VERSION 5.8 ;
BUSBITCHARS "[]" ;
DIVIDERCHAR "/" ;
UNITS
    DATABASE MICRONS 1000 ;
END UNITS

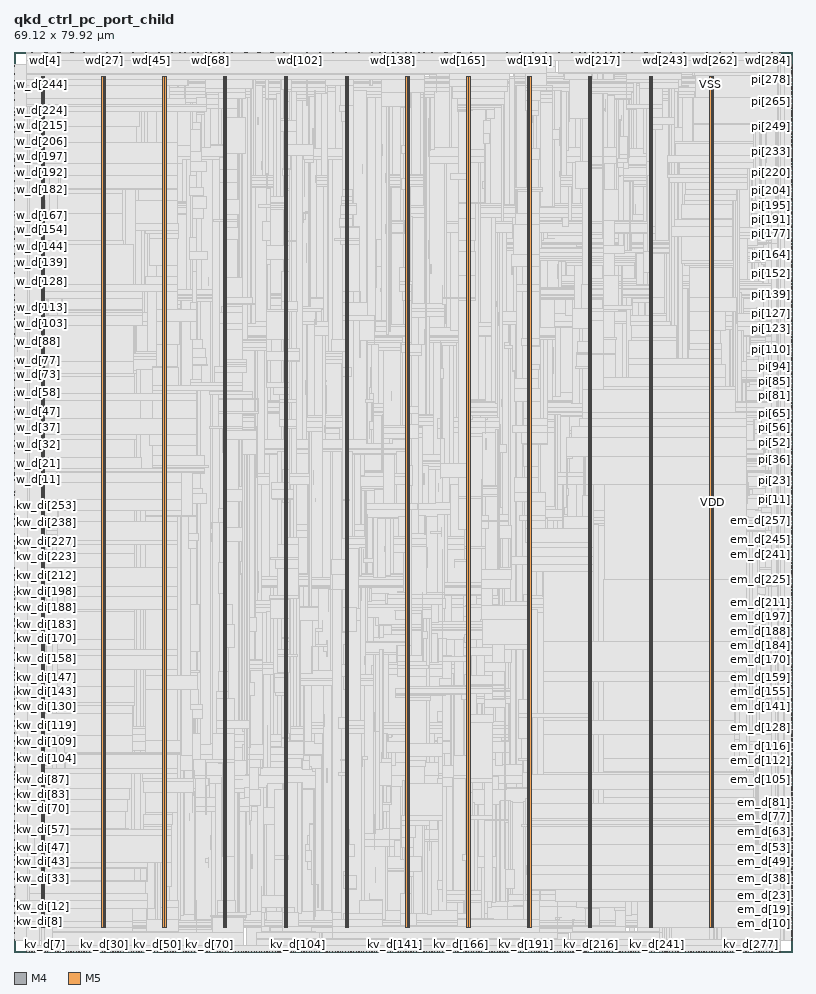
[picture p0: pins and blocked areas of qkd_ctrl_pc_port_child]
MACRO qkd_ctrl_pc_port_child
  FOREIGN qkd_ctrl_pc_port_child 0 0 ;
  CLASS BLOCK ;
  SIZE 69.12 BY 79.92 ;
  PIN col_sr_e
    DIRECTION INPUT ;
    USE SIGNAL ;
    PORT
      LAYER M4 ;
        RECT  0 1.056 0.084 1.08 ;
    END
  END col_sr_e
  PIN col_v_e
    DIRECTION INPUT ;
    USE SIGNAL ;
    PORT
      LAYER M4 ;
        RECT  0 1.2 0.084 1.224 ;
    END
  END col_v_e
  PIN col_we_e
    DIRECTION INPUT ;
    USE SIGNAL ;
    PORT
      LAYER M4 ;
        RECT  0 1.344 0.084 1.368 ;
    END
  END col_we_e
  PIN em_d[0]
    DIRECTION OUTPUT ;
    USE SIGNAL ;
    PORT
      LAYER M4 ;
        RECT  69.036 1.056 69.12 1.08 ;
    END
  END em_d[0]
  PIN em_d[100]
    DIRECTION OUTPUT ;
    USE SIGNAL ;
    PORT
      LAYER M4 ;
        RECT  69.036 15.264 69.12 15.288 ;
    END
  END em_d[100]
  PIN em_d[101]
    DIRECTION OUTPUT ;
    USE SIGNAL ;
    PORT
      LAYER M4 ;
        RECT  69.036 15.408 69.12 15.432 ;
    END
  END em_d[101]
  PIN em_d[102]
    DIRECTION OUTPUT ;
    USE SIGNAL ;
    PORT
      LAYER M4 ;
        RECT  69.036 15.552 69.12 15.576 ;
    END
  END em_d[102]
  PIN em_d[103]
    DIRECTION OUTPUT ;
    USE SIGNAL ;
    PORT
      LAYER M4 ;
        RECT  69.036 15.696 69.12 15.72 ;
    END
  END em_d[103]
  PIN em_d[104]
    DIRECTION OUTPUT ;
    USE SIGNAL ;
    PORT
      LAYER M4 ;
        RECT  69.036 15.84 69.12 15.864 ;
    END
  END em_d[104]
  PIN em_d[105]
    DIRECTION OUTPUT ;
    USE SIGNAL ;
    PORT
      LAYER M4 ;
        RECT  69.036 15.984 69.12 16.008 ;
    END
  END em_d[105]
  PIN em_d[106]
    DIRECTION OUTPUT ;
    USE SIGNAL ;
    PORT
      LAYER M4 ;
        RECT  69.036 16.128 69.12 16.152 ;
    END
  END em_d[106]
  PIN em_d[107]
    DIRECTION OUTPUT ;
    USE SIGNAL ;
    PORT
      LAYER M4 ;
        RECT  69.036 16.272 69.12 16.296 ;
    END
  END em_d[107]
  PIN em_d[108]
    DIRECTION OUTPUT ;
    USE SIGNAL ;
    PORT
      LAYER M4 ;
        RECT  69.036 16.416 69.12 16.44 ;
    END
  END em_d[108]
  PIN em_d[109]
    DIRECTION OUTPUT ;
    USE SIGNAL ;
    PORT
      LAYER M4 ;
        RECT  69.036 16.56 69.12 16.584 ;
    END
  END em_d[109]
  PIN em_d[10]
    DIRECTION OUTPUT ;
    USE SIGNAL ;
    PORT
      LAYER M4 ;
        RECT  69.036 2.496 69.12 2.52 ;
    END
  END em_d[10]
  PIN em_d[110]
    DIRECTION OUTPUT ;
    USE SIGNAL ;
    PORT
      LAYER M4 ;
        RECT  69.036 16.704 69.12 16.728 ;
    END
  END em_d[110]
  PIN em_d[111]
    DIRECTION OUTPUT ;
    USE SIGNAL ;
    PORT
      LAYER M4 ;
        RECT  69.036 16.848 69.12 16.872 ;
    END
  END em_d[111]
  PIN em_d[112]
    DIRECTION OUTPUT ;
    USE SIGNAL ;
    PORT
      LAYER M4 ;
        RECT  69.036 16.992 69.12 17.016 ;
    END
  END em_d[112]
  PIN em_d[113]
    DIRECTION OUTPUT ;
    USE SIGNAL ;
    PORT
      LAYER M4 ;
        RECT  69.036 17.136 69.12 17.16 ;
    END
  END em_d[113]
  PIN em_d[114]
    DIRECTION OUTPUT ;
    USE SIGNAL ;
    PORT
      LAYER M4 ;
        RECT  69.036 17.28 69.12 17.304 ;
    END
  END em_d[114]
  PIN em_d[115]
    DIRECTION OUTPUT ;
    USE SIGNAL ;
    PORT
      LAYER M4 ;
        RECT  69.036 17.424 69.12 17.448 ;
    END
  END em_d[115]
  PIN em_d[116]
    DIRECTION OUTPUT ;
    USE SIGNAL ;
    PORT
      LAYER M4 ;
        RECT  69.036 17.568 69.12 17.592 ;
    END
  END em_d[116]
  PIN em_d[117]
    DIRECTION OUTPUT ;
    USE SIGNAL ;
    PORT
      LAYER M4 ;
        RECT  69.036 17.712 69.12 17.736 ;
    END
  END em_d[117]
  PIN em_d[118]
    DIRECTION OUTPUT ;
    USE SIGNAL ;
    PORT
      LAYER M4 ;
        RECT  69.036 17.856 69.12 17.88 ;
    END
  END em_d[118]
  PIN em_d[119]
    DIRECTION OUTPUT ;
    USE SIGNAL ;
    PORT
      LAYER M4 ;
        RECT  69.036 18 69.12 18.024 ;
    END
  END em_d[119]
  PIN em_d[11]
    DIRECTION OUTPUT ;
    USE SIGNAL ;
    PORT
      LAYER M4 ;
        RECT  69.036 2.64 69.12 2.664 ;
    END
  END em_d[11]
  PIN em_d[120]
    DIRECTION OUTPUT ;
    USE SIGNAL ;
    PORT
      LAYER M4 ;
        RECT  69.036 18.144 69.12 18.168 ;
    END
  END em_d[120]
  PIN em_d[121]
    DIRECTION OUTPUT ;
    USE SIGNAL ;
    PORT
      LAYER M4 ;
        RECT  69.036 18.288 69.12 18.312 ;
    END
  END em_d[121]
  PIN em_d[122]
    DIRECTION OUTPUT ;
    USE SIGNAL ;
    PORT
      LAYER M4 ;
        RECT  69.036 18.384 69.12 18.408 ;
    END
  END em_d[122]
  PIN em_d[123]
    DIRECTION OUTPUT ;
    USE SIGNAL ;
    PORT
      LAYER M4 ;
        RECT  69.036 18.528 69.12 18.552 ;
    END
  END em_d[123]
  PIN em_d[124]
    DIRECTION OUTPUT ;
    USE SIGNAL ;
    PORT
      LAYER M4 ;
        RECT  69.036 18.672 69.12 18.696 ;
    END
  END em_d[124]
  PIN em_d[125]
    DIRECTION OUTPUT ;
    USE SIGNAL ;
    PORT
      LAYER M4 ;
        RECT  69.036 18.816 69.12 18.84 ;
    END
  END em_d[125]
  PIN em_d[126]
    DIRECTION OUTPUT ;
    USE SIGNAL ;
    PORT
      LAYER M4 ;
        RECT  69.036 18.96 69.12 18.984 ;
    END
  END em_d[126]
  PIN em_d[127]
    DIRECTION OUTPUT ;
    USE SIGNAL ;
    PORT
      LAYER M4 ;
        RECT  69.036 19.104 69.12 19.128 ;
    END
  END em_d[127]
  PIN em_d[128]
    DIRECTION OUTPUT ;
    USE SIGNAL ;
    PORT
      LAYER M4 ;
        RECT  69.036 19.248 69.12 19.272 ;
    END
  END em_d[128]
  PIN em_d[129]
    DIRECTION OUTPUT ;
    USE SIGNAL ;
    PORT
      LAYER M4 ;
        RECT  69.036 19.392 69.12 19.416 ;
    END
  END em_d[129]
  PIN em_d[12]
    DIRECTION OUTPUT ;
    USE SIGNAL ;
    PORT
      LAYER M4 ;
        RECT  69.036 2.784 69.12 2.808 ;
    END
  END em_d[12]
  PIN em_d[130]
    DIRECTION OUTPUT ;
    USE SIGNAL ;
    PORT
      LAYER M4 ;
        RECT  69.036 19.536 69.12 19.56 ;
    END
  END em_d[130]
  PIN em_d[131]
    DIRECTION OUTPUT ;
    USE SIGNAL ;
    PORT
      LAYER M4 ;
        RECT  69.036 19.68 69.12 19.704 ;
    END
  END em_d[131]
  PIN em_d[132]
    DIRECTION OUTPUT ;
    USE SIGNAL ;
    PORT
      LAYER M4 ;
        RECT  69.036 19.824 69.12 19.848 ;
    END
  END em_d[132]
  PIN em_d[133]
    DIRECTION OUTPUT ;
    USE SIGNAL ;
    PORT
      LAYER M4 ;
        RECT  69.036 19.968 69.12 19.992 ;
    END
  END em_d[133]
  PIN em_d[134]
    DIRECTION OUTPUT ;
    USE SIGNAL ;
    PORT
      LAYER M4 ;
        RECT  69.036 20.112 69.12 20.136 ;
    END
  END em_d[134]
  PIN em_d[135]
    DIRECTION OUTPUT ;
    USE SIGNAL ;
    PORT
      LAYER M4 ;
        RECT  69.036 20.256 69.12 20.28 ;
    END
  END em_d[135]
  PIN em_d[136]
    DIRECTION OUTPUT ;
    USE SIGNAL ;
    PORT
      LAYER M4 ;
        RECT  69.036 20.4 69.12 20.424 ;
    END
  END em_d[136]
  PIN em_d[137]
    DIRECTION OUTPUT ;
    USE SIGNAL ;
    PORT
      LAYER M4 ;
        RECT  69.036 20.544 69.12 20.568 ;
    END
  END em_d[137]
  PIN em_d[138]
    DIRECTION OUTPUT ;
    USE SIGNAL ;
    PORT
      LAYER M4 ;
        RECT  69.036 20.688 69.12 20.712 ;
    END
  END em_d[138]
  PIN em_d[139]
    DIRECTION OUTPUT ;
    USE SIGNAL ;
    PORT
      LAYER M4 ;
        RECT  69.036 20.832 69.12 20.856 ;
    END
  END em_d[139]
  PIN em_d[13]
    DIRECTION OUTPUT ;
    USE SIGNAL ;
    PORT
      LAYER M4 ;
        RECT  69.036 2.928 69.12 2.952 ;
    END
  END em_d[13]
  PIN em_d[140]
    DIRECTION OUTPUT ;
    USE SIGNAL ;
    PORT
      LAYER M4 ;
        RECT  69.036 20.976 69.12 21 ;
    END
  END em_d[140]
  PIN em_d[141]
    DIRECTION OUTPUT ;
    USE SIGNAL ;
    PORT
      LAYER M4 ;
        RECT  69.036 21.12 69.12 21.144 ;
    END
  END em_d[141]
  PIN em_d[142]
    DIRECTION OUTPUT ;
    USE SIGNAL ;
    PORT
      LAYER M4 ;
        RECT  69.036 21.264 69.12 21.288 ;
    END
  END em_d[142]
  PIN em_d[143]
    DIRECTION OUTPUT ;
    USE SIGNAL ;
    PORT
      LAYER M4 ;
        RECT  69.036 21.408 69.12 21.432 ;
    END
  END em_d[143]
  PIN em_d[144]
    DIRECTION OUTPUT ;
    USE SIGNAL ;
    PORT
      LAYER M4 ;
        RECT  69.036 21.552 69.12 21.576 ;
    END
  END em_d[144]
  PIN em_d[145]
    DIRECTION OUTPUT ;
    USE SIGNAL ;
    PORT
      LAYER M4 ;
        RECT  69.036 21.696 69.12 21.72 ;
    END
  END em_d[145]
  PIN em_d[146]
    DIRECTION OUTPUT ;
    USE SIGNAL ;
    PORT
      LAYER M4 ;
        RECT  69.036 21.84 69.12 21.864 ;
    END
  END em_d[146]
  PIN em_d[147]
    DIRECTION OUTPUT ;
    USE SIGNAL ;
    PORT
      LAYER M4 ;
        RECT  69.036 21.984 69.12 22.008 ;
    END
  END em_d[147]
  PIN em_d[148]
    DIRECTION OUTPUT ;
    USE SIGNAL ;
    PORT
      LAYER M4 ;
        RECT  69.036 22.08 69.12 22.104 ;
    END
  END em_d[148]
  PIN em_d[149]
    DIRECTION OUTPUT ;
    USE SIGNAL ;
    PORT
      LAYER M4 ;
        RECT  69.036 22.224 69.12 22.248 ;
    END
  END em_d[149]
  PIN em_d[14]
    DIRECTION OUTPUT ;
    USE SIGNAL ;
    PORT
      LAYER M4 ;
        RECT  69.036 3.072 69.12 3.096 ;
    END
  END em_d[14]
  PIN em_d[150]
    DIRECTION OUTPUT ;
    USE SIGNAL ;
    PORT
      LAYER M4 ;
        RECT  69.036 22.368 69.12 22.392 ;
    END
  END em_d[150]
  PIN em_d[151]
    DIRECTION OUTPUT ;
    USE SIGNAL ;
    PORT
      LAYER M4 ;
        RECT  69.036 22.512 69.12 22.536 ;
    END
  END em_d[151]
  PIN em_d[152]
    DIRECTION OUTPUT ;
    USE SIGNAL ;
    PORT
      LAYER M4 ;
        RECT  69.036 22.656 69.12 22.68 ;
    END
  END em_d[152]
  PIN em_d[153]
    DIRECTION OUTPUT ;
    USE SIGNAL ;
    PORT
      LAYER M4 ;
        RECT  69.036 22.8 69.12 22.824 ;
    END
  END em_d[153]
  PIN em_d[154]
    DIRECTION OUTPUT ;
    USE SIGNAL ;
    PORT
      LAYER M4 ;
        RECT  69.036 22.944 69.12 22.968 ;
    END
  END em_d[154]
  PIN em_d[155]
    DIRECTION OUTPUT ;
    USE SIGNAL ;
    PORT
      LAYER M4 ;
        RECT  69.036 23.088 69.12 23.112 ;
    END
  END em_d[155]
  PIN em_d[156]
    DIRECTION OUTPUT ;
    USE SIGNAL ;
    PORT
      LAYER M4 ;
        RECT  69.036 23.232 69.12 23.256 ;
    END
  END em_d[156]
  PIN em_d[157]
    DIRECTION OUTPUT ;
    USE SIGNAL ;
    PORT
      LAYER M4 ;
        RECT  69.036 23.376 69.12 23.4 ;
    END
  END em_d[157]
  PIN em_d[158]
    DIRECTION OUTPUT ;
    USE SIGNAL ;
    PORT
      LAYER M4 ;
        RECT  69.036 23.52 69.12 23.544 ;
    END
  END em_d[158]
  PIN em_d[159]
    DIRECTION OUTPUT ;
    USE SIGNAL ;
    PORT
      LAYER M4 ;
        RECT  69.036 23.664 69.12 23.688 ;
    END
  END em_d[159]
  PIN em_d[15]
    DIRECTION OUTPUT ;
    USE SIGNAL ;
    PORT
      LAYER M4 ;
        RECT  69.036 3.216 69.12 3.24 ;
    END
  END em_d[15]
  PIN em_d[160]
    DIRECTION OUTPUT ;
    USE SIGNAL ;
    PORT
      LAYER M4 ;
        RECT  69.036 23.808 69.12 23.832 ;
    END
  END em_d[160]
  PIN em_d[161]
    DIRECTION OUTPUT ;
    USE SIGNAL ;
    PORT
      LAYER M4 ;
        RECT  69.036 23.952 69.12 23.976 ;
    END
  END em_d[161]
  PIN em_d[162]
    DIRECTION OUTPUT ;
    USE SIGNAL ;
    PORT
      LAYER M4 ;
        RECT  69.036 24.096 69.12 24.12 ;
    END
  END em_d[162]
  PIN em_d[163]
    DIRECTION OUTPUT ;
    USE SIGNAL ;
    PORT
      LAYER M4 ;
        RECT  69.036 24.24 69.12 24.264 ;
    END
  END em_d[163]
  PIN em_d[164]
    DIRECTION OUTPUT ;
    USE SIGNAL ;
    PORT
      LAYER M4 ;
        RECT  69.036 24.384 69.12 24.408 ;
    END
  END em_d[164]
  PIN em_d[165]
    DIRECTION OUTPUT ;
    USE SIGNAL ;
    PORT
      LAYER M4 ;
        RECT  69.036 24.528 69.12 24.552 ;
    END
  END em_d[165]
  PIN em_d[166]
    DIRECTION OUTPUT ;
    USE SIGNAL ;
    PORT
      LAYER M4 ;
        RECT  69.036 24.672 69.12 24.696 ;
    END
  END em_d[166]
  PIN em_d[167]
    DIRECTION OUTPUT ;
    USE SIGNAL ;
    PORT
      LAYER M4 ;
        RECT  69.036 24.816 69.12 24.84 ;
    END
  END em_d[167]
  PIN em_d[168]
    DIRECTION OUTPUT ;
    USE SIGNAL ;
    PORT
      LAYER M4 ;
        RECT  69.036 24.96 69.12 24.984 ;
    END
  END em_d[168]
  PIN em_d[169]
    DIRECTION OUTPUT ;
    USE SIGNAL ;
    PORT
      LAYER M4 ;
        RECT  69.036 25.104 69.12 25.128 ;
    END
  END em_d[169]
  PIN em_d[16]
    DIRECTION OUTPUT ;
    USE SIGNAL ;
    PORT
      LAYER M4 ;
        RECT  69.036 3.312 69.12 3.336 ;
    END
  END em_d[16]
  PIN em_d[170]
    DIRECTION OUTPUT ;
    USE SIGNAL ;
    PORT
      LAYER M4 ;
        RECT  69.036 25.248 69.12 25.272 ;
    END
  END em_d[170]
  PIN em_d[171]
    DIRECTION OUTPUT ;
    USE SIGNAL ;
    PORT
      LAYER M4 ;
        RECT  69.036 25.392 69.12 25.416 ;
    END
  END em_d[171]
  PIN em_d[172]
    DIRECTION OUTPUT ;
    USE SIGNAL ;
    PORT
      LAYER M4 ;
        RECT  69.036 25.536 69.12 25.56 ;
    END
  END em_d[172]
  PIN em_d[173]
    DIRECTION OUTPUT ;
    USE SIGNAL ;
    PORT
      LAYER M4 ;
        RECT  69.036 25.68 69.12 25.704 ;
    END
  END em_d[173]
  PIN em_d[174]
    DIRECTION OUTPUT ;
    USE SIGNAL ;
    PORT
      LAYER M4 ;
        RECT  69.036 25.824 69.12 25.848 ;
    END
  END em_d[174]
  PIN em_d[175]
    DIRECTION OUTPUT ;
    USE SIGNAL ;
    PORT
      LAYER M4 ;
        RECT  69.036 25.92 69.12 25.944 ;
    END
  END em_d[175]
  PIN em_d[176]
    DIRECTION OUTPUT ;
    USE SIGNAL ;
    PORT
      LAYER M4 ;
        RECT  69.036 26.064 69.12 26.088 ;
    END
  END em_d[176]
  PIN em_d[177]
    DIRECTION OUTPUT ;
    USE SIGNAL ;
    PORT
      LAYER M4 ;
        RECT  69.036 26.208 69.12 26.232 ;
    END
  END em_d[177]
  PIN em_d[178]
    DIRECTION OUTPUT ;
    USE SIGNAL ;
    PORT
      LAYER M4 ;
        RECT  69.036 26.352 69.12 26.376 ;
    END
  END em_d[178]
  PIN em_d[179]
    DIRECTION OUTPUT ;
    USE SIGNAL ;
    PORT
      LAYER M4 ;
        RECT  69.036 26.496 69.12 26.52 ;
    END
  END em_d[179]
  PIN em_d[17]
    DIRECTION OUTPUT ;
    USE SIGNAL ;
    PORT
      LAYER M4 ;
        RECT  69.036 3.456 69.12 3.48 ;
    END
  END em_d[17]
  PIN em_d[180]
    DIRECTION OUTPUT ;
    USE SIGNAL ;
    PORT
      LAYER M4 ;
        RECT  69.036 26.64 69.12 26.664 ;
    END
  END em_d[180]
  PIN em_d[181]
    DIRECTION OUTPUT ;
    USE SIGNAL ;
    PORT
      LAYER M4 ;
        RECT  69.036 26.784 69.12 26.808 ;
    END
  END em_d[181]
  PIN em_d[182]
    DIRECTION OUTPUT ;
    USE SIGNAL ;
    PORT
      LAYER M4 ;
        RECT  69.036 26.928 69.12 26.952 ;
    END
  END em_d[182]
  PIN em_d[183]
    DIRECTION OUTPUT ;
    USE SIGNAL ;
    PORT
      LAYER M4 ;
        RECT  69.036 27.072 69.12 27.096 ;
    END
  END em_d[183]
  PIN em_d[184]
    DIRECTION OUTPUT ;
    USE SIGNAL ;
    PORT
      LAYER M4 ;
        RECT  69.036 27.216 69.12 27.24 ;
    END
  END em_d[184]
  PIN em_d[185]
    DIRECTION OUTPUT ;
    USE SIGNAL ;
    PORT
      LAYER M4 ;
        RECT  69.036 27.36 69.12 27.384 ;
    END
  END em_d[185]
  PIN em_d[186]
    DIRECTION OUTPUT ;
    USE SIGNAL ;
    PORT
      LAYER M4 ;
        RECT  69.036 27.504 69.12 27.528 ;
    END
  END em_d[186]
  PIN em_d[187]
    DIRECTION OUTPUT ;
    USE SIGNAL ;
    PORT
      LAYER M4 ;
        RECT  69.036 27.648 69.12 27.672 ;
    END
  END em_d[187]
  PIN em_d[188]
    DIRECTION OUTPUT ;
    USE SIGNAL ;
    PORT
      LAYER M4 ;
        RECT  69.036 27.792 69.12 27.816 ;
    END
  END em_d[188]
  PIN em_d[189]
    DIRECTION OUTPUT ;
    USE SIGNAL ;
    PORT
      LAYER M4 ;
        RECT  69.036 27.936 69.12 27.96 ;
    END
  END em_d[189]
  PIN em_d[18]
    DIRECTION OUTPUT ;
    USE SIGNAL ;
    PORT
      LAYER M4 ;
        RECT  69.036 3.6 69.12 3.624 ;
    END
  END em_d[18]
  PIN em_d[190]
    DIRECTION OUTPUT ;
    USE SIGNAL ;
    PORT
      LAYER M4 ;
        RECT  69.036 28.08 69.12 28.104 ;
    END
  END em_d[190]
  PIN em_d[191]
    DIRECTION OUTPUT ;
    USE SIGNAL ;
    PORT
      LAYER M4 ;
        RECT  69.036 28.224 69.12 28.248 ;
    END
  END em_d[191]
  PIN em_d[192]
    DIRECTION OUTPUT ;
    USE SIGNAL ;
    PORT
      LAYER M4 ;
        RECT  69.036 28.368 69.12 28.392 ;
    END
  END em_d[192]
  PIN em_d[193]
    DIRECTION OUTPUT ;
    USE SIGNAL ;
    PORT
      LAYER M4 ;
        RECT  69.036 28.512 69.12 28.536 ;
    END
  END em_d[193]
  PIN em_d[194]
    DIRECTION OUTPUT ;
    USE SIGNAL ;
    PORT
      LAYER M4 ;
        RECT  69.036 28.656 69.12 28.68 ;
    END
  END em_d[194]
  PIN em_d[195]
    DIRECTION OUTPUT ;
    USE SIGNAL ;
    PORT
      LAYER M4 ;
        RECT  69.036 28.8 69.12 28.824 ;
    END
  END em_d[195]
  PIN em_d[196]
    DIRECTION OUTPUT ;
    USE SIGNAL ;
    PORT
      LAYER M4 ;
        RECT  69.036 28.944 69.12 28.968 ;
    END
  END em_d[196]
  PIN em_d[197]
    DIRECTION OUTPUT ;
    USE SIGNAL ;
    PORT
      LAYER M4 ;
        RECT  69.036 29.088 69.12 29.112 ;
    END
  END em_d[197]
  PIN em_d[198]
    DIRECTION OUTPUT ;
    USE SIGNAL ;
    PORT
      LAYER M4 ;
        RECT  69.036 29.232 69.12 29.256 ;
    END
  END em_d[198]
  PIN em_d[199]
    DIRECTION OUTPUT ;
    USE SIGNAL ;
    PORT
      LAYER M4 ;
        RECT  69.036 29.376 69.12 29.4 ;
    END
  END em_d[199]
  PIN em_d[19]
    DIRECTION OUTPUT ;
    USE SIGNAL ;
    PORT
      LAYER M4 ;
        RECT  69.036 3.744 69.12 3.768 ;
    END
  END em_d[19]
  PIN em_d[1]
    DIRECTION OUTPUT ;
    USE SIGNAL ;
    PORT
      LAYER M4 ;
        RECT  69.036 1.2 69.12 1.224 ;
    END
  END em_d[1]
  PIN em_d[200]
    DIRECTION OUTPUT ;
    USE SIGNAL ;
    PORT
      LAYER M4 ;
        RECT  69.036 29.52 69.12 29.544 ;
    END
  END em_d[200]
  PIN em_d[201]
    DIRECTION OUTPUT ;
    USE SIGNAL ;
    PORT
      LAYER M4 ;
        RECT  69.036 29.616 69.12 29.64 ;
    END
  END em_d[201]
  PIN em_d[202]
    DIRECTION OUTPUT ;
    USE SIGNAL ;
    PORT
      LAYER M4 ;
        RECT  69.036 29.76 69.12 29.784 ;
    END
  END em_d[202]
  PIN em_d[203]
    DIRECTION OUTPUT ;
    USE SIGNAL ;
    PORT
      LAYER M4 ;
        RECT  69.036 29.904 69.12 29.928 ;
    END
  END em_d[203]
  PIN em_d[204]
    DIRECTION OUTPUT ;
    USE SIGNAL ;
    PORT
      LAYER M4 ;
        RECT  69.036 30.048 69.12 30.072 ;
    END
  END em_d[204]
  PIN em_d[205]
    DIRECTION OUTPUT ;
    USE SIGNAL ;
    PORT
      LAYER M4 ;
        RECT  69.036 30.192 69.12 30.216 ;
    END
  END em_d[205]
  PIN em_d[206]
    DIRECTION OUTPUT ;
    USE SIGNAL ;
    PORT
      LAYER M4 ;
        RECT  69.036 30.336 69.12 30.36 ;
    END
  END em_d[206]
  PIN em_d[207]
    DIRECTION OUTPUT ;
    USE SIGNAL ;
    PORT
      LAYER M4 ;
        RECT  69.036 30.48 69.12 30.504 ;
    END
  END em_d[207]
  PIN em_d[208]
    DIRECTION OUTPUT ;
    USE SIGNAL ;
    PORT
      LAYER M4 ;
        RECT  69.036 30.624 69.12 30.648 ;
    END
  END em_d[208]
  PIN em_d[209]
    DIRECTION OUTPUT ;
    USE SIGNAL ;
    PORT
      LAYER M4 ;
        RECT  69.036 30.768 69.12 30.792 ;
    END
  END em_d[209]
  PIN em_d[20]
    DIRECTION OUTPUT ;
    USE SIGNAL ;
    PORT
      LAYER M4 ;
        RECT  69.036 3.888 69.12 3.912 ;
    END
  END em_d[20]
  PIN em_d[210]
    DIRECTION OUTPUT ;
    USE SIGNAL ;
    PORT
      LAYER M4 ;
        RECT  69.036 30.912 69.12 30.936 ;
    END
  END em_d[210]
  PIN em_d[211]
    DIRECTION OUTPUT ;
    USE SIGNAL ;
    PORT
      LAYER M4 ;
        RECT  69.036 31.056 69.12 31.08 ;
    END
  END em_d[211]
  PIN em_d[212]
    DIRECTION OUTPUT ;
    USE SIGNAL ;
    PORT
      LAYER M4 ;
        RECT  69.036 31.2 69.12 31.224 ;
    END
  END em_d[212]
  PIN em_d[213]
    DIRECTION OUTPUT ;
    USE SIGNAL ;
    PORT
      LAYER M4 ;
        RECT  69.036 31.344 69.12 31.368 ;
    END
  END em_d[213]
  PIN em_d[214]
    DIRECTION OUTPUT ;
    USE SIGNAL ;
    PORT
      LAYER M4 ;
        RECT  69.036 31.488 69.12 31.512 ;
    END
  END em_d[214]
  PIN em_d[215]
    DIRECTION OUTPUT ;
    USE SIGNAL ;
    PORT
      LAYER M4 ;
        RECT  69.036 31.632 69.12 31.656 ;
    END
  END em_d[215]
  PIN em_d[216]
    DIRECTION OUTPUT ;
    USE SIGNAL ;
    PORT
      LAYER M4 ;
        RECT  69.036 31.776 69.12 31.8 ;
    END
  END em_d[216]
  PIN em_d[217]
    DIRECTION OUTPUT ;
    USE SIGNAL ;
    PORT
      LAYER M4 ;
        RECT  69.036 31.92 69.12 31.944 ;
    END
  END em_d[217]
  PIN em_d[218]
    DIRECTION OUTPUT ;
    USE SIGNAL ;
    PORT
      LAYER M4 ;
        RECT  69.036 32.064 69.12 32.088 ;
    END
  END em_d[218]
  PIN em_d[219]
    DIRECTION OUTPUT ;
    USE SIGNAL ;
    PORT
      LAYER M4 ;
        RECT  69.036 32.208 69.12 32.232 ;
    END
  END em_d[219]
  PIN em_d[21]
    DIRECTION OUTPUT ;
    USE SIGNAL ;
    PORT
      LAYER M4 ;
        RECT  69.036 4.032 69.12 4.056 ;
    END
  END em_d[21]
  PIN em_d[220]
    DIRECTION OUTPUT ;
    USE SIGNAL ;
    PORT
      LAYER M4 ;
        RECT  69.036 32.352 69.12 32.376 ;
    END
  END em_d[220]
  PIN em_d[221]
    DIRECTION OUTPUT ;
    USE SIGNAL ;
    PORT
      LAYER M4 ;
        RECT  69.036 32.496 69.12 32.52 ;
    END
  END em_d[221]
  PIN em_d[222]
    DIRECTION OUTPUT ;
    USE SIGNAL ;
    PORT
      LAYER M4 ;
        RECT  69.036 32.64 69.12 32.664 ;
    END
  END em_d[222]
  PIN em_d[223]
    DIRECTION OUTPUT ;
    USE SIGNAL ;
    PORT
      LAYER M4 ;
        RECT  69.036 32.784 69.12 32.808 ;
    END
  END em_d[223]
  PIN em_d[224]
    DIRECTION OUTPUT ;
    USE SIGNAL ;
    PORT
      LAYER M4 ;
        RECT  69.036 32.928 69.12 32.952 ;
    END
  END em_d[224]
  PIN em_d[225]
    DIRECTION OUTPUT ;
    USE SIGNAL ;
    PORT
      LAYER M4 ;
        RECT  69.036 33.072 69.12 33.096 ;
    END
  END em_d[225]
  PIN em_d[226]
    DIRECTION OUTPUT ;
    USE SIGNAL ;
    PORT
      LAYER M4 ;
        RECT  69.036 33.216 69.12 33.24 ;
    END
  END em_d[226]
  PIN em_d[227]
    DIRECTION OUTPUT ;
    USE SIGNAL ;
    PORT
      LAYER M4 ;
        RECT  69.036 33.36 69.12 33.384 ;
    END
  END em_d[227]
  PIN em_d[228]
    DIRECTION OUTPUT ;
    USE SIGNAL ;
    PORT
      LAYER M4 ;
        RECT  69.036 33.456 69.12 33.48 ;
    END
  END em_d[228]
  PIN em_d[229]
    DIRECTION OUTPUT ;
    USE SIGNAL ;
    PORT
      LAYER M4 ;
        RECT  69.036 33.6 69.12 33.624 ;
    END
  END em_d[229]
  PIN em_d[22]
    DIRECTION OUTPUT ;
    USE SIGNAL ;
    PORT
      LAYER M4 ;
        RECT  69.036 4.176 69.12 4.2 ;
    END
  END em_d[22]
  PIN em_d[230]
    DIRECTION OUTPUT ;
    USE SIGNAL ;
    PORT
      LAYER M4 ;
        RECT  69.036 33.744 69.12 33.768 ;
    END
  END em_d[230]
  PIN em_d[231]
    DIRECTION OUTPUT ;
    USE SIGNAL ;
    PORT
      LAYER M4 ;
        RECT  69.036 33.888 69.12 33.912 ;
    END
  END em_d[231]
  PIN em_d[232]
    DIRECTION OUTPUT ;
    USE SIGNAL ;
    PORT
      LAYER M4 ;
        RECT  69.036 34.032 69.12 34.056 ;
    END
  END em_d[232]
  PIN em_d[233]
    DIRECTION OUTPUT ;
    USE SIGNAL ;
    PORT
      LAYER M4 ;
        RECT  69.036 34.176 69.12 34.2 ;
    END
  END em_d[233]
  PIN em_d[234]
    DIRECTION OUTPUT ;
    USE SIGNAL ;
    PORT
      LAYER M4 ;
        RECT  69.036 34.32 69.12 34.344 ;
    END
  END em_d[234]
  PIN em_d[235]
    DIRECTION OUTPUT ;
    USE SIGNAL ;
    PORT
      LAYER M4 ;
        RECT  69.036 34.464 69.12 34.488 ;
    END
  END em_d[235]
  PIN em_d[236]
    DIRECTION OUTPUT ;
    USE SIGNAL ;
    PORT
      LAYER M4 ;
        RECT  69.036 34.608 69.12 34.632 ;
    END
  END em_d[236]
  PIN em_d[237]
    DIRECTION OUTPUT ;
    USE SIGNAL ;
    PORT
      LAYER M4 ;
        RECT  69.036 34.752 69.12 34.776 ;
    END
  END em_d[237]
  PIN em_d[238]
    DIRECTION OUTPUT ;
    USE SIGNAL ;
    PORT
      LAYER M4 ;
        RECT  69.036 34.896 69.12 34.92 ;
    END
  END em_d[238]
  PIN em_d[239]
    DIRECTION OUTPUT ;
    USE SIGNAL ;
    PORT
      LAYER M4 ;
        RECT  69.036 35.04 69.12 35.064 ;
    END
  END em_d[239]
  PIN em_d[23]
    DIRECTION OUTPUT ;
    USE SIGNAL ;
    PORT
      LAYER M4 ;
        RECT  69.036 4.32 69.12 4.344 ;
    END
  END em_d[23]
  PIN em_d[240]
    DIRECTION OUTPUT ;
    USE SIGNAL ;
    PORT
      LAYER M4 ;
        RECT  69.036 35.184 69.12 35.208 ;
    END
  END em_d[240]
  PIN em_d[241]
    DIRECTION OUTPUT ;
    USE SIGNAL ;
    PORT
      LAYER M4 ;
        RECT  69.036 35.328 69.12 35.352 ;
    END
  END em_d[241]
  PIN em_d[242]
    DIRECTION OUTPUT ;
    USE SIGNAL ;
    PORT
      LAYER M4 ;
        RECT  69.036 35.472 69.12 35.496 ;
    END
  END em_d[242]
  PIN em_d[243]
    DIRECTION OUTPUT ;
    USE SIGNAL ;
    PORT
      LAYER M4 ;
        RECT  69.036 35.616 69.12 35.64 ;
    END
  END em_d[243]
  PIN em_d[244]
    DIRECTION OUTPUT ;
    USE SIGNAL ;
    PORT
      LAYER M4 ;
        RECT  69.036 35.76 69.12 35.784 ;
    END
  END em_d[244]
  PIN em_d[245]
    DIRECTION OUTPUT ;
    USE SIGNAL ;
    PORT
      LAYER M4 ;
        RECT  69.036 35.904 69.12 35.928 ;
    END
  END em_d[245]
  PIN em_d[246]
    DIRECTION OUTPUT ;
    USE SIGNAL ;
    PORT
      LAYER M4 ;
        RECT  69.036 36.048 69.12 36.072 ;
    END
  END em_d[246]
  PIN em_d[247]
    DIRECTION OUTPUT ;
    USE SIGNAL ;
    PORT
      LAYER M4 ;
        RECT  69.036 36.192 69.12 36.216 ;
    END
  END em_d[247]
  PIN em_d[248]
    DIRECTION OUTPUT ;
    USE SIGNAL ;
    PORT
      LAYER M4 ;
        RECT  69.036 36.336 69.12 36.36 ;
    END
  END em_d[248]
  PIN em_d[249]
    DIRECTION OUTPUT ;
    USE SIGNAL ;
    PORT
      LAYER M4 ;
        RECT  69.036 36.48 69.12 36.504 ;
    END
  END em_d[249]
  PIN em_d[24]
    DIRECTION OUTPUT ;
    USE SIGNAL ;
    PORT
      LAYER M4 ;
        RECT  69.036 4.464 69.12 4.488 ;
    END
  END em_d[24]
  PIN em_d[250]
    DIRECTION OUTPUT ;
    USE SIGNAL ;
    PORT
      LAYER M4 ;
        RECT  69.036 36.624 69.12 36.648 ;
    END
  END em_d[250]
  PIN em_d[251]
    DIRECTION OUTPUT ;
    USE SIGNAL ;
    PORT
      LAYER M4 ;
        RECT  69.036 36.768 69.12 36.792 ;
    END
  END em_d[251]
  PIN em_d[252]
    DIRECTION OUTPUT ;
    USE SIGNAL ;
    PORT
      LAYER M4 ;
        RECT  69.036 36.912 69.12 36.936 ;
    END
  END em_d[252]
  PIN em_d[253]
    DIRECTION OUTPUT ;
    USE SIGNAL ;
    PORT
      LAYER M4 ;
        RECT  69.036 37.056 69.12 37.08 ;
    END
  END em_d[253]
  PIN em_d[254]
    DIRECTION OUTPUT ;
    USE SIGNAL ;
    PORT
      LAYER M4 ;
        RECT  69.036 37.152 69.12 37.176 ;
    END
  END em_d[254]
  PIN em_d[255]
    DIRECTION OUTPUT ;
    USE SIGNAL ;
    PORT
      LAYER M4 ;
        RECT  69.036 37.296 69.12 37.32 ;
    END
  END em_d[255]
  PIN em_d[256]
    DIRECTION OUTPUT ;
    USE SIGNAL ;
    PORT
      LAYER M4 ;
        RECT  69.036 37.44 69.12 37.464 ;
    END
  END em_d[256]
  PIN em_d[257]
    DIRECTION OUTPUT ;
    USE SIGNAL ;
    PORT
      LAYER M4 ;
        RECT  69.036 37.584 69.12 37.608 ;
    END
  END em_d[257]
  PIN em_d[25]
    DIRECTION OUTPUT ;
    USE SIGNAL ;
    PORT
      LAYER M4 ;
        RECT  69.036 4.608 69.12 4.632 ;
    END
  END em_d[25]
  PIN em_d[26]
    DIRECTION OUTPUT ;
    USE SIGNAL ;
    PORT
      LAYER M4 ;
        RECT  69.036 4.752 69.12 4.776 ;
    END
  END em_d[26]
  PIN em_d[27]
    DIRECTION OUTPUT ;
    USE SIGNAL ;
    PORT
      LAYER M4 ;
        RECT  69.036 4.896 69.12 4.92 ;
    END
  END em_d[27]
  PIN em_d[28]
    DIRECTION OUTPUT ;
    USE SIGNAL ;
    PORT
      LAYER M4 ;
        RECT  69.036 5.04 69.12 5.064 ;
    END
  END em_d[28]
  PIN em_d[29]
    DIRECTION OUTPUT ;
    USE SIGNAL ;
    PORT
      LAYER M4 ;
        RECT  69.036 5.184 69.12 5.208 ;
    END
  END em_d[29]
  PIN em_d[2]
    DIRECTION OUTPUT ;
    USE SIGNAL ;
    PORT
      LAYER M4 ;
        RECT  69.036 1.344 69.12 1.368 ;
    END
  END em_d[2]
  PIN em_d[30]
    DIRECTION OUTPUT ;
    USE SIGNAL ;
    PORT
      LAYER M4 ;
        RECT  69.036 5.328 69.12 5.352 ;
    END
  END em_d[30]
  PIN em_d[31]
    DIRECTION OUTPUT ;
    USE SIGNAL ;
    PORT
      LAYER M4 ;
        RECT  69.036 5.472 69.12 5.496 ;
    END
  END em_d[31]
  PIN em_d[32]
    DIRECTION OUTPUT ;
    USE SIGNAL ;
    PORT
      LAYER M4 ;
        RECT  69.036 5.616 69.12 5.64 ;
    END
  END em_d[32]
  PIN em_d[33]
    DIRECTION OUTPUT ;
    USE SIGNAL ;
    PORT
      LAYER M4 ;
        RECT  69.036 5.76 69.12 5.784 ;
    END
  END em_d[33]
  PIN em_d[34]
    DIRECTION OUTPUT ;
    USE SIGNAL ;
    PORT
      LAYER M4 ;
        RECT  69.036 5.904 69.12 5.928 ;
    END
  END em_d[34]
  PIN em_d[35]
    DIRECTION OUTPUT ;
    USE SIGNAL ;
    PORT
      LAYER M4 ;
        RECT  69.036 6.048 69.12 6.072 ;
    END
  END em_d[35]
  PIN em_d[36]
    DIRECTION OUTPUT ;
    USE SIGNAL ;
    PORT
      LAYER M4 ;
        RECT  69.036 6.192 69.12 6.216 ;
    END
  END em_d[36]
  PIN em_d[37]
    DIRECTION OUTPUT ;
    USE SIGNAL ;
    PORT
      LAYER M4 ;
        RECT  69.036 6.336 69.12 6.36 ;
    END
  END em_d[37]
  PIN em_d[38]
    DIRECTION OUTPUT ;
    USE SIGNAL ;
    PORT
      LAYER M4 ;
        RECT  69.036 6.48 69.12 6.504 ;
    END
  END em_d[38]
  PIN em_d[39]
    DIRECTION OUTPUT ;
    USE SIGNAL ;
    PORT
      LAYER M4 ;
        RECT  69.036 6.624 69.12 6.648 ;
    END
  END em_d[39]
  PIN em_d[3]
    DIRECTION OUTPUT ;
    USE SIGNAL ;
    PORT
      LAYER M4 ;
        RECT  69.036 1.488 69.12 1.512 ;
    END
  END em_d[3]
  PIN em_d[40]
    DIRECTION OUTPUT ;
    USE SIGNAL ;
    PORT
      LAYER M4 ;
        RECT  69.036 6.768 69.12 6.792 ;
    END
  END em_d[40]
  PIN em_d[41]
    DIRECTION OUTPUT ;
    USE SIGNAL ;
    PORT
      LAYER M4 ;
        RECT  69.036 6.912 69.12 6.936 ;
    END
  END em_d[41]
  PIN em_d[42]
    DIRECTION OUTPUT ;
    USE SIGNAL ;
    PORT
      LAYER M4 ;
        RECT  69.036 7.008 69.12 7.032 ;
    END
  END em_d[42]
  PIN em_d[43]
    DIRECTION OUTPUT ;
    USE SIGNAL ;
    PORT
      LAYER M4 ;
        RECT  69.036 7.152 69.12 7.176 ;
    END
  END em_d[43]
  PIN em_d[44]
    DIRECTION OUTPUT ;
    USE SIGNAL ;
    PORT
      LAYER M4 ;
        RECT  69.036 7.296 69.12 7.32 ;
    END
  END em_d[44]
  PIN em_d[45]
    DIRECTION OUTPUT ;
    USE SIGNAL ;
    PORT
      LAYER M4 ;
        RECT  69.036 7.44 69.12 7.464 ;
    END
  END em_d[45]
  PIN em_d[46]
    DIRECTION OUTPUT ;
    USE SIGNAL ;
    PORT
      LAYER M4 ;
        RECT  69.036 7.584 69.12 7.608 ;
    END
  END em_d[46]
  PIN em_d[47]
    DIRECTION OUTPUT ;
    USE SIGNAL ;
    PORT
      LAYER M4 ;
        RECT  69.036 7.728 69.12 7.752 ;
    END
  END em_d[47]
  PIN em_d[48]
    DIRECTION OUTPUT ;
    USE SIGNAL ;
    PORT
      LAYER M4 ;
        RECT  69.036 7.872 69.12 7.896 ;
    END
  END em_d[48]
  PIN em_d[49]
    DIRECTION OUTPUT ;
    USE SIGNAL ;
    PORT
      LAYER M4 ;
        RECT  69.036 8.016 69.12 8.04 ;
    END
  END em_d[49]
  PIN em_d[4]
    DIRECTION OUTPUT ;
    USE SIGNAL ;
    PORT
      LAYER M4 ;
        RECT  69.036 1.632 69.12 1.656 ;
    END
  END em_d[4]
  PIN em_d[50]
    DIRECTION OUTPUT ;
    USE SIGNAL ;
    PORT
      LAYER M4 ;
        RECT  69.036 8.16 69.12 8.184 ;
    END
  END em_d[50]
  PIN em_d[51]
    DIRECTION OUTPUT ;
    USE SIGNAL ;
    PORT
      LAYER M4 ;
        RECT  69.036 8.304 69.12 8.328 ;
    END
  END em_d[51]
  PIN em_d[52]
    DIRECTION OUTPUT ;
    USE SIGNAL ;
    PORT
      LAYER M4 ;
        RECT  69.036 8.448 69.12 8.472 ;
    END
  END em_d[52]
  PIN em_d[53]
    DIRECTION OUTPUT ;
    USE SIGNAL ;
    PORT
      LAYER M4 ;
        RECT  69.036 8.592 69.12 8.616 ;
    END
  END em_d[53]
  PIN em_d[54]
    DIRECTION OUTPUT ;
    USE SIGNAL ;
    PORT
      LAYER M4 ;
        RECT  69.036 8.736 69.12 8.76 ;
    END
  END em_d[54]
  PIN em_d[55]
    DIRECTION OUTPUT ;
    USE SIGNAL ;
    PORT
      LAYER M4 ;
        RECT  69.036 8.88 69.12 8.904 ;
    END
  END em_d[55]
  PIN em_d[56]
    DIRECTION OUTPUT ;
    USE SIGNAL ;
    PORT
      LAYER M4 ;
        RECT  69.036 9.024 69.12 9.048 ;
    END
  END em_d[56]
  PIN em_d[57]
    DIRECTION OUTPUT ;
    USE SIGNAL ;
    PORT
      LAYER M4 ;
        RECT  69.036 9.168 69.12 9.192 ;
    END
  END em_d[57]
  PIN em_d[58]
    DIRECTION OUTPUT ;
    USE SIGNAL ;
    PORT
      LAYER M4 ;
        RECT  69.036 9.312 69.12 9.336 ;
    END
  END em_d[58]
  PIN em_d[59]
    DIRECTION OUTPUT ;
    USE SIGNAL ;
    PORT
      LAYER M4 ;
        RECT  69.036 9.456 69.12 9.48 ;
    END
  END em_d[59]
  PIN em_d[5]
    DIRECTION OUTPUT ;
    USE SIGNAL ;
    PORT
      LAYER M4 ;
        RECT  69.036 1.776 69.12 1.8 ;
    END
  END em_d[5]
  PIN em_d[60]
    DIRECTION OUTPUT ;
    USE SIGNAL ;
    PORT
      LAYER M4 ;
        RECT  69.036 9.6 69.12 9.624 ;
    END
  END em_d[60]
  PIN em_d[61]
    DIRECTION OUTPUT ;
    USE SIGNAL ;
    PORT
      LAYER M4 ;
        RECT  69.036 9.744 69.12 9.768 ;
    END
  END em_d[61]
  PIN em_d[62]
    DIRECTION OUTPUT ;
    USE SIGNAL ;
    PORT
      LAYER M4 ;
        RECT  69.036 9.888 69.12 9.912 ;
    END
  END em_d[62]
  PIN em_d[63]
    DIRECTION OUTPUT ;
    USE SIGNAL ;
    PORT
      LAYER M4 ;
        RECT  69.036 10.032 69.12 10.056 ;
    END
  END em_d[63]
  PIN em_d[64]
    DIRECTION OUTPUT ;
    USE SIGNAL ;
    PORT
      LAYER M4 ;
        RECT  69.036 10.176 69.12 10.2 ;
    END
  END em_d[64]
  PIN em_d[65]
    DIRECTION OUTPUT ;
    USE SIGNAL ;
    PORT
      LAYER M4 ;
        RECT  69.036 10.32 69.12 10.344 ;
    END
  END em_d[65]
  PIN em_d[66]
    DIRECTION OUTPUT ;
    USE SIGNAL ;
    PORT
      LAYER M4 ;
        RECT  69.036 10.464 69.12 10.488 ;
    END
  END em_d[66]
  PIN em_d[67]
    DIRECTION OUTPUT ;
    USE SIGNAL ;
    PORT
      LAYER M4 ;
        RECT  69.036 10.608 69.12 10.632 ;
    END
  END em_d[67]
  PIN em_d[68]
    DIRECTION OUTPUT ;
    USE SIGNAL ;
    PORT
      LAYER M4 ;
        RECT  69.036 10.752 69.12 10.776 ;
    END
  END em_d[68]
  PIN em_d[69]
    DIRECTION OUTPUT ;
    USE SIGNAL ;
    PORT
      LAYER M4 ;
        RECT  69.036 10.848 69.12 10.872 ;
    END
  END em_d[69]
  PIN em_d[6]
    DIRECTION OUTPUT ;
    USE SIGNAL ;
    PORT
      LAYER M4 ;
        RECT  69.036 1.92 69.12 1.944 ;
    END
  END em_d[6]
  PIN em_d[70]
    DIRECTION OUTPUT ;
    USE SIGNAL ;
    PORT
      LAYER M4 ;
        RECT  69.036 10.992 69.12 11.016 ;
    END
  END em_d[70]
  PIN em_d[71]
    DIRECTION OUTPUT ;
    USE SIGNAL ;
    PORT
      LAYER M4 ;
        RECT  69.036 11.136 69.12 11.16 ;
    END
  END em_d[71]
  PIN em_d[72]
    DIRECTION OUTPUT ;
    USE SIGNAL ;
    PORT
      LAYER M4 ;
        RECT  69.036 11.28 69.12 11.304 ;
    END
  END em_d[72]
  PIN em_d[73]
    DIRECTION OUTPUT ;
    USE SIGNAL ;
    PORT
      LAYER M4 ;
        RECT  69.036 11.424 69.12 11.448 ;
    END
  END em_d[73]
  PIN em_d[74]
    DIRECTION OUTPUT ;
    USE SIGNAL ;
    PORT
      LAYER M4 ;
        RECT  69.036 11.568 69.12 11.592 ;
    END
  END em_d[74]
  PIN em_d[75]
    DIRECTION OUTPUT ;
    USE SIGNAL ;
    PORT
      LAYER M4 ;
        RECT  69.036 11.712 69.12 11.736 ;
    END
  END em_d[75]
  PIN em_d[76]
    DIRECTION OUTPUT ;
    USE SIGNAL ;
    PORT
      LAYER M4 ;
        RECT  69.036 11.856 69.12 11.88 ;
    END
  END em_d[76]
  PIN em_d[77]
    DIRECTION OUTPUT ;
    USE SIGNAL ;
    PORT
      LAYER M4 ;
        RECT  69.036 12 69.12 12.024 ;
    END
  END em_d[77]
  PIN em_d[78]
    DIRECTION OUTPUT ;
    USE SIGNAL ;
    PORT
      LAYER M4 ;
        RECT  69.036 12.144 69.12 12.168 ;
    END
  END em_d[78]
  PIN em_d[79]
    DIRECTION OUTPUT ;
    USE SIGNAL ;
    PORT
      LAYER M4 ;
        RECT  69.036 12.288 69.12 12.312 ;
    END
  END em_d[79]
  PIN em_d[7]
    DIRECTION OUTPUT ;
    USE SIGNAL ;
    PORT
      LAYER M4 ;
        RECT  69.036 2.064 69.12 2.088 ;
    END
  END em_d[7]
  PIN em_d[80]
    DIRECTION OUTPUT ;
    USE SIGNAL ;
    PORT
      LAYER M4 ;
        RECT  69.036 12.432 69.12 12.456 ;
    END
  END em_d[80]
  PIN em_d[81]
    DIRECTION OUTPUT ;
    USE SIGNAL ;
    PORT
      LAYER M4 ;
        RECT  69.036 12.576 69.12 12.6 ;
    END
  END em_d[81]
  PIN em_d[82]
    DIRECTION OUTPUT ;
    USE SIGNAL ;
    PORT
      LAYER M4 ;
        RECT  69.036 12.72 69.12 12.744 ;
    END
  END em_d[82]
  PIN em_d[83]
    DIRECTION OUTPUT ;
    USE SIGNAL ;
    PORT
      LAYER M4 ;
        RECT  69.036 12.864 69.12 12.888 ;
    END
  END em_d[83]
  PIN em_d[84]
    DIRECTION OUTPUT ;
    USE SIGNAL ;
    PORT
      LAYER M4 ;
        RECT  69.036 13.008 69.12 13.032 ;
    END
  END em_d[84]
  PIN em_d[85]
    DIRECTION OUTPUT ;
    USE SIGNAL ;
    PORT
      LAYER M4 ;
        RECT  69.036 13.152 69.12 13.176 ;
    END
  END em_d[85]
  PIN em_d[86]
    DIRECTION OUTPUT ;
    USE SIGNAL ;
    PORT
      LAYER M4 ;
        RECT  69.036 13.296 69.12 13.32 ;
    END
  END em_d[86]
  PIN em_d[87]
    DIRECTION OUTPUT ;
    USE SIGNAL ;
    PORT
      LAYER M4 ;
        RECT  69.036 13.44 69.12 13.464 ;
    END
  END em_d[87]
  PIN em_d[88]
    DIRECTION OUTPUT ;
    USE SIGNAL ;
    PORT
      LAYER M4 ;
        RECT  69.036 13.584 69.12 13.608 ;
    END
  END em_d[88]
  PIN em_d[89]
    DIRECTION OUTPUT ;
    USE SIGNAL ;
    PORT
      LAYER M4 ;
        RECT  69.036 13.728 69.12 13.752 ;
    END
  END em_d[89]
  PIN em_d[8]
    DIRECTION OUTPUT ;
    USE SIGNAL ;
    PORT
      LAYER M4 ;
        RECT  69.036 2.208 69.12 2.232 ;
    END
  END em_d[8]
  PIN em_d[90]
    DIRECTION OUTPUT ;
    USE SIGNAL ;
    PORT
      LAYER M4 ;
        RECT  69.036 13.872 69.12 13.896 ;
    END
  END em_d[90]
  PIN em_d[91]
    DIRECTION OUTPUT ;
    USE SIGNAL ;
    PORT
      LAYER M4 ;
        RECT  69.036 14.016 69.12 14.04 ;
    END
  END em_d[91]
  PIN em_d[92]
    DIRECTION OUTPUT ;
    USE SIGNAL ;
    PORT
      LAYER M4 ;
        RECT  69.036 14.16 69.12 14.184 ;
    END
  END em_d[92]
  PIN em_d[93]
    DIRECTION OUTPUT ;
    USE SIGNAL ;
    PORT
      LAYER M4 ;
        RECT  69.036 14.304 69.12 14.328 ;
    END
  END em_d[93]
  PIN em_d[94]
    DIRECTION OUTPUT ;
    USE SIGNAL ;
    PORT
      LAYER M4 ;
        RECT  69.036 14.448 69.12 14.472 ;
    END
  END em_d[94]
  PIN em_d[95]
    DIRECTION OUTPUT ;
    USE SIGNAL ;
    PORT
      LAYER M4 ;
        RECT  69.036 14.544 69.12 14.568 ;
    END
  END em_d[95]
  PIN em_d[96]
    DIRECTION OUTPUT ;
    USE SIGNAL ;
    PORT
      LAYER M4 ;
        RECT  69.036 14.688 69.12 14.712 ;
    END
  END em_d[96]
  PIN em_d[97]
    DIRECTION OUTPUT ;
    USE SIGNAL ;
    PORT
      LAYER M4 ;
        RECT  69.036 14.832 69.12 14.856 ;
    END
  END em_d[97]
  PIN em_d[98]
    DIRECTION OUTPUT ;
    USE SIGNAL ;
    PORT
      LAYER M4 ;
        RECT  69.036 14.976 69.12 15 ;
    END
  END em_d[98]
  PIN em_d[99]
    DIRECTION OUTPUT ;
    USE SIGNAL ;
    PORT
      LAYER M4 ;
        RECT  69.036 15.12 69.12 15.144 ;
    END
  END em_d[99]
  PIN em_d[9]
    DIRECTION OUTPUT ;
    USE SIGNAL ;
    PORT
      LAYER M4 ;
        RECT  69.036 2.352 69.12 2.376 ;
    END
  END em_d[9]
  PIN em_v
    DIRECTION OUTPUT ;
    USE SIGNAL ;
    PORT
      LAYER M4 ;
        RECT  69.036 37.728 69.12 37.752 ;
    END
  END em_v
  PIN fault
    DIRECTION OUTPUT ;
    USE SIGNAL ;
    PORT
      LAYER M5 ;
        RECT  1.104 79.836 1.128 79.92 ;
    END
  END fault
  PIN hclk
    DIRECTION INPUT ;
    USE SIGNAL ;
    PORT
      LAYER M5 ;
        RECT  1.344 79.836 1.368 79.92 ;
    END
  END hclk
  PIN hrst
    DIRECTION INPUT ;
    USE SIGNAL ;
    PORT
      LAYER M5 ;
        RECT  1.584 79.836 1.608 79.92 ;
    END
  END hrst
  PIN kv_d[0]
    DIRECTION OUTPUT ;
    USE SIGNAL ;
    PORT
      LAYER M5 ;
        RECT  1.104 0 1.128 0.084 ;
    END
  END kv_d[0]
  PIN kv_d[100]
    DIRECTION OUTPUT ;
    USE SIGNAL ;
    PORT
      LAYER M5 ;
        RECT  24.336 0 24.36 0.084 ;
    END
  END kv_d[100]
  PIN kv_d[101]
    DIRECTION OUTPUT ;
    USE SIGNAL ;
    PORT
      LAYER M5 ;
        RECT  24.576 0 24.6 0.084 ;
    END
  END kv_d[101]
  PIN kv_d[102]
    DIRECTION OUTPUT ;
    USE SIGNAL ;
    PORT
      LAYER M5 ;
        RECT  24.816 0 24.84 0.084 ;
    END
  END kv_d[102]
  PIN kv_d[103]
    DIRECTION OUTPUT ;
    USE SIGNAL ;
    PORT
      LAYER M5 ;
        RECT  25.008 0 25.032 0.084 ;
    END
  END kv_d[103]
  PIN kv_d[104]
    DIRECTION OUTPUT ;
    USE SIGNAL ;
    PORT
      LAYER M5 ;
        RECT  25.248 0 25.272 0.084 ;
    END
  END kv_d[104]
  PIN kv_d[105]
    DIRECTION OUTPUT ;
    USE SIGNAL ;
    PORT
      LAYER M5 ;
        RECT  25.488 0 25.512 0.084 ;
    END
  END kv_d[105]
  PIN kv_d[106]
    DIRECTION OUTPUT ;
    USE SIGNAL ;
    PORT
      LAYER M5 ;
        RECT  25.728 0 25.752 0.084 ;
    END
  END kv_d[106]
  PIN kv_d[107]
    DIRECTION OUTPUT ;
    USE SIGNAL ;
    PORT
      LAYER M5 ;
        RECT  25.968 0 25.992 0.084 ;
    END
  END kv_d[107]
  PIN kv_d[108]
    DIRECTION OUTPUT ;
    USE SIGNAL ;
    PORT
      LAYER M5 ;
        RECT  26.208 0 26.232 0.084 ;
    END
  END kv_d[108]
  PIN kv_d[109]
    DIRECTION OUTPUT ;
    USE SIGNAL ;
    PORT
      LAYER M5 ;
        RECT  26.4 0 26.424 0.084 ;
    END
  END kv_d[109]
  PIN kv_d[10]
    DIRECTION OUTPUT ;
    USE SIGNAL ;
    PORT
      LAYER M5 ;
        RECT  3.408 0 3.432 0.084 ;
    END
  END kv_d[10]
  PIN kv_d[110]
    DIRECTION OUTPUT ;
    USE SIGNAL ;
    PORT
      LAYER M5 ;
        RECT  26.64 0 26.664 0.084 ;
    END
  END kv_d[110]
  PIN kv_d[111]
    DIRECTION OUTPUT ;
    USE SIGNAL ;
    PORT
      LAYER M5 ;
        RECT  26.88 0 26.904 0.084 ;
    END
  END kv_d[111]
  PIN kv_d[112]
    DIRECTION OUTPUT ;
    USE SIGNAL ;
    PORT
      LAYER M5 ;
        RECT  27.12 0 27.144 0.084 ;
    END
  END kv_d[112]
  PIN kv_d[113]
    DIRECTION OUTPUT ;
    USE SIGNAL ;
    PORT
      LAYER M5 ;
        RECT  27.36 0 27.384 0.084 ;
    END
  END kv_d[113]
  PIN kv_d[114]
    DIRECTION OUTPUT ;
    USE SIGNAL ;
    PORT
      LAYER M5 ;
        RECT  27.6 0 27.624 0.084 ;
    END
  END kv_d[114]
  PIN kv_d[115]
    DIRECTION OUTPUT ;
    USE SIGNAL ;
    PORT
      LAYER M5 ;
        RECT  27.792 0 27.816 0.084 ;
    END
  END kv_d[115]
  PIN kv_d[116]
    DIRECTION OUTPUT ;
    USE SIGNAL ;
    PORT
      LAYER M5 ;
        RECT  28.032 0 28.056 0.084 ;
    END
  END kv_d[116]
  PIN kv_d[117]
    DIRECTION OUTPUT ;
    USE SIGNAL ;
    PORT
      LAYER M5 ;
        RECT  28.272 0 28.296 0.084 ;
    END
  END kv_d[117]
  PIN kv_d[118]
    DIRECTION OUTPUT ;
    USE SIGNAL ;
    PORT
      LAYER M5 ;
        RECT  28.512 0 28.536 0.084 ;
    END
  END kv_d[118]
  PIN kv_d[119]
    DIRECTION OUTPUT ;
    USE SIGNAL ;
    PORT
      LAYER M5 ;
        RECT  28.752 0 28.776 0.084 ;
    END
  END kv_d[119]
  PIN kv_d[11]
    DIRECTION OUTPUT ;
    USE SIGNAL ;
    PORT
      LAYER M5 ;
        RECT  3.648 0 3.672 0.084 ;
    END
  END kv_d[11]
  PIN kv_d[120]
    DIRECTION OUTPUT ;
    USE SIGNAL ;
    PORT
      LAYER M5 ;
        RECT  28.992 0 29.016 0.084 ;
    END
  END kv_d[120]
  PIN kv_d[121]
    DIRECTION OUTPUT ;
    USE SIGNAL ;
    PORT
      LAYER M5 ;
        RECT  29.184 0 29.208 0.084 ;
    END
  END kv_d[121]
  PIN kv_d[122]
    DIRECTION OUTPUT ;
    USE SIGNAL ;
    PORT
      LAYER M5 ;
        RECT  29.424 0 29.448 0.084 ;
    END
  END kv_d[122]
  PIN kv_d[123]
    DIRECTION OUTPUT ;
    USE SIGNAL ;
    PORT
      LAYER M5 ;
        RECT  29.664 0 29.688 0.084 ;
    END
  END kv_d[123]
  PIN kv_d[124]
    DIRECTION OUTPUT ;
    USE SIGNAL ;
    PORT
      LAYER M5 ;
        RECT  29.904 0 29.928 0.084 ;
    END
  END kv_d[124]
  PIN kv_d[125]
    DIRECTION OUTPUT ;
    USE SIGNAL ;
    PORT
      LAYER M5 ;
        RECT  30.144 0 30.168 0.084 ;
    END
  END kv_d[125]
  PIN kv_d[126]
    DIRECTION OUTPUT ;
    USE SIGNAL ;
    PORT
      LAYER M5 ;
        RECT  30.384 0 30.408 0.084 ;
    END
  END kv_d[126]
  PIN kv_d[127]
    DIRECTION OUTPUT ;
    USE SIGNAL ;
    PORT
      LAYER M5 ;
        RECT  30.624 0 30.648 0.084 ;
    END
  END kv_d[127]
  PIN kv_d[128]
    DIRECTION OUTPUT ;
    USE SIGNAL ;
    PORT
      LAYER M5 ;
        RECT  30.816 0 30.84 0.084 ;
    END
  END kv_d[128]
  PIN kv_d[129]
    DIRECTION OUTPUT ;
    USE SIGNAL ;
    PORT
      LAYER M5 ;
        RECT  31.056 0 31.08 0.084 ;
    END
  END kv_d[129]
  PIN kv_d[12]
    DIRECTION OUTPUT ;
    USE SIGNAL ;
    PORT
      LAYER M5 ;
        RECT  3.888 0 3.912 0.084 ;
    END
  END kv_d[12]
  PIN kv_d[130]
    DIRECTION OUTPUT ;
    USE SIGNAL ;
    PORT
      LAYER M5 ;
        RECT  31.296 0 31.32 0.084 ;
    END
  END kv_d[130]
  PIN kv_d[131]
    DIRECTION OUTPUT ;
    USE SIGNAL ;
    PORT
      LAYER M5 ;
        RECT  31.536 0 31.56 0.084 ;
    END
  END kv_d[131]
  PIN kv_d[132]
    DIRECTION OUTPUT ;
    USE SIGNAL ;
    PORT
      LAYER M5 ;
        RECT  31.776 0 31.8 0.084 ;
    END
  END kv_d[132]
  PIN kv_d[133]
    DIRECTION OUTPUT ;
    USE SIGNAL ;
    PORT
      LAYER M5 ;
        RECT  32.016 0 32.04 0.084 ;
    END
  END kv_d[133]
  PIN kv_d[134]
    DIRECTION OUTPUT ;
    USE SIGNAL ;
    PORT
      LAYER M5 ;
        RECT  32.208 0 32.232 0.084 ;
    END
  END kv_d[134]
  PIN kv_d[135]
    DIRECTION OUTPUT ;
    USE SIGNAL ;
    PORT
      LAYER M5 ;
        RECT  32.448 0 32.472 0.084 ;
    END
  END kv_d[135]
  PIN kv_d[136]
    DIRECTION OUTPUT ;
    USE SIGNAL ;
    PORT
      LAYER M5 ;
        RECT  32.688 0 32.712 0.084 ;
    END
  END kv_d[136]
  PIN kv_d[137]
    DIRECTION OUTPUT ;
    USE SIGNAL ;
    PORT
      LAYER M5 ;
        RECT  32.928 0 32.952 0.084 ;
    END
  END kv_d[137]
  PIN kv_d[138]
    DIRECTION OUTPUT ;
    USE SIGNAL ;
    PORT
      LAYER M5 ;
        RECT  33.168 0 33.192 0.084 ;
    END
  END kv_d[138]
  PIN kv_d[139]
    DIRECTION OUTPUT ;
    USE SIGNAL ;
    PORT
      LAYER M5 ;
        RECT  33.408 0 33.432 0.084 ;
    END
  END kv_d[139]
  PIN kv_d[13]
    DIRECTION OUTPUT ;
    USE SIGNAL ;
    PORT
      LAYER M5 ;
        RECT  4.128 0 4.152 0.084 ;
    END
  END kv_d[13]
  PIN kv_d[140]
    DIRECTION OUTPUT ;
    USE SIGNAL ;
    PORT
      LAYER M5 ;
        RECT  33.6 0 33.624 0.084 ;
    END
  END kv_d[140]
  PIN kv_d[141]
    DIRECTION OUTPUT ;
    USE SIGNAL ;
    PORT
      LAYER M5 ;
        RECT  33.84 0 33.864 0.084 ;
    END
  END kv_d[141]
  PIN kv_d[142]
    DIRECTION OUTPUT ;
    USE SIGNAL ;
    PORT
      LAYER M5 ;
        RECT  34.08 0 34.104 0.084 ;
    END
  END kv_d[142]
  PIN kv_d[143]
    DIRECTION OUTPUT ;
    USE SIGNAL ;
    PORT
      LAYER M5 ;
        RECT  34.32 0 34.344 0.084 ;
    END
  END kv_d[143]
  PIN kv_d[144]
    DIRECTION OUTPUT ;
    USE SIGNAL ;
    PORT
      LAYER M5 ;
        RECT  34.56 0 34.584 0.084 ;
    END
  END kv_d[144]
  PIN kv_d[145]
    DIRECTION OUTPUT ;
    USE SIGNAL ;
    PORT
      LAYER M5 ;
        RECT  34.8 0 34.824 0.084 ;
    END
  END kv_d[145]
  PIN kv_d[146]
    DIRECTION OUTPUT ;
    USE SIGNAL ;
    PORT
      LAYER M5 ;
        RECT  34.992 0 35.016 0.084 ;
    END
  END kv_d[146]
  PIN kv_d[147]
    DIRECTION OUTPUT ;
    USE SIGNAL ;
    PORT
      LAYER M5 ;
        RECT  35.232 0 35.256 0.084 ;
    END
  END kv_d[147]
  PIN kv_d[148]
    DIRECTION OUTPUT ;
    USE SIGNAL ;
    PORT
      LAYER M5 ;
        RECT  35.472 0 35.496 0.084 ;
    END
  END kv_d[148]
  PIN kv_d[149]
    DIRECTION OUTPUT ;
    USE SIGNAL ;
    PORT
      LAYER M5 ;
        RECT  35.712 0 35.736 0.084 ;
    END
  END kv_d[149]
  PIN kv_d[14]
    DIRECTION OUTPUT ;
    USE SIGNAL ;
    PORT
      LAYER M5 ;
        RECT  4.368 0 4.392 0.084 ;
    END
  END kv_d[14]
  PIN kv_d[150]
    DIRECTION OUTPUT ;
    USE SIGNAL ;
    PORT
      LAYER M5 ;
        RECT  35.952 0 35.976 0.084 ;
    END
  END kv_d[150]
  PIN kv_d[151]
    DIRECTION OUTPUT ;
    USE SIGNAL ;
    PORT
      LAYER M5 ;
        RECT  36.192 0 36.216 0.084 ;
    END
  END kv_d[151]
  PIN kv_d[152]
    DIRECTION OUTPUT ;
    USE SIGNAL ;
    PORT
      LAYER M5 ;
        RECT  36.384 0 36.408 0.084 ;
    END
  END kv_d[152]
  PIN kv_d[153]
    DIRECTION OUTPUT ;
    USE SIGNAL ;
    PORT
      LAYER M5 ;
        RECT  36.624 0 36.648 0.084 ;
    END
  END kv_d[153]
  PIN kv_d[154]
    DIRECTION OUTPUT ;
    USE SIGNAL ;
    PORT
      LAYER M5 ;
        RECT  36.864 0 36.888 0.084 ;
    END
  END kv_d[154]
  PIN kv_d[155]
    DIRECTION OUTPUT ;
    USE SIGNAL ;
    PORT
      LAYER M5 ;
        RECT  37.104 0 37.128 0.084 ;
    END
  END kv_d[155]
  PIN kv_d[156]
    DIRECTION OUTPUT ;
    USE SIGNAL ;
    PORT
      LAYER M5 ;
        RECT  37.344 0 37.368 0.084 ;
    END
  END kv_d[156]
  PIN kv_d[157]
    DIRECTION OUTPUT ;
    USE SIGNAL ;
    PORT
      LAYER M5 ;
        RECT  37.584 0 37.608 0.084 ;
    END
  END kv_d[157]
  PIN kv_d[158]
    DIRECTION OUTPUT ;
    USE SIGNAL ;
    PORT
      LAYER M5 ;
        RECT  37.776 0 37.8 0.084 ;
    END
  END kv_d[158]
  PIN kv_d[159]
    DIRECTION OUTPUT ;
    USE SIGNAL ;
    PORT
      LAYER M5 ;
        RECT  38.016 0 38.04 0.084 ;
    END
  END kv_d[159]
  PIN kv_d[15]
    DIRECTION OUTPUT ;
    USE SIGNAL ;
    PORT
      LAYER M5 ;
        RECT  4.608 0 4.632 0.084 ;
    END
  END kv_d[15]
  PIN kv_d[160]
    DIRECTION OUTPUT ;
    USE SIGNAL ;
    PORT
      LAYER M5 ;
        RECT  38.256 0 38.28 0.084 ;
    END
  END kv_d[160]
  PIN kv_d[161]
    DIRECTION OUTPUT ;
    USE SIGNAL ;
    PORT
      LAYER M5 ;
        RECT  38.496 0 38.52 0.084 ;
    END
  END kv_d[161]
  PIN kv_d[162]
    DIRECTION OUTPUT ;
    USE SIGNAL ;
    PORT
      LAYER M5 ;
        RECT  38.736 0 38.76 0.084 ;
    END
  END kv_d[162]
  PIN kv_d[163]
    DIRECTION OUTPUT ;
    USE SIGNAL ;
    PORT
      LAYER M5 ;
        RECT  38.976 0 39 0.084 ;
    END
  END kv_d[163]
  PIN kv_d[164]
    DIRECTION OUTPUT ;
    USE SIGNAL ;
    PORT
      LAYER M5 ;
        RECT  39.216 0 39.24 0.084 ;
    END
  END kv_d[164]
  PIN kv_d[165]
    DIRECTION OUTPUT ;
    USE SIGNAL ;
    PORT
      LAYER M5 ;
        RECT  39.408 0 39.432 0.084 ;
    END
  END kv_d[165]
  PIN kv_d[166]
    DIRECTION OUTPUT ;
    USE SIGNAL ;
    PORT
      LAYER M5 ;
        RECT  39.648 0 39.672 0.084 ;
    END
  END kv_d[166]
  PIN kv_d[167]
    DIRECTION OUTPUT ;
    USE SIGNAL ;
    PORT
      LAYER M5 ;
        RECT  39.888 0 39.912 0.084 ;
    END
  END kv_d[167]
  PIN kv_d[168]
    DIRECTION OUTPUT ;
    USE SIGNAL ;
    PORT
      LAYER M5 ;
        RECT  40.128 0 40.152 0.084 ;
    END
  END kv_d[168]
  PIN kv_d[169]
    DIRECTION OUTPUT ;
    USE SIGNAL ;
    PORT
      LAYER M5 ;
        RECT  40.368 0 40.392 0.084 ;
    END
  END kv_d[169]
  PIN kv_d[16]
    DIRECTION OUTPUT ;
    USE SIGNAL ;
    PORT
      LAYER M5 ;
        RECT  4.8 0 4.824 0.084 ;
    END
  END kv_d[16]
  PIN kv_d[170]
    DIRECTION OUTPUT ;
    USE SIGNAL ;
    PORT
      LAYER M5 ;
        RECT  40.608 0 40.632 0.084 ;
    END
  END kv_d[170]
  PIN kv_d[171]
    DIRECTION OUTPUT ;
    USE SIGNAL ;
    PORT
      LAYER M5 ;
        RECT  40.8 0 40.824 0.084 ;
    END
  END kv_d[171]
  PIN kv_d[172]
    DIRECTION OUTPUT ;
    USE SIGNAL ;
    PORT
      LAYER M5 ;
        RECT  41.04 0 41.064 0.084 ;
    END
  END kv_d[172]
  PIN kv_d[173]
    DIRECTION OUTPUT ;
    USE SIGNAL ;
    PORT
      LAYER M5 ;
        RECT  41.28 0 41.304 0.084 ;
    END
  END kv_d[173]
  PIN kv_d[174]
    DIRECTION OUTPUT ;
    USE SIGNAL ;
    PORT
      LAYER M5 ;
        RECT  41.52 0 41.544 0.084 ;
    END
  END kv_d[174]
  PIN kv_d[175]
    DIRECTION OUTPUT ;
    USE SIGNAL ;
    PORT
      LAYER M5 ;
        RECT  41.76 0 41.784 0.084 ;
    END
  END kv_d[175]
  PIN kv_d[176]
    DIRECTION OUTPUT ;
    USE SIGNAL ;
    PORT
      LAYER M5 ;
        RECT  42 0 42.024 0.084 ;
    END
  END kv_d[176]
  PIN kv_d[177]
    DIRECTION OUTPUT ;
    USE SIGNAL ;
    PORT
      LAYER M5 ;
        RECT  42.192 0 42.216 0.084 ;
    END
  END kv_d[177]
  PIN kv_d[178]
    DIRECTION OUTPUT ;
    USE SIGNAL ;
    PORT
      LAYER M5 ;
        RECT  42.432 0 42.456 0.084 ;
    END
  END kv_d[178]
  PIN kv_d[179]
    DIRECTION OUTPUT ;
    USE SIGNAL ;
    PORT
      LAYER M5 ;
        RECT  42.672 0 42.696 0.084 ;
    END
  END kv_d[179]
  PIN kv_d[17]
    DIRECTION OUTPUT ;
    USE SIGNAL ;
    PORT
      LAYER M5 ;
        RECT  5.04 0 5.064 0.084 ;
    END
  END kv_d[17]
  PIN kv_d[180]
    DIRECTION OUTPUT ;
    USE SIGNAL ;
    PORT
      LAYER M5 ;
        RECT  42.912 0 42.936 0.084 ;
    END
  END kv_d[180]
  PIN kv_d[181]
    DIRECTION OUTPUT ;
    USE SIGNAL ;
    PORT
      LAYER M5 ;
        RECT  43.152 0 43.176 0.084 ;
    END
  END kv_d[181]
  PIN kv_d[182]
    DIRECTION OUTPUT ;
    USE SIGNAL ;
    PORT
      LAYER M5 ;
        RECT  43.392 0 43.416 0.084 ;
    END
  END kv_d[182]
  PIN kv_d[183]
    DIRECTION OUTPUT ;
    USE SIGNAL ;
    PORT
      LAYER M5 ;
        RECT  43.584 0 43.608 0.084 ;
    END
  END kv_d[183]
  PIN kv_d[184]
    DIRECTION OUTPUT ;
    USE SIGNAL ;
    PORT
      LAYER M5 ;
        RECT  43.824 0 43.848 0.084 ;
    END
  END kv_d[184]
  PIN kv_d[185]
    DIRECTION OUTPUT ;
    USE SIGNAL ;
    PORT
      LAYER M5 ;
        RECT  44.064 0 44.088 0.084 ;
    END
  END kv_d[185]
  PIN kv_d[186]
    DIRECTION OUTPUT ;
    USE SIGNAL ;
    PORT
      LAYER M5 ;
        RECT  44.304 0 44.328 0.084 ;
    END
  END kv_d[186]
  PIN kv_d[187]
    DIRECTION OUTPUT ;
    USE SIGNAL ;
    PORT
      LAYER M5 ;
        RECT  44.544 0 44.568 0.084 ;
    END
  END kv_d[187]
  PIN kv_d[188]
    DIRECTION OUTPUT ;
    USE SIGNAL ;
    PORT
      LAYER M5 ;
        RECT  44.784 0 44.808 0.084 ;
    END
  END kv_d[188]
  PIN kv_d[189]
    DIRECTION OUTPUT ;
    USE SIGNAL ;
    PORT
      LAYER M5 ;
        RECT  44.976 0 45 0.084 ;
    END
  END kv_d[189]
  PIN kv_d[18]
    DIRECTION OUTPUT ;
    USE SIGNAL ;
    PORT
      LAYER M5 ;
        RECT  5.28 0 5.304 0.084 ;
    END
  END kv_d[18]
  PIN kv_d[190]
    DIRECTION OUTPUT ;
    USE SIGNAL ;
    PORT
      LAYER M5 ;
        RECT  45.216 0 45.24 0.084 ;
    END
  END kv_d[190]
  PIN kv_d[191]
    DIRECTION OUTPUT ;
    USE SIGNAL ;
    PORT
      LAYER M5 ;
        RECT  45.456 0 45.48 0.084 ;
    END
  END kv_d[191]
  PIN kv_d[192]
    DIRECTION OUTPUT ;
    USE SIGNAL ;
    PORT
      LAYER M5 ;
        RECT  45.696 0 45.72 0.084 ;
    END
  END kv_d[192]
  PIN kv_d[193]
    DIRECTION OUTPUT ;
    USE SIGNAL ;
    PORT
      LAYER M5 ;
        RECT  45.936 0 45.96 0.084 ;
    END
  END kv_d[193]
  PIN kv_d[194]
    DIRECTION OUTPUT ;
    USE SIGNAL ;
    PORT
      LAYER M5 ;
        RECT  46.176 0 46.2 0.084 ;
    END
  END kv_d[194]
  PIN kv_d[195]
    DIRECTION OUTPUT ;
    USE SIGNAL ;
    PORT
      LAYER M5 ;
        RECT  46.416 0 46.44 0.084 ;
    END
  END kv_d[195]
  PIN kv_d[196]
    DIRECTION OUTPUT ;
    USE SIGNAL ;
    PORT
      LAYER M5 ;
        RECT  46.608 0 46.632 0.084 ;
    END
  END kv_d[196]
  PIN kv_d[197]
    DIRECTION OUTPUT ;
    USE SIGNAL ;
    PORT
      LAYER M5 ;
        RECT  46.848 0 46.872 0.084 ;
    END
  END kv_d[197]
  PIN kv_d[198]
    DIRECTION OUTPUT ;
    USE SIGNAL ;
    PORT
      LAYER M5 ;
        RECT  47.088 0 47.112 0.084 ;
    END
  END kv_d[198]
  PIN kv_d[199]
    DIRECTION OUTPUT ;
    USE SIGNAL ;
    PORT
      LAYER M5 ;
        RECT  47.328 0 47.352 0.084 ;
    END
  END kv_d[199]
  PIN kv_d[19]
    DIRECTION OUTPUT ;
    USE SIGNAL ;
    PORT
      LAYER M5 ;
        RECT  5.52 0 5.544 0.084 ;
    END
  END kv_d[19]
  PIN kv_d[1]
    DIRECTION OUTPUT ;
    USE SIGNAL ;
    PORT
      LAYER M5 ;
        RECT  1.344 0 1.368 0.084 ;
    END
  END kv_d[1]
  PIN kv_d[200]
    DIRECTION OUTPUT ;
    USE SIGNAL ;
    PORT
      LAYER M5 ;
        RECT  47.568 0 47.592 0.084 ;
    END
  END kv_d[200]
  PIN kv_d[201]
    DIRECTION OUTPUT ;
    USE SIGNAL ;
    PORT
      LAYER M5 ;
        RECT  47.808 0 47.832 0.084 ;
    END
  END kv_d[201]
  PIN kv_d[202]
    DIRECTION OUTPUT ;
    USE SIGNAL ;
    PORT
      LAYER M5 ;
        RECT  48 0 48.024 0.084 ;
    END
  END kv_d[202]
  PIN kv_d[203]
    DIRECTION OUTPUT ;
    USE SIGNAL ;
    PORT
      LAYER M5 ;
        RECT  48.24 0 48.264 0.084 ;
    END
  END kv_d[203]
  PIN kv_d[204]
    DIRECTION OUTPUT ;
    USE SIGNAL ;
    PORT
      LAYER M5 ;
        RECT  48.48 0 48.504 0.084 ;
    END
  END kv_d[204]
  PIN kv_d[205]
    DIRECTION OUTPUT ;
    USE SIGNAL ;
    PORT
      LAYER M5 ;
        RECT  48.72 0 48.744 0.084 ;
    END
  END kv_d[205]
  PIN kv_d[206]
    DIRECTION OUTPUT ;
    USE SIGNAL ;
    PORT
      LAYER M5 ;
        RECT  48.96 0 48.984 0.084 ;
    END
  END kv_d[206]
  PIN kv_d[207]
    DIRECTION OUTPUT ;
    USE SIGNAL ;
    PORT
      LAYER M5 ;
        RECT  49.2 0 49.224 0.084 ;
    END
  END kv_d[207]
  PIN kv_d[208]
    DIRECTION OUTPUT ;
    USE SIGNAL ;
    PORT
      LAYER M5 ;
        RECT  49.392 0 49.416 0.084 ;
    END
  END kv_d[208]
  PIN kv_d[209]
    DIRECTION OUTPUT ;
    USE SIGNAL ;
    PORT
      LAYER M5 ;
        RECT  49.632 0 49.656 0.084 ;
    END
  END kv_d[209]
  PIN kv_d[20]
    DIRECTION OUTPUT ;
    USE SIGNAL ;
    PORT
      LAYER M5 ;
        RECT  5.76 0 5.784 0.084 ;
    END
  END kv_d[20]
  PIN kv_d[210]
    DIRECTION OUTPUT ;
    USE SIGNAL ;
    PORT
      LAYER M5 ;
        RECT  49.872 0 49.896 0.084 ;
    END
  END kv_d[210]
  PIN kv_d[211]
    DIRECTION OUTPUT ;
    USE SIGNAL ;
    PORT
      LAYER M5 ;
        RECT  50.112 0 50.136 0.084 ;
    END
  END kv_d[211]
  PIN kv_d[212]
    DIRECTION OUTPUT ;
    USE SIGNAL ;
    PORT
      LAYER M5 ;
        RECT  50.352 0 50.376 0.084 ;
    END
  END kv_d[212]
  PIN kv_d[213]
    DIRECTION OUTPUT ;
    USE SIGNAL ;
    PORT
      LAYER M5 ;
        RECT  50.592 0 50.616 0.084 ;
    END
  END kv_d[213]
  PIN kv_d[214]
    DIRECTION OUTPUT ;
    USE SIGNAL ;
    PORT
      LAYER M5 ;
        RECT  50.784 0 50.808 0.084 ;
    END
  END kv_d[214]
  PIN kv_d[215]
    DIRECTION OUTPUT ;
    USE SIGNAL ;
    PORT
      LAYER M5 ;
        RECT  51.024 0 51.048 0.084 ;
    END
  END kv_d[215]
  PIN kv_d[216]
    DIRECTION OUTPUT ;
    USE SIGNAL ;
    PORT
      LAYER M5 ;
        RECT  51.264 0 51.288 0.084 ;
    END
  END kv_d[216]
  PIN kv_d[217]
    DIRECTION OUTPUT ;
    USE SIGNAL ;
    PORT
      LAYER M5 ;
        RECT  51.504 0 51.528 0.084 ;
    END
  END kv_d[217]
  PIN kv_d[218]
    DIRECTION OUTPUT ;
    USE SIGNAL ;
    PORT
      LAYER M5 ;
        RECT  51.744 0 51.768 0.084 ;
    END
  END kv_d[218]
  PIN kv_d[219]
    DIRECTION OUTPUT ;
    USE SIGNAL ;
    PORT
      LAYER M5 ;
        RECT  51.984 0 52.008 0.084 ;
    END
  END kv_d[219]
  PIN kv_d[21]
    DIRECTION OUTPUT ;
    USE SIGNAL ;
    PORT
      LAYER M5 ;
        RECT  6 0 6.024 0.084 ;
    END
  END kv_d[21]
  PIN kv_d[220]
    DIRECTION OUTPUT ;
    USE SIGNAL ;
    PORT
      LAYER M5 ;
        RECT  52.176 0 52.2 0.084 ;
    END
  END kv_d[220]
  PIN kv_d[221]
    DIRECTION OUTPUT ;
    USE SIGNAL ;
    PORT
      LAYER M5 ;
        RECT  52.416 0 52.44 0.084 ;
    END
  END kv_d[221]
  PIN kv_d[222]
    DIRECTION OUTPUT ;
    USE SIGNAL ;
    PORT
      LAYER M5 ;
        RECT  52.656 0 52.68 0.084 ;
    END
  END kv_d[222]
  PIN kv_d[223]
    DIRECTION OUTPUT ;
    USE SIGNAL ;
    PORT
      LAYER M5 ;
        RECT  52.896 0 52.92 0.084 ;
    END
  END kv_d[223]
  PIN kv_d[224]
    DIRECTION OUTPUT ;
    USE SIGNAL ;
    PORT
      LAYER M5 ;
        RECT  53.136 0 53.16 0.084 ;
    END
  END kv_d[224]
  PIN kv_d[225]
    DIRECTION OUTPUT ;
    USE SIGNAL ;
    PORT
      LAYER M5 ;
        RECT  53.376 0 53.4 0.084 ;
    END
  END kv_d[225]
  PIN kv_d[226]
    DIRECTION OUTPUT ;
    USE SIGNAL ;
    PORT
      LAYER M5 ;
        RECT  53.616 0 53.64 0.084 ;
    END
  END kv_d[226]
  PIN kv_d[227]
    DIRECTION OUTPUT ;
    USE SIGNAL ;
    PORT
      LAYER M5 ;
        RECT  53.808 0 53.832 0.084 ;
    END
  END kv_d[227]
  PIN kv_d[228]
    DIRECTION OUTPUT ;
    USE SIGNAL ;
    PORT
      LAYER M5 ;
        RECT  54.048 0 54.072 0.084 ;
    END
  END kv_d[228]
  PIN kv_d[229]
    DIRECTION OUTPUT ;
    USE SIGNAL ;
    PORT
      LAYER M5 ;
        RECT  54.288 0 54.312 0.084 ;
    END
  END kv_d[229]
  PIN kv_d[22]
    DIRECTION OUTPUT ;
    USE SIGNAL ;
    PORT
      LAYER M5 ;
        RECT  6.192 0 6.216 0.084 ;
    END
  END kv_d[22]
  PIN kv_d[230]
    DIRECTION OUTPUT ;
    USE SIGNAL ;
    PORT
      LAYER M5 ;
        RECT  54.528 0 54.552 0.084 ;
    END
  END kv_d[230]
  PIN kv_d[231]
    DIRECTION OUTPUT ;
    USE SIGNAL ;
    PORT
      LAYER M5 ;
        RECT  54.768 0 54.792 0.084 ;
    END
  END kv_d[231]
  PIN kv_d[232]
    DIRECTION OUTPUT ;
    USE SIGNAL ;
    PORT
      LAYER M5 ;
        RECT  55.008 0 55.032 0.084 ;
    END
  END kv_d[232]
  PIN kv_d[233]
    DIRECTION OUTPUT ;
    USE SIGNAL ;
    PORT
      LAYER M5 ;
        RECT  55.2 0 55.224 0.084 ;
    END
  END kv_d[233]
  PIN kv_d[234]
    DIRECTION OUTPUT ;
    USE SIGNAL ;
    PORT
      LAYER M5 ;
        RECT  55.44 0 55.464 0.084 ;
    END
  END kv_d[234]
  PIN kv_d[235]
    DIRECTION OUTPUT ;
    USE SIGNAL ;
    PORT
      LAYER M5 ;
        RECT  55.68 0 55.704 0.084 ;
    END
  END kv_d[235]
  PIN kv_d[236]
    DIRECTION OUTPUT ;
    USE SIGNAL ;
    PORT
      LAYER M5 ;
        RECT  55.92 0 55.944 0.084 ;
    END
  END kv_d[236]
  PIN kv_d[237]
    DIRECTION OUTPUT ;
    USE SIGNAL ;
    PORT
      LAYER M5 ;
        RECT  56.16 0 56.184 0.084 ;
    END
  END kv_d[237]
  PIN kv_d[238]
    DIRECTION OUTPUT ;
    USE SIGNAL ;
    PORT
      LAYER M5 ;
        RECT  56.4 0 56.424 0.084 ;
    END
  END kv_d[238]
  PIN kv_d[239]
    DIRECTION OUTPUT ;
    USE SIGNAL ;
    PORT
      LAYER M5 ;
        RECT  56.592 0 56.616 0.084 ;
    END
  END kv_d[239]
  PIN kv_d[23]
    DIRECTION OUTPUT ;
    USE SIGNAL ;
    PORT
      LAYER M5 ;
        RECT  6.432 0 6.456 0.084 ;
    END
  END kv_d[23]
  PIN kv_d[240]
    DIRECTION OUTPUT ;
    USE SIGNAL ;
    PORT
      LAYER M5 ;
        RECT  56.832 0 56.856 0.084 ;
    END
  END kv_d[240]
  PIN kv_d[241]
    DIRECTION OUTPUT ;
    USE SIGNAL ;
    PORT
      LAYER M5 ;
        RECT  57.072 0 57.096 0.084 ;
    END
  END kv_d[241]
  PIN kv_d[242]
    DIRECTION OUTPUT ;
    USE SIGNAL ;
    PORT
      LAYER M5 ;
        RECT  57.312 0 57.336 0.084 ;
    END
  END kv_d[242]
  PIN kv_d[243]
    DIRECTION OUTPUT ;
    USE SIGNAL ;
    PORT
      LAYER M5 ;
        RECT  57.552 0 57.576 0.084 ;
    END
  END kv_d[243]
  PIN kv_d[244]
    DIRECTION OUTPUT ;
    USE SIGNAL ;
    PORT
      LAYER M5 ;
        RECT  57.792 0 57.816 0.084 ;
    END
  END kv_d[244]
  PIN kv_d[245]
    DIRECTION OUTPUT ;
    USE SIGNAL ;
    PORT
      LAYER M5 ;
        RECT  57.984 0 58.008 0.084 ;
    END
  END kv_d[245]
  PIN kv_d[246]
    DIRECTION OUTPUT ;
    USE SIGNAL ;
    PORT
      LAYER M5 ;
        RECT  58.224 0 58.248 0.084 ;
    END
  END kv_d[246]
  PIN kv_d[247]
    DIRECTION OUTPUT ;
    USE SIGNAL ;
    PORT
      LAYER M5 ;
        RECT  58.464 0 58.488 0.084 ;
    END
  END kv_d[247]
  PIN kv_d[248]
    DIRECTION OUTPUT ;
    USE SIGNAL ;
    PORT
      LAYER M5 ;
        RECT  58.704 0 58.728 0.084 ;
    END
  END kv_d[248]
  PIN kv_d[249]
    DIRECTION OUTPUT ;
    USE SIGNAL ;
    PORT
      LAYER M5 ;
        RECT  58.944 0 58.968 0.084 ;
    END
  END kv_d[249]
  PIN kv_d[24]
    DIRECTION OUTPUT ;
    USE SIGNAL ;
    PORT
      LAYER M5 ;
        RECT  6.672 0 6.696 0.084 ;
    END
  END kv_d[24]
  PIN kv_d[250]
    DIRECTION OUTPUT ;
    USE SIGNAL ;
    PORT
      LAYER M5 ;
        RECT  59.184 0 59.208 0.084 ;
    END
  END kv_d[250]
  PIN kv_d[251]
    DIRECTION OUTPUT ;
    USE SIGNAL ;
    PORT
      LAYER M5 ;
        RECT  59.376 0 59.4 0.084 ;
    END
  END kv_d[251]
  PIN kv_d[252]
    DIRECTION OUTPUT ;
    USE SIGNAL ;
    PORT
      LAYER M5 ;
        RECT  59.616 0 59.64 0.084 ;
    END
  END kv_d[252]
  PIN kv_d[253]
    DIRECTION OUTPUT ;
    USE SIGNAL ;
    PORT
      LAYER M5 ;
        RECT  59.856 0 59.88 0.084 ;
    END
  END kv_d[253]
  PIN kv_d[254]
    DIRECTION OUTPUT ;
    USE SIGNAL ;
    PORT
      LAYER M5 ;
        RECT  60.096 0 60.12 0.084 ;
    END
  END kv_d[254]
  PIN kv_d[255]
    DIRECTION OUTPUT ;
    USE SIGNAL ;
    PORT
      LAYER M5 ;
        RECT  60.336 0 60.36 0.084 ;
    END
  END kv_d[255]
  PIN kv_d[256]
    DIRECTION OUTPUT ;
    USE SIGNAL ;
    PORT
      LAYER M5 ;
        RECT  60.576 0 60.6 0.084 ;
    END
  END kv_d[256]
  PIN kv_d[257]
    DIRECTION OUTPUT ;
    USE SIGNAL ;
    PORT
      LAYER M5 ;
        RECT  60.816 0 60.84 0.084 ;
    END
  END kv_d[257]
  PIN kv_d[258]
    DIRECTION OUTPUT ;
    USE SIGNAL ;
    PORT
      LAYER M5 ;
        RECT  61.008 0 61.032 0.084 ;
    END
  END kv_d[258]
  PIN kv_d[259]
    DIRECTION OUTPUT ;
    USE SIGNAL ;
    PORT
      LAYER M5 ;
        RECT  61.248 0 61.272 0.084 ;
    END
  END kv_d[259]
  PIN kv_d[25]
    DIRECTION OUTPUT ;
    USE SIGNAL ;
    PORT
      LAYER M5 ;
        RECT  6.912 0 6.936 0.084 ;
    END
  END kv_d[25]
  PIN kv_d[260]
    DIRECTION OUTPUT ;
    USE SIGNAL ;
    PORT
      LAYER M5 ;
        RECT  61.488 0 61.512 0.084 ;
    END
  END kv_d[260]
  PIN kv_d[261]
    DIRECTION OUTPUT ;
    USE SIGNAL ;
    PORT
      LAYER M5 ;
        RECT  61.728 0 61.752 0.084 ;
    END
  END kv_d[261]
  PIN kv_d[262]
    DIRECTION OUTPUT ;
    USE SIGNAL ;
    PORT
      LAYER M5 ;
        RECT  61.968 0 61.992 0.084 ;
    END
  END kv_d[262]
  PIN kv_d[263]
    DIRECTION OUTPUT ;
    USE SIGNAL ;
    PORT
      LAYER M5 ;
        RECT  62.208 0 62.232 0.084 ;
    END
  END kv_d[263]
  PIN kv_d[264]
    DIRECTION OUTPUT ;
    USE SIGNAL ;
    PORT
      LAYER M5 ;
        RECT  62.4 0 62.424 0.084 ;
    END
  END kv_d[264]
  PIN kv_d[265]
    DIRECTION OUTPUT ;
    USE SIGNAL ;
    PORT
      LAYER M5 ;
        RECT  62.64 0 62.664 0.084 ;
    END
  END kv_d[265]
  PIN kv_d[266]
    DIRECTION OUTPUT ;
    USE SIGNAL ;
    PORT
      LAYER M5 ;
        RECT  62.88 0 62.904 0.084 ;
    END
  END kv_d[266]
  PIN kv_d[267]
    DIRECTION OUTPUT ;
    USE SIGNAL ;
    PORT
      LAYER M5 ;
        RECT  63.12 0 63.144 0.084 ;
    END
  END kv_d[267]
  PIN kv_d[268]
    DIRECTION OUTPUT ;
    USE SIGNAL ;
    PORT
      LAYER M5 ;
        RECT  63.36 0 63.384 0.084 ;
    END
  END kv_d[268]
  PIN kv_d[269]
    DIRECTION OUTPUT ;
    USE SIGNAL ;
    PORT
      LAYER M5 ;
        RECT  63.6 0 63.624 0.084 ;
    END
  END kv_d[269]
  PIN kv_d[26]
    DIRECTION OUTPUT ;
    USE SIGNAL ;
    PORT
      LAYER M5 ;
        RECT  7.152 0 7.176 0.084 ;
    END
  END kv_d[26]
  PIN kv_d[270]
    DIRECTION OUTPUT ;
    USE SIGNAL ;
    PORT
      LAYER M5 ;
        RECT  63.792 0 63.816 0.084 ;
    END
  END kv_d[270]
  PIN kv_d[271]
    DIRECTION OUTPUT ;
    USE SIGNAL ;
    PORT
      LAYER M5 ;
        RECT  64.032 0 64.056 0.084 ;
    END
  END kv_d[271]
  PIN kv_d[272]
    DIRECTION OUTPUT ;
    USE SIGNAL ;
    PORT
      LAYER M5 ;
        RECT  64.272 0 64.296 0.084 ;
    END
  END kv_d[272]
  PIN kv_d[273]
    DIRECTION OUTPUT ;
    USE SIGNAL ;
    PORT
      LAYER M5 ;
        RECT  64.512 0 64.536 0.084 ;
    END
  END kv_d[273]
  PIN kv_d[274]
    DIRECTION OUTPUT ;
    USE SIGNAL ;
    PORT
      LAYER M5 ;
        RECT  64.752 0 64.776 0.084 ;
    END
  END kv_d[274]
  PIN kv_d[275]
    DIRECTION OUTPUT ;
    USE SIGNAL ;
    PORT
      LAYER M5 ;
        RECT  64.992 0 65.016 0.084 ;
    END
  END kv_d[275]
  PIN kv_d[276]
    DIRECTION OUTPUT ;
    USE SIGNAL ;
    PORT
      LAYER M5 ;
        RECT  65.184 0 65.208 0.084 ;
    END
  END kv_d[276]
  PIN kv_d[277]
    DIRECTION OUTPUT ;
    USE SIGNAL ;
    PORT
      LAYER M5 ;
        RECT  65.424 0 65.448 0.084 ;
    END
  END kv_d[277]
  PIN kv_d[278]
    DIRECTION OUTPUT ;
    USE SIGNAL ;
    PORT
      LAYER M5 ;
        RECT  65.664 0 65.688 0.084 ;
    END
  END kv_d[278]
  PIN kv_d[279]
    DIRECTION OUTPUT ;
    USE SIGNAL ;
    PORT
      LAYER M5 ;
        RECT  65.904 0 65.928 0.084 ;
    END
  END kv_d[279]
  PIN kv_d[27]
    DIRECTION OUTPUT ;
    USE SIGNAL ;
    PORT
      LAYER M5 ;
        RECT  7.392 0 7.416 0.084 ;
    END
  END kv_d[27]
  PIN kv_d[280]
    DIRECTION OUTPUT ;
    USE SIGNAL ;
    PORT
      LAYER M5 ;
        RECT  66.144 0 66.168 0.084 ;
    END
  END kv_d[280]
  PIN kv_d[281]
    DIRECTION OUTPUT ;
    USE SIGNAL ;
    PORT
      LAYER M5 ;
        RECT  66.384 0 66.408 0.084 ;
    END
  END kv_d[281]
  PIN kv_d[282]
    DIRECTION OUTPUT ;
    USE SIGNAL ;
    PORT
      LAYER M5 ;
        RECT  66.576 0 66.6 0.084 ;
    END
  END kv_d[282]
  PIN kv_d[283]
    DIRECTION OUTPUT ;
    USE SIGNAL ;
    PORT
      LAYER M5 ;
        RECT  66.816 0 66.84 0.084 ;
    END
  END kv_d[283]
  PIN kv_d[284]
    DIRECTION OUTPUT ;
    USE SIGNAL ;
    PORT
      LAYER M5 ;
        RECT  67.056 0 67.08 0.084 ;
    END
  END kv_d[284]
  PIN kv_d[285]
    DIRECTION OUTPUT ;
    USE SIGNAL ;
    PORT
      LAYER M5 ;
        RECT  67.296 0 67.32 0.084 ;
    END
  END kv_d[285]
  PIN kv_d[286]
    DIRECTION OUTPUT ;
    USE SIGNAL ;
    PORT
      LAYER M5 ;
        RECT  67.536 0 67.56 0.084 ;
    END
  END kv_d[286]
  PIN kv_d[287]
    DIRECTION OUTPUT ;
    USE SIGNAL ;
    PORT
      LAYER M5 ;
        RECT  67.776 0 67.8 0.084 ;
    END
  END kv_d[287]
  PIN kv_d[28]
    DIRECTION OUTPUT ;
    USE SIGNAL ;
    PORT
      LAYER M5 ;
        RECT  7.584 0 7.608 0.084 ;
    END
  END kv_d[28]
  PIN kv_d[29]
    DIRECTION OUTPUT ;
    USE SIGNAL ;
    PORT
      LAYER M5 ;
        RECT  7.824 0 7.848 0.084 ;
    END
  END kv_d[29]
  PIN kv_d[2]
    DIRECTION OUTPUT ;
    USE SIGNAL ;
    PORT
      LAYER M5 ;
        RECT  1.584 0 1.608 0.084 ;
    END
  END kv_d[2]
  PIN kv_d[30]
    DIRECTION OUTPUT ;
    USE SIGNAL ;
    PORT
      LAYER M5 ;
        RECT  8.064 0 8.088 0.084 ;
    END
  END kv_d[30]
  PIN kv_d[31]
    DIRECTION OUTPUT ;
    USE SIGNAL ;
    PORT
      LAYER M5 ;
        RECT  8.304 0 8.328 0.084 ;
    END
  END kv_d[31]
  PIN kv_d[32]
    DIRECTION OUTPUT ;
    USE SIGNAL ;
    PORT
      LAYER M5 ;
        RECT  8.544 0 8.568 0.084 ;
    END
  END kv_d[32]
  PIN kv_d[33]
    DIRECTION OUTPUT ;
    USE SIGNAL ;
    PORT
      LAYER M5 ;
        RECT  8.784 0 8.808 0.084 ;
    END
  END kv_d[33]
  PIN kv_d[34]
    DIRECTION OUTPUT ;
    USE SIGNAL ;
    PORT
      LAYER M5 ;
        RECT  9.024 0 9.048 0.084 ;
    END
  END kv_d[34]
  PIN kv_d[35]
    DIRECTION OUTPUT ;
    USE SIGNAL ;
    PORT
      LAYER M5 ;
        RECT  9.216 0 9.24 0.084 ;
    END
  END kv_d[35]
  PIN kv_d[36]
    DIRECTION OUTPUT ;
    USE SIGNAL ;
    PORT
      LAYER M5 ;
        RECT  9.456 0 9.48 0.084 ;
    END
  END kv_d[36]
  PIN kv_d[37]
    DIRECTION OUTPUT ;
    USE SIGNAL ;
    PORT
      LAYER M5 ;
        RECT  9.696 0 9.72 0.084 ;
    END
  END kv_d[37]
  PIN kv_d[38]
    DIRECTION OUTPUT ;
    USE SIGNAL ;
    PORT
      LAYER M5 ;
        RECT  9.936 0 9.96 0.084 ;
    END
  END kv_d[38]
  PIN kv_d[39]
    DIRECTION OUTPUT ;
    USE SIGNAL ;
    PORT
      LAYER M5 ;
        RECT  10.176 0 10.2 0.084 ;
    END
  END kv_d[39]
  PIN kv_d[3]
    DIRECTION OUTPUT ;
    USE SIGNAL ;
    PORT
      LAYER M5 ;
        RECT  1.824 0 1.848 0.084 ;
    END
  END kv_d[3]
  PIN kv_d[40]
    DIRECTION OUTPUT ;
    USE SIGNAL ;
    PORT
      LAYER M5 ;
        RECT  10.416 0 10.44 0.084 ;
    END
  END kv_d[40]
  PIN kv_d[41]
    DIRECTION OUTPUT ;
    USE SIGNAL ;
    PORT
      LAYER M5 ;
        RECT  10.608 0 10.632 0.084 ;
    END
  END kv_d[41]
  PIN kv_d[42]
    DIRECTION OUTPUT ;
    USE SIGNAL ;
    PORT
      LAYER M5 ;
        RECT  10.848 0 10.872 0.084 ;
    END
  END kv_d[42]
  PIN kv_d[43]
    DIRECTION OUTPUT ;
    USE SIGNAL ;
    PORT
      LAYER M5 ;
        RECT  11.088 0 11.112 0.084 ;
    END
  END kv_d[43]
  PIN kv_d[44]
    DIRECTION OUTPUT ;
    USE SIGNAL ;
    PORT
      LAYER M5 ;
        RECT  11.328 0 11.352 0.084 ;
    END
  END kv_d[44]
  PIN kv_d[45]
    DIRECTION OUTPUT ;
    USE SIGNAL ;
    PORT
      LAYER M5 ;
        RECT  11.568 0 11.592 0.084 ;
    END
  END kv_d[45]
  PIN kv_d[46]
    DIRECTION OUTPUT ;
    USE SIGNAL ;
    PORT
      LAYER M5 ;
        RECT  11.808 0 11.832 0.084 ;
    END
  END kv_d[46]
  PIN kv_d[47]
    DIRECTION OUTPUT ;
    USE SIGNAL ;
    PORT
      LAYER M5 ;
        RECT  12 0 12.024 0.084 ;
    END
  END kv_d[47]
  PIN kv_d[48]
    DIRECTION OUTPUT ;
    USE SIGNAL ;
    PORT
      LAYER M5 ;
        RECT  12.24 0 12.264 0.084 ;
    END
  END kv_d[48]
  PIN kv_d[49]
    DIRECTION OUTPUT ;
    USE SIGNAL ;
    PORT
      LAYER M5 ;
        RECT  12.48 0 12.504 0.084 ;
    END
  END kv_d[49]
  PIN kv_d[4]
    DIRECTION OUTPUT ;
    USE SIGNAL ;
    PORT
      LAYER M5 ;
        RECT  2.016 0 2.04 0.084 ;
    END
  END kv_d[4]
  PIN kv_d[50]
    DIRECTION OUTPUT ;
    USE SIGNAL ;
    PORT
      LAYER M5 ;
        RECT  12.72 0 12.744 0.084 ;
    END
  END kv_d[50]
  PIN kv_d[51]
    DIRECTION OUTPUT ;
    USE SIGNAL ;
    PORT
      LAYER M5 ;
        RECT  12.96 0 12.984 0.084 ;
    END
  END kv_d[51]
  PIN kv_d[52]
    DIRECTION OUTPUT ;
    USE SIGNAL ;
    PORT
      LAYER M5 ;
        RECT  13.2 0 13.224 0.084 ;
    END
  END kv_d[52]
  PIN kv_d[53]
    DIRECTION OUTPUT ;
    USE SIGNAL ;
    PORT
      LAYER M5 ;
        RECT  13.392 0 13.416 0.084 ;
    END
  END kv_d[53]
  PIN kv_d[54]
    DIRECTION OUTPUT ;
    USE SIGNAL ;
    PORT
      LAYER M5 ;
        RECT  13.632 0 13.656 0.084 ;
    END
  END kv_d[54]
  PIN kv_d[55]
    DIRECTION OUTPUT ;
    USE SIGNAL ;
    PORT
      LAYER M5 ;
        RECT  13.872 0 13.896 0.084 ;
    END
  END kv_d[55]
  PIN kv_d[56]
    DIRECTION OUTPUT ;
    USE SIGNAL ;
    PORT
      LAYER M5 ;
        RECT  14.112 0 14.136 0.084 ;
    END
  END kv_d[56]
  PIN kv_d[57]
    DIRECTION OUTPUT ;
    USE SIGNAL ;
    PORT
      LAYER M5 ;
        RECT  14.352 0 14.376 0.084 ;
    END
  END kv_d[57]
  PIN kv_d[58]
    DIRECTION OUTPUT ;
    USE SIGNAL ;
    PORT
      LAYER M5 ;
        RECT  14.592 0 14.616 0.084 ;
    END
  END kv_d[58]
  PIN kv_d[59]
    DIRECTION OUTPUT ;
    USE SIGNAL ;
    PORT
      LAYER M5 ;
        RECT  14.784 0 14.808 0.084 ;
    END
  END kv_d[59]
  PIN kv_d[5]
    DIRECTION OUTPUT ;
    USE SIGNAL ;
    PORT
      LAYER M5 ;
        RECT  2.256 0 2.28 0.084 ;
    END
  END kv_d[5]
  PIN kv_d[60]
    DIRECTION OUTPUT ;
    USE SIGNAL ;
    PORT
      LAYER M5 ;
        RECT  15.024 0 15.048 0.084 ;
    END
  END kv_d[60]
  PIN kv_d[61]
    DIRECTION OUTPUT ;
    USE SIGNAL ;
    PORT
      LAYER M5 ;
        RECT  15.264 0 15.288 0.084 ;
    END
  END kv_d[61]
  PIN kv_d[62]
    DIRECTION OUTPUT ;
    USE SIGNAL ;
    PORT
      LAYER M5 ;
        RECT  15.504 0 15.528 0.084 ;
    END
  END kv_d[62]
  PIN kv_d[63]
    DIRECTION OUTPUT ;
    USE SIGNAL ;
    PORT
      LAYER M5 ;
        RECT  15.744 0 15.768 0.084 ;
    END
  END kv_d[63]
  PIN kv_d[64]
    DIRECTION OUTPUT ;
    USE SIGNAL ;
    PORT
      LAYER M5 ;
        RECT  15.984 0 16.008 0.084 ;
    END
  END kv_d[64]
  PIN kv_d[65]
    DIRECTION OUTPUT ;
    USE SIGNAL ;
    PORT
      LAYER M5 ;
        RECT  16.224 0 16.248 0.084 ;
    END
  END kv_d[65]
  PIN kv_d[66]
    DIRECTION OUTPUT ;
    USE SIGNAL ;
    PORT
      LAYER M5 ;
        RECT  16.416 0 16.44 0.084 ;
    END
  END kv_d[66]
  PIN kv_d[67]
    DIRECTION OUTPUT ;
    USE SIGNAL ;
    PORT
      LAYER M5 ;
        RECT  16.656 0 16.68 0.084 ;
    END
  END kv_d[67]
  PIN kv_d[68]
    DIRECTION OUTPUT ;
    USE SIGNAL ;
    PORT
      LAYER M5 ;
        RECT  16.896 0 16.92 0.084 ;
    END
  END kv_d[68]
  PIN kv_d[69]
    DIRECTION OUTPUT ;
    USE SIGNAL ;
    PORT
      LAYER M5 ;
        RECT  17.136 0 17.16 0.084 ;
    END
  END kv_d[69]
  PIN kv_d[6]
    DIRECTION OUTPUT ;
    USE SIGNAL ;
    PORT
      LAYER M5 ;
        RECT  2.496 0 2.52 0.084 ;
    END
  END kv_d[6]
  PIN kv_d[70]
    DIRECTION OUTPUT ;
    USE SIGNAL ;
    PORT
      LAYER M5 ;
        RECT  17.376 0 17.4 0.084 ;
    END
  END kv_d[70]
  PIN kv_d[71]
    DIRECTION OUTPUT ;
    USE SIGNAL ;
    PORT
      LAYER M5 ;
        RECT  17.616 0 17.64 0.084 ;
    END
  END kv_d[71]
  PIN kv_d[72]
    DIRECTION OUTPUT ;
    USE SIGNAL ;
    PORT
      LAYER M5 ;
        RECT  17.808 0 17.832 0.084 ;
    END
  END kv_d[72]
  PIN kv_d[73]
    DIRECTION OUTPUT ;
    USE SIGNAL ;
    PORT
      LAYER M5 ;
        RECT  18.048 0 18.072 0.084 ;
    END
  END kv_d[73]
  PIN kv_d[74]
    DIRECTION OUTPUT ;
    USE SIGNAL ;
    PORT
      LAYER M5 ;
        RECT  18.288 0 18.312 0.084 ;
    END
  END kv_d[74]
  PIN kv_d[75]
    DIRECTION OUTPUT ;
    USE SIGNAL ;
    PORT
      LAYER M5 ;
        RECT  18.528 0 18.552 0.084 ;
    END
  END kv_d[75]
  PIN kv_d[76]
    DIRECTION OUTPUT ;
    USE SIGNAL ;
    PORT
      LAYER M5 ;
        RECT  18.768 0 18.792 0.084 ;
    END
  END kv_d[76]
  PIN kv_d[77]
    DIRECTION OUTPUT ;
    USE SIGNAL ;
    PORT
      LAYER M5 ;
        RECT  19.008 0 19.032 0.084 ;
    END
  END kv_d[77]
  PIN kv_d[78]
    DIRECTION OUTPUT ;
    USE SIGNAL ;
    PORT
      LAYER M5 ;
        RECT  19.2 0 19.224 0.084 ;
    END
  END kv_d[78]
  PIN kv_d[79]
    DIRECTION OUTPUT ;
    USE SIGNAL ;
    PORT
      LAYER M5 ;
        RECT  19.44 0 19.464 0.084 ;
    END
  END kv_d[79]
  PIN kv_d[7]
    DIRECTION OUTPUT ;
    USE SIGNAL ;
    PORT
      LAYER M5 ;
        RECT  2.736 0 2.76 0.084 ;
    END
  END kv_d[7]
  PIN kv_d[80]
    DIRECTION OUTPUT ;
    USE SIGNAL ;
    PORT
      LAYER M5 ;
        RECT  19.68 0 19.704 0.084 ;
    END
  END kv_d[80]
  PIN kv_d[81]
    DIRECTION OUTPUT ;
    USE SIGNAL ;
    PORT
      LAYER M5 ;
        RECT  19.92 0 19.944 0.084 ;
    END
  END kv_d[81]
  PIN kv_d[82]
    DIRECTION OUTPUT ;
    USE SIGNAL ;
    PORT
      LAYER M5 ;
        RECT  20.16 0 20.184 0.084 ;
    END
  END kv_d[82]
  PIN kv_d[83]
    DIRECTION OUTPUT ;
    USE SIGNAL ;
    PORT
      LAYER M5 ;
        RECT  20.4 0 20.424 0.084 ;
    END
  END kv_d[83]
  PIN kv_d[84]
    DIRECTION OUTPUT ;
    USE SIGNAL ;
    PORT
      LAYER M5 ;
        RECT  20.592 0 20.616 0.084 ;
    END
  END kv_d[84]
  PIN kv_d[85]
    DIRECTION OUTPUT ;
    USE SIGNAL ;
    PORT
      LAYER M5 ;
        RECT  20.832 0 20.856 0.084 ;
    END
  END kv_d[85]
  PIN kv_d[86]
    DIRECTION OUTPUT ;
    USE SIGNAL ;
    PORT
      LAYER M5 ;
        RECT  21.072 0 21.096 0.084 ;
    END
  END kv_d[86]
  PIN kv_d[87]
    DIRECTION OUTPUT ;
    USE SIGNAL ;
    PORT
      LAYER M5 ;
        RECT  21.312 0 21.336 0.084 ;
    END
  END kv_d[87]
  PIN kv_d[88]
    DIRECTION OUTPUT ;
    USE SIGNAL ;
    PORT
      LAYER M5 ;
        RECT  21.552 0 21.576 0.084 ;
    END
  END kv_d[88]
  PIN kv_d[89]
    DIRECTION OUTPUT ;
    USE SIGNAL ;
    PORT
      LAYER M5 ;
        RECT  21.792 0 21.816 0.084 ;
    END
  END kv_d[89]
  PIN kv_d[8]
    DIRECTION OUTPUT ;
    USE SIGNAL ;
    PORT
      LAYER M5 ;
        RECT  2.976 0 3 0.084 ;
    END
  END kv_d[8]
  PIN kv_d[90]
    DIRECTION OUTPUT ;
    USE SIGNAL ;
    PORT
      LAYER M5 ;
        RECT  21.984 0 22.008 0.084 ;
    END
  END kv_d[90]
  PIN kv_d[91]
    DIRECTION OUTPUT ;
    USE SIGNAL ;
    PORT
      LAYER M5 ;
        RECT  22.224 0 22.248 0.084 ;
    END
  END kv_d[91]
  PIN kv_d[92]
    DIRECTION OUTPUT ;
    USE SIGNAL ;
    PORT
      LAYER M5 ;
        RECT  22.464 0 22.488 0.084 ;
    END
  END kv_d[92]
  PIN kv_d[93]
    DIRECTION OUTPUT ;
    USE SIGNAL ;
    PORT
      LAYER M5 ;
        RECT  22.704 0 22.728 0.084 ;
    END
  END kv_d[93]
  PIN kv_d[94]
    DIRECTION OUTPUT ;
    USE SIGNAL ;
    PORT
      LAYER M5 ;
        RECT  22.944 0 22.968 0.084 ;
    END
  END kv_d[94]
  PIN kv_d[95]
    DIRECTION OUTPUT ;
    USE SIGNAL ;
    PORT
      LAYER M5 ;
        RECT  23.184 0 23.208 0.084 ;
    END
  END kv_d[95]
  PIN kv_d[96]
    DIRECTION OUTPUT ;
    USE SIGNAL ;
    PORT
      LAYER M5 ;
        RECT  23.424 0 23.448 0.084 ;
    END
  END kv_d[96]
  PIN kv_d[97]
    DIRECTION OUTPUT ;
    USE SIGNAL ;
    PORT
      LAYER M5 ;
        RECT  23.616 0 23.64 0.084 ;
    END
  END kv_d[97]
  PIN kv_d[98]
    DIRECTION OUTPUT ;
    USE SIGNAL ;
    PORT
      LAYER M5 ;
        RECT  23.856 0 23.88 0.084 ;
    END
  END kv_d[98]
  PIN kv_d[99]
    DIRECTION OUTPUT ;
    USE SIGNAL ;
    PORT
      LAYER M5 ;
        RECT  24.096 0 24.12 0.084 ;
    END
  END kv_d[99]
  PIN kv_d[9]
    DIRECTION OUTPUT ;
    USE SIGNAL ;
    PORT
      LAYER M5 ;
        RECT  3.216 0 3.24 0.084 ;
    END
  END kv_d[9]
  PIN kv_v
    DIRECTION OUTPUT ;
    USE SIGNAL ;
    PORT
      LAYER M5 ;
        RECT  68.016 0 68.04 0.084 ;
    END
  END kv_v
  PIN kw_di[0]
    DIRECTION INPUT ;
    USE SIGNAL ;
    PORT
      LAYER M4 ;
        RECT  0 1.536 0.084 1.56 ;
    END
  END kw_di[0]
  PIN kw_di[100]
    DIRECTION INPUT ;
    USE SIGNAL ;
    PORT
      LAYER M4 ;
        RECT  0 16.608 0.084 16.632 ;
    END
  END kw_di[100]
  PIN kw_di[101]
    DIRECTION INPUT ;
    USE SIGNAL ;
    PORT
      LAYER M4 ;
        RECT  0 16.752 0.084 16.776 ;
    END
  END kw_di[101]
  PIN kw_di[102]
    DIRECTION INPUT ;
    USE SIGNAL ;
    PORT
      LAYER M4 ;
        RECT  0 16.896 0.084 16.92 ;
    END
  END kw_di[102]
  PIN kw_di[103]
    DIRECTION INPUT ;
    USE SIGNAL ;
    PORT
      LAYER M4 ;
        RECT  0 17.04 0.084 17.064 ;
    END
  END kw_di[103]
  PIN kw_di[104]
    DIRECTION INPUT ;
    USE SIGNAL ;
    PORT
      LAYER M4 ;
        RECT  0 17.184 0.084 17.208 ;
    END
  END kw_di[104]
  PIN kw_di[105]
    DIRECTION INPUT ;
    USE SIGNAL ;
    PORT
      LAYER M4 ;
        RECT  0 17.328 0.084 17.352 ;
    END
  END kw_di[105]
  PIN kw_di[106]
    DIRECTION INPUT ;
    USE SIGNAL ;
    PORT
      LAYER M4 ;
        RECT  0 17.472 0.084 17.496 ;
    END
  END kw_di[106]
  PIN kw_di[107]
    DIRECTION INPUT ;
    USE SIGNAL ;
    PORT
      LAYER M4 ;
        RECT  0 17.664 0.084 17.688 ;
    END
  END kw_di[107]
  PIN kw_di[108]
    DIRECTION INPUT ;
    USE SIGNAL ;
    PORT
      LAYER M4 ;
        RECT  0 17.808 0.084 17.832 ;
    END
  END kw_di[108]
  PIN kw_di[109]
    DIRECTION INPUT ;
    USE SIGNAL ;
    PORT
      LAYER M4 ;
        RECT  0 17.952 0.084 17.976 ;
    END
  END kw_di[109]
  PIN kw_di[10]
    DIRECTION INPUT ;
    USE SIGNAL ;
    PORT
      LAYER M4 ;
        RECT  0 3.024 0.084 3.048 ;
    END
  END kw_di[10]
  PIN kw_di[110]
    DIRECTION INPUT ;
    USE SIGNAL ;
    PORT
      LAYER M4 ;
        RECT  0 18.096 0.084 18.12 ;
    END
  END kw_di[110]
  PIN kw_di[111]
    DIRECTION INPUT ;
    USE SIGNAL ;
    PORT
      LAYER M4 ;
        RECT  0 18.24 0.084 18.264 ;
    END
  END kw_di[111]
  PIN kw_di[112]
    DIRECTION INPUT ;
    USE SIGNAL ;
    PORT
      LAYER M4 ;
        RECT  0 18.384 0.084 18.408 ;
    END
  END kw_di[112]
  PIN kw_di[113]
    DIRECTION INPUT ;
    USE SIGNAL ;
    PORT
      LAYER M4 ;
        RECT  0 18.528 0.084 18.552 ;
    END
  END kw_di[113]
  PIN kw_di[114]
    DIRECTION INPUT ;
    USE SIGNAL ;
    PORT
      LAYER M4 ;
        RECT  0 18.72 0.084 18.744 ;
    END
  END kw_di[114]
  PIN kw_di[115]
    DIRECTION INPUT ;
    USE SIGNAL ;
    PORT
      LAYER M4 ;
        RECT  0 18.864 0.084 18.888 ;
    END
  END kw_di[115]
  PIN kw_di[116]
    DIRECTION INPUT ;
    USE SIGNAL ;
    PORT
      LAYER M4 ;
        RECT  0 19.008 0.084 19.032 ;
    END
  END kw_di[116]
  PIN kw_di[117]
    DIRECTION INPUT ;
    USE SIGNAL ;
    PORT
      LAYER M4 ;
        RECT  0 19.152 0.084 19.176 ;
    END
  END kw_di[117]
  PIN kw_di[118]
    DIRECTION INPUT ;
    USE SIGNAL ;
    PORT
      LAYER M4 ;
        RECT  0 19.296 0.084 19.32 ;
    END
  END kw_di[118]
  PIN kw_di[119]
    DIRECTION INPUT ;
    USE SIGNAL ;
    PORT
      LAYER M4 ;
        RECT  0 19.44 0.084 19.464 ;
    END
  END kw_di[119]
  PIN kw_di[11]
    DIRECTION INPUT ;
    USE SIGNAL ;
    PORT
      LAYER M4 ;
        RECT  0 3.168 0.084 3.192 ;
    END
  END kw_di[11]
  PIN kw_di[120]
    DIRECTION INPUT ;
    USE SIGNAL ;
    PORT
      LAYER M4 ;
        RECT  0 19.584 0.084 19.608 ;
    END
  END kw_di[120]
  PIN kw_di[121]
    DIRECTION INPUT ;
    USE SIGNAL ;
    PORT
      LAYER M4 ;
        RECT  0 19.776 0.084 19.8 ;
    END
  END kw_di[121]
  PIN kw_di[122]
    DIRECTION INPUT ;
    USE SIGNAL ;
    PORT
      LAYER M4 ;
        RECT  0 19.92 0.084 19.944 ;
    END
  END kw_di[122]
  PIN kw_di[123]
    DIRECTION INPUT ;
    USE SIGNAL ;
    PORT
      LAYER M4 ;
        RECT  0 20.064 0.084 20.088 ;
    END
  END kw_di[123]
  PIN kw_di[124]
    DIRECTION INPUT ;
    USE SIGNAL ;
    PORT
      LAYER M4 ;
        RECT  0 20.208 0.084 20.232 ;
    END
  END kw_di[124]
  PIN kw_di[125]
    DIRECTION INPUT ;
    USE SIGNAL ;
    PORT
      LAYER M4 ;
        RECT  0 20.352 0.084 20.376 ;
    END
  END kw_di[125]
  PIN kw_di[126]
    DIRECTION INPUT ;
    USE SIGNAL ;
    PORT
      LAYER M4 ;
        RECT  0 20.496 0.084 20.52 ;
    END
  END kw_di[126]
  PIN kw_di[127]
    DIRECTION INPUT ;
    USE SIGNAL ;
    PORT
      LAYER M4 ;
        RECT  0 20.64 0.084 20.664 ;
    END
  END kw_di[127]
  PIN kw_di[128]
    DIRECTION INPUT ;
    USE SIGNAL ;
    PORT
      LAYER M4 ;
        RECT  0 20.784 0.084 20.808 ;
    END
  END kw_di[128]
  PIN kw_di[129]
    DIRECTION INPUT ;
    USE SIGNAL ;
    PORT
      LAYER M4 ;
        RECT  0 20.976 0.084 21 ;
    END
  END kw_di[129]
  PIN kw_di[12]
    DIRECTION INPUT ;
    USE SIGNAL ;
    PORT
      LAYER M4 ;
        RECT  0 3.312 0.084 3.336 ;
    END
  END kw_di[12]
  PIN kw_di[130]
    DIRECTION INPUT ;
    USE SIGNAL ;
    PORT
      LAYER M4 ;
        RECT  0 21.12 0.084 21.144 ;
    END
  END kw_di[130]
  PIN kw_di[131]
    DIRECTION INPUT ;
    USE SIGNAL ;
    PORT
      LAYER M4 ;
        RECT  0 21.264 0.084 21.288 ;
    END
  END kw_di[131]
  PIN kw_di[132]
    DIRECTION INPUT ;
    USE SIGNAL ;
    PORT
      LAYER M4 ;
        RECT  0 21.408 0.084 21.432 ;
    END
  END kw_di[132]
  PIN kw_di[133]
    DIRECTION INPUT ;
    USE SIGNAL ;
    PORT
      LAYER M4 ;
        RECT  0 21.552 0.084 21.576 ;
    END
  END kw_di[133]
  PIN kw_di[134]
    DIRECTION INPUT ;
    USE SIGNAL ;
    PORT
      LAYER M4 ;
        RECT  0 21.696 0.084 21.72 ;
    END
  END kw_di[134]
  PIN kw_di[135]
    DIRECTION INPUT ;
    USE SIGNAL ;
    PORT
      LAYER M4 ;
        RECT  0 21.84 0.084 21.864 ;
    END
  END kw_di[135]
  PIN kw_di[136]
    DIRECTION INPUT ;
    USE SIGNAL ;
    PORT
      LAYER M4 ;
        RECT  0 22.032 0.084 22.056 ;
    END
  END kw_di[136]
  PIN kw_di[137]
    DIRECTION INPUT ;
    USE SIGNAL ;
    PORT
      LAYER M4 ;
        RECT  0 22.176 0.084 22.2 ;
    END
  END kw_di[137]
  PIN kw_di[138]
    DIRECTION INPUT ;
    USE SIGNAL ;
    PORT
      LAYER M4 ;
        RECT  0 22.32 0.084 22.344 ;
    END
  END kw_di[138]
  PIN kw_di[139]
    DIRECTION INPUT ;
    USE SIGNAL ;
    PORT
      LAYER M4 ;
        RECT  0 22.464 0.084 22.488 ;
    END
  END kw_di[139]
  PIN kw_di[13]
    DIRECTION INPUT ;
    USE SIGNAL ;
    PORT
      LAYER M4 ;
        RECT  0 3.456 0.084 3.48 ;
    END
  END kw_di[13]
  PIN kw_di[140]
    DIRECTION INPUT ;
    USE SIGNAL ;
    PORT
      LAYER M4 ;
        RECT  0 22.608 0.084 22.632 ;
    END
  END kw_di[140]
  PIN kw_di[141]
    DIRECTION INPUT ;
    USE SIGNAL ;
    PORT
      LAYER M4 ;
        RECT  0 22.752 0.084 22.776 ;
    END
  END kw_di[141]
  PIN kw_di[142]
    DIRECTION INPUT ;
    USE SIGNAL ;
    PORT
      LAYER M4 ;
        RECT  0 22.896 0.084 22.92 ;
    END
  END kw_di[142]
  PIN kw_di[143]
    DIRECTION INPUT ;
    USE SIGNAL ;
    PORT
      LAYER M4 ;
        RECT  0 23.088 0.084 23.112 ;
    END
  END kw_di[143]
  PIN kw_di[144]
    DIRECTION INPUT ;
    USE SIGNAL ;
    PORT
      LAYER M4 ;
        RECT  0 23.232 0.084 23.256 ;
    END
  END kw_di[144]
  PIN kw_di[145]
    DIRECTION INPUT ;
    USE SIGNAL ;
    PORT
      LAYER M4 ;
        RECT  0 23.376 0.084 23.4 ;
    END
  END kw_di[145]
  PIN kw_di[146]
    DIRECTION INPUT ;
    USE SIGNAL ;
    PORT
      LAYER M4 ;
        RECT  0 23.52 0.084 23.544 ;
    END
  END kw_di[146]
  PIN kw_di[147]
    DIRECTION INPUT ;
    USE SIGNAL ;
    PORT
      LAYER M4 ;
        RECT  0 23.664 0.084 23.688 ;
    END
  END kw_di[147]
  PIN kw_di[148]
    DIRECTION INPUT ;
    USE SIGNAL ;
    PORT
      LAYER M4 ;
        RECT  0 23.808 0.084 23.832 ;
    END
  END kw_di[148]
  PIN kw_di[149]
    DIRECTION INPUT ;
    USE SIGNAL ;
    PORT
      LAYER M4 ;
        RECT  0 23.952 0.084 23.976 ;
    END
  END kw_di[149]
  PIN kw_di[14]
    DIRECTION INPUT ;
    USE SIGNAL ;
    PORT
      LAYER M4 ;
        RECT  0 3.648 0.084 3.672 ;
    END
  END kw_di[14]
  PIN kw_di[150]
    DIRECTION INPUT ;
    USE SIGNAL ;
    PORT
      LAYER M4 ;
        RECT  0 24.144 0.084 24.168 ;
    END
  END kw_di[150]
  PIN kw_di[151]
    DIRECTION INPUT ;
    USE SIGNAL ;
    PORT
      LAYER M4 ;
        RECT  0 24.288 0.084 24.312 ;
    END
  END kw_di[151]
  PIN kw_di[152]
    DIRECTION INPUT ;
    USE SIGNAL ;
    PORT
      LAYER M4 ;
        RECT  0 24.432 0.084 24.456 ;
    END
  END kw_di[152]
  PIN kw_di[153]
    DIRECTION INPUT ;
    USE SIGNAL ;
    PORT
      LAYER M4 ;
        RECT  0 24.576 0.084 24.6 ;
    END
  END kw_di[153]
  PIN kw_di[154]
    DIRECTION INPUT ;
    USE SIGNAL ;
    PORT
      LAYER M4 ;
        RECT  0 24.72 0.084 24.744 ;
    END
  END kw_di[154]
  PIN kw_di[155]
    DIRECTION INPUT ;
    USE SIGNAL ;
    PORT
      LAYER M4 ;
        RECT  0 24.864 0.084 24.888 ;
    END
  END kw_di[155]
  PIN kw_di[156]
    DIRECTION INPUT ;
    USE SIGNAL ;
    PORT
      LAYER M4 ;
        RECT  0 25.008 0.084 25.032 ;
    END
  END kw_di[156]
  PIN kw_di[157]
    DIRECTION INPUT ;
    USE SIGNAL ;
    PORT
      LAYER M4 ;
        RECT  0 25.2 0.084 25.224 ;
    END
  END kw_di[157]
  PIN kw_di[158]
    DIRECTION INPUT ;
    USE SIGNAL ;
    PORT
      LAYER M4 ;
        RECT  0 25.344 0.084 25.368 ;
    END
  END kw_di[158]
  PIN kw_di[159]
    DIRECTION INPUT ;
    USE SIGNAL ;
    PORT
      LAYER M4 ;
        RECT  0 25.488 0.084 25.512 ;
    END
  END kw_di[159]
  PIN kw_di[15]
    DIRECTION INPUT ;
    USE SIGNAL ;
    PORT
      LAYER M4 ;
        RECT  0 3.792 0.084 3.816 ;
    END
  END kw_di[15]
  PIN kw_di[160]
    DIRECTION INPUT ;
    USE SIGNAL ;
    PORT
      LAYER M4 ;
        RECT  0 25.632 0.084 25.656 ;
    END
  END kw_di[160]
  PIN kw_di[161]
    DIRECTION INPUT ;
    USE SIGNAL ;
    PORT
      LAYER M4 ;
        RECT  0 25.776 0.084 25.8 ;
    END
  END kw_di[161]
  PIN kw_di[162]
    DIRECTION INPUT ;
    USE SIGNAL ;
    PORT
      LAYER M4 ;
        RECT  0 25.92 0.084 25.944 ;
    END
  END kw_di[162]
  PIN kw_di[163]
    DIRECTION INPUT ;
    USE SIGNAL ;
    PORT
      LAYER M4 ;
        RECT  0 26.064 0.084 26.088 ;
    END
  END kw_di[163]
  PIN kw_di[164]
    DIRECTION INPUT ;
    USE SIGNAL ;
    PORT
      LAYER M4 ;
        RECT  0 26.256 0.084 26.28 ;
    END
  END kw_di[164]
  PIN kw_di[165]
    DIRECTION INPUT ;
    USE SIGNAL ;
    PORT
      LAYER M4 ;
        RECT  0 26.4 0.084 26.424 ;
    END
  END kw_di[165]
  PIN kw_di[166]
    DIRECTION INPUT ;
    USE SIGNAL ;
    PORT
      LAYER M4 ;
        RECT  0 26.544 0.084 26.568 ;
    END
  END kw_di[166]
  PIN kw_di[167]
    DIRECTION INPUT ;
    USE SIGNAL ;
    PORT
      LAYER M4 ;
        RECT  0 26.688 0.084 26.712 ;
    END
  END kw_di[167]
  PIN kw_di[168]
    DIRECTION INPUT ;
    USE SIGNAL ;
    PORT
      LAYER M4 ;
        RECT  0 26.832 0.084 26.856 ;
    END
  END kw_di[168]
  PIN kw_di[169]
    DIRECTION INPUT ;
    USE SIGNAL ;
    PORT
      LAYER M4 ;
        RECT  0 26.976 0.084 27 ;
    END
  END kw_di[169]
  PIN kw_di[16]
    DIRECTION INPUT ;
    USE SIGNAL ;
    PORT
      LAYER M4 ;
        RECT  0 3.936 0.084 3.96 ;
    END
  END kw_di[16]
  PIN kw_di[170]
    DIRECTION INPUT ;
    USE SIGNAL ;
    PORT
      LAYER M4 ;
        RECT  0 27.12 0.084 27.144 ;
    END
  END kw_di[170]
  PIN kw_di[171]
    DIRECTION INPUT ;
    USE SIGNAL ;
    PORT
      LAYER M4 ;
        RECT  0 27.312 0.084 27.336 ;
    END
  END kw_di[171]
  PIN kw_di[172]
    DIRECTION INPUT ;
    USE SIGNAL ;
    PORT
      LAYER M4 ;
        RECT  0 27.456 0.084 27.48 ;
    END
  END kw_di[172]
  PIN kw_di[173]
    DIRECTION INPUT ;
    USE SIGNAL ;
    PORT
      LAYER M4 ;
        RECT  0 27.6 0.084 27.624 ;
    END
  END kw_di[173]
  PIN kw_di[174]
    DIRECTION INPUT ;
    USE SIGNAL ;
    PORT
      LAYER M4 ;
        RECT  0 27.744 0.084 27.768 ;
    END
  END kw_di[174]
  PIN kw_di[175]
    DIRECTION INPUT ;
    USE SIGNAL ;
    PORT
      LAYER M4 ;
        RECT  0 27.888 0.084 27.912 ;
    END
  END kw_di[175]
  PIN kw_di[176]
    DIRECTION INPUT ;
    USE SIGNAL ;
    PORT
      LAYER M4 ;
        RECT  0 28.032 0.084 28.056 ;
    END
  END kw_di[176]
  PIN kw_di[177]
    DIRECTION INPUT ;
    USE SIGNAL ;
    PORT
      LAYER M4 ;
        RECT  0 28.176 0.084 28.2 ;
    END
  END kw_di[177]
  PIN kw_di[178]
    DIRECTION INPUT ;
    USE SIGNAL ;
    PORT
      LAYER M4 ;
        RECT  0 28.32 0.084 28.344 ;
    END
  END kw_di[178]
  PIN kw_di[179]
    DIRECTION INPUT ;
    USE SIGNAL ;
    PORT
      LAYER M4 ;
        RECT  0 28.512 0.084 28.536 ;
    END
  END kw_di[179]
  PIN kw_di[17]
    DIRECTION INPUT ;
    USE SIGNAL ;
    PORT
      LAYER M4 ;
        RECT  0 4.08 0.084 4.104 ;
    END
  END kw_di[17]
  PIN kw_di[180]
    DIRECTION INPUT ;
    USE SIGNAL ;
    PORT
      LAYER M4 ;
        RECT  0 28.656 0.084 28.68 ;
    END
  END kw_di[180]
  PIN kw_di[181]
    DIRECTION INPUT ;
    USE SIGNAL ;
    PORT
      LAYER M4 ;
        RECT  0 28.8 0.084 28.824 ;
    END
  END kw_di[181]
  PIN kw_di[182]
    DIRECTION INPUT ;
    USE SIGNAL ;
    PORT
      LAYER M4 ;
        RECT  0 28.944 0.084 28.968 ;
    END
  END kw_di[182]
  PIN kw_di[183]
    DIRECTION INPUT ;
    USE SIGNAL ;
    PORT
      LAYER M4 ;
        RECT  0 29.088 0.084 29.112 ;
    END
  END kw_di[183]
  PIN kw_di[184]
    DIRECTION INPUT ;
    USE SIGNAL ;
    PORT
      LAYER M4 ;
        RECT  0 29.232 0.084 29.256 ;
    END
  END kw_di[184]
  PIN kw_di[185]
    DIRECTION INPUT ;
    USE SIGNAL ;
    PORT
      LAYER M4 ;
        RECT  0 29.376 0.084 29.4 ;
    END
  END kw_di[185]
  PIN kw_di[186]
    DIRECTION INPUT ;
    USE SIGNAL ;
    PORT
      LAYER M4 ;
        RECT  0 29.568 0.084 29.592 ;
    END
  END kw_di[186]
  PIN kw_di[187]
    DIRECTION INPUT ;
    USE SIGNAL ;
    PORT
      LAYER M4 ;
        RECT  0 29.712 0.084 29.736 ;
    END
  END kw_di[187]
  PIN kw_di[188]
    DIRECTION INPUT ;
    USE SIGNAL ;
    PORT
      LAYER M4 ;
        RECT  0 29.856 0.084 29.88 ;
    END
  END kw_di[188]
  PIN kw_di[189]
    DIRECTION INPUT ;
    USE SIGNAL ;
    PORT
      LAYER M4 ;
        RECT  0 30 0.084 30.024 ;
    END
  END kw_di[189]
  PIN kw_di[18]
    DIRECTION INPUT ;
    USE SIGNAL ;
    PORT
      LAYER M4 ;
        RECT  0 4.224 0.084 4.248 ;
    END
  END kw_di[18]
  PIN kw_di[190]
    DIRECTION INPUT ;
    USE SIGNAL ;
    PORT
      LAYER M4 ;
        RECT  0 30.144 0.084 30.168 ;
    END
  END kw_di[190]
  PIN kw_di[191]
    DIRECTION INPUT ;
    USE SIGNAL ;
    PORT
      LAYER M4 ;
        RECT  0 30.288 0.084 30.312 ;
    END
  END kw_di[191]
  PIN kw_di[192]
    DIRECTION INPUT ;
    USE SIGNAL ;
    PORT
      LAYER M4 ;
        RECT  0 30.432 0.084 30.456 ;
    END
  END kw_di[192]
  PIN kw_di[193]
    DIRECTION INPUT ;
    USE SIGNAL ;
    PORT
      LAYER M4 ;
        RECT  0 30.624 0.084 30.648 ;
    END
  END kw_di[193]
  PIN kw_di[194]
    DIRECTION INPUT ;
    USE SIGNAL ;
    PORT
      LAYER M4 ;
        RECT  0 30.768 0.084 30.792 ;
    END
  END kw_di[194]
  PIN kw_di[195]
    DIRECTION INPUT ;
    USE SIGNAL ;
    PORT
      LAYER M4 ;
        RECT  0 30.912 0.084 30.936 ;
    END
  END kw_di[195]
  PIN kw_di[196]
    DIRECTION INPUT ;
    USE SIGNAL ;
    PORT
      LAYER M4 ;
        RECT  0 31.056 0.084 31.08 ;
    END
  END kw_di[196]
  PIN kw_di[197]
    DIRECTION INPUT ;
    USE SIGNAL ;
    PORT
      LAYER M4 ;
        RECT  0 31.2 0.084 31.224 ;
    END
  END kw_di[197]
  PIN kw_di[198]
    DIRECTION INPUT ;
    USE SIGNAL ;
    PORT
      LAYER M4 ;
        RECT  0 31.344 0.084 31.368 ;
    END
  END kw_di[198]
  PIN kw_di[199]
    DIRECTION INPUT ;
    USE SIGNAL ;
    PORT
      LAYER M4 ;
        RECT  0 31.488 0.084 31.512 ;
    END
  END kw_di[199]
  PIN kw_di[19]
    DIRECTION INPUT ;
    USE SIGNAL ;
    PORT
      LAYER M4 ;
        RECT  0 4.368 0.084 4.392 ;
    END
  END kw_di[19]
  PIN kw_di[1]
    DIRECTION INPUT ;
    USE SIGNAL ;
    PORT
      LAYER M4 ;
        RECT  0 1.68 0.084 1.704 ;
    END
  END kw_di[1]
  PIN kw_di[200]
    DIRECTION INPUT ;
    USE SIGNAL ;
    PORT
      LAYER M4 ;
        RECT  0 31.68 0.084 31.704 ;
    END
  END kw_di[200]
  PIN kw_di[201]
    DIRECTION INPUT ;
    USE SIGNAL ;
    PORT
      LAYER M4 ;
        RECT  0 31.824 0.084 31.848 ;
    END
  END kw_di[201]
  PIN kw_di[202]
    DIRECTION INPUT ;
    USE SIGNAL ;
    PORT
      LAYER M4 ;
        RECT  0 31.968 0.084 31.992 ;
    END
  END kw_di[202]
  PIN kw_di[203]
    DIRECTION INPUT ;
    USE SIGNAL ;
    PORT
      LAYER M4 ;
        RECT  0 32.112 0.084 32.136 ;
    END
  END kw_di[203]
  PIN kw_di[204]
    DIRECTION INPUT ;
    USE SIGNAL ;
    PORT
      LAYER M4 ;
        RECT  0 32.256 0.084 32.28 ;
    END
  END kw_di[204]
  PIN kw_di[205]
    DIRECTION INPUT ;
    USE SIGNAL ;
    PORT
      LAYER M4 ;
        RECT  0 32.4 0.084 32.424 ;
    END
  END kw_di[205]
  PIN kw_di[206]
    DIRECTION INPUT ;
    USE SIGNAL ;
    PORT
      LAYER M4 ;
        RECT  0 32.544 0.084 32.568 ;
    END
  END kw_di[206]
  PIN kw_di[207]
    DIRECTION INPUT ;
    USE SIGNAL ;
    PORT
      LAYER M4 ;
        RECT  0 32.736 0.084 32.76 ;
    END
  END kw_di[207]
  PIN kw_di[208]
    DIRECTION INPUT ;
    USE SIGNAL ;
    PORT
      LAYER M4 ;
        RECT  0 32.88 0.084 32.904 ;
    END
  END kw_di[208]
  PIN kw_di[209]
    DIRECTION INPUT ;
    USE SIGNAL ;
    PORT
      LAYER M4 ;
        RECT  0 33.024 0.084 33.048 ;
    END
  END kw_di[209]
  PIN kw_di[20]
    DIRECTION INPUT ;
    USE SIGNAL ;
    PORT
      LAYER M4 ;
        RECT  0 4.512 0.084 4.536 ;
    END
  END kw_di[20]
  PIN kw_di[210]
    DIRECTION INPUT ;
    USE SIGNAL ;
    PORT
      LAYER M4 ;
        RECT  0 33.168 0.084 33.192 ;
    END
  END kw_di[210]
  PIN kw_di[211]
    DIRECTION INPUT ;
    USE SIGNAL ;
    PORT
      LAYER M4 ;
        RECT  0 33.312 0.084 33.336 ;
    END
  END kw_di[211]
  PIN kw_di[212]
    DIRECTION INPUT ;
    USE SIGNAL ;
    PORT
      LAYER M4 ;
        RECT  0 33.456 0.084 33.48 ;
    END
  END kw_di[212]
  PIN kw_di[213]
    DIRECTION INPUT ;
    USE SIGNAL ;
    PORT
      LAYER M4 ;
        RECT  0 33.6 0.084 33.624 ;
    END
  END kw_di[213]
  PIN kw_di[214]
    DIRECTION INPUT ;
    USE SIGNAL ;
    PORT
      LAYER M4 ;
        RECT  0 33.792 0.084 33.816 ;
    END
  END kw_di[214]
  PIN kw_di[215]
    DIRECTION INPUT ;
    USE SIGNAL ;
    PORT
      LAYER M4 ;
        RECT  0 33.936 0.084 33.96 ;
    END
  END kw_di[215]
  PIN kw_di[216]
    DIRECTION INPUT ;
    USE SIGNAL ;
    PORT
      LAYER M4 ;
        RECT  0 34.08 0.084 34.104 ;
    END
  END kw_di[216]
  PIN kw_di[217]
    DIRECTION INPUT ;
    USE SIGNAL ;
    PORT
      LAYER M4 ;
        RECT  0 34.224 0.084 34.248 ;
    END
  END kw_di[217]
  PIN kw_di[218]
    DIRECTION INPUT ;
    USE SIGNAL ;
    PORT
      LAYER M4 ;
        RECT  0 34.368 0.084 34.392 ;
    END
  END kw_di[218]
  PIN kw_di[219]
    DIRECTION INPUT ;
    USE SIGNAL ;
    PORT
      LAYER M4 ;
        RECT  0 34.512 0.084 34.536 ;
    END
  END kw_di[219]
  PIN kw_di[21]
    DIRECTION INPUT ;
    USE SIGNAL ;
    PORT
      LAYER M4 ;
        RECT  0 4.704 0.084 4.728 ;
    END
  END kw_di[21]
  PIN kw_di[220]
    DIRECTION INPUT ;
    USE SIGNAL ;
    PORT
      LAYER M4 ;
        RECT  0 34.656 0.084 34.68 ;
    END
  END kw_di[220]
  PIN kw_di[221]
    DIRECTION INPUT ;
    USE SIGNAL ;
    PORT
      LAYER M4 ;
        RECT  0 34.848 0.084 34.872 ;
    END
  END kw_di[221]
  PIN kw_di[222]
    DIRECTION INPUT ;
    USE SIGNAL ;
    PORT
      LAYER M4 ;
        RECT  0 34.992 0.084 35.016 ;
    END
  END kw_di[222]
  PIN kw_di[223]
    DIRECTION INPUT ;
    USE SIGNAL ;
    PORT
      LAYER M4 ;
        RECT  0 35.136 0.084 35.16 ;
    END
  END kw_di[223]
  PIN kw_di[224]
    DIRECTION INPUT ;
    USE SIGNAL ;
    PORT
      LAYER M4 ;
        RECT  0 35.28 0.084 35.304 ;
    END
  END kw_di[224]
  PIN kw_di[225]
    DIRECTION INPUT ;
    USE SIGNAL ;
    PORT
      LAYER M4 ;
        RECT  0 35.424 0.084 35.448 ;
    END
  END kw_di[225]
  PIN kw_di[226]
    DIRECTION INPUT ;
    USE SIGNAL ;
    PORT
      LAYER M4 ;
        RECT  0 35.568 0.084 35.592 ;
    END
  END kw_di[226]
  PIN kw_di[227]
    DIRECTION INPUT ;
    USE SIGNAL ;
    PORT
      LAYER M4 ;
        RECT  0 35.712 0.084 35.736 ;
    END
  END kw_di[227]
  PIN kw_di[228]
    DIRECTION INPUT ;
    USE SIGNAL ;
    PORT
      LAYER M4 ;
        RECT  0 35.856 0.084 35.88 ;
    END
  END kw_di[228]
  PIN kw_di[229]
    DIRECTION INPUT ;
    USE SIGNAL ;
    PORT
      LAYER M4 ;
        RECT  0 36.048 0.084 36.072 ;
    END
  END kw_di[229]
  PIN kw_di[22]
    DIRECTION INPUT ;
    USE SIGNAL ;
    PORT
      LAYER M4 ;
        RECT  0 4.848 0.084 4.872 ;
    END
  END kw_di[22]
  PIN kw_di[230]
    DIRECTION INPUT ;
    USE SIGNAL ;
    PORT
      LAYER M4 ;
        RECT  0 36.192 0.084 36.216 ;
    END
  END kw_di[230]
  PIN kw_di[231]
    DIRECTION INPUT ;
    USE SIGNAL ;
    PORT
      LAYER M4 ;
        RECT  0 36.336 0.084 36.36 ;
    END
  END kw_di[231]
  PIN kw_di[232]
    DIRECTION INPUT ;
    USE SIGNAL ;
    PORT
      LAYER M4 ;
        RECT  0 36.48 0.084 36.504 ;
    END
  END kw_di[232]
  PIN kw_di[233]
    DIRECTION INPUT ;
    USE SIGNAL ;
    PORT
      LAYER M4 ;
        RECT  0 36.624 0.084 36.648 ;
    END
  END kw_di[233]
  PIN kw_di[234]
    DIRECTION INPUT ;
    USE SIGNAL ;
    PORT
      LAYER M4 ;
        RECT  0 36.768 0.084 36.792 ;
    END
  END kw_di[234]
  PIN kw_di[235]
    DIRECTION INPUT ;
    USE SIGNAL ;
    PORT
      LAYER M4 ;
        RECT  0 36.912 0.084 36.936 ;
    END
  END kw_di[235]
  PIN kw_di[236]
    DIRECTION INPUT ;
    USE SIGNAL ;
    PORT
      LAYER M4 ;
        RECT  0 37.104 0.084 37.128 ;
    END
  END kw_di[236]
  PIN kw_di[237]
    DIRECTION INPUT ;
    USE SIGNAL ;
    PORT
      LAYER M4 ;
        RECT  0 37.248 0.084 37.272 ;
    END
  END kw_di[237]
  PIN kw_di[238]
    DIRECTION INPUT ;
    USE SIGNAL ;
    PORT
      LAYER M4 ;
        RECT  0 37.392 0.084 37.416 ;
    END
  END kw_di[238]
  PIN kw_di[239]
    DIRECTION INPUT ;
    USE SIGNAL ;
    PORT
      LAYER M4 ;
        RECT  0 37.536 0.084 37.56 ;
    END
  END kw_di[239]
  PIN kw_di[23]
    DIRECTION INPUT ;
    USE SIGNAL ;
    PORT
      LAYER M4 ;
        RECT  0 4.992 0.084 5.016 ;
    END
  END kw_di[23]
  PIN kw_di[240]
    DIRECTION INPUT ;
    USE SIGNAL ;
    PORT
      LAYER M4 ;
        RECT  0 37.68 0.084 37.704 ;
    END
  END kw_di[240]
  PIN kw_di[241]
    DIRECTION INPUT ;
    USE SIGNAL ;
    PORT
      LAYER M4 ;
        RECT  0 37.824 0.084 37.848 ;
    END
  END kw_di[241]
  PIN kw_di[242]
    DIRECTION INPUT ;
    USE SIGNAL ;
    PORT
      LAYER M4 ;
        RECT  0 37.968 0.084 37.992 ;
    END
  END kw_di[242]
  PIN kw_di[243]
    DIRECTION INPUT ;
    USE SIGNAL ;
    PORT
      LAYER M4 ;
        RECT  0 38.16 0.084 38.184 ;
    END
  END kw_di[243]
  PIN kw_di[244]
    DIRECTION INPUT ;
    USE SIGNAL ;
    PORT
      LAYER M4 ;
        RECT  0 38.304 0.084 38.328 ;
    END
  END kw_di[244]
  PIN kw_di[245]
    DIRECTION INPUT ;
    USE SIGNAL ;
    PORT
      LAYER M4 ;
        RECT  0 38.448 0.084 38.472 ;
    END
  END kw_di[245]
  PIN kw_di[246]
    DIRECTION INPUT ;
    USE SIGNAL ;
    PORT
      LAYER M4 ;
        RECT  0 38.592 0.084 38.616 ;
    END
  END kw_di[246]
  PIN kw_di[247]
    DIRECTION INPUT ;
    USE SIGNAL ;
    PORT
      LAYER M4 ;
        RECT  0 38.736 0.084 38.76 ;
    END
  END kw_di[247]
  PIN kw_di[248]
    DIRECTION INPUT ;
    USE SIGNAL ;
    PORT
      LAYER M4 ;
        RECT  0 38.88 0.084 38.904 ;
    END
  END kw_di[248]
  PIN kw_di[249]
    DIRECTION INPUT ;
    USE SIGNAL ;
    PORT
      LAYER M4 ;
        RECT  0 39.024 0.084 39.048 ;
    END
  END kw_di[249]
  PIN kw_di[24]
    DIRECTION INPUT ;
    USE SIGNAL ;
    PORT
      LAYER M4 ;
        RECT  0 5.136 0.084 5.16 ;
    END
  END kw_di[24]
  PIN kw_di[250]
    DIRECTION INPUT ;
    USE SIGNAL ;
    PORT
      LAYER M4 ;
        RECT  0 39.216 0.084 39.24 ;
    END
  END kw_di[250]
  PIN kw_di[251]
    DIRECTION INPUT ;
    USE SIGNAL ;
    PORT
      LAYER M4 ;
        RECT  0 39.36 0.084 39.384 ;
    END
  END kw_di[251]
  PIN kw_di[252]
    DIRECTION INPUT ;
    USE SIGNAL ;
    PORT
      LAYER M4 ;
        RECT  0 39.504 0.084 39.528 ;
    END
  END kw_di[252]
  PIN kw_di[253]
    DIRECTION INPUT ;
    USE SIGNAL ;
    PORT
      LAYER M4 ;
        RECT  0 39.648 0.084 39.672 ;
    END
  END kw_di[253]
  PIN kw_di[254]
    DIRECTION INPUT ;
    USE SIGNAL ;
    PORT
      LAYER M4 ;
        RECT  0 39.792 0.084 39.816 ;
    END
  END kw_di[254]
  PIN kw_di[255]
    DIRECTION INPUT ;
    USE SIGNAL ;
    PORT
      LAYER M4 ;
        RECT  0 39.936 0.084 39.96 ;
    END
  END kw_di[255]
  PIN kw_di[25]
    DIRECTION INPUT ;
    USE SIGNAL ;
    PORT
      LAYER M4 ;
        RECT  0 5.28 0.084 5.304 ;
    END
  END kw_di[25]
  PIN kw_di[26]
    DIRECTION INPUT ;
    USE SIGNAL ;
    PORT
      LAYER M4 ;
        RECT  0 5.424 0.084 5.448 ;
    END
  END kw_di[26]
  PIN kw_di[27]
    DIRECTION INPUT ;
    USE SIGNAL ;
    PORT
      LAYER M4 ;
        RECT  0 5.568 0.084 5.592 ;
    END
  END kw_di[27]
  PIN kw_di[28]
    DIRECTION INPUT ;
    USE SIGNAL ;
    PORT
      LAYER M4 ;
        RECT  0 5.76 0.084 5.784 ;
    END
  END kw_di[28]
  PIN kw_di[29]
    DIRECTION INPUT ;
    USE SIGNAL ;
    PORT
      LAYER M4 ;
        RECT  0 5.904 0.084 5.928 ;
    END
  END kw_di[29]
  PIN kw_di[2]
    DIRECTION INPUT ;
    USE SIGNAL ;
    PORT
      LAYER M4 ;
        RECT  0 1.824 0.084 1.848 ;
    END
  END kw_di[2]
  PIN kw_di[30]
    DIRECTION INPUT ;
    USE SIGNAL ;
    PORT
      LAYER M4 ;
        RECT  0 6.048 0.084 6.072 ;
    END
  END kw_di[30]
  PIN kw_di[31]
    DIRECTION INPUT ;
    USE SIGNAL ;
    PORT
      LAYER M4 ;
        RECT  0 6.192 0.084 6.216 ;
    END
  END kw_di[31]
  PIN kw_di[32]
    DIRECTION INPUT ;
    USE SIGNAL ;
    PORT
      LAYER M4 ;
        RECT  0 6.336 0.084 6.36 ;
    END
  END kw_di[32]
  PIN kw_di[33]
    DIRECTION INPUT ;
    USE SIGNAL ;
    PORT
      LAYER M4 ;
        RECT  0 6.48 0.084 6.504 ;
    END
  END kw_di[33]
  PIN kw_di[34]
    DIRECTION INPUT ;
    USE SIGNAL ;
    PORT
      LAYER M4 ;
        RECT  0 6.624 0.084 6.648 ;
    END
  END kw_di[34]
  PIN kw_di[35]
    DIRECTION INPUT ;
    USE SIGNAL ;
    PORT
      LAYER M4 ;
        RECT  0 6.768 0.084 6.792 ;
    END
  END kw_di[35]
  PIN kw_di[36]
    DIRECTION INPUT ;
    USE SIGNAL ;
    PORT
      LAYER M4 ;
        RECT  0 6.96 0.084 6.984 ;
    END
  END kw_di[36]
  PIN kw_di[37]
    DIRECTION INPUT ;
    USE SIGNAL ;
    PORT
      LAYER M4 ;
        RECT  0 7.104 0.084 7.128 ;
    END
  END kw_di[37]
  PIN kw_di[38]
    DIRECTION INPUT ;
    USE SIGNAL ;
    PORT
      LAYER M4 ;
        RECT  0 7.248 0.084 7.272 ;
    END
  END kw_di[38]
  PIN kw_di[39]
    DIRECTION INPUT ;
    USE SIGNAL ;
    PORT
      LAYER M4 ;
        RECT  0 7.392 0.084 7.416 ;
    END
  END kw_di[39]
  PIN kw_di[3]
    DIRECTION INPUT ;
    USE SIGNAL ;
    PORT
      LAYER M4 ;
        RECT  0 1.968 0.084 1.992 ;
    END
  END kw_di[3]
  PIN kw_di[40]
    DIRECTION INPUT ;
    USE SIGNAL ;
    PORT
      LAYER M4 ;
        RECT  0 7.536 0.084 7.56 ;
    END
  END kw_di[40]
  PIN kw_di[41]
    DIRECTION INPUT ;
    USE SIGNAL ;
    PORT
      LAYER M4 ;
        RECT  0 7.68 0.084 7.704 ;
    END
  END kw_di[41]
  PIN kw_di[42]
    DIRECTION INPUT ;
    USE SIGNAL ;
    PORT
      LAYER M4 ;
        RECT  0 7.824 0.084 7.848 ;
    END
  END kw_di[42]
  PIN kw_di[43]
    DIRECTION INPUT ;
    USE SIGNAL ;
    PORT
      LAYER M4 ;
        RECT  0 8.016 0.084 8.04 ;
    END
  END kw_di[43]
  PIN kw_di[44]
    DIRECTION INPUT ;
    USE SIGNAL ;
    PORT
      LAYER M4 ;
        RECT  0 8.16 0.084 8.184 ;
    END
  END kw_di[44]
  PIN kw_di[45]
    DIRECTION INPUT ;
    USE SIGNAL ;
    PORT
      LAYER M4 ;
        RECT  0 8.304 0.084 8.328 ;
    END
  END kw_di[45]
  PIN kw_di[46]
    DIRECTION INPUT ;
    USE SIGNAL ;
    PORT
      LAYER M4 ;
        RECT  0 8.448 0.084 8.472 ;
    END
  END kw_di[46]
  PIN kw_di[47]
    DIRECTION INPUT ;
    USE SIGNAL ;
    PORT
      LAYER M4 ;
        RECT  0 8.592 0.084 8.616 ;
    END
  END kw_di[47]
  PIN kw_di[48]
    DIRECTION INPUT ;
    USE SIGNAL ;
    PORT
      LAYER M4 ;
        RECT  0 8.736 0.084 8.76 ;
    END
  END kw_di[48]
  PIN kw_di[49]
    DIRECTION INPUT ;
    USE SIGNAL ;
    PORT
      LAYER M4 ;
        RECT  0 8.88 0.084 8.904 ;
    END
  END kw_di[49]
  PIN kw_di[4]
    DIRECTION INPUT ;
    USE SIGNAL ;
    PORT
      LAYER M4 ;
        RECT  0 2.112 0.084 2.136 ;
    END
  END kw_di[4]
  PIN kw_di[50]
    DIRECTION INPUT ;
    USE SIGNAL ;
    PORT
      LAYER M4 ;
        RECT  0 9.072 0.084 9.096 ;
    END
  END kw_di[50]
  PIN kw_di[51]
    DIRECTION INPUT ;
    USE SIGNAL ;
    PORT
      LAYER M4 ;
        RECT  0 9.216 0.084 9.24 ;
    END
  END kw_di[51]
  PIN kw_di[52]
    DIRECTION INPUT ;
    USE SIGNAL ;
    PORT
      LAYER M4 ;
        RECT  0 9.36 0.084 9.384 ;
    END
  END kw_di[52]
  PIN kw_di[53]
    DIRECTION INPUT ;
    USE SIGNAL ;
    PORT
      LAYER M4 ;
        RECT  0 9.504 0.084 9.528 ;
    END
  END kw_di[53]
  PIN kw_di[54]
    DIRECTION INPUT ;
    USE SIGNAL ;
    PORT
      LAYER M4 ;
        RECT  0 9.648 0.084 9.672 ;
    END
  END kw_di[54]
  PIN kw_di[55]
    DIRECTION INPUT ;
    USE SIGNAL ;
    PORT
      LAYER M4 ;
        RECT  0 9.792 0.084 9.816 ;
    END
  END kw_di[55]
  PIN kw_di[56]
    DIRECTION INPUT ;
    USE SIGNAL ;
    PORT
      LAYER M4 ;
        RECT  0 9.936 0.084 9.96 ;
    END
  END kw_di[56]
  PIN kw_di[57]
    DIRECTION INPUT ;
    USE SIGNAL ;
    PORT
      LAYER M4 ;
        RECT  0 10.128 0.084 10.152 ;
    END
  END kw_di[57]
  PIN kw_di[58]
    DIRECTION INPUT ;
    USE SIGNAL ;
    PORT
      LAYER M4 ;
        RECT  0 10.272 0.084 10.296 ;
    END
  END kw_di[58]
  PIN kw_di[59]
    DIRECTION INPUT ;
    USE SIGNAL ;
    PORT
      LAYER M4 ;
        RECT  0 10.416 0.084 10.44 ;
    END
  END kw_di[59]
  PIN kw_di[5]
    DIRECTION INPUT ;
    USE SIGNAL ;
    PORT
      LAYER M4 ;
        RECT  0 2.256 0.084 2.28 ;
    END
  END kw_di[5]
  PIN kw_di[60]
    DIRECTION INPUT ;
    USE SIGNAL ;
    PORT
      LAYER M4 ;
        RECT  0 10.56 0.084 10.584 ;
    END
  END kw_di[60]
  PIN kw_di[61]
    DIRECTION INPUT ;
    USE SIGNAL ;
    PORT
      LAYER M4 ;
        RECT  0 10.704 0.084 10.728 ;
    END
  END kw_di[61]
  PIN kw_di[62]
    DIRECTION INPUT ;
    USE SIGNAL ;
    PORT
      LAYER M4 ;
        RECT  0 10.848 0.084 10.872 ;
    END
  END kw_di[62]
  PIN kw_di[63]
    DIRECTION INPUT ;
    USE SIGNAL ;
    PORT
      LAYER M4 ;
        RECT  0 10.992 0.084 11.016 ;
    END
  END kw_di[63]
  PIN kw_di[64]
    DIRECTION INPUT ;
    USE SIGNAL ;
    PORT
      LAYER M4 ;
        RECT  0 11.184 0.084 11.208 ;
    END
  END kw_di[64]
  PIN kw_di[65]
    DIRECTION INPUT ;
    USE SIGNAL ;
    PORT
      LAYER M4 ;
        RECT  0 11.328 0.084 11.352 ;
    END
  END kw_di[65]
  PIN kw_di[66]
    DIRECTION INPUT ;
    USE SIGNAL ;
    PORT
      LAYER M4 ;
        RECT  0 11.472 0.084 11.496 ;
    END
  END kw_di[66]
  PIN kw_di[67]
    DIRECTION INPUT ;
    USE SIGNAL ;
    PORT
      LAYER M4 ;
        RECT  0 11.616 0.084 11.64 ;
    END
  END kw_di[67]
  PIN kw_di[68]
    DIRECTION INPUT ;
    USE SIGNAL ;
    PORT
      LAYER M4 ;
        RECT  0 11.76 0.084 11.784 ;
    END
  END kw_di[68]
  PIN kw_di[69]
    DIRECTION INPUT ;
    USE SIGNAL ;
    PORT
      LAYER M4 ;
        RECT  0 11.904 0.084 11.928 ;
    END
  END kw_di[69]
  PIN kw_di[6]
    DIRECTION INPUT ;
    USE SIGNAL ;
    PORT
      LAYER M4 ;
        RECT  0 2.4 0.084 2.424 ;
    END
  END kw_di[6]
  PIN kw_di[70]
    DIRECTION INPUT ;
    USE SIGNAL ;
    PORT
      LAYER M4 ;
        RECT  0 12.048 0.084 12.072 ;
    END
  END kw_di[70]
  PIN kw_di[71]
    DIRECTION INPUT ;
    USE SIGNAL ;
    PORT
      LAYER M4 ;
        RECT  0 12.24 0.084 12.264 ;
    END
  END kw_di[71]
  PIN kw_di[72]
    DIRECTION INPUT ;
    USE SIGNAL ;
    PORT
      LAYER M4 ;
        RECT  0 12.384 0.084 12.408 ;
    END
  END kw_di[72]
  PIN kw_di[73]
    DIRECTION INPUT ;
    USE SIGNAL ;
    PORT
      LAYER M4 ;
        RECT  0 12.528 0.084 12.552 ;
    END
  END kw_di[73]
  PIN kw_di[74]
    DIRECTION INPUT ;
    USE SIGNAL ;
    PORT
      LAYER M4 ;
        RECT  0 12.672 0.084 12.696 ;
    END
  END kw_di[74]
  PIN kw_di[75]
    DIRECTION INPUT ;
    USE SIGNAL ;
    PORT
      LAYER M4 ;
        RECT  0 12.816 0.084 12.84 ;
    END
  END kw_di[75]
  PIN kw_di[76]
    DIRECTION INPUT ;
    USE SIGNAL ;
    PORT
      LAYER M4 ;
        RECT  0 12.96 0.084 12.984 ;
    END
  END kw_di[76]
  PIN kw_di[77]
    DIRECTION INPUT ;
    USE SIGNAL ;
    PORT
      LAYER M4 ;
        RECT  0 13.104 0.084 13.128 ;
    END
  END kw_di[77]
  PIN kw_di[78]
    DIRECTION INPUT ;
    USE SIGNAL ;
    PORT
      LAYER M4 ;
        RECT  0 13.248 0.084 13.272 ;
    END
  END kw_di[78]
  PIN kw_di[79]
    DIRECTION INPUT ;
    USE SIGNAL ;
    PORT
      LAYER M4 ;
        RECT  0 13.44 0.084 13.464 ;
    END
  END kw_di[79]
  PIN kw_di[7]
    DIRECTION INPUT ;
    USE SIGNAL ;
    PORT
      LAYER M4 ;
        RECT  0 2.592 0.084 2.616 ;
    END
  END kw_di[7]
  PIN kw_di[80]
    DIRECTION INPUT ;
    USE SIGNAL ;
    PORT
      LAYER M4 ;
        RECT  0 13.584 0.084 13.608 ;
    END
  END kw_di[80]
  PIN kw_di[81]
    DIRECTION INPUT ;
    USE SIGNAL ;
    PORT
      LAYER M4 ;
        RECT  0 13.728 0.084 13.752 ;
    END
  END kw_di[81]
  PIN kw_di[82]
    DIRECTION INPUT ;
    USE SIGNAL ;
    PORT
      LAYER M4 ;
        RECT  0 13.872 0.084 13.896 ;
    END
  END kw_di[82]
  PIN kw_di[83]
    DIRECTION INPUT ;
    USE SIGNAL ;
    PORT
      LAYER M4 ;
        RECT  0 14.016 0.084 14.04 ;
    END
  END kw_di[83]
  PIN kw_di[84]
    DIRECTION INPUT ;
    USE SIGNAL ;
    PORT
      LAYER M4 ;
        RECT  0 14.16 0.084 14.184 ;
    END
  END kw_di[84]
  PIN kw_di[85]
    DIRECTION INPUT ;
    USE SIGNAL ;
    PORT
      LAYER M4 ;
        RECT  0 14.304 0.084 14.328 ;
    END
  END kw_di[85]
  PIN kw_di[86]
    DIRECTION INPUT ;
    USE SIGNAL ;
    PORT
      LAYER M4 ;
        RECT  0 14.496 0.084 14.52 ;
    END
  END kw_di[86]
  PIN kw_di[87]
    DIRECTION INPUT ;
    USE SIGNAL ;
    PORT
      LAYER M4 ;
        RECT  0 14.64 0.084 14.664 ;
    END
  END kw_di[87]
  PIN kw_di[88]
    DIRECTION INPUT ;
    USE SIGNAL ;
    PORT
      LAYER M4 ;
        RECT  0 14.784 0.084 14.808 ;
    END
  END kw_di[88]
  PIN kw_di[89]
    DIRECTION INPUT ;
    USE SIGNAL ;
    PORT
      LAYER M4 ;
        RECT  0 14.928 0.084 14.952 ;
    END
  END kw_di[89]
  PIN kw_di[8]
    DIRECTION INPUT ;
    USE SIGNAL ;
    PORT
      LAYER M4 ;
        RECT  0 2.736 0.084 2.76 ;
    END
  END kw_di[8]
  PIN kw_di[90]
    DIRECTION INPUT ;
    USE SIGNAL ;
    PORT
      LAYER M4 ;
        RECT  0 15.072 0.084 15.096 ;
    END
  END kw_di[90]
  PIN kw_di[91]
    DIRECTION INPUT ;
    USE SIGNAL ;
    PORT
      LAYER M4 ;
        RECT  0 15.216 0.084 15.24 ;
    END
  END kw_di[91]
  PIN kw_di[92]
    DIRECTION INPUT ;
    USE SIGNAL ;
    PORT
      LAYER M4 ;
        RECT  0 15.36 0.084 15.384 ;
    END
  END kw_di[92]
  PIN kw_di[93]
    DIRECTION INPUT ;
    USE SIGNAL ;
    PORT
      LAYER M4 ;
        RECT  0 15.552 0.084 15.576 ;
    END
  END kw_di[93]
  PIN kw_di[94]
    DIRECTION INPUT ;
    USE SIGNAL ;
    PORT
      LAYER M4 ;
        RECT  0 15.696 0.084 15.72 ;
    END
  END kw_di[94]
  PIN kw_di[95]
    DIRECTION INPUT ;
    USE SIGNAL ;
    PORT
      LAYER M4 ;
        RECT  0 15.84 0.084 15.864 ;
    END
  END kw_di[95]
  PIN kw_di[96]
    DIRECTION INPUT ;
    USE SIGNAL ;
    PORT
      LAYER M4 ;
        RECT  0 15.984 0.084 16.008 ;
    END
  END kw_di[96]
  PIN kw_di[97]
    DIRECTION INPUT ;
    USE SIGNAL ;
    PORT
      LAYER M4 ;
        RECT  0 16.128 0.084 16.152 ;
    END
  END kw_di[97]
  PIN kw_di[98]
    DIRECTION INPUT ;
    USE SIGNAL ;
    PORT
      LAYER M4 ;
        RECT  0 16.272 0.084 16.296 ;
    END
  END kw_di[98]
  PIN kw_di[99]
    DIRECTION INPUT ;
    USE SIGNAL ;
    PORT
      LAYER M4 ;
        RECT  0 16.416 0.084 16.44 ;
    END
  END kw_di[99]
  PIN kw_di[9]
    DIRECTION INPUT ;
    USE SIGNAL ;
    PORT
      LAYER M4 ;
        RECT  0 2.88 0.084 2.904 ;
    END
  END kw_di[9]
  PIN kw_vi
    DIRECTION INPUT ;
    USE SIGNAL ;
    PORT
      LAYER M4 ;
        RECT  0 40.08 0.084 40.104 ;
    END
  END kw_vi
  PIN pi[0]
    DIRECTION INPUT ;
    USE SIGNAL ;
    PORT
      LAYER M4 ;
        RECT  69.036 37.872 69.12 37.896 ;
    END
  END pi[0]
  PIN pi[100]
    DIRECTION INPUT ;
    USE SIGNAL ;
    PORT
      LAYER M4 ;
        RECT  69.036 52.128 69.12 52.152 ;
    END
  END pi[100]
  PIN pi[101]
    DIRECTION INPUT ;
    USE SIGNAL ;
    PORT
      LAYER M4 ;
        RECT  69.036 52.224 69.12 52.248 ;
    END
  END pi[101]
  PIN pi[102]
    DIRECTION INPUT ;
    USE SIGNAL ;
    PORT
      LAYER M4 ;
        RECT  69.036 52.368 69.12 52.392 ;
    END
  END pi[102]
  PIN pi[103]
    DIRECTION INPUT ;
    USE SIGNAL ;
    PORT
      LAYER M4 ;
        RECT  69.036 52.512 69.12 52.536 ;
    END
  END pi[103]
  PIN pi[104]
    DIRECTION INPUT ;
    USE SIGNAL ;
    PORT
      LAYER M4 ;
        RECT  69.036 52.656 69.12 52.68 ;
    END
  END pi[104]
  PIN pi[105]
    DIRECTION INPUT ;
    USE SIGNAL ;
    PORT
      LAYER M4 ;
        RECT  69.036 52.8 69.12 52.824 ;
    END
  END pi[105]
  PIN pi[106]
    DIRECTION INPUT ;
    USE SIGNAL ;
    PORT
      LAYER M4 ;
        RECT  69.036 52.944 69.12 52.968 ;
    END
  END pi[106]
  PIN pi[107]
    DIRECTION INPUT ;
    USE SIGNAL ;
    PORT
      LAYER M4 ;
        RECT  69.036 53.088 69.12 53.112 ;
    END
  END pi[107]
  PIN pi[108]
    DIRECTION INPUT ;
    USE SIGNAL ;
    PORT
      LAYER M4 ;
        RECT  69.036 53.232 69.12 53.256 ;
    END
  END pi[108]
  PIN pi[109]
    DIRECTION INPUT ;
    USE SIGNAL ;
    PORT
      LAYER M4 ;
        RECT  69.036 53.376 69.12 53.4 ;
    END
  END pi[109]
  PIN pi[10]
    DIRECTION INPUT ;
    USE SIGNAL ;
    PORT
      LAYER M4 ;
        RECT  69.036 39.312 69.12 39.336 ;
    END
  END pi[10]
  PIN pi[110]
    DIRECTION INPUT ;
    USE SIGNAL ;
    PORT
      LAYER M4 ;
        RECT  69.036 53.52 69.12 53.544 ;
    END
  END pi[110]
  PIN pi[111]
    DIRECTION INPUT ;
    USE SIGNAL ;
    PORT
      LAYER M4 ;
        RECT  69.036 53.664 69.12 53.688 ;
    END
  END pi[111]
  PIN pi[112]
    DIRECTION INPUT ;
    USE SIGNAL ;
    PORT
      LAYER M4 ;
        RECT  69.036 53.808 69.12 53.832 ;
    END
  END pi[112]
  PIN pi[113]
    DIRECTION INPUT ;
    USE SIGNAL ;
    PORT
      LAYER M4 ;
        RECT  69.036 53.952 69.12 53.976 ;
    END
  END pi[113]
  PIN pi[114]
    DIRECTION INPUT ;
    USE SIGNAL ;
    PORT
      LAYER M4 ;
        RECT  69.036 54.096 69.12 54.12 ;
    END
  END pi[114]
  PIN pi[115]
    DIRECTION INPUT ;
    USE SIGNAL ;
    PORT
      LAYER M4 ;
        RECT  69.036 54.24 69.12 54.264 ;
    END
  END pi[115]
  PIN pi[116]
    DIRECTION INPUT ;
    USE SIGNAL ;
    PORT
      LAYER M4 ;
        RECT  69.036 54.384 69.12 54.408 ;
    END
  END pi[116]
  PIN pi[117]
    DIRECTION INPUT ;
    USE SIGNAL ;
    PORT
      LAYER M4 ;
        RECT  69.036 54.528 69.12 54.552 ;
    END
  END pi[117]
  PIN pi[118]
    DIRECTION INPUT ;
    USE SIGNAL ;
    PORT
      LAYER M4 ;
        RECT  69.036 54.672 69.12 54.696 ;
    END
  END pi[118]
  PIN pi[119]
    DIRECTION INPUT ;
    USE SIGNAL ;
    PORT
      LAYER M4 ;
        RECT  69.036 54.816 69.12 54.84 ;
    END
  END pi[119]
  PIN pi[11]
    DIRECTION INPUT ;
    USE SIGNAL ;
    PORT
      LAYER M4 ;
        RECT  69.036 39.456 69.12 39.48 ;
    END
  END pi[11]
  PIN pi[120]
    DIRECTION INPUT ;
    USE SIGNAL ;
    PORT
      LAYER M4 ;
        RECT  69.036 54.96 69.12 54.984 ;
    END
  END pi[120]
  PIN pi[121]
    DIRECTION INPUT ;
    USE SIGNAL ;
    PORT
      LAYER M4 ;
        RECT  69.036 55.104 69.12 55.128 ;
    END
  END pi[121]
  PIN pi[122]
    DIRECTION INPUT ;
    USE SIGNAL ;
    PORT
      LAYER M4 ;
        RECT  69.036 55.248 69.12 55.272 ;
    END
  END pi[122]
  PIN pi[123]
    DIRECTION INPUT ;
    USE SIGNAL ;
    PORT
      LAYER M4 ;
        RECT  69.036 55.392 69.12 55.416 ;
    END
  END pi[123]
  PIN pi[124]
    DIRECTION INPUT ;
    USE SIGNAL ;
    PORT
      LAYER M4 ;
        RECT  69.036 55.536 69.12 55.56 ;
    END
  END pi[124]
  PIN pi[125]
    DIRECTION INPUT ;
    USE SIGNAL ;
    PORT
      LAYER M4 ;
        RECT  69.036 55.68 69.12 55.704 ;
    END
  END pi[125]
  PIN pi[126]
    DIRECTION INPUT ;
    USE SIGNAL ;
    PORT
      LAYER M4 ;
        RECT  69.036 55.824 69.12 55.848 ;
    END
  END pi[126]
  PIN pi[127]
    DIRECTION INPUT ;
    USE SIGNAL ;
    PORT
      LAYER M4 ;
        RECT  69.036 55.968 69.12 55.992 ;
    END
  END pi[127]
  PIN pi[128]
    DIRECTION INPUT ;
    USE SIGNAL ;
    PORT
      LAYER M4 ;
        RECT  69.036 56.064 69.12 56.088 ;
    END
  END pi[128]
  PIN pi[129]
    DIRECTION INPUT ;
    USE SIGNAL ;
    PORT
      LAYER M4 ;
        RECT  69.036 56.208 69.12 56.232 ;
    END
  END pi[129]
  PIN pi[12]
    DIRECTION INPUT ;
    USE SIGNAL ;
    PORT
      LAYER M4 ;
        RECT  69.036 39.6 69.12 39.624 ;
    END
  END pi[12]
  PIN pi[130]
    DIRECTION INPUT ;
    USE SIGNAL ;
    PORT
      LAYER M4 ;
        RECT  69.036 56.352 69.12 56.376 ;
    END
  END pi[130]
  PIN pi[131]
    DIRECTION INPUT ;
    USE SIGNAL ;
    PORT
      LAYER M4 ;
        RECT  69.036 56.496 69.12 56.52 ;
    END
  END pi[131]
  PIN pi[132]
    DIRECTION INPUT ;
    USE SIGNAL ;
    PORT
      LAYER M4 ;
        RECT  69.036 56.64 69.12 56.664 ;
    END
  END pi[132]
  PIN pi[133]
    DIRECTION INPUT ;
    USE SIGNAL ;
    PORT
      LAYER M4 ;
        RECT  69.036 56.784 69.12 56.808 ;
    END
  END pi[133]
  PIN pi[134]
    DIRECTION INPUT ;
    USE SIGNAL ;
    PORT
      LAYER M4 ;
        RECT  69.036 56.928 69.12 56.952 ;
    END
  END pi[134]
  PIN pi[135]
    DIRECTION INPUT ;
    USE SIGNAL ;
    PORT
      LAYER M4 ;
        RECT  69.036 57.072 69.12 57.096 ;
    END
  END pi[135]
  PIN pi[136]
    DIRECTION INPUT ;
    USE SIGNAL ;
    PORT
      LAYER M4 ;
        RECT  69.036 57.216 69.12 57.24 ;
    END
  END pi[136]
  PIN pi[137]
    DIRECTION INPUT ;
    USE SIGNAL ;
    PORT
      LAYER M4 ;
        RECT  69.036 57.36 69.12 57.384 ;
    END
  END pi[137]
  PIN pi[138]
    DIRECTION INPUT ;
    USE SIGNAL ;
    PORT
      LAYER M4 ;
        RECT  69.036 57.504 69.12 57.528 ;
    END
  END pi[138]
  PIN pi[139]
    DIRECTION INPUT ;
    USE SIGNAL ;
    PORT
      LAYER M4 ;
        RECT  69.036 57.648 69.12 57.672 ;
    END
  END pi[139]
  PIN pi[13]
    DIRECTION INPUT ;
    USE SIGNAL ;
    PORT
      LAYER M4 ;
        RECT  69.036 39.744 69.12 39.768 ;
    END
  END pi[13]
  PIN pi[140]
    DIRECTION INPUT ;
    USE SIGNAL ;
    PORT
      LAYER M4 ;
        RECT  69.036 57.792 69.12 57.816 ;
    END
  END pi[140]
  PIN pi[141]
    DIRECTION INPUT ;
    USE SIGNAL ;
    PORT
      LAYER M4 ;
        RECT  69.036 57.936 69.12 57.96 ;
    END
  END pi[141]
  PIN pi[142]
    DIRECTION INPUT ;
    USE SIGNAL ;
    PORT
      LAYER M4 ;
        RECT  69.036 58.08 69.12 58.104 ;
    END
  END pi[142]
  PIN pi[143]
    DIRECTION INPUT ;
    USE SIGNAL ;
    PORT
      LAYER M4 ;
        RECT  69.036 58.224 69.12 58.248 ;
    END
  END pi[143]
  PIN pi[144]
    DIRECTION INPUT ;
    USE SIGNAL ;
    PORT
      LAYER M4 ;
        RECT  69.036 58.368 69.12 58.392 ;
    END
  END pi[144]
  PIN pi[145]
    DIRECTION INPUT ;
    USE SIGNAL ;
    PORT
      LAYER M4 ;
        RECT  69.036 58.512 69.12 58.536 ;
    END
  END pi[145]
  PIN pi[146]
    DIRECTION INPUT ;
    USE SIGNAL ;
    PORT
      LAYER M4 ;
        RECT  69.036 58.656 69.12 58.68 ;
    END
  END pi[146]
  PIN pi[147]
    DIRECTION INPUT ;
    USE SIGNAL ;
    PORT
      LAYER M4 ;
        RECT  69.036 58.8 69.12 58.824 ;
    END
  END pi[147]
  PIN pi[148]
    DIRECTION INPUT ;
    USE SIGNAL ;
    PORT
      LAYER M4 ;
        RECT  69.036 58.944 69.12 58.968 ;
    END
  END pi[148]
  PIN pi[149]
    DIRECTION INPUT ;
    USE SIGNAL ;
    PORT
      LAYER M4 ;
        RECT  69.036 59.088 69.12 59.112 ;
    END
  END pi[149]
  PIN pi[14]
    DIRECTION INPUT ;
    USE SIGNAL ;
    PORT
      LAYER M4 ;
        RECT  69.036 39.888 69.12 39.912 ;
    END
  END pi[14]
  PIN pi[150]
    DIRECTION INPUT ;
    USE SIGNAL ;
    PORT
      LAYER M4 ;
        RECT  69.036 59.232 69.12 59.256 ;
    END
  END pi[150]
  PIN pi[151]
    DIRECTION INPUT ;
    USE SIGNAL ;
    PORT
      LAYER M4 ;
        RECT  69.036 59.376 69.12 59.4 ;
    END
  END pi[151]
  PIN pi[152]
    DIRECTION INPUT ;
    USE SIGNAL ;
    PORT
      LAYER M4 ;
        RECT  69.036 59.52 69.12 59.544 ;
    END
  END pi[152]
  PIN pi[153]
    DIRECTION INPUT ;
    USE SIGNAL ;
    PORT
      LAYER M4 ;
        RECT  69.036 59.664 69.12 59.688 ;
    END
  END pi[153]
  PIN pi[154]
    DIRECTION INPUT ;
    USE SIGNAL ;
    PORT
      LAYER M4 ;
        RECT  69.036 59.76 69.12 59.784 ;
    END
  END pi[154]
  PIN pi[155]
    DIRECTION INPUT ;
    USE SIGNAL ;
    PORT
      LAYER M4 ;
        RECT  69.036 59.904 69.12 59.928 ;
    END
  END pi[155]
  PIN pi[156]
    DIRECTION INPUT ;
    USE SIGNAL ;
    PORT
      LAYER M4 ;
        RECT  69.036 60.048 69.12 60.072 ;
    END
  END pi[156]
  PIN pi[157]
    DIRECTION INPUT ;
    USE SIGNAL ;
    PORT
      LAYER M4 ;
        RECT  69.036 60.192 69.12 60.216 ;
    END
  END pi[157]
  PIN pi[158]
    DIRECTION INPUT ;
    USE SIGNAL ;
    PORT
      LAYER M4 ;
        RECT  69.036 60.336 69.12 60.36 ;
    END
  END pi[158]
  PIN pi[159]
    DIRECTION INPUT ;
    USE SIGNAL ;
    PORT
      LAYER M4 ;
        RECT  69.036 60.48 69.12 60.504 ;
    END
  END pi[159]
  PIN pi[15]
    DIRECTION INPUT ;
    USE SIGNAL ;
    PORT
      LAYER M4 ;
        RECT  69.036 40.032 69.12 40.056 ;
    END
  END pi[15]
  PIN pi[160]
    DIRECTION INPUT ;
    USE SIGNAL ;
    PORT
      LAYER M4 ;
        RECT  69.036 60.624 69.12 60.648 ;
    END
  END pi[160]
  PIN pi[161]
    DIRECTION INPUT ;
    USE SIGNAL ;
    PORT
      LAYER M4 ;
        RECT  69.036 60.768 69.12 60.792 ;
    END
  END pi[161]
  PIN pi[162]
    DIRECTION INPUT ;
    USE SIGNAL ;
    PORT
      LAYER M4 ;
        RECT  69.036 60.912 69.12 60.936 ;
    END
  END pi[162]
  PIN pi[163]
    DIRECTION INPUT ;
    USE SIGNAL ;
    PORT
      LAYER M4 ;
        RECT  69.036 61.056 69.12 61.08 ;
    END
  END pi[163]
  PIN pi[164]
    DIRECTION INPUT ;
    USE SIGNAL ;
    PORT
      LAYER M4 ;
        RECT  69.036 61.2 69.12 61.224 ;
    END
  END pi[164]
  PIN pi[165]
    DIRECTION INPUT ;
    USE SIGNAL ;
    PORT
      LAYER M4 ;
        RECT  69.036 61.344 69.12 61.368 ;
    END
  END pi[165]
  PIN pi[166]
    DIRECTION INPUT ;
    USE SIGNAL ;
    PORT
      LAYER M4 ;
        RECT  69.036 61.488 69.12 61.512 ;
    END
  END pi[166]
  PIN pi[167]
    DIRECTION INPUT ;
    USE SIGNAL ;
    PORT
      LAYER M4 ;
        RECT  69.036 61.632 69.12 61.656 ;
    END
  END pi[167]
  PIN pi[168]
    DIRECTION INPUT ;
    USE SIGNAL ;
    PORT
      LAYER M4 ;
        RECT  69.036 61.776 69.12 61.8 ;
    END
  END pi[168]
  PIN pi[169]
    DIRECTION INPUT ;
    USE SIGNAL ;
    PORT
      LAYER M4 ;
        RECT  69.036 61.92 69.12 61.944 ;
    END
  END pi[169]
  PIN pi[16]
    DIRECTION INPUT ;
    USE SIGNAL ;
    PORT
      LAYER M4 ;
        RECT  69.036 40.176 69.12 40.2 ;
    END
  END pi[16]
  PIN pi[170]
    DIRECTION INPUT ;
    USE SIGNAL ;
    PORT
      LAYER M4 ;
        RECT  69.036 62.064 69.12 62.088 ;
    END
  END pi[170]
  PIN pi[171]
    DIRECTION INPUT ;
    USE SIGNAL ;
    PORT
      LAYER M4 ;
        RECT  69.036 62.208 69.12 62.232 ;
    END
  END pi[171]
  PIN pi[172]
    DIRECTION INPUT ;
    USE SIGNAL ;
    PORT
      LAYER M4 ;
        RECT  69.036 62.352 69.12 62.376 ;
    END
  END pi[172]
  PIN pi[173]
    DIRECTION INPUT ;
    USE SIGNAL ;
    PORT
      LAYER M4 ;
        RECT  69.036 62.496 69.12 62.52 ;
    END
  END pi[173]
  PIN pi[174]
    DIRECTION INPUT ;
    USE SIGNAL ;
    PORT
      LAYER M4 ;
        RECT  69.036 62.64 69.12 62.664 ;
    END
  END pi[174]
  PIN pi[175]
    DIRECTION INPUT ;
    USE SIGNAL ;
    PORT
      LAYER M4 ;
        RECT  69.036 62.784 69.12 62.808 ;
    END
  END pi[175]
  PIN pi[176]
    DIRECTION INPUT ;
    USE SIGNAL ;
    PORT
      LAYER M4 ;
        RECT  69.036 62.928 69.12 62.952 ;
    END
  END pi[176]
  PIN pi[177]
    DIRECTION INPUT ;
    USE SIGNAL ;
    PORT
      LAYER M4 ;
        RECT  69.036 63.072 69.12 63.096 ;
    END
  END pi[177]
  PIN pi[178]
    DIRECTION INPUT ;
    USE SIGNAL ;
    PORT
      LAYER M4 ;
        RECT  69.036 63.216 69.12 63.24 ;
    END
  END pi[178]
  PIN pi[179]
    DIRECTION INPUT ;
    USE SIGNAL ;
    PORT
      LAYER M4 ;
        RECT  69.036 63.36 69.12 63.384 ;
    END
  END pi[179]
  PIN pi[17]
    DIRECTION INPUT ;
    USE SIGNAL ;
    PORT
      LAYER M4 ;
        RECT  69.036 40.32 69.12 40.344 ;
    END
  END pi[17]
  PIN pi[180]
    DIRECTION INPUT ;
    USE SIGNAL ;
    PORT
      LAYER M4 ;
        RECT  69.036 63.504 69.12 63.528 ;
    END
  END pi[180]
  PIN pi[181]
    DIRECTION INPUT ;
    USE SIGNAL ;
    PORT
      LAYER M4 ;
        RECT  69.036 63.6 69.12 63.624 ;
    END
  END pi[181]
  PIN pi[182]
    DIRECTION INPUT ;
    USE SIGNAL ;
    PORT
      LAYER M4 ;
        RECT  69.036 63.744 69.12 63.768 ;
    END
  END pi[182]
  PIN pi[183]
    DIRECTION INPUT ;
    USE SIGNAL ;
    PORT
      LAYER M4 ;
        RECT  69.036 63.888 69.12 63.912 ;
    END
  END pi[183]
  PIN pi[184]
    DIRECTION INPUT ;
    USE SIGNAL ;
    PORT
      LAYER M4 ;
        RECT  69.036 64.032 69.12 64.056 ;
    END
  END pi[184]
  PIN pi[185]
    DIRECTION INPUT ;
    USE SIGNAL ;
    PORT
      LAYER M4 ;
        RECT  69.036 64.176 69.12 64.2 ;
    END
  END pi[185]
  PIN pi[186]
    DIRECTION INPUT ;
    USE SIGNAL ;
    PORT
      LAYER M4 ;
        RECT  69.036 64.32 69.12 64.344 ;
    END
  END pi[186]
  PIN pi[187]
    DIRECTION INPUT ;
    USE SIGNAL ;
    PORT
      LAYER M4 ;
        RECT  69.036 64.464 69.12 64.488 ;
    END
  END pi[187]
  PIN pi[188]
    DIRECTION INPUT ;
    USE SIGNAL ;
    PORT
      LAYER M4 ;
        RECT  69.036 64.608 69.12 64.632 ;
    END
  END pi[188]
  PIN pi[189]
    DIRECTION INPUT ;
    USE SIGNAL ;
    PORT
      LAYER M4 ;
        RECT  69.036 64.752 69.12 64.776 ;
    END
  END pi[189]
  PIN pi[18]
    DIRECTION INPUT ;
    USE SIGNAL ;
    PORT
      LAYER M4 ;
        RECT  69.036 40.464 69.12 40.488 ;
    END
  END pi[18]
  PIN pi[190]
    DIRECTION INPUT ;
    USE SIGNAL ;
    PORT
      LAYER M4 ;
        RECT  69.036 64.896 69.12 64.92 ;
    END
  END pi[190]
  PIN pi[191]
    DIRECTION INPUT ;
    USE SIGNAL ;
    PORT
      LAYER M4 ;
        RECT  69.036 65.04 69.12 65.064 ;
    END
  END pi[191]
  PIN pi[192]
    DIRECTION INPUT ;
    USE SIGNAL ;
    PORT
      LAYER M4 ;
        RECT  69.036 65.184 69.12 65.208 ;
    END
  END pi[192]
  PIN pi[193]
    DIRECTION INPUT ;
    USE SIGNAL ;
    PORT
      LAYER M4 ;
        RECT  69.036 65.328 69.12 65.352 ;
    END
  END pi[193]
  PIN pi[194]
    DIRECTION INPUT ;
    USE SIGNAL ;
    PORT
      LAYER M4 ;
        RECT  69.036 65.472 69.12 65.496 ;
    END
  END pi[194]
  PIN pi[195]
    DIRECTION INPUT ;
    USE SIGNAL ;
    PORT
      LAYER M4 ;
        RECT  69.036 65.616 69.12 65.64 ;
    END
  END pi[195]
  PIN pi[196]
    DIRECTION INPUT ;
    USE SIGNAL ;
    PORT
      LAYER M4 ;
        RECT  69.036 65.76 69.12 65.784 ;
    END
  END pi[196]
  PIN pi[197]
    DIRECTION INPUT ;
    USE SIGNAL ;
    PORT
      LAYER M4 ;
        RECT  69.036 65.904 69.12 65.928 ;
    END
  END pi[197]
  PIN pi[198]
    DIRECTION INPUT ;
    USE SIGNAL ;
    PORT
      LAYER M4 ;
        RECT  69.036 66.048 69.12 66.072 ;
    END
  END pi[198]
  PIN pi[199]
    DIRECTION INPUT ;
    USE SIGNAL ;
    PORT
      LAYER M4 ;
        RECT  69.036 66.192 69.12 66.216 ;
    END
  END pi[199]
  PIN pi[19]
    DIRECTION INPUT ;
    USE SIGNAL ;
    PORT
      LAYER M4 ;
        RECT  69.036 40.608 69.12 40.632 ;
    END
  END pi[19]
  PIN pi[1]
    DIRECTION INPUT ;
    USE SIGNAL ;
    PORT
      LAYER M4 ;
        RECT  69.036 38.016 69.12 38.04 ;
    END
  END pi[1]
  PIN pi[200]
    DIRECTION INPUT ;
    USE SIGNAL ;
    PORT
      LAYER M4 ;
        RECT  69.036 66.336 69.12 66.36 ;
    END
  END pi[200]
  PIN pi[201]
    DIRECTION INPUT ;
    USE SIGNAL ;
    PORT
      LAYER M4 ;
        RECT  69.036 66.48 69.12 66.504 ;
    END
  END pi[201]
  PIN pi[202]
    DIRECTION INPUT ;
    USE SIGNAL ;
    PORT
      LAYER M4 ;
        RECT  69.036 66.624 69.12 66.648 ;
    END
  END pi[202]
  PIN pi[203]
    DIRECTION INPUT ;
    USE SIGNAL ;
    PORT
      LAYER M4 ;
        RECT  69.036 66.768 69.12 66.792 ;
    END
  END pi[203]
  PIN pi[204]
    DIRECTION INPUT ;
    USE SIGNAL ;
    PORT
      LAYER M4 ;
        RECT  69.036 66.912 69.12 66.936 ;
    END
  END pi[204]
  PIN pi[205]
    DIRECTION INPUT ;
    USE SIGNAL ;
    PORT
      LAYER M4 ;
        RECT  69.036 67.056 69.12 67.08 ;
    END
  END pi[205]
  PIN pi[206]
    DIRECTION INPUT ;
    USE SIGNAL ;
    PORT
      LAYER M4 ;
        RECT  69.036 67.2 69.12 67.224 ;
    END
  END pi[206]
  PIN pi[207]
    DIRECTION INPUT ;
    USE SIGNAL ;
    PORT
      LAYER M4 ;
        RECT  69.036 67.344 69.12 67.368 ;
    END
  END pi[207]
  PIN pi[208]
    DIRECTION INPUT ;
    USE SIGNAL ;
    PORT
      LAYER M4 ;
        RECT  69.036 67.44 69.12 67.464 ;
    END
  END pi[208]
  PIN pi[209]
    DIRECTION INPUT ;
    USE SIGNAL ;
    PORT
      LAYER M4 ;
        RECT  69.036 67.584 69.12 67.608 ;
    END
  END pi[209]
  PIN pi[20]
    DIRECTION INPUT ;
    USE SIGNAL ;
    PORT
      LAYER M4 ;
        RECT  69.036 40.752 69.12 40.776 ;
    END
  END pi[20]
  PIN pi[210]
    DIRECTION INPUT ;
    USE SIGNAL ;
    PORT
      LAYER M4 ;
        RECT  69.036 67.728 69.12 67.752 ;
    END
  END pi[210]
  PIN pi[211]
    DIRECTION INPUT ;
    USE SIGNAL ;
    PORT
      LAYER M4 ;
        RECT  69.036 67.872 69.12 67.896 ;
    END
  END pi[211]
  PIN pi[212]
    DIRECTION INPUT ;
    USE SIGNAL ;
    PORT
      LAYER M4 ;
        RECT  69.036 68.016 69.12 68.04 ;
    END
  END pi[212]
  PIN pi[213]
    DIRECTION INPUT ;
    USE SIGNAL ;
    PORT
      LAYER M4 ;
        RECT  69.036 68.16 69.12 68.184 ;
    END
  END pi[213]
  PIN pi[214]
    DIRECTION INPUT ;
    USE SIGNAL ;
    PORT
      LAYER M4 ;
        RECT  69.036 68.304 69.12 68.328 ;
    END
  END pi[214]
  PIN pi[215]
    DIRECTION INPUT ;
    USE SIGNAL ;
    PORT
      LAYER M4 ;
        RECT  69.036 68.448 69.12 68.472 ;
    END
  END pi[215]
  PIN pi[216]
    DIRECTION INPUT ;
    USE SIGNAL ;
    PORT
      LAYER M4 ;
        RECT  69.036 68.592 69.12 68.616 ;
    END
  END pi[216]
  PIN pi[217]
    DIRECTION INPUT ;
    USE SIGNAL ;
    PORT
      LAYER M4 ;
        RECT  69.036 68.736 69.12 68.76 ;
    END
  END pi[217]
  PIN pi[218]
    DIRECTION INPUT ;
    USE SIGNAL ;
    PORT
      LAYER M4 ;
        RECT  69.036 68.88 69.12 68.904 ;
    END
  END pi[218]
  PIN pi[219]
    DIRECTION INPUT ;
    USE SIGNAL ;
    PORT
      LAYER M4 ;
        RECT  69.036 69.024 69.12 69.048 ;
    END
  END pi[219]
  PIN pi[21]
    DIRECTION INPUT ;
    USE SIGNAL ;
    PORT
      LAYER M4 ;
        RECT  69.036 40.896 69.12 40.92 ;
    END
  END pi[21]
  PIN pi[220]
    DIRECTION INPUT ;
    USE SIGNAL ;
    PORT
      LAYER M4 ;
        RECT  69.036 69.168 69.12 69.192 ;
    END
  END pi[220]
  PIN pi[221]
    DIRECTION INPUT ;
    USE SIGNAL ;
    PORT
      LAYER M4 ;
        RECT  69.036 69.312 69.12 69.336 ;
    END
  END pi[221]
  PIN pi[222]
    DIRECTION INPUT ;
    USE SIGNAL ;
    PORT
      LAYER M4 ;
        RECT  69.036 69.456 69.12 69.48 ;
    END
  END pi[222]
  PIN pi[223]
    DIRECTION INPUT ;
    USE SIGNAL ;
    PORT
      LAYER M4 ;
        RECT  69.036 69.6 69.12 69.624 ;
    END
  END pi[223]
  PIN pi[224]
    DIRECTION INPUT ;
    USE SIGNAL ;
    PORT
      LAYER M4 ;
        RECT  69.036 69.744 69.12 69.768 ;
    END
  END pi[224]
  PIN pi[225]
    DIRECTION INPUT ;
    USE SIGNAL ;
    PORT
      LAYER M4 ;
        RECT  69.036 69.888 69.12 69.912 ;
    END
  END pi[225]
  PIN pi[226]
    DIRECTION INPUT ;
    USE SIGNAL ;
    PORT
      LAYER M4 ;
        RECT  69.036 70.032 69.12 70.056 ;
    END
  END pi[226]
  PIN pi[227]
    DIRECTION INPUT ;
    USE SIGNAL ;
    PORT
      LAYER M4 ;
        RECT  69.036 70.176 69.12 70.2 ;
    END
  END pi[227]
  PIN pi[228]
    DIRECTION INPUT ;
    USE SIGNAL ;
    PORT
      LAYER M4 ;
        RECT  69.036 70.32 69.12 70.344 ;
    END
  END pi[228]
  PIN pi[229]
    DIRECTION INPUT ;
    USE SIGNAL ;
    PORT
      LAYER M4 ;
        RECT  69.036 70.464 69.12 70.488 ;
    END
  END pi[229]
  PIN pi[22]
    DIRECTION INPUT ;
    USE SIGNAL ;
    PORT
      LAYER M4 ;
        RECT  69.036 40.992 69.12 41.016 ;
    END
  END pi[22]
  PIN pi[230]
    DIRECTION INPUT ;
    USE SIGNAL ;
    PORT
      LAYER M4 ;
        RECT  69.036 70.608 69.12 70.632 ;
    END
  END pi[230]
  PIN pi[231]
    DIRECTION INPUT ;
    USE SIGNAL ;
    PORT
      LAYER M4 ;
        RECT  69.036 70.752 69.12 70.776 ;
    END
  END pi[231]
  PIN pi[232]
    DIRECTION INPUT ;
    USE SIGNAL ;
    PORT
      LAYER M4 ;
        RECT  69.036 70.896 69.12 70.92 ;
    END
  END pi[232]
  PIN pi[233]
    DIRECTION INPUT ;
    USE SIGNAL ;
    PORT
      LAYER M4 ;
        RECT  69.036 71.04 69.12 71.064 ;
    END
  END pi[233]
  PIN pi[234]
    DIRECTION INPUT ;
    USE SIGNAL ;
    PORT
      LAYER M4 ;
        RECT  69.036 71.136 69.12 71.16 ;
    END
  END pi[234]
  PIN pi[235]
    DIRECTION INPUT ;
    USE SIGNAL ;
    PORT
      LAYER M4 ;
        RECT  69.036 71.28 69.12 71.304 ;
    END
  END pi[235]
  PIN pi[236]
    DIRECTION INPUT ;
    USE SIGNAL ;
    PORT
      LAYER M4 ;
        RECT  69.036 71.424 69.12 71.448 ;
    END
  END pi[236]
  PIN pi[237]
    DIRECTION INPUT ;
    USE SIGNAL ;
    PORT
      LAYER M4 ;
        RECT  69.036 71.568 69.12 71.592 ;
    END
  END pi[237]
  PIN pi[238]
    DIRECTION INPUT ;
    USE SIGNAL ;
    PORT
      LAYER M4 ;
        RECT  69.036 71.712 69.12 71.736 ;
    END
  END pi[238]
  PIN pi[239]
    DIRECTION INPUT ;
    USE SIGNAL ;
    PORT
      LAYER M4 ;
        RECT  69.036 71.856 69.12 71.88 ;
    END
  END pi[239]
  PIN pi[23]
    DIRECTION INPUT ;
    USE SIGNAL ;
    PORT
      LAYER M4 ;
        RECT  69.036 41.136 69.12 41.16 ;
    END
  END pi[23]
  PIN pi[240]
    DIRECTION INPUT ;
    USE SIGNAL ;
    PORT
      LAYER M4 ;
        RECT  69.036 72 69.12 72.024 ;
    END
  END pi[240]
  PIN pi[241]
    DIRECTION INPUT ;
    USE SIGNAL ;
    PORT
      LAYER M4 ;
        RECT  69.036 72.144 69.12 72.168 ;
    END
  END pi[241]
  PIN pi[242]
    DIRECTION INPUT ;
    USE SIGNAL ;
    PORT
      LAYER M4 ;
        RECT  69.036 72.288 69.12 72.312 ;
    END
  END pi[242]
  PIN pi[243]
    DIRECTION INPUT ;
    USE SIGNAL ;
    PORT
      LAYER M4 ;
        RECT  69.036 72.432 69.12 72.456 ;
    END
  END pi[243]
  PIN pi[244]
    DIRECTION INPUT ;
    USE SIGNAL ;
    PORT
      LAYER M4 ;
        RECT  69.036 72.576 69.12 72.6 ;
    END
  END pi[244]
  PIN pi[245]
    DIRECTION INPUT ;
    USE SIGNAL ;
    PORT
      LAYER M4 ;
        RECT  69.036 72.72 69.12 72.744 ;
    END
  END pi[245]
  PIN pi[246]
    DIRECTION INPUT ;
    USE SIGNAL ;
    PORT
      LAYER M4 ;
        RECT  69.036 72.864 69.12 72.888 ;
    END
  END pi[246]
  PIN pi[247]
    DIRECTION INPUT ;
    USE SIGNAL ;
    PORT
      LAYER M4 ;
        RECT  69.036 73.008 69.12 73.032 ;
    END
  END pi[247]
  PIN pi[248]
    DIRECTION INPUT ;
    USE SIGNAL ;
    PORT
      LAYER M4 ;
        RECT  69.036 73.152 69.12 73.176 ;
    END
  END pi[248]
  PIN pi[249]
    DIRECTION INPUT ;
    USE SIGNAL ;
    PORT
      LAYER M4 ;
        RECT  69.036 73.296 69.12 73.32 ;
    END
  END pi[249]
  PIN pi[24]
    DIRECTION INPUT ;
    USE SIGNAL ;
    PORT
      LAYER M4 ;
        RECT  69.036 41.28 69.12 41.304 ;
    END
  END pi[24]
  PIN pi[250]
    DIRECTION INPUT ;
    USE SIGNAL ;
    PORT
      LAYER M4 ;
        RECT  69.036 73.44 69.12 73.464 ;
    END
  END pi[250]
  PIN pi[251]
    DIRECTION INPUT ;
    USE SIGNAL ;
    PORT
      LAYER M4 ;
        RECT  69.036 73.584 69.12 73.608 ;
    END
  END pi[251]
  PIN pi[252]
    DIRECTION INPUT ;
    USE SIGNAL ;
    PORT
      LAYER M4 ;
        RECT  69.036 73.728 69.12 73.752 ;
    END
  END pi[252]
  PIN pi[253]
    DIRECTION INPUT ;
    USE SIGNAL ;
    PORT
      LAYER M4 ;
        RECT  69.036 73.872 69.12 73.896 ;
    END
  END pi[253]
  PIN pi[254]
    DIRECTION INPUT ;
    USE SIGNAL ;
    PORT
      LAYER M4 ;
        RECT  69.036 74.016 69.12 74.04 ;
    END
  END pi[254]
  PIN pi[255]
    DIRECTION INPUT ;
    USE SIGNAL ;
    PORT
      LAYER M4 ;
        RECT  69.036 74.16 69.12 74.184 ;
    END
  END pi[255]
  PIN pi[256]
    DIRECTION INPUT ;
    USE SIGNAL ;
    PORT
      LAYER M4 ;
        RECT  69.036 74.304 69.12 74.328 ;
    END
  END pi[256]
  PIN pi[257]
    DIRECTION INPUT ;
    USE SIGNAL ;
    PORT
      LAYER M4 ;
        RECT  69.036 74.448 69.12 74.472 ;
    END
  END pi[257]
  PIN pi[258]
    DIRECTION INPUT ;
    USE SIGNAL ;
    PORT
      LAYER M4 ;
        RECT  69.036 74.592 69.12 74.616 ;
    END
  END pi[258]
  PIN pi[259]
    DIRECTION INPUT ;
    USE SIGNAL ;
    PORT
      LAYER M4 ;
        RECT  69.036 74.736 69.12 74.76 ;
    END
  END pi[259]
  PIN pi[25]
    DIRECTION INPUT ;
    USE SIGNAL ;
    PORT
      LAYER M4 ;
        RECT  69.036 41.424 69.12 41.448 ;
    END
  END pi[25]
  PIN pi[260]
    DIRECTION INPUT ;
    USE SIGNAL ;
    PORT
      LAYER M4 ;
        RECT  69.036 74.88 69.12 74.904 ;
    END
  END pi[260]
  PIN pi[261]
    DIRECTION INPUT ;
    USE SIGNAL ;
    PORT
      LAYER M4 ;
        RECT  69.036 74.976 69.12 75 ;
    END
  END pi[261]
  PIN pi[262]
    DIRECTION INPUT ;
    USE SIGNAL ;
    PORT
      LAYER M4 ;
        RECT  69.036 75.12 69.12 75.144 ;
    END
  END pi[262]
  PIN pi[263]
    DIRECTION INPUT ;
    USE SIGNAL ;
    PORT
      LAYER M4 ;
        RECT  69.036 75.264 69.12 75.288 ;
    END
  END pi[263]
  PIN pi[264]
    DIRECTION INPUT ;
    USE SIGNAL ;
    PORT
      LAYER M4 ;
        RECT  69.036 75.408 69.12 75.432 ;
    END
  END pi[264]
  PIN pi[265]
    DIRECTION INPUT ;
    USE SIGNAL ;
    PORT
      LAYER M4 ;
        RECT  69.036 75.552 69.12 75.576 ;
    END
  END pi[265]
  PIN pi[266]
    DIRECTION INPUT ;
    USE SIGNAL ;
    PORT
      LAYER M4 ;
        RECT  69.036 75.696 69.12 75.72 ;
    END
  END pi[266]
  PIN pi[267]
    DIRECTION INPUT ;
    USE SIGNAL ;
    PORT
      LAYER M4 ;
        RECT  69.036 75.84 69.12 75.864 ;
    END
  END pi[267]
  PIN pi[268]
    DIRECTION INPUT ;
    USE SIGNAL ;
    PORT
      LAYER M4 ;
        RECT  69.036 75.984 69.12 76.008 ;
    END
  END pi[268]
  PIN pi[269]
    DIRECTION INPUT ;
    USE SIGNAL ;
    PORT
      LAYER M4 ;
        RECT  69.036 76.128 69.12 76.152 ;
    END
  END pi[269]
  PIN pi[26]
    DIRECTION INPUT ;
    USE SIGNAL ;
    PORT
      LAYER M4 ;
        RECT  69.036 41.568 69.12 41.592 ;
    END
  END pi[26]
  PIN pi[270]
    DIRECTION INPUT ;
    USE SIGNAL ;
    PORT
      LAYER M4 ;
        RECT  69.036 76.272 69.12 76.296 ;
    END
  END pi[270]
  PIN pi[271]
    DIRECTION INPUT ;
    USE SIGNAL ;
    PORT
      LAYER M4 ;
        RECT  69.036 76.416 69.12 76.44 ;
    END
  END pi[271]
  PIN pi[272]
    DIRECTION INPUT ;
    USE SIGNAL ;
    PORT
      LAYER M4 ;
        RECT  69.036 76.56 69.12 76.584 ;
    END
  END pi[272]
  PIN pi[273]
    DIRECTION INPUT ;
    USE SIGNAL ;
    PORT
      LAYER M4 ;
        RECT  69.036 76.704 69.12 76.728 ;
    END
  END pi[273]
  PIN pi[274]
    DIRECTION INPUT ;
    USE SIGNAL ;
    PORT
      LAYER M4 ;
        RECT  69.036 76.848 69.12 76.872 ;
    END
  END pi[274]
  PIN pi[275]
    DIRECTION INPUT ;
    USE SIGNAL ;
    PORT
      LAYER M4 ;
        RECT  69.036 76.992 69.12 77.016 ;
    END
  END pi[275]
  PIN pi[276]
    DIRECTION INPUT ;
    USE SIGNAL ;
    PORT
      LAYER M4 ;
        RECT  69.036 77.136 69.12 77.16 ;
    END
  END pi[276]
  PIN pi[277]
    DIRECTION INPUT ;
    USE SIGNAL ;
    PORT
      LAYER M4 ;
        RECT  69.036 77.28 69.12 77.304 ;
    END
  END pi[277]
  PIN pi[278]
    DIRECTION INPUT ;
    USE SIGNAL ;
    PORT
      LAYER M4 ;
        RECT  69.036 77.424 69.12 77.448 ;
    END
  END pi[278]
  PIN pi[279]
    DIRECTION INPUT ;
    USE SIGNAL ;
    PORT
      LAYER M4 ;
        RECT  69.036 77.568 69.12 77.592 ;
    END
  END pi[279]
  PIN pi[27]
    DIRECTION INPUT ;
    USE SIGNAL ;
    PORT
      LAYER M4 ;
        RECT  69.036 41.712 69.12 41.736 ;
    END
  END pi[27]
  PIN pi[280]
    DIRECTION INPUT ;
    USE SIGNAL ;
    PORT
      LAYER M4 ;
        RECT  69.036 77.712 69.12 77.736 ;
    END
  END pi[280]
  PIN pi[281]
    DIRECTION INPUT ;
    USE SIGNAL ;
    PORT
      LAYER M4 ;
        RECT  69.036 77.856 69.12 77.88 ;
    END
  END pi[281]
  PIN pi[282]
    DIRECTION INPUT ;
    USE SIGNAL ;
    PORT
      LAYER M4 ;
        RECT  69.036 78 69.12 78.024 ;
    END
  END pi[282]
  PIN pi[283]
    DIRECTION INPUT ;
    USE SIGNAL ;
    PORT
      LAYER M4 ;
        RECT  69.036 78.144 69.12 78.168 ;
    END
  END pi[283]
  PIN pi[284]
    DIRECTION INPUT ;
    USE SIGNAL ;
    PORT
      LAYER M4 ;
        RECT  69.036 78.288 69.12 78.312 ;
    END
  END pi[284]
  PIN pi[285]
    DIRECTION INPUT ;
    USE SIGNAL ;
    PORT
      LAYER M4 ;
        RECT  69.036 78.432 69.12 78.456 ;
    END
  END pi[285]
  PIN pi[286]
    DIRECTION INPUT ;
    USE SIGNAL ;
    PORT
      LAYER M4 ;
        RECT  69.036 78.576 69.12 78.6 ;
    END
  END pi[286]
  PIN pi[287]
    DIRECTION INPUT ;
    USE SIGNAL ;
    PORT
      LAYER M4 ;
        RECT  69.036 78.672 69.12 78.696 ;
    END
  END pi[287]
  PIN pi[288]
    DIRECTION INPUT ;
    USE SIGNAL ;
    PORT
      LAYER M4 ;
        RECT  69.036 78.816 69.12 78.84 ;
    END
  END pi[288]
  PIN pi[28]
    DIRECTION INPUT ;
    USE SIGNAL ;
    PORT
      LAYER M4 ;
        RECT  69.036 41.856 69.12 41.88 ;
    END
  END pi[28]
  PIN pi[29]
    DIRECTION INPUT ;
    USE SIGNAL ;
    PORT
      LAYER M4 ;
        RECT  69.036 42 69.12 42.024 ;
    END
  END pi[29]
  PIN pi[2]
    DIRECTION INPUT ;
    USE SIGNAL ;
    PORT
      LAYER M4 ;
        RECT  69.036 38.16 69.12 38.184 ;
    END
  END pi[2]
  PIN pi[30]
    DIRECTION INPUT ;
    USE SIGNAL ;
    PORT
      LAYER M4 ;
        RECT  69.036 42.144 69.12 42.168 ;
    END
  END pi[30]
  PIN pi[31]
    DIRECTION INPUT ;
    USE SIGNAL ;
    PORT
      LAYER M4 ;
        RECT  69.036 42.288 69.12 42.312 ;
    END
  END pi[31]
  PIN pi[32]
    DIRECTION INPUT ;
    USE SIGNAL ;
    PORT
      LAYER M4 ;
        RECT  69.036 42.432 69.12 42.456 ;
    END
  END pi[32]
  PIN pi[33]
    DIRECTION INPUT ;
    USE SIGNAL ;
    PORT
      LAYER M4 ;
        RECT  69.036 42.576 69.12 42.6 ;
    END
  END pi[33]
  PIN pi[34]
    DIRECTION INPUT ;
    USE SIGNAL ;
    PORT
      LAYER M4 ;
        RECT  69.036 42.72 69.12 42.744 ;
    END
  END pi[34]
  PIN pi[35]
    DIRECTION INPUT ;
    USE SIGNAL ;
    PORT
      LAYER M4 ;
        RECT  69.036 42.864 69.12 42.888 ;
    END
  END pi[35]
  PIN pi[36]
    DIRECTION INPUT ;
    USE SIGNAL ;
    PORT
      LAYER M4 ;
        RECT  69.036 43.008 69.12 43.032 ;
    END
  END pi[36]
  PIN pi[37]
    DIRECTION INPUT ;
    USE SIGNAL ;
    PORT
      LAYER M4 ;
        RECT  69.036 43.152 69.12 43.176 ;
    END
  END pi[37]
  PIN pi[38]
    DIRECTION INPUT ;
    USE SIGNAL ;
    PORT
      LAYER M4 ;
        RECT  69.036 43.296 69.12 43.32 ;
    END
  END pi[38]
  PIN pi[39]
    DIRECTION INPUT ;
    USE SIGNAL ;
    PORT
      LAYER M4 ;
        RECT  69.036 43.44 69.12 43.464 ;
    END
  END pi[39]
  PIN pi[3]
    DIRECTION INPUT ;
    USE SIGNAL ;
    PORT
      LAYER M4 ;
        RECT  69.036 38.304 69.12 38.328 ;
    END
  END pi[3]
  PIN pi[40]
    DIRECTION INPUT ;
    USE SIGNAL ;
    PORT
      LAYER M4 ;
        RECT  69.036 43.584 69.12 43.608 ;
    END
  END pi[40]
  PIN pi[41]
    DIRECTION INPUT ;
    USE SIGNAL ;
    PORT
      LAYER M4 ;
        RECT  69.036 43.728 69.12 43.752 ;
    END
  END pi[41]
  PIN pi[42]
    DIRECTION INPUT ;
    USE SIGNAL ;
    PORT
      LAYER M4 ;
        RECT  69.036 43.872 69.12 43.896 ;
    END
  END pi[42]
  PIN pi[43]
    DIRECTION INPUT ;
    USE SIGNAL ;
    PORT
      LAYER M4 ;
        RECT  69.036 44.016 69.12 44.04 ;
    END
  END pi[43]
  PIN pi[44]
    DIRECTION INPUT ;
    USE SIGNAL ;
    PORT
      LAYER M4 ;
        RECT  69.036 44.16 69.12 44.184 ;
    END
  END pi[44]
  PIN pi[45]
    DIRECTION INPUT ;
    USE SIGNAL ;
    PORT
      LAYER M4 ;
        RECT  69.036 44.304 69.12 44.328 ;
    END
  END pi[45]
  PIN pi[46]
    DIRECTION INPUT ;
    USE SIGNAL ;
    PORT
      LAYER M4 ;
        RECT  69.036 44.448 69.12 44.472 ;
    END
  END pi[46]
  PIN pi[47]
    DIRECTION INPUT ;
    USE SIGNAL ;
    PORT
      LAYER M4 ;
        RECT  69.036 44.592 69.12 44.616 ;
    END
  END pi[47]
  PIN pi[48]
    DIRECTION INPUT ;
    USE SIGNAL ;
    PORT
      LAYER M4 ;
        RECT  69.036 44.688 69.12 44.712 ;
    END
  END pi[48]
  PIN pi[49]
    DIRECTION INPUT ;
    USE SIGNAL ;
    PORT
      LAYER M4 ;
        RECT  69.036 44.832 69.12 44.856 ;
    END
  END pi[49]
  PIN pi[4]
    DIRECTION INPUT ;
    USE SIGNAL ;
    PORT
      LAYER M4 ;
        RECT  69.036 38.448 69.12 38.472 ;
    END
  END pi[4]
  PIN pi[50]
    DIRECTION INPUT ;
    USE SIGNAL ;
    PORT
      LAYER M4 ;
        RECT  69.036 44.976 69.12 45 ;
    END
  END pi[50]
  PIN pi[51]
    DIRECTION INPUT ;
    USE SIGNAL ;
    PORT
      LAYER M4 ;
        RECT  69.036 45.12 69.12 45.144 ;
    END
  END pi[51]
  PIN pi[52]
    DIRECTION INPUT ;
    USE SIGNAL ;
    PORT
      LAYER M4 ;
        RECT  69.036 45.264 69.12 45.288 ;
    END
  END pi[52]
  PIN pi[53]
    DIRECTION INPUT ;
    USE SIGNAL ;
    PORT
      LAYER M4 ;
        RECT  69.036 45.408 69.12 45.432 ;
    END
  END pi[53]
  PIN pi[54]
    DIRECTION INPUT ;
    USE SIGNAL ;
    PORT
      LAYER M4 ;
        RECT  69.036 45.552 69.12 45.576 ;
    END
  END pi[54]
  PIN pi[55]
    DIRECTION INPUT ;
    USE SIGNAL ;
    PORT
      LAYER M4 ;
        RECT  69.036 45.696 69.12 45.72 ;
    END
  END pi[55]
  PIN pi[56]
    DIRECTION INPUT ;
    USE SIGNAL ;
    PORT
      LAYER M4 ;
        RECT  69.036 45.84 69.12 45.864 ;
    END
  END pi[56]
  PIN pi[57]
    DIRECTION INPUT ;
    USE SIGNAL ;
    PORT
      LAYER M4 ;
        RECT  69.036 45.984 69.12 46.008 ;
    END
  END pi[57]
  PIN pi[58]
    DIRECTION INPUT ;
    USE SIGNAL ;
    PORT
      LAYER M4 ;
        RECT  69.036 46.128 69.12 46.152 ;
    END
  END pi[58]
  PIN pi[59]
    DIRECTION INPUT ;
    USE SIGNAL ;
    PORT
      LAYER M4 ;
        RECT  69.036 46.272 69.12 46.296 ;
    END
  END pi[59]
  PIN pi[5]
    DIRECTION INPUT ;
    USE SIGNAL ;
    PORT
      LAYER M4 ;
        RECT  69.036 38.592 69.12 38.616 ;
    END
  END pi[5]
  PIN pi[60]
    DIRECTION INPUT ;
    USE SIGNAL ;
    PORT
      LAYER M4 ;
        RECT  69.036 46.416 69.12 46.44 ;
    END
  END pi[60]
  PIN pi[61]
    DIRECTION INPUT ;
    USE SIGNAL ;
    PORT
      LAYER M4 ;
        RECT  69.036 46.56 69.12 46.584 ;
    END
  END pi[61]
  PIN pi[62]
    DIRECTION INPUT ;
    USE SIGNAL ;
    PORT
      LAYER M4 ;
        RECT  69.036 46.704 69.12 46.728 ;
    END
  END pi[62]
  PIN pi[63]
    DIRECTION INPUT ;
    USE SIGNAL ;
    PORT
      LAYER M4 ;
        RECT  69.036 46.848 69.12 46.872 ;
    END
  END pi[63]
  PIN pi[64]
    DIRECTION INPUT ;
    USE SIGNAL ;
    PORT
      LAYER M4 ;
        RECT  69.036 46.992 69.12 47.016 ;
    END
  END pi[64]
  PIN pi[65]
    DIRECTION INPUT ;
    USE SIGNAL ;
    PORT
      LAYER M4 ;
        RECT  69.036 47.136 69.12 47.16 ;
    END
  END pi[65]
  PIN pi[66]
    DIRECTION INPUT ;
    USE SIGNAL ;
    PORT
      LAYER M4 ;
        RECT  69.036 47.28 69.12 47.304 ;
    END
  END pi[66]
  PIN pi[67]
    DIRECTION INPUT ;
    USE SIGNAL ;
    PORT
      LAYER M4 ;
        RECT  69.036 47.424 69.12 47.448 ;
    END
  END pi[67]
  PIN pi[68]
    DIRECTION INPUT ;
    USE SIGNAL ;
    PORT
      LAYER M4 ;
        RECT  69.036 47.568 69.12 47.592 ;
    END
  END pi[68]
  PIN pi[69]
    DIRECTION INPUT ;
    USE SIGNAL ;
    PORT
      LAYER M4 ;
        RECT  69.036 47.712 69.12 47.736 ;
    END
  END pi[69]
  PIN pi[6]
    DIRECTION INPUT ;
    USE SIGNAL ;
    PORT
      LAYER M4 ;
        RECT  69.036 38.736 69.12 38.76 ;
    END
  END pi[6]
  PIN pi[70]
    DIRECTION INPUT ;
    USE SIGNAL ;
    PORT
      LAYER M4 ;
        RECT  69.036 47.856 69.12 47.88 ;
    END
  END pi[70]
  PIN pi[71]
    DIRECTION INPUT ;
    USE SIGNAL ;
    PORT
      LAYER M4 ;
        RECT  69.036 48 69.12 48.024 ;
    END
  END pi[71]
  PIN pi[72]
    DIRECTION INPUT ;
    USE SIGNAL ;
    PORT
      LAYER M4 ;
        RECT  69.036 48.144 69.12 48.168 ;
    END
  END pi[72]
  PIN pi[73]
    DIRECTION INPUT ;
    USE SIGNAL ;
    PORT
      LAYER M4 ;
        RECT  69.036 48.288 69.12 48.312 ;
    END
  END pi[73]
  PIN pi[74]
    DIRECTION INPUT ;
    USE SIGNAL ;
    PORT
      LAYER M4 ;
        RECT  69.036 48.432 69.12 48.456 ;
    END
  END pi[74]
  PIN pi[75]
    DIRECTION INPUT ;
    USE SIGNAL ;
    PORT
      LAYER M4 ;
        RECT  69.036 48.528 69.12 48.552 ;
    END
  END pi[75]
  PIN pi[76]
    DIRECTION INPUT ;
    USE SIGNAL ;
    PORT
      LAYER M4 ;
        RECT  69.036 48.672 69.12 48.696 ;
    END
  END pi[76]
  PIN pi[77]
    DIRECTION INPUT ;
    USE SIGNAL ;
    PORT
      LAYER M4 ;
        RECT  69.036 48.816 69.12 48.84 ;
    END
  END pi[77]
  PIN pi[78]
    DIRECTION INPUT ;
    USE SIGNAL ;
    PORT
      LAYER M4 ;
        RECT  69.036 48.96 69.12 48.984 ;
    END
  END pi[78]
  PIN pi[79]
    DIRECTION INPUT ;
    USE SIGNAL ;
    PORT
      LAYER M4 ;
        RECT  69.036 49.104 69.12 49.128 ;
    END
  END pi[79]
  PIN pi[7]
    DIRECTION INPUT ;
    USE SIGNAL ;
    PORT
      LAYER M4 ;
        RECT  69.036 38.88 69.12 38.904 ;
    END
  END pi[7]
  PIN pi[80]
    DIRECTION INPUT ;
    USE SIGNAL ;
    PORT
      LAYER M4 ;
        RECT  69.036 49.248 69.12 49.272 ;
    END
  END pi[80]
  PIN pi[81]
    DIRECTION INPUT ;
    USE SIGNAL ;
    PORT
      LAYER M4 ;
        RECT  69.036 49.392 69.12 49.416 ;
    END
  END pi[81]
  PIN pi[82]
    DIRECTION INPUT ;
    USE SIGNAL ;
    PORT
      LAYER M4 ;
        RECT  69.036 49.536 69.12 49.56 ;
    END
  END pi[82]
  PIN pi[83]
    DIRECTION INPUT ;
    USE SIGNAL ;
    PORT
      LAYER M4 ;
        RECT  69.036 49.68 69.12 49.704 ;
    END
  END pi[83]
  PIN pi[84]
    DIRECTION INPUT ;
    USE SIGNAL ;
    PORT
      LAYER M4 ;
        RECT  69.036 49.824 69.12 49.848 ;
    END
  END pi[84]
  PIN pi[85]
    DIRECTION INPUT ;
    USE SIGNAL ;
    PORT
      LAYER M4 ;
        RECT  69.036 49.968 69.12 49.992 ;
    END
  END pi[85]
  PIN pi[86]
    DIRECTION INPUT ;
    USE SIGNAL ;
    PORT
      LAYER M4 ;
        RECT  69.036 50.112 69.12 50.136 ;
    END
  END pi[86]
  PIN pi[87]
    DIRECTION INPUT ;
    USE SIGNAL ;
    PORT
      LAYER M4 ;
        RECT  69.036 50.256 69.12 50.28 ;
    END
  END pi[87]
  PIN pi[88]
    DIRECTION INPUT ;
    USE SIGNAL ;
    PORT
      LAYER M4 ;
        RECT  69.036 50.4 69.12 50.424 ;
    END
  END pi[88]
  PIN pi[89]
    DIRECTION INPUT ;
    USE SIGNAL ;
    PORT
      LAYER M4 ;
        RECT  69.036 50.544 69.12 50.568 ;
    END
  END pi[89]
  PIN pi[8]
    DIRECTION INPUT ;
    USE SIGNAL ;
    PORT
      LAYER M4 ;
        RECT  69.036 39.024 69.12 39.048 ;
    END
  END pi[8]
  PIN pi[90]
    DIRECTION INPUT ;
    USE SIGNAL ;
    PORT
      LAYER M4 ;
        RECT  69.036 50.688 69.12 50.712 ;
    END
  END pi[90]
  PIN pi[91]
    DIRECTION INPUT ;
    USE SIGNAL ;
    PORT
      LAYER M4 ;
        RECT  69.036 50.832 69.12 50.856 ;
    END
  END pi[91]
  PIN pi[92]
    DIRECTION INPUT ;
    USE SIGNAL ;
    PORT
      LAYER M4 ;
        RECT  69.036 50.976 69.12 51 ;
    END
  END pi[92]
  PIN pi[93]
    DIRECTION INPUT ;
    USE SIGNAL ;
    PORT
      LAYER M4 ;
        RECT  69.036 51.12 69.12 51.144 ;
    END
  END pi[93]
  PIN pi[94]
    DIRECTION INPUT ;
    USE SIGNAL ;
    PORT
      LAYER M4 ;
        RECT  69.036 51.264 69.12 51.288 ;
    END
  END pi[94]
  PIN pi[95]
    DIRECTION INPUT ;
    USE SIGNAL ;
    PORT
      LAYER M4 ;
        RECT  69.036 51.408 69.12 51.432 ;
    END
  END pi[95]
  PIN pi[96]
    DIRECTION INPUT ;
    USE SIGNAL ;
    PORT
      LAYER M4 ;
        RECT  69.036 51.552 69.12 51.576 ;
    END
  END pi[96]
  PIN pi[97]
    DIRECTION INPUT ;
    USE SIGNAL ;
    PORT
      LAYER M4 ;
        RECT  69.036 51.696 69.12 51.72 ;
    END
  END pi[97]
  PIN pi[98]
    DIRECTION INPUT ;
    USE SIGNAL ;
    PORT
      LAYER M4 ;
        RECT  69.036 51.84 69.12 51.864 ;
    END
  END pi[98]
  PIN pi[99]
    DIRECTION INPUT ;
    USE SIGNAL ;
    PORT
      LAYER M4 ;
        RECT  69.036 51.984 69.12 52.008 ;
    END
  END pi[99]
  PIN pi[9]
    DIRECTION INPUT ;
    USE SIGNAL ;
    PORT
      LAYER M4 ;
        RECT  69.036 39.168 69.12 39.192 ;
    END
  END pi[9]
  PIN w_d[0]
    DIRECTION INPUT ;
    USE SIGNAL ;
    PORT
      LAYER M4 ;
        RECT  0 40.272 0.084 40.296 ;
    END
  END w_d[0]
  PIN w_d[100]
    DIRECTION INPUT ;
    USE SIGNAL ;
    PORT
      LAYER M4 ;
        RECT  0 55.344 0.084 55.368 ;
    END
  END w_d[100]
  PIN w_d[101]
    DIRECTION INPUT ;
    USE SIGNAL ;
    PORT
      LAYER M4 ;
        RECT  0 55.488 0.084 55.512 ;
    END
  END w_d[101]
  PIN w_d[102]
    DIRECTION INPUT ;
    USE SIGNAL ;
    PORT
      LAYER M4 ;
        RECT  0 55.632 0.084 55.656 ;
    END
  END w_d[102]
  PIN w_d[103]
    DIRECTION INPUT ;
    USE SIGNAL ;
    PORT
      LAYER M4 ;
        RECT  0 55.776 0.084 55.8 ;
    END
  END w_d[103]
  PIN w_d[104]
    DIRECTION INPUT ;
    USE SIGNAL ;
    PORT
      LAYER M4 ;
        RECT  0 55.92 0.084 55.944 ;
    END
  END w_d[104]
  PIN w_d[105]
    DIRECTION INPUT ;
    USE SIGNAL ;
    PORT
      LAYER M4 ;
        RECT  0 56.064 0.084 56.088 ;
    END
  END w_d[105]
  PIN w_d[106]
    DIRECTION INPUT ;
    USE SIGNAL ;
    PORT
      LAYER M4 ;
        RECT  0 56.208 0.084 56.232 ;
    END
  END w_d[106]
  PIN w_d[107]
    DIRECTION INPUT ;
    USE SIGNAL ;
    PORT
      LAYER M4 ;
        RECT  0 56.4 0.084 56.424 ;
    END
  END w_d[107]
  PIN w_d[108]
    DIRECTION INPUT ;
    USE SIGNAL ;
    PORT
      LAYER M4 ;
        RECT  0 56.544 0.084 56.568 ;
    END
  END w_d[108]
  PIN w_d[109]
    DIRECTION INPUT ;
    USE SIGNAL ;
    PORT
      LAYER M4 ;
        RECT  0 56.688 0.084 56.712 ;
    END
  END w_d[109]
  PIN w_d[10]
    DIRECTION INPUT ;
    USE SIGNAL ;
    PORT
      LAYER M4 ;
        RECT  0 41.76 0.084 41.784 ;
    END
  END w_d[10]
  PIN w_d[110]
    DIRECTION INPUT ;
    USE SIGNAL ;
    PORT
      LAYER M4 ;
        RECT  0 56.832 0.084 56.856 ;
    END
  END w_d[110]
  PIN w_d[111]
    DIRECTION INPUT ;
    USE SIGNAL ;
    PORT
      LAYER M4 ;
        RECT  0 56.976 0.084 57 ;
    END
  END w_d[111]
  PIN w_d[112]
    DIRECTION INPUT ;
    USE SIGNAL ;
    PORT
      LAYER M4 ;
        RECT  0 57.12 0.084 57.144 ;
    END
  END w_d[112]
  PIN w_d[113]
    DIRECTION INPUT ;
    USE SIGNAL ;
    PORT
      LAYER M4 ;
        RECT  0 57.264 0.084 57.288 ;
    END
  END w_d[113]
  PIN w_d[114]
    DIRECTION INPUT ;
    USE SIGNAL ;
    PORT
      LAYER M4 ;
        RECT  0 57.408 0.084 57.432 ;
    END
  END w_d[114]
  PIN w_d[115]
    DIRECTION INPUT ;
    USE SIGNAL ;
    PORT
      LAYER M4 ;
        RECT  0 57.6 0.084 57.624 ;
    END
  END w_d[115]
  PIN w_d[116]
    DIRECTION INPUT ;
    USE SIGNAL ;
    PORT
      LAYER M4 ;
        RECT  0 57.744 0.084 57.768 ;
    END
  END w_d[116]
  PIN w_d[117]
    DIRECTION INPUT ;
    USE SIGNAL ;
    PORT
      LAYER M4 ;
        RECT  0 57.888 0.084 57.912 ;
    END
  END w_d[117]
  PIN w_d[118]
    DIRECTION INPUT ;
    USE SIGNAL ;
    PORT
      LAYER M4 ;
        RECT  0 58.032 0.084 58.056 ;
    END
  END w_d[118]
  PIN w_d[119]
    DIRECTION INPUT ;
    USE SIGNAL ;
    PORT
      LAYER M4 ;
        RECT  0 58.176 0.084 58.2 ;
    END
  END w_d[119]
  PIN w_d[11]
    DIRECTION INPUT ;
    USE SIGNAL ;
    PORT
      LAYER M4 ;
        RECT  0 41.904 0.084 41.928 ;
    END
  END w_d[11]
  PIN w_d[120]
    DIRECTION INPUT ;
    USE SIGNAL ;
    PORT
      LAYER M4 ;
        RECT  0 58.32 0.084 58.344 ;
    END
  END w_d[120]
  PIN w_d[121]
    DIRECTION INPUT ;
    USE SIGNAL ;
    PORT
      LAYER M4 ;
        RECT  0 58.464 0.084 58.488 ;
    END
  END w_d[121]
  PIN w_d[122]
    DIRECTION INPUT ;
    USE SIGNAL ;
    PORT
      LAYER M4 ;
        RECT  0 58.656 0.084 58.68 ;
    END
  END w_d[122]
  PIN w_d[123]
    DIRECTION INPUT ;
    USE SIGNAL ;
    PORT
      LAYER M4 ;
        RECT  0 58.8 0.084 58.824 ;
    END
  END w_d[123]
  PIN w_d[124]
    DIRECTION INPUT ;
    USE SIGNAL ;
    PORT
      LAYER M4 ;
        RECT  0 58.944 0.084 58.968 ;
    END
  END w_d[124]
  PIN w_d[125]
    DIRECTION INPUT ;
    USE SIGNAL ;
    PORT
      LAYER M4 ;
        RECT  0 59.088 0.084 59.112 ;
    END
  END w_d[125]
  PIN w_d[126]
    DIRECTION INPUT ;
    USE SIGNAL ;
    PORT
      LAYER M4 ;
        RECT  0 59.232 0.084 59.256 ;
    END
  END w_d[126]
  PIN w_d[127]
    DIRECTION INPUT ;
    USE SIGNAL ;
    PORT
      LAYER M4 ;
        RECT  0 59.376 0.084 59.4 ;
    END
  END w_d[127]
  PIN w_d[128]
    DIRECTION INPUT ;
    USE SIGNAL ;
    PORT
      LAYER M4 ;
        RECT  0 59.52 0.084 59.544 ;
    END
  END w_d[128]
  PIN w_d[129]
    DIRECTION INPUT ;
    USE SIGNAL ;
    PORT
      LAYER M4 ;
        RECT  0 59.712 0.084 59.736 ;
    END
  END w_d[129]
  PIN w_d[12]
    DIRECTION INPUT ;
    USE SIGNAL ;
    PORT
      LAYER M4 ;
        RECT  0 42.048 0.084 42.072 ;
    END
  END w_d[12]
  PIN w_d[130]
    DIRECTION INPUT ;
    USE SIGNAL ;
    PORT
      LAYER M4 ;
        RECT  0 59.856 0.084 59.88 ;
    END
  END w_d[130]
  PIN w_d[131]
    DIRECTION INPUT ;
    USE SIGNAL ;
    PORT
      LAYER M4 ;
        RECT  0 60 0.084 60.024 ;
    END
  END w_d[131]
  PIN w_d[132]
    DIRECTION INPUT ;
    USE SIGNAL ;
    PORT
      LAYER M4 ;
        RECT  0 60.144 0.084 60.168 ;
    END
  END w_d[132]
  PIN w_d[133]
    DIRECTION INPUT ;
    USE SIGNAL ;
    PORT
      LAYER M4 ;
        RECT  0 60.288 0.084 60.312 ;
    END
  END w_d[133]
  PIN w_d[134]
    DIRECTION INPUT ;
    USE SIGNAL ;
    PORT
      LAYER M4 ;
        RECT  0 60.432 0.084 60.456 ;
    END
  END w_d[134]
  PIN w_d[135]
    DIRECTION INPUT ;
    USE SIGNAL ;
    PORT
      LAYER M4 ;
        RECT  0 60.576 0.084 60.6 ;
    END
  END w_d[135]
  PIN w_d[136]
    DIRECTION INPUT ;
    USE SIGNAL ;
    PORT
      LAYER M4 ;
        RECT  0 60.768 0.084 60.792 ;
    END
  END w_d[136]
  PIN w_d[137]
    DIRECTION INPUT ;
    USE SIGNAL ;
    PORT
      LAYER M4 ;
        RECT  0 60.912 0.084 60.936 ;
    END
  END w_d[137]
  PIN w_d[138]
    DIRECTION INPUT ;
    USE SIGNAL ;
    PORT
      LAYER M4 ;
        RECT  0 61.056 0.084 61.08 ;
    END
  END w_d[138]
  PIN w_d[139]
    DIRECTION INPUT ;
    USE SIGNAL ;
    PORT
      LAYER M4 ;
        RECT  0 61.2 0.084 61.224 ;
    END
  END w_d[139]
  PIN w_d[13]
    DIRECTION INPUT ;
    USE SIGNAL ;
    PORT
      LAYER M4 ;
        RECT  0 42.192 0.084 42.216 ;
    END
  END w_d[13]
  PIN w_d[140]
    DIRECTION INPUT ;
    USE SIGNAL ;
    PORT
      LAYER M4 ;
        RECT  0 61.344 0.084 61.368 ;
    END
  END w_d[140]
  PIN w_d[141]
    DIRECTION INPUT ;
    USE SIGNAL ;
    PORT
      LAYER M4 ;
        RECT  0 61.488 0.084 61.512 ;
    END
  END w_d[141]
  PIN w_d[142]
    DIRECTION INPUT ;
    USE SIGNAL ;
    PORT
      LAYER M4 ;
        RECT  0 61.632 0.084 61.656 ;
    END
  END w_d[142]
  PIN w_d[143]
    DIRECTION INPUT ;
    USE SIGNAL ;
    PORT
      LAYER M4 ;
        RECT  0 61.824 0.084 61.848 ;
    END
  END w_d[143]
  PIN w_d[144]
    DIRECTION INPUT ;
    USE SIGNAL ;
    PORT
      LAYER M4 ;
        RECT  0 61.968 0.084 61.992 ;
    END
  END w_d[144]
  PIN w_d[145]
    DIRECTION INPUT ;
    USE SIGNAL ;
    PORT
      LAYER M4 ;
        RECT  0 62.112 0.084 62.136 ;
    END
  END w_d[145]
  PIN w_d[146]
    DIRECTION INPUT ;
    USE SIGNAL ;
    PORT
      LAYER M4 ;
        RECT  0 62.256 0.084 62.28 ;
    END
  END w_d[146]
  PIN w_d[147]
    DIRECTION INPUT ;
    USE SIGNAL ;
    PORT
      LAYER M4 ;
        RECT  0 62.4 0.084 62.424 ;
    END
  END w_d[147]
  PIN w_d[148]
    DIRECTION INPUT ;
    USE SIGNAL ;
    PORT
      LAYER M4 ;
        RECT  0 62.544 0.084 62.568 ;
    END
  END w_d[148]
  PIN w_d[149]
    DIRECTION INPUT ;
    USE SIGNAL ;
    PORT
      LAYER M4 ;
        RECT  0 62.688 0.084 62.712 ;
    END
  END w_d[149]
  PIN w_d[14]
    DIRECTION INPUT ;
    USE SIGNAL ;
    PORT
      LAYER M4 ;
        RECT  0 42.336 0.084 42.36 ;
    END
  END w_d[14]
  PIN w_d[150]
    DIRECTION INPUT ;
    USE SIGNAL ;
    PORT
      LAYER M4 ;
        RECT  0 62.88 0.084 62.904 ;
    END
  END w_d[150]
  PIN w_d[151]
    DIRECTION INPUT ;
    USE SIGNAL ;
    PORT
      LAYER M4 ;
        RECT  0 63.024 0.084 63.048 ;
    END
  END w_d[151]
  PIN w_d[152]
    DIRECTION INPUT ;
    USE SIGNAL ;
    PORT
      LAYER M4 ;
        RECT  0 63.168 0.084 63.192 ;
    END
  END w_d[152]
  PIN w_d[153]
    DIRECTION INPUT ;
    USE SIGNAL ;
    PORT
      LAYER M4 ;
        RECT  0 63.312 0.084 63.336 ;
    END
  END w_d[153]
  PIN w_d[154]
    DIRECTION INPUT ;
    USE SIGNAL ;
    PORT
      LAYER M4 ;
        RECT  0 63.456 0.084 63.48 ;
    END
  END w_d[154]
  PIN w_d[155]
    DIRECTION INPUT ;
    USE SIGNAL ;
    PORT
      LAYER M4 ;
        RECT  0 63.6 0.084 63.624 ;
    END
  END w_d[155]
  PIN w_d[156]
    DIRECTION INPUT ;
    USE SIGNAL ;
    PORT
      LAYER M4 ;
        RECT  0 63.744 0.084 63.768 ;
    END
  END w_d[156]
  PIN w_d[157]
    DIRECTION INPUT ;
    USE SIGNAL ;
    PORT
      LAYER M4 ;
        RECT  0 63.936 0.084 63.96 ;
    END
  END w_d[157]
  PIN w_d[158]
    DIRECTION INPUT ;
    USE SIGNAL ;
    PORT
      LAYER M4 ;
        RECT  0 64.08 0.084 64.104 ;
    END
  END w_d[158]
  PIN w_d[159]
    DIRECTION INPUT ;
    USE SIGNAL ;
    PORT
      LAYER M4 ;
        RECT  0 64.224 0.084 64.248 ;
    END
  END w_d[159]
  PIN w_d[15]
    DIRECTION INPUT ;
    USE SIGNAL ;
    PORT
      LAYER M4 ;
        RECT  0 42.528 0.084 42.552 ;
    END
  END w_d[15]
  PIN w_d[160]
    DIRECTION INPUT ;
    USE SIGNAL ;
    PORT
      LAYER M4 ;
        RECT  0 64.368 0.084 64.392 ;
    END
  END w_d[160]
  PIN w_d[161]
    DIRECTION INPUT ;
    USE SIGNAL ;
    PORT
      LAYER M4 ;
        RECT  0 64.512 0.084 64.536 ;
    END
  END w_d[161]
  PIN w_d[162]
    DIRECTION INPUT ;
    USE SIGNAL ;
    PORT
      LAYER M4 ;
        RECT  0 64.656 0.084 64.68 ;
    END
  END w_d[162]
  PIN w_d[163]
    DIRECTION INPUT ;
    USE SIGNAL ;
    PORT
      LAYER M4 ;
        RECT  0 64.8 0.084 64.824 ;
    END
  END w_d[163]
  PIN w_d[164]
    DIRECTION INPUT ;
    USE SIGNAL ;
    PORT
      LAYER M4 ;
        RECT  0 64.944 0.084 64.968 ;
    END
  END w_d[164]
  PIN w_d[165]
    DIRECTION INPUT ;
    USE SIGNAL ;
    PORT
      LAYER M4 ;
        RECT  0 65.136 0.084 65.16 ;
    END
  END w_d[165]
  PIN w_d[166]
    DIRECTION INPUT ;
    USE SIGNAL ;
    PORT
      LAYER M4 ;
        RECT  0 65.28 0.084 65.304 ;
    END
  END w_d[166]
  PIN w_d[167]
    DIRECTION INPUT ;
    USE SIGNAL ;
    PORT
      LAYER M4 ;
        RECT  0 65.424 0.084 65.448 ;
    END
  END w_d[167]
  PIN w_d[168]
    DIRECTION INPUT ;
    USE SIGNAL ;
    PORT
      LAYER M4 ;
        RECT  0 65.568 0.084 65.592 ;
    END
  END w_d[168]
  PIN w_d[169]
    DIRECTION INPUT ;
    USE SIGNAL ;
    PORT
      LAYER M4 ;
        RECT  0 65.712 0.084 65.736 ;
    END
  END w_d[169]
  PIN w_d[16]
    DIRECTION INPUT ;
    USE SIGNAL ;
    PORT
      LAYER M4 ;
        RECT  0 42.672 0.084 42.696 ;
    END
  END w_d[16]
  PIN w_d[170]
    DIRECTION INPUT ;
    USE SIGNAL ;
    PORT
      LAYER M4 ;
        RECT  0 65.856 0.084 65.88 ;
    END
  END w_d[170]
  PIN w_d[171]
    DIRECTION INPUT ;
    USE SIGNAL ;
    PORT
      LAYER M4 ;
        RECT  0 66 0.084 66.024 ;
    END
  END w_d[171]
  PIN w_d[172]
    DIRECTION INPUT ;
    USE SIGNAL ;
    PORT
      LAYER M4 ;
        RECT  0 66.192 0.084 66.216 ;
    END
  END w_d[172]
  PIN w_d[173]
    DIRECTION INPUT ;
    USE SIGNAL ;
    PORT
      LAYER M4 ;
        RECT  0 66.336 0.084 66.36 ;
    END
  END w_d[173]
  PIN w_d[174]
    DIRECTION INPUT ;
    USE SIGNAL ;
    PORT
      LAYER M4 ;
        RECT  0 66.48 0.084 66.504 ;
    END
  END w_d[174]
  PIN w_d[175]
    DIRECTION INPUT ;
    USE SIGNAL ;
    PORT
      LAYER M4 ;
        RECT  0 66.624 0.084 66.648 ;
    END
  END w_d[175]
  PIN w_d[176]
    DIRECTION INPUT ;
    USE SIGNAL ;
    PORT
      LAYER M4 ;
        RECT  0 66.768 0.084 66.792 ;
    END
  END w_d[176]
  PIN w_d[177]
    DIRECTION INPUT ;
    USE SIGNAL ;
    PORT
      LAYER M4 ;
        RECT  0 66.912 0.084 66.936 ;
    END
  END w_d[177]
  PIN w_d[178]
    DIRECTION INPUT ;
    USE SIGNAL ;
    PORT
      LAYER M4 ;
        RECT  0 67.056 0.084 67.08 ;
    END
  END w_d[178]
  PIN w_d[179]
    DIRECTION INPUT ;
    USE SIGNAL ;
    PORT
      LAYER M4 ;
        RECT  0 67.248 0.084 67.272 ;
    END
  END w_d[179]
  PIN w_d[17]
    DIRECTION INPUT ;
    USE SIGNAL ;
    PORT
      LAYER M4 ;
        RECT  0 42.816 0.084 42.84 ;
    END
  END w_d[17]
  PIN w_d[180]
    DIRECTION INPUT ;
    USE SIGNAL ;
    PORT
      LAYER M4 ;
        RECT  0 67.392 0.084 67.416 ;
    END
  END w_d[180]
  PIN w_d[181]
    DIRECTION INPUT ;
    USE SIGNAL ;
    PORT
      LAYER M4 ;
        RECT  0 67.536 0.084 67.56 ;
    END
  END w_d[181]
  PIN w_d[182]
    DIRECTION INPUT ;
    USE SIGNAL ;
    PORT
      LAYER M4 ;
        RECT  0 67.68 0.084 67.704 ;
    END
  END w_d[182]
  PIN w_d[183]
    DIRECTION INPUT ;
    USE SIGNAL ;
    PORT
      LAYER M4 ;
        RECT  0 67.824 0.084 67.848 ;
    END
  END w_d[183]
  PIN w_d[184]
    DIRECTION INPUT ;
    USE SIGNAL ;
    PORT
      LAYER M4 ;
        RECT  0 67.968 0.084 67.992 ;
    END
  END w_d[184]
  PIN w_d[185]
    DIRECTION INPUT ;
    USE SIGNAL ;
    PORT
      LAYER M4 ;
        RECT  0 68.112 0.084 68.136 ;
    END
  END w_d[185]
  PIN w_d[186]
    DIRECTION INPUT ;
    USE SIGNAL ;
    PORT
      LAYER M4 ;
        RECT  0 68.304 0.084 68.328 ;
    END
  END w_d[186]
  PIN w_d[187]
    DIRECTION INPUT ;
    USE SIGNAL ;
    PORT
      LAYER M4 ;
        RECT  0 68.448 0.084 68.472 ;
    END
  END w_d[187]
  PIN w_d[188]
    DIRECTION INPUT ;
    USE SIGNAL ;
    PORT
      LAYER M4 ;
        RECT  0 68.592 0.084 68.616 ;
    END
  END w_d[188]
  PIN w_d[189]
    DIRECTION INPUT ;
    USE SIGNAL ;
    PORT
      LAYER M4 ;
        RECT  0 68.736 0.084 68.76 ;
    END
  END w_d[189]
  PIN w_d[18]
    DIRECTION INPUT ;
    USE SIGNAL ;
    PORT
      LAYER M4 ;
        RECT  0 42.96 0.084 42.984 ;
    END
  END w_d[18]
  PIN w_d[190]
    DIRECTION INPUT ;
    USE SIGNAL ;
    PORT
      LAYER M4 ;
        RECT  0 68.88 0.084 68.904 ;
    END
  END w_d[190]
  PIN w_d[191]
    DIRECTION INPUT ;
    USE SIGNAL ;
    PORT
      LAYER M4 ;
        RECT  0 69.024 0.084 69.048 ;
    END
  END w_d[191]
  PIN w_d[192]
    DIRECTION INPUT ;
    USE SIGNAL ;
    PORT
      LAYER M4 ;
        RECT  0 69.168 0.084 69.192 ;
    END
  END w_d[192]
  PIN w_d[193]
    DIRECTION INPUT ;
    USE SIGNAL ;
    PORT
      LAYER M4 ;
        RECT  0 69.36 0.084 69.384 ;
    END
  END w_d[193]
  PIN w_d[194]
    DIRECTION INPUT ;
    USE SIGNAL ;
    PORT
      LAYER M4 ;
        RECT  0 69.504 0.084 69.528 ;
    END
  END w_d[194]
  PIN w_d[195]
    DIRECTION INPUT ;
    USE SIGNAL ;
    PORT
      LAYER M4 ;
        RECT  0 69.648 0.084 69.672 ;
    END
  END w_d[195]
  PIN w_d[196]
    DIRECTION INPUT ;
    USE SIGNAL ;
    PORT
      LAYER M4 ;
        RECT  0 69.792 0.084 69.816 ;
    END
  END w_d[196]
  PIN w_d[197]
    DIRECTION INPUT ;
    USE SIGNAL ;
    PORT
      LAYER M4 ;
        RECT  0 69.936 0.084 69.96 ;
    END
  END w_d[197]
  PIN w_d[198]
    DIRECTION INPUT ;
    USE SIGNAL ;
    PORT
      LAYER M4 ;
        RECT  0 70.08 0.084 70.104 ;
    END
  END w_d[198]
  PIN w_d[199]
    DIRECTION INPUT ;
    USE SIGNAL ;
    PORT
      LAYER M4 ;
        RECT  0 70.224 0.084 70.248 ;
    END
  END w_d[199]
  PIN w_d[19]
    DIRECTION INPUT ;
    USE SIGNAL ;
    PORT
      LAYER M4 ;
        RECT  0 43.104 0.084 43.128 ;
    END
  END w_d[19]
  PIN w_d[1]
    DIRECTION INPUT ;
    USE SIGNAL ;
    PORT
      LAYER M4 ;
        RECT  0 40.416 0.084 40.44 ;
    END
  END w_d[1]
  PIN w_d[200]
    DIRECTION INPUT ;
    USE SIGNAL ;
    PORT
      LAYER M4 ;
        RECT  0 70.416 0.084 70.44 ;
    END
  END w_d[200]
  PIN w_d[201]
    DIRECTION INPUT ;
    USE SIGNAL ;
    PORT
      LAYER M4 ;
        RECT  0 70.56 0.084 70.584 ;
    END
  END w_d[201]
  PIN w_d[202]
    DIRECTION INPUT ;
    USE SIGNAL ;
    PORT
      LAYER M4 ;
        RECT  0 70.704 0.084 70.728 ;
    END
  END w_d[202]
  PIN w_d[203]
    DIRECTION INPUT ;
    USE SIGNAL ;
    PORT
      LAYER M4 ;
        RECT  0 70.848 0.084 70.872 ;
    END
  END w_d[203]
  PIN w_d[204]
    DIRECTION INPUT ;
    USE SIGNAL ;
    PORT
      LAYER M4 ;
        RECT  0 70.992 0.084 71.016 ;
    END
  END w_d[204]
  PIN w_d[205]
    DIRECTION INPUT ;
    USE SIGNAL ;
    PORT
      LAYER M4 ;
        RECT  0 71.136 0.084 71.16 ;
    END
  END w_d[205]
  PIN w_d[206]
    DIRECTION INPUT ;
    USE SIGNAL ;
    PORT
      LAYER M4 ;
        RECT  0 71.28 0.084 71.304 ;
    END
  END w_d[206]
  PIN w_d[207]
    DIRECTION INPUT ;
    USE SIGNAL ;
    PORT
      LAYER M4 ;
        RECT  0 71.472 0.084 71.496 ;
    END
  END w_d[207]
  PIN w_d[208]
    DIRECTION INPUT ;
    USE SIGNAL ;
    PORT
      LAYER M4 ;
        RECT  0 71.616 0.084 71.64 ;
    END
  END w_d[208]
  PIN w_d[209]
    DIRECTION INPUT ;
    USE SIGNAL ;
    PORT
      LAYER M4 ;
        RECT  0 71.76 0.084 71.784 ;
    END
  END w_d[209]
  PIN w_d[20]
    DIRECTION INPUT ;
    USE SIGNAL ;
    PORT
      LAYER M4 ;
        RECT  0 43.248 0.084 43.272 ;
    END
  END w_d[20]
  PIN w_d[210]
    DIRECTION INPUT ;
    USE SIGNAL ;
    PORT
      LAYER M4 ;
        RECT  0 71.904 0.084 71.928 ;
    END
  END w_d[210]
  PIN w_d[211]
    DIRECTION INPUT ;
    USE SIGNAL ;
    PORT
      LAYER M4 ;
        RECT  0 72.048 0.084 72.072 ;
    END
  END w_d[211]
  PIN w_d[212]
    DIRECTION INPUT ;
    USE SIGNAL ;
    PORT
      LAYER M4 ;
        RECT  0 72.192 0.084 72.216 ;
    END
  END w_d[212]
  PIN w_d[213]
    DIRECTION INPUT ;
    USE SIGNAL ;
    PORT
      LAYER M4 ;
        RECT  0 72.336 0.084 72.36 ;
    END
  END w_d[213]
  PIN w_d[214]
    DIRECTION INPUT ;
    USE SIGNAL ;
    PORT
      LAYER M4 ;
        RECT  0 72.48 0.084 72.504 ;
    END
  END w_d[214]
  PIN w_d[215]
    DIRECTION INPUT ;
    USE SIGNAL ;
    PORT
      LAYER M4 ;
        RECT  0 72.672 0.084 72.696 ;
    END
  END w_d[215]
  PIN w_d[216]
    DIRECTION INPUT ;
    USE SIGNAL ;
    PORT
      LAYER M4 ;
        RECT  0 72.816 0.084 72.84 ;
    END
  END w_d[216]
  PIN w_d[217]
    DIRECTION INPUT ;
    USE SIGNAL ;
    PORT
      LAYER M4 ;
        RECT  0 72.96 0.084 72.984 ;
    END
  END w_d[217]
  PIN w_d[218]
    DIRECTION INPUT ;
    USE SIGNAL ;
    PORT
      LAYER M4 ;
        RECT  0 73.104 0.084 73.128 ;
    END
  END w_d[218]
  PIN w_d[219]
    DIRECTION INPUT ;
    USE SIGNAL ;
    PORT
      LAYER M4 ;
        RECT  0 73.248 0.084 73.272 ;
    END
  END w_d[219]
  PIN w_d[21]
    DIRECTION INPUT ;
    USE SIGNAL ;
    PORT
      LAYER M4 ;
        RECT  0 43.392 0.084 43.416 ;
    END
  END w_d[21]
  PIN w_d[220]
    DIRECTION INPUT ;
    USE SIGNAL ;
    PORT
      LAYER M4 ;
        RECT  0 73.392 0.084 73.416 ;
    END
  END w_d[220]
  PIN w_d[221]
    DIRECTION INPUT ;
    USE SIGNAL ;
    PORT
      LAYER M4 ;
        RECT  0 73.536 0.084 73.56 ;
    END
  END w_d[221]
  PIN w_d[222]
    DIRECTION INPUT ;
    USE SIGNAL ;
    PORT
      LAYER M4 ;
        RECT  0 73.728 0.084 73.752 ;
    END
  END w_d[222]
  PIN w_d[223]
    DIRECTION INPUT ;
    USE SIGNAL ;
    PORT
      LAYER M4 ;
        RECT  0 73.872 0.084 73.896 ;
    END
  END w_d[223]
  PIN w_d[224]
    DIRECTION INPUT ;
    USE SIGNAL ;
    PORT
      LAYER M4 ;
        RECT  0 74.016 0.084 74.04 ;
    END
  END w_d[224]
  PIN w_d[225]
    DIRECTION INPUT ;
    USE SIGNAL ;
    PORT
      LAYER M4 ;
        RECT  0 74.16 0.084 74.184 ;
    END
  END w_d[225]
  PIN w_d[226]
    DIRECTION INPUT ;
    USE SIGNAL ;
    PORT
      LAYER M4 ;
        RECT  0 74.304 0.084 74.328 ;
    END
  END w_d[226]
  PIN w_d[227]
    DIRECTION INPUT ;
    USE SIGNAL ;
    PORT
      LAYER M4 ;
        RECT  0 74.448 0.084 74.472 ;
    END
  END w_d[227]
  PIN w_d[228]
    DIRECTION INPUT ;
    USE SIGNAL ;
    PORT
      LAYER M4 ;
        RECT  0 74.592 0.084 74.616 ;
    END
  END w_d[228]
  PIN w_d[229]
    DIRECTION INPUT ;
    USE SIGNAL ;
    PORT
      LAYER M4 ;
        RECT  0 74.784 0.084 74.808 ;
    END
  END w_d[229]
  PIN w_d[22]
    DIRECTION INPUT ;
    USE SIGNAL ;
    PORT
      LAYER M4 ;
        RECT  0 43.584 0.084 43.608 ;
    END
  END w_d[22]
  PIN w_d[230]
    DIRECTION INPUT ;
    USE SIGNAL ;
    PORT
      LAYER M4 ;
        RECT  0 74.928 0.084 74.952 ;
    END
  END w_d[230]
  PIN w_d[231]
    DIRECTION INPUT ;
    USE SIGNAL ;
    PORT
      LAYER M4 ;
        RECT  0 75.072 0.084 75.096 ;
    END
  END w_d[231]
  PIN w_d[232]
    DIRECTION INPUT ;
    USE SIGNAL ;
    PORT
      LAYER M4 ;
        RECT  0 75.216 0.084 75.24 ;
    END
  END w_d[232]
  PIN w_d[233]
    DIRECTION INPUT ;
    USE SIGNAL ;
    PORT
      LAYER M4 ;
        RECT  0 75.36 0.084 75.384 ;
    END
  END w_d[233]
  PIN w_d[234]
    DIRECTION INPUT ;
    USE SIGNAL ;
    PORT
      LAYER M4 ;
        RECT  0 75.504 0.084 75.528 ;
    END
  END w_d[234]
  PIN w_d[235]
    DIRECTION INPUT ;
    USE SIGNAL ;
    PORT
      LAYER M4 ;
        RECT  0 75.648 0.084 75.672 ;
    END
  END w_d[235]
  PIN w_d[236]
    DIRECTION INPUT ;
    USE SIGNAL ;
    PORT
      LAYER M4 ;
        RECT  0 75.84 0.084 75.864 ;
    END
  END w_d[236]
  PIN w_d[237]
    DIRECTION INPUT ;
    USE SIGNAL ;
    PORT
      LAYER M4 ;
        RECT  0 75.984 0.084 76.008 ;
    END
  END w_d[237]
  PIN w_d[238]
    DIRECTION INPUT ;
    USE SIGNAL ;
    PORT
      LAYER M4 ;
        RECT  0 76.128 0.084 76.152 ;
    END
  END w_d[238]
  PIN w_d[239]
    DIRECTION INPUT ;
    USE SIGNAL ;
    PORT
      LAYER M4 ;
        RECT  0 76.272 0.084 76.296 ;
    END
  END w_d[239]
  PIN w_d[23]
    DIRECTION INPUT ;
    USE SIGNAL ;
    PORT
      LAYER M4 ;
        RECT  0 43.728 0.084 43.752 ;
    END
  END w_d[23]
  PIN w_d[240]
    DIRECTION INPUT ;
    USE SIGNAL ;
    PORT
      LAYER M4 ;
        RECT  0 76.416 0.084 76.44 ;
    END
  END w_d[240]
  PIN w_d[241]
    DIRECTION INPUT ;
    USE SIGNAL ;
    PORT
      LAYER M4 ;
        RECT  0 76.56 0.084 76.584 ;
    END
  END w_d[241]
  PIN w_d[242]
    DIRECTION INPUT ;
    USE SIGNAL ;
    PORT
      LAYER M4 ;
        RECT  0 76.704 0.084 76.728 ;
    END
  END w_d[242]
  PIN w_d[243]
    DIRECTION INPUT ;
    USE SIGNAL ;
    PORT
      LAYER M4 ;
        RECT  0 76.896 0.084 76.92 ;
    END
  END w_d[243]
  PIN w_d[244]
    DIRECTION INPUT ;
    USE SIGNAL ;
    PORT
      LAYER M4 ;
        RECT  0 77.04 0.084 77.064 ;
    END
  END w_d[244]
  PIN w_d[245]
    DIRECTION INPUT ;
    USE SIGNAL ;
    PORT
      LAYER M4 ;
        RECT  0 77.184 0.084 77.208 ;
    END
  END w_d[245]
  PIN w_d[246]
    DIRECTION INPUT ;
    USE SIGNAL ;
    PORT
      LAYER M4 ;
        RECT  0 77.328 0.084 77.352 ;
    END
  END w_d[246]
  PIN w_d[247]
    DIRECTION INPUT ;
    USE SIGNAL ;
    PORT
      LAYER M4 ;
        RECT  0 77.472 0.084 77.496 ;
    END
  END w_d[247]
  PIN w_d[248]
    DIRECTION INPUT ;
    USE SIGNAL ;
    PORT
      LAYER M4 ;
        RECT  0 77.616 0.084 77.64 ;
    END
  END w_d[248]
  PIN w_d[249]
    DIRECTION INPUT ;
    USE SIGNAL ;
    PORT
      LAYER M4 ;
        RECT  0 77.76 0.084 77.784 ;
    END
  END w_d[249]
  PIN w_d[24]
    DIRECTION INPUT ;
    USE SIGNAL ;
    PORT
      LAYER M4 ;
        RECT  0 43.872 0.084 43.896 ;
    END
  END w_d[24]
  PIN w_d[250]
    DIRECTION INPUT ;
    USE SIGNAL ;
    PORT
      LAYER M4 ;
        RECT  0 77.952 0.084 77.976 ;
    END
  END w_d[250]
  PIN w_d[251]
    DIRECTION INPUT ;
    USE SIGNAL ;
    PORT
      LAYER M4 ;
        RECT  0 78.096 0.084 78.12 ;
    END
  END w_d[251]
  PIN w_d[252]
    DIRECTION INPUT ;
    USE SIGNAL ;
    PORT
      LAYER M4 ;
        RECT  0 78.24 0.084 78.264 ;
    END
  END w_d[252]
  PIN w_d[253]
    DIRECTION INPUT ;
    USE SIGNAL ;
    PORT
      LAYER M4 ;
        RECT  0 78.384 0.084 78.408 ;
    END
  END w_d[253]
  PIN w_d[254]
    DIRECTION INPUT ;
    USE SIGNAL ;
    PORT
      LAYER M4 ;
        RECT  0 78.528 0.084 78.552 ;
    END
  END w_d[254]
  PIN w_d[255]
    DIRECTION INPUT ;
    USE SIGNAL ;
    PORT
      LAYER M4 ;
        RECT  0 78.672 0.084 78.696 ;
    END
  END w_d[255]
  PIN w_d[25]
    DIRECTION INPUT ;
    USE SIGNAL ;
    PORT
      LAYER M4 ;
        RECT  0 44.016 0.084 44.04 ;
    END
  END w_d[25]
  PIN w_d[26]
    DIRECTION INPUT ;
    USE SIGNAL ;
    PORT
      LAYER M4 ;
        RECT  0 44.16 0.084 44.184 ;
    END
  END w_d[26]
  PIN w_d[27]
    DIRECTION INPUT ;
    USE SIGNAL ;
    PORT
      LAYER M4 ;
        RECT  0 44.304 0.084 44.328 ;
    END
  END w_d[27]
  PIN w_d[28]
    DIRECTION INPUT ;
    USE SIGNAL ;
    PORT
      LAYER M4 ;
        RECT  0 44.448 0.084 44.472 ;
    END
  END w_d[28]
  PIN w_d[29]
    DIRECTION INPUT ;
    USE SIGNAL ;
    PORT
      LAYER M4 ;
        RECT  0 44.64 0.084 44.664 ;
    END
  END w_d[29]
  PIN w_d[2]
    DIRECTION INPUT ;
    USE SIGNAL ;
    PORT
      LAYER M4 ;
        RECT  0 40.56 0.084 40.584 ;
    END
  END w_d[2]
  PIN w_d[30]
    DIRECTION INPUT ;
    USE SIGNAL ;
    PORT
      LAYER M4 ;
        RECT  0 44.784 0.084 44.808 ;
    END
  END w_d[30]
  PIN w_d[31]
    DIRECTION INPUT ;
    USE SIGNAL ;
    PORT
      LAYER M4 ;
        RECT  0 44.928 0.084 44.952 ;
    END
  END w_d[31]
  PIN w_d[32]
    DIRECTION INPUT ;
    USE SIGNAL ;
    PORT
      LAYER M4 ;
        RECT  0 45.072 0.084 45.096 ;
    END
  END w_d[32]
  PIN w_d[33]
    DIRECTION INPUT ;
    USE SIGNAL ;
    PORT
      LAYER M4 ;
        RECT  0 45.216 0.084 45.24 ;
    END
  END w_d[33]
  PIN w_d[34]
    DIRECTION INPUT ;
    USE SIGNAL ;
    PORT
      LAYER M4 ;
        RECT  0 45.36 0.084 45.384 ;
    END
  END w_d[34]
  PIN w_d[35]
    DIRECTION INPUT ;
    USE SIGNAL ;
    PORT
      LAYER M4 ;
        RECT  0 45.504 0.084 45.528 ;
    END
  END w_d[35]
  PIN w_d[36]
    DIRECTION INPUT ;
    USE SIGNAL ;
    PORT
      LAYER M4 ;
        RECT  0 45.696 0.084 45.72 ;
    END
  END w_d[36]
  PIN w_d[37]
    DIRECTION INPUT ;
    USE SIGNAL ;
    PORT
      LAYER M4 ;
        RECT  0 45.84 0.084 45.864 ;
    END
  END w_d[37]
  PIN w_d[38]
    DIRECTION INPUT ;
    USE SIGNAL ;
    PORT
      LAYER M4 ;
        RECT  0 45.984 0.084 46.008 ;
    END
  END w_d[38]
  PIN w_d[39]
    DIRECTION INPUT ;
    USE SIGNAL ;
    PORT
      LAYER M4 ;
        RECT  0 46.128 0.084 46.152 ;
    END
  END w_d[39]
  PIN w_d[3]
    DIRECTION INPUT ;
    USE SIGNAL ;
    PORT
      LAYER M4 ;
        RECT  0 40.704 0.084 40.728 ;
    END
  END w_d[3]
  PIN w_d[40]
    DIRECTION INPUT ;
    USE SIGNAL ;
    PORT
      LAYER M4 ;
        RECT  0 46.272 0.084 46.296 ;
    END
  END w_d[40]
  PIN w_d[41]
    DIRECTION INPUT ;
    USE SIGNAL ;
    PORT
      LAYER M4 ;
        RECT  0 46.416 0.084 46.44 ;
    END
  END w_d[41]
  PIN w_d[42]
    DIRECTION INPUT ;
    USE SIGNAL ;
    PORT
      LAYER M4 ;
        RECT  0 46.56 0.084 46.584 ;
    END
  END w_d[42]
  PIN w_d[43]
    DIRECTION INPUT ;
    USE SIGNAL ;
    PORT
      LAYER M4 ;
        RECT  0 46.752 0.084 46.776 ;
    END
  END w_d[43]
  PIN w_d[44]
    DIRECTION INPUT ;
    USE SIGNAL ;
    PORT
      LAYER M4 ;
        RECT  0 46.896 0.084 46.92 ;
    END
  END w_d[44]
  PIN w_d[45]
    DIRECTION INPUT ;
    USE SIGNAL ;
    PORT
      LAYER M4 ;
        RECT  0 47.04 0.084 47.064 ;
    END
  END w_d[45]
  PIN w_d[46]
    DIRECTION INPUT ;
    USE SIGNAL ;
    PORT
      LAYER M4 ;
        RECT  0 47.184 0.084 47.208 ;
    END
  END w_d[46]
  PIN w_d[47]
    DIRECTION INPUT ;
    USE SIGNAL ;
    PORT
      LAYER M4 ;
        RECT  0 47.328 0.084 47.352 ;
    END
  END w_d[47]
  PIN w_d[48]
    DIRECTION INPUT ;
    USE SIGNAL ;
    PORT
      LAYER M4 ;
        RECT  0 47.472 0.084 47.496 ;
    END
  END w_d[48]
  PIN w_d[49]
    DIRECTION INPUT ;
    USE SIGNAL ;
    PORT
      LAYER M4 ;
        RECT  0 47.616 0.084 47.64 ;
    END
  END w_d[49]
  PIN w_d[4]
    DIRECTION INPUT ;
    USE SIGNAL ;
    PORT
      LAYER M4 ;
        RECT  0 40.848 0.084 40.872 ;
    END
  END w_d[4]
  PIN w_d[50]
    DIRECTION INPUT ;
    USE SIGNAL ;
    PORT
      LAYER M4 ;
        RECT  0 47.808 0.084 47.832 ;
    END
  END w_d[50]
  PIN w_d[51]
    DIRECTION INPUT ;
    USE SIGNAL ;
    PORT
      LAYER M4 ;
        RECT  0 47.952 0.084 47.976 ;
    END
  END w_d[51]
  PIN w_d[52]
    DIRECTION INPUT ;
    USE SIGNAL ;
    PORT
      LAYER M4 ;
        RECT  0 48.096 0.084 48.12 ;
    END
  END w_d[52]
  PIN w_d[53]
    DIRECTION INPUT ;
    USE SIGNAL ;
    PORT
      LAYER M4 ;
        RECT  0 48.24 0.084 48.264 ;
    END
  END w_d[53]
  PIN w_d[54]
    DIRECTION INPUT ;
    USE SIGNAL ;
    PORT
      LAYER M4 ;
        RECT  0 48.384 0.084 48.408 ;
    END
  END w_d[54]
  PIN w_d[55]
    DIRECTION INPUT ;
    USE SIGNAL ;
    PORT
      LAYER M4 ;
        RECT  0 48.528 0.084 48.552 ;
    END
  END w_d[55]
  PIN w_d[56]
    DIRECTION INPUT ;
    USE SIGNAL ;
    PORT
      LAYER M4 ;
        RECT  0 48.672 0.084 48.696 ;
    END
  END w_d[56]
  PIN w_d[57]
    DIRECTION INPUT ;
    USE SIGNAL ;
    PORT
      LAYER M4 ;
        RECT  0 48.864 0.084 48.888 ;
    END
  END w_d[57]
  PIN w_d[58]
    DIRECTION INPUT ;
    USE SIGNAL ;
    PORT
      LAYER M4 ;
        RECT  0 49.008 0.084 49.032 ;
    END
  END w_d[58]
  PIN w_d[59]
    DIRECTION INPUT ;
    USE SIGNAL ;
    PORT
      LAYER M4 ;
        RECT  0 49.152 0.084 49.176 ;
    END
  END w_d[59]
  PIN w_d[5]
    DIRECTION INPUT ;
    USE SIGNAL ;
    PORT
      LAYER M4 ;
        RECT  0 40.992 0.084 41.016 ;
    END
  END w_d[5]
  PIN w_d[60]
    DIRECTION INPUT ;
    USE SIGNAL ;
    PORT
      LAYER M4 ;
        RECT  0 49.296 0.084 49.32 ;
    END
  END w_d[60]
  PIN w_d[61]
    DIRECTION INPUT ;
    USE SIGNAL ;
    PORT
      LAYER M4 ;
        RECT  0 49.44 0.084 49.464 ;
    END
  END w_d[61]
  PIN w_d[62]
    DIRECTION INPUT ;
    USE SIGNAL ;
    PORT
      LAYER M4 ;
        RECT  0 49.584 0.084 49.608 ;
    END
  END w_d[62]
  PIN w_d[63]
    DIRECTION INPUT ;
    USE SIGNAL ;
    PORT
      LAYER M4 ;
        RECT  0 49.728 0.084 49.752 ;
    END
  END w_d[63]
  PIN w_d[64]
    DIRECTION INPUT ;
    USE SIGNAL ;
    PORT
      LAYER M4 ;
        RECT  0 49.872 0.084 49.896 ;
    END
  END w_d[64]
  PIN w_d[65]
    DIRECTION INPUT ;
    USE SIGNAL ;
    PORT
      LAYER M4 ;
        RECT  0 50.064 0.084 50.088 ;
    END
  END w_d[65]
  PIN w_d[66]
    DIRECTION INPUT ;
    USE SIGNAL ;
    PORT
      LAYER M4 ;
        RECT  0 50.208 0.084 50.232 ;
    END
  END w_d[66]
  PIN w_d[67]
    DIRECTION INPUT ;
    USE SIGNAL ;
    PORT
      LAYER M4 ;
        RECT  0 50.352 0.084 50.376 ;
    END
  END w_d[67]
  PIN w_d[68]
    DIRECTION INPUT ;
    USE SIGNAL ;
    PORT
      LAYER M4 ;
        RECT  0 50.496 0.084 50.52 ;
    END
  END w_d[68]
  PIN w_d[69]
    DIRECTION INPUT ;
    USE SIGNAL ;
    PORT
      LAYER M4 ;
        RECT  0 50.64 0.084 50.664 ;
    END
  END w_d[69]
  PIN w_d[6]
    DIRECTION INPUT ;
    USE SIGNAL ;
    PORT
      LAYER M4 ;
        RECT  0 41.136 0.084 41.16 ;
    END
  END w_d[6]
  PIN w_d[70]
    DIRECTION INPUT ;
    USE SIGNAL ;
    PORT
      LAYER M4 ;
        RECT  0 50.784 0.084 50.808 ;
    END
  END w_d[70]
  PIN w_d[71]
    DIRECTION INPUT ;
    USE SIGNAL ;
    PORT
      LAYER M4 ;
        RECT  0 50.928 0.084 50.952 ;
    END
  END w_d[71]
  PIN w_d[72]
    DIRECTION INPUT ;
    USE SIGNAL ;
    PORT
      LAYER M4 ;
        RECT  0 51.12 0.084 51.144 ;
    END
  END w_d[72]
  PIN w_d[73]
    DIRECTION INPUT ;
    USE SIGNAL ;
    PORT
      LAYER M4 ;
        RECT  0 51.264 0.084 51.288 ;
    END
  END w_d[73]
  PIN w_d[74]
    DIRECTION INPUT ;
    USE SIGNAL ;
    PORT
      LAYER M4 ;
        RECT  0 51.408 0.084 51.432 ;
    END
  END w_d[74]
  PIN w_d[75]
    DIRECTION INPUT ;
    USE SIGNAL ;
    PORT
      LAYER M4 ;
        RECT  0 51.552 0.084 51.576 ;
    END
  END w_d[75]
  PIN w_d[76]
    DIRECTION INPUT ;
    USE SIGNAL ;
    PORT
      LAYER M4 ;
        RECT  0 51.696 0.084 51.72 ;
    END
  END w_d[76]
  PIN w_d[77]
    DIRECTION INPUT ;
    USE SIGNAL ;
    PORT
      LAYER M4 ;
        RECT  0 51.84 0.084 51.864 ;
    END
  END w_d[77]
  PIN w_d[78]
    DIRECTION INPUT ;
    USE SIGNAL ;
    PORT
      LAYER M4 ;
        RECT  0 51.984 0.084 52.008 ;
    END
  END w_d[78]
  PIN w_d[79]
    DIRECTION INPUT ;
    USE SIGNAL ;
    PORT
      LAYER M4 ;
        RECT  0 52.176 0.084 52.2 ;
    END
  END w_d[79]
  PIN w_d[7]
    DIRECTION INPUT ;
    USE SIGNAL ;
    PORT
      LAYER M4 ;
        RECT  0 41.328 0.084 41.352 ;
    END
  END w_d[7]
  PIN w_d[80]
    DIRECTION INPUT ;
    USE SIGNAL ;
    PORT
      LAYER M4 ;
        RECT  0 52.32 0.084 52.344 ;
    END
  END w_d[80]
  PIN w_d[81]
    DIRECTION INPUT ;
    USE SIGNAL ;
    PORT
      LAYER M4 ;
        RECT  0 52.464 0.084 52.488 ;
    END
  END w_d[81]
  PIN w_d[82]
    DIRECTION INPUT ;
    USE SIGNAL ;
    PORT
      LAYER M4 ;
        RECT  0 52.608 0.084 52.632 ;
    END
  END w_d[82]
  PIN w_d[83]
    DIRECTION INPUT ;
    USE SIGNAL ;
    PORT
      LAYER M4 ;
        RECT  0 52.752 0.084 52.776 ;
    END
  END w_d[83]
  PIN w_d[84]
    DIRECTION INPUT ;
    USE SIGNAL ;
    PORT
      LAYER M4 ;
        RECT  0 52.896 0.084 52.92 ;
    END
  END w_d[84]
  PIN w_d[85]
    DIRECTION INPUT ;
    USE SIGNAL ;
    PORT
      LAYER M4 ;
        RECT  0 53.04 0.084 53.064 ;
    END
  END w_d[85]
  PIN w_d[86]
    DIRECTION INPUT ;
    USE SIGNAL ;
    PORT
      LAYER M4 ;
        RECT  0 53.232 0.084 53.256 ;
    END
  END w_d[86]
  PIN w_d[87]
    DIRECTION INPUT ;
    USE SIGNAL ;
    PORT
      LAYER M4 ;
        RECT  0 53.376 0.084 53.4 ;
    END
  END w_d[87]
  PIN w_d[88]
    DIRECTION INPUT ;
    USE SIGNAL ;
    PORT
      LAYER M4 ;
        RECT  0 53.52 0.084 53.544 ;
    END
  END w_d[88]
  PIN w_d[89]
    DIRECTION INPUT ;
    USE SIGNAL ;
    PORT
      LAYER M4 ;
        RECT  0 53.664 0.084 53.688 ;
    END
  END w_d[89]
  PIN w_d[8]
    DIRECTION INPUT ;
    USE SIGNAL ;
    PORT
      LAYER M4 ;
        RECT  0 41.472 0.084 41.496 ;
    END
  END w_d[8]
  PIN w_d[90]
    DIRECTION INPUT ;
    USE SIGNAL ;
    PORT
      LAYER M4 ;
        RECT  0 53.808 0.084 53.832 ;
    END
  END w_d[90]
  PIN w_d[91]
    DIRECTION INPUT ;
    USE SIGNAL ;
    PORT
      LAYER M4 ;
        RECT  0 53.952 0.084 53.976 ;
    END
  END w_d[91]
  PIN w_d[92]
    DIRECTION INPUT ;
    USE SIGNAL ;
    PORT
      LAYER M4 ;
        RECT  0 54.096 0.084 54.12 ;
    END
  END w_d[92]
  PIN w_d[93]
    DIRECTION INPUT ;
    USE SIGNAL ;
    PORT
      LAYER M4 ;
        RECT  0 54.288 0.084 54.312 ;
    END
  END w_d[93]
  PIN w_d[94]
    DIRECTION INPUT ;
    USE SIGNAL ;
    PORT
      LAYER M4 ;
        RECT  0 54.432 0.084 54.456 ;
    END
  END w_d[94]
  PIN w_d[95]
    DIRECTION INPUT ;
    USE SIGNAL ;
    PORT
      LAYER M4 ;
        RECT  0 54.576 0.084 54.6 ;
    END
  END w_d[95]
  PIN w_d[96]
    DIRECTION INPUT ;
    USE SIGNAL ;
    PORT
      LAYER M4 ;
        RECT  0 54.72 0.084 54.744 ;
    END
  END w_d[96]
  PIN w_d[97]
    DIRECTION INPUT ;
    USE SIGNAL ;
    PORT
      LAYER M4 ;
        RECT  0 54.864 0.084 54.888 ;
    END
  END w_d[97]
  PIN w_d[98]
    DIRECTION INPUT ;
    USE SIGNAL ;
    PORT
      LAYER M4 ;
        RECT  0 55.008 0.084 55.032 ;
    END
  END w_d[98]
  PIN w_d[99]
    DIRECTION INPUT ;
    USE SIGNAL ;
    PORT
      LAYER M4 ;
        RECT  0 55.152 0.084 55.176 ;
    END
  END w_d[99]
  PIN w_d[9]
    DIRECTION INPUT ;
    USE SIGNAL ;
    PORT
      LAYER M4 ;
        RECT  0 41.616 0.084 41.64 ;
    END
  END w_d[9]
  PIN w_v
    DIRECTION INPUT ;
    USE SIGNAL ;
    PORT
      LAYER M4 ;
        RECT  0 78.816 0.084 78.84 ;
    END
  END w_v
  PIN wd[0]
    DIRECTION OUTPUT ;
    USE SIGNAL ;
    PORT
      LAYER M5 ;
        RECT  1.776 79.836 1.8 79.92 ;
    END
  END wd[0]
  PIN wd[100]
    DIRECTION OUTPUT ;
    USE SIGNAL ;
    PORT
      LAYER M5 ;
        RECT  24.864 79.836 24.888 79.92 ;
    END
  END wd[100]
  PIN wd[101]
    DIRECTION OUTPUT ;
    USE SIGNAL ;
    PORT
      LAYER M5 ;
        RECT  25.104 79.836 25.128 79.92 ;
    END
  END wd[101]
  PIN wd[102]
    DIRECTION OUTPUT ;
    USE SIGNAL ;
    PORT
      LAYER M5 ;
        RECT  25.344 79.836 25.368 79.92 ;
    END
  END wd[102]
  PIN wd[103]
    DIRECTION OUTPUT ;
    USE SIGNAL ;
    PORT
      LAYER M5 ;
        RECT  25.536 79.836 25.56 79.92 ;
    END
  END wd[103]
  PIN wd[104]
    DIRECTION OUTPUT ;
    USE SIGNAL ;
    PORT
      LAYER M5 ;
        RECT  25.776 79.836 25.8 79.92 ;
    END
  END wd[104]
  PIN wd[105]
    DIRECTION OUTPUT ;
    USE SIGNAL ;
    PORT
      LAYER M5 ;
        RECT  26.016 79.836 26.04 79.92 ;
    END
  END wd[105]
  PIN wd[106]
    DIRECTION OUTPUT ;
    USE SIGNAL ;
    PORT
      LAYER M5 ;
        RECT  26.256 79.836 26.28 79.92 ;
    END
  END wd[106]
  PIN wd[107]
    DIRECTION OUTPUT ;
    USE SIGNAL ;
    PORT
      LAYER M5 ;
        RECT  26.496 79.836 26.52 79.92 ;
    END
  END wd[107]
  PIN wd[108]
    DIRECTION OUTPUT ;
    USE SIGNAL ;
    PORT
      LAYER M5 ;
        RECT  26.688 79.836 26.712 79.92 ;
    END
  END wd[108]
  PIN wd[109]
    DIRECTION OUTPUT ;
    USE SIGNAL ;
    PORT
      LAYER M5 ;
        RECT  26.928 79.836 26.952 79.92 ;
    END
  END wd[109]
  PIN wd[10]
    DIRECTION OUTPUT ;
    USE SIGNAL ;
    PORT
      LAYER M5 ;
        RECT  4.08 79.836 4.104 79.92 ;
    END
  END wd[10]
  PIN wd[110]
    DIRECTION OUTPUT ;
    USE SIGNAL ;
    PORT
      LAYER M5 ;
        RECT  27.168 79.836 27.192 79.92 ;
    END
  END wd[110]
  PIN wd[111]
    DIRECTION OUTPUT ;
    USE SIGNAL ;
    PORT
      LAYER M5 ;
        RECT  27.408 79.836 27.432 79.92 ;
    END
  END wd[111]
  PIN wd[112]
    DIRECTION OUTPUT ;
    USE SIGNAL ;
    PORT
      LAYER M5 ;
        RECT  27.648 79.836 27.672 79.92 ;
    END
  END wd[112]
  PIN wd[113]
    DIRECTION OUTPUT ;
    USE SIGNAL ;
    PORT
      LAYER M5 ;
        RECT  27.84 79.836 27.864 79.92 ;
    END
  END wd[113]
  PIN wd[114]
    DIRECTION OUTPUT ;
    USE SIGNAL ;
    PORT
      LAYER M5 ;
        RECT  28.08 79.836 28.104 79.92 ;
    END
  END wd[114]
  PIN wd[115]
    DIRECTION OUTPUT ;
    USE SIGNAL ;
    PORT
      LAYER M5 ;
        RECT  28.32 79.836 28.344 79.92 ;
    END
  END wd[115]
  PIN wd[116]
    DIRECTION OUTPUT ;
    USE SIGNAL ;
    PORT
      LAYER M5 ;
        RECT  28.56 79.836 28.584 79.92 ;
    END
  END wd[116]
  PIN wd[117]
    DIRECTION OUTPUT ;
    USE SIGNAL ;
    PORT
      LAYER M5 ;
        RECT  28.8 79.836 28.824 79.92 ;
    END
  END wd[117]
  PIN wd[118]
    DIRECTION OUTPUT ;
    USE SIGNAL ;
    PORT
      LAYER M5 ;
        RECT  28.992 79.836 29.016 79.92 ;
    END
  END wd[118]
  PIN wd[119]
    DIRECTION OUTPUT ;
    USE SIGNAL ;
    PORT
      LAYER M5 ;
        RECT  29.232 79.836 29.256 79.92 ;
    END
  END wd[119]
  PIN wd[11]
    DIRECTION OUTPUT ;
    USE SIGNAL ;
    PORT
      LAYER M5 ;
        RECT  4.32 79.836 4.344 79.92 ;
    END
  END wd[11]
  PIN wd[120]
    DIRECTION OUTPUT ;
    USE SIGNAL ;
    PORT
      LAYER M5 ;
        RECT  29.472 79.836 29.496 79.92 ;
    END
  END wd[120]
  PIN wd[121]
    DIRECTION OUTPUT ;
    USE SIGNAL ;
    PORT
      LAYER M5 ;
        RECT  29.712 79.836 29.736 79.92 ;
    END
  END wd[121]
  PIN wd[122]
    DIRECTION OUTPUT ;
    USE SIGNAL ;
    PORT
      LAYER M5 ;
        RECT  29.952 79.836 29.976 79.92 ;
    END
  END wd[122]
  PIN wd[123]
    DIRECTION OUTPUT ;
    USE SIGNAL ;
    PORT
      LAYER M5 ;
        RECT  30.144 79.836 30.168 79.92 ;
    END
  END wd[123]
  PIN wd[124]
    DIRECTION OUTPUT ;
    USE SIGNAL ;
    PORT
      LAYER M5 ;
        RECT  30.384 79.836 30.408 79.92 ;
    END
  END wd[124]
  PIN wd[125]
    DIRECTION OUTPUT ;
    USE SIGNAL ;
    PORT
      LAYER M5 ;
        RECT  30.624 79.836 30.648 79.92 ;
    END
  END wd[125]
  PIN wd[126]
    DIRECTION OUTPUT ;
    USE SIGNAL ;
    PORT
      LAYER M5 ;
        RECT  30.864 79.836 30.888 79.92 ;
    END
  END wd[126]
  PIN wd[127]
    DIRECTION OUTPUT ;
    USE SIGNAL ;
    PORT
      LAYER M5 ;
        RECT  31.104 79.836 31.128 79.92 ;
    END
  END wd[127]
  PIN wd[128]
    DIRECTION OUTPUT ;
    USE SIGNAL ;
    PORT
      LAYER M5 ;
        RECT  31.296 79.836 31.32 79.92 ;
    END
  END wd[128]
  PIN wd[129]
    DIRECTION OUTPUT ;
    USE SIGNAL ;
    PORT
      LAYER M5 ;
        RECT  31.536 79.836 31.56 79.92 ;
    END
  END wd[129]
  PIN wd[12]
    DIRECTION OUTPUT ;
    USE SIGNAL ;
    PORT
      LAYER M5 ;
        RECT  4.56 79.836 4.584 79.92 ;
    END
  END wd[12]
  PIN wd[130]
    DIRECTION OUTPUT ;
    USE SIGNAL ;
    PORT
      LAYER M5 ;
        RECT  31.776 79.836 31.8 79.92 ;
    END
  END wd[130]
  PIN wd[131]
    DIRECTION OUTPUT ;
    USE SIGNAL ;
    PORT
      LAYER M5 ;
        RECT  32.016 79.836 32.04 79.92 ;
    END
  END wd[131]
  PIN wd[132]
    DIRECTION OUTPUT ;
    USE SIGNAL ;
    PORT
      LAYER M5 ;
        RECT  32.256 79.836 32.28 79.92 ;
    END
  END wd[132]
  PIN wd[133]
    DIRECTION OUTPUT ;
    USE SIGNAL ;
    PORT
      LAYER M5 ;
        RECT  32.496 79.836 32.52 79.92 ;
    END
  END wd[133]
  PIN wd[134]
    DIRECTION OUTPUT ;
    USE SIGNAL ;
    PORT
      LAYER M5 ;
        RECT  32.688 79.836 32.712 79.92 ;
    END
  END wd[134]
  PIN wd[135]
    DIRECTION OUTPUT ;
    USE SIGNAL ;
    PORT
      LAYER M5 ;
        RECT  32.928 79.836 32.952 79.92 ;
    END
  END wd[135]
  PIN wd[136]
    DIRECTION OUTPUT ;
    USE SIGNAL ;
    PORT
      LAYER M5 ;
        RECT  33.168 79.836 33.192 79.92 ;
    END
  END wd[136]
  PIN wd[137]
    DIRECTION OUTPUT ;
    USE SIGNAL ;
    PORT
      LAYER M5 ;
        RECT  33.408 79.836 33.432 79.92 ;
    END
  END wd[137]
  PIN wd[138]
    DIRECTION OUTPUT ;
    USE SIGNAL ;
    PORT
      LAYER M5 ;
        RECT  33.648 79.836 33.672 79.92 ;
    END
  END wd[138]
  PIN wd[139]
    DIRECTION OUTPUT ;
    USE SIGNAL ;
    PORT
      LAYER M5 ;
        RECT  33.84 79.836 33.864 79.92 ;
    END
  END wd[139]
  PIN wd[13]
    DIRECTION OUTPUT ;
    USE SIGNAL ;
    PORT
      LAYER M5 ;
        RECT  4.8 79.836 4.824 79.92 ;
    END
  END wd[13]
  PIN wd[140]
    DIRECTION OUTPUT ;
    USE SIGNAL ;
    PORT
      LAYER M5 ;
        RECT  34.08 79.836 34.104 79.92 ;
    END
  END wd[140]
  PIN wd[141]
    DIRECTION OUTPUT ;
    USE SIGNAL ;
    PORT
      LAYER M5 ;
        RECT  34.32 79.836 34.344 79.92 ;
    END
  END wd[141]
  PIN wd[142]
    DIRECTION OUTPUT ;
    USE SIGNAL ;
    PORT
      LAYER M5 ;
        RECT  34.56 79.836 34.584 79.92 ;
    END
  END wd[142]
  PIN wd[143]
    DIRECTION OUTPUT ;
    USE SIGNAL ;
    PORT
      LAYER M5 ;
        RECT  34.8 79.836 34.824 79.92 ;
    END
  END wd[143]
  PIN wd[144]
    DIRECTION OUTPUT ;
    USE SIGNAL ;
    PORT
      LAYER M5 ;
        RECT  34.992 79.836 35.016 79.92 ;
    END
  END wd[144]
  PIN wd[145]
    DIRECTION OUTPUT ;
    USE SIGNAL ;
    PORT
      LAYER M5 ;
        RECT  35.232 79.836 35.256 79.92 ;
    END
  END wd[145]
  PIN wd[146]
    DIRECTION OUTPUT ;
    USE SIGNAL ;
    PORT
      LAYER M5 ;
        RECT  35.472 79.836 35.496 79.92 ;
    END
  END wd[146]
  PIN wd[147]
    DIRECTION OUTPUT ;
    USE SIGNAL ;
    PORT
      LAYER M5 ;
        RECT  35.712 79.836 35.736 79.92 ;
    END
  END wd[147]
  PIN wd[148]
    DIRECTION OUTPUT ;
    USE SIGNAL ;
    PORT
      LAYER M5 ;
        RECT  35.952 79.836 35.976 79.92 ;
    END
  END wd[148]
  PIN wd[149]
    DIRECTION OUTPUT ;
    USE SIGNAL ;
    PORT
      LAYER M5 ;
        RECT  36.144 79.836 36.168 79.92 ;
    END
  END wd[149]
  PIN wd[14]
    DIRECTION OUTPUT ;
    USE SIGNAL ;
    PORT
      LAYER M5 ;
        RECT  5.04 79.836 5.064 79.92 ;
    END
  END wd[14]
  PIN wd[150]
    DIRECTION OUTPUT ;
    USE SIGNAL ;
    PORT
      LAYER M5 ;
        RECT  36.384 79.836 36.408 79.92 ;
    END
  END wd[150]
  PIN wd[151]
    DIRECTION OUTPUT ;
    USE SIGNAL ;
    PORT
      LAYER M5 ;
        RECT  36.624 79.836 36.648 79.92 ;
    END
  END wd[151]
  PIN wd[152]
    DIRECTION OUTPUT ;
    USE SIGNAL ;
    PORT
      LAYER M5 ;
        RECT  36.864 79.836 36.888 79.92 ;
    END
  END wd[152]
  PIN wd[153]
    DIRECTION OUTPUT ;
    USE SIGNAL ;
    PORT
      LAYER M5 ;
        RECT  37.104 79.836 37.128 79.92 ;
    END
  END wd[153]
  PIN wd[154]
    DIRECTION OUTPUT ;
    USE SIGNAL ;
    PORT
      LAYER M5 ;
        RECT  37.296 79.836 37.32 79.92 ;
    END
  END wd[154]
  PIN wd[155]
    DIRECTION OUTPUT ;
    USE SIGNAL ;
    PORT
      LAYER M5 ;
        RECT  37.536 79.836 37.56 79.92 ;
    END
  END wd[155]
  PIN wd[156]
    DIRECTION OUTPUT ;
    USE SIGNAL ;
    PORT
      LAYER M5 ;
        RECT  37.776 79.836 37.8 79.92 ;
    END
  END wd[156]
  PIN wd[157]
    DIRECTION OUTPUT ;
    USE SIGNAL ;
    PORT
      LAYER M5 ;
        RECT  38.016 79.836 38.04 79.92 ;
    END
  END wd[157]
  PIN wd[158]
    DIRECTION OUTPUT ;
    USE SIGNAL ;
    PORT
      LAYER M5 ;
        RECT  38.256 79.836 38.28 79.92 ;
    END
  END wd[158]
  PIN wd[159]
    DIRECTION OUTPUT ;
    USE SIGNAL ;
    PORT
      LAYER M5 ;
        RECT  38.448 79.836 38.472 79.92 ;
    END
  END wd[159]
  PIN wd[15]
    DIRECTION OUTPUT ;
    USE SIGNAL ;
    PORT
      LAYER M5 ;
        RECT  5.232 79.836 5.256 79.92 ;
    END
  END wd[15]
  PIN wd[160]
    DIRECTION OUTPUT ;
    USE SIGNAL ;
    PORT
      LAYER M5 ;
        RECT  38.688 79.836 38.712 79.92 ;
    END
  END wd[160]
  PIN wd[161]
    DIRECTION OUTPUT ;
    USE SIGNAL ;
    PORT
      LAYER M5 ;
        RECT  38.928 79.836 38.952 79.92 ;
    END
  END wd[161]
  PIN wd[162]
    DIRECTION OUTPUT ;
    USE SIGNAL ;
    PORT
      LAYER M5 ;
        RECT  39.168 79.836 39.192 79.92 ;
    END
  END wd[162]
  PIN wd[163]
    DIRECTION OUTPUT ;
    USE SIGNAL ;
    PORT
      LAYER M5 ;
        RECT  39.408 79.836 39.432 79.92 ;
    END
  END wd[163]
  PIN wd[164]
    DIRECTION OUTPUT ;
    USE SIGNAL ;
    PORT
      LAYER M5 ;
        RECT  39.6 79.836 39.624 79.92 ;
    END
  END wd[164]
  PIN wd[165]
    DIRECTION OUTPUT ;
    USE SIGNAL ;
    PORT
      LAYER M5 ;
        RECT  39.84 79.836 39.864 79.92 ;
    END
  END wd[165]
  PIN wd[166]
    DIRECTION OUTPUT ;
    USE SIGNAL ;
    PORT
      LAYER M5 ;
        RECT  40.08 79.836 40.104 79.92 ;
    END
  END wd[166]
  PIN wd[167]
    DIRECTION OUTPUT ;
    USE SIGNAL ;
    PORT
      LAYER M5 ;
        RECT  40.32 79.836 40.344 79.92 ;
    END
  END wd[167]
  PIN wd[168]
    DIRECTION OUTPUT ;
    USE SIGNAL ;
    PORT
      LAYER M5 ;
        RECT  40.56 79.836 40.584 79.92 ;
    END
  END wd[168]
  PIN wd[169]
    DIRECTION OUTPUT ;
    USE SIGNAL ;
    PORT
      LAYER M5 ;
        RECT  40.8 79.836 40.824 79.92 ;
    END
  END wd[169]
  PIN wd[16]
    DIRECTION OUTPUT ;
    USE SIGNAL ;
    PORT
      LAYER M5 ;
        RECT  5.472 79.836 5.496 79.92 ;
    END
  END wd[16]
  PIN wd[170]
    DIRECTION OUTPUT ;
    USE SIGNAL ;
    PORT
      LAYER M5 ;
        RECT  40.992 79.836 41.016 79.92 ;
    END
  END wd[170]
  PIN wd[171]
    DIRECTION OUTPUT ;
    USE SIGNAL ;
    PORT
      LAYER M5 ;
        RECT  41.232 79.836 41.256 79.92 ;
    END
  END wd[171]
  PIN wd[172]
    DIRECTION OUTPUT ;
    USE SIGNAL ;
    PORT
      LAYER M5 ;
        RECT  41.472 79.836 41.496 79.92 ;
    END
  END wd[172]
  PIN wd[173]
    DIRECTION OUTPUT ;
    USE SIGNAL ;
    PORT
      LAYER M5 ;
        RECT  41.712 79.836 41.736 79.92 ;
    END
  END wd[173]
  PIN wd[174]
    DIRECTION OUTPUT ;
    USE SIGNAL ;
    PORT
      LAYER M5 ;
        RECT  41.952 79.836 41.976 79.92 ;
    END
  END wd[174]
  PIN wd[175]
    DIRECTION OUTPUT ;
    USE SIGNAL ;
    PORT
      LAYER M5 ;
        RECT  42.144 79.836 42.168 79.92 ;
    END
  END wd[175]
  PIN wd[176]
    DIRECTION OUTPUT ;
    USE SIGNAL ;
    PORT
      LAYER M5 ;
        RECT  42.384 79.836 42.408 79.92 ;
    END
  END wd[176]
  PIN wd[177]
    DIRECTION OUTPUT ;
    USE SIGNAL ;
    PORT
      LAYER M5 ;
        RECT  42.624 79.836 42.648 79.92 ;
    END
  END wd[177]
  PIN wd[178]
    DIRECTION OUTPUT ;
    USE SIGNAL ;
    PORT
      LAYER M5 ;
        RECT  42.864 79.836 42.888 79.92 ;
    END
  END wd[178]
  PIN wd[179]
    DIRECTION OUTPUT ;
    USE SIGNAL ;
    PORT
      LAYER M5 ;
        RECT  43.104 79.836 43.128 79.92 ;
    END
  END wd[179]
  PIN wd[17]
    DIRECTION OUTPUT ;
    USE SIGNAL ;
    PORT
      LAYER M5 ;
        RECT  5.712 79.836 5.736 79.92 ;
    END
  END wd[17]
  PIN wd[180]
    DIRECTION OUTPUT ;
    USE SIGNAL ;
    PORT
      LAYER M5 ;
        RECT  43.296 79.836 43.32 79.92 ;
    END
  END wd[180]
  PIN wd[181]
    DIRECTION OUTPUT ;
    USE SIGNAL ;
    PORT
      LAYER M5 ;
        RECT  43.536 79.836 43.56 79.92 ;
    END
  END wd[181]
  PIN wd[182]
    DIRECTION OUTPUT ;
    USE SIGNAL ;
    PORT
      LAYER M5 ;
        RECT  43.776 79.836 43.8 79.92 ;
    END
  END wd[182]
  PIN wd[183]
    DIRECTION OUTPUT ;
    USE SIGNAL ;
    PORT
      LAYER M5 ;
        RECT  44.016 79.836 44.04 79.92 ;
    END
  END wd[183]
  PIN wd[184]
    DIRECTION OUTPUT ;
    USE SIGNAL ;
    PORT
      LAYER M5 ;
        RECT  44.256 79.836 44.28 79.92 ;
    END
  END wd[184]
  PIN wd[185]
    DIRECTION OUTPUT ;
    USE SIGNAL ;
    PORT
      LAYER M5 ;
        RECT  44.448 79.836 44.472 79.92 ;
    END
  END wd[185]
  PIN wd[186]
    DIRECTION OUTPUT ;
    USE SIGNAL ;
    PORT
      LAYER M5 ;
        RECT  44.688 79.836 44.712 79.92 ;
    END
  END wd[186]
  PIN wd[187]
    DIRECTION OUTPUT ;
    USE SIGNAL ;
    PORT
      LAYER M5 ;
        RECT  44.928 79.836 44.952 79.92 ;
    END
  END wd[187]
  PIN wd[188]
    DIRECTION OUTPUT ;
    USE SIGNAL ;
    PORT
      LAYER M5 ;
        RECT  45.168 79.836 45.192 79.92 ;
    END
  END wd[188]
  PIN wd[189]
    DIRECTION OUTPUT ;
    USE SIGNAL ;
    PORT
      LAYER M5 ;
        RECT  45.408 79.836 45.432 79.92 ;
    END
  END wd[189]
  PIN wd[18]
    DIRECTION OUTPUT ;
    USE SIGNAL ;
    PORT
      LAYER M5 ;
        RECT  5.952 79.836 5.976 79.92 ;
    END
  END wd[18]
  PIN wd[190]
    DIRECTION OUTPUT ;
    USE SIGNAL ;
    PORT
      LAYER M5 ;
        RECT  45.6 79.836 45.624 79.92 ;
    END
  END wd[190]
  PIN wd[191]
    DIRECTION OUTPUT ;
    USE SIGNAL ;
    PORT
      LAYER M5 ;
        RECT  45.84 79.836 45.864 79.92 ;
    END
  END wd[191]
  PIN wd[192]
    DIRECTION OUTPUT ;
    USE SIGNAL ;
    PORT
      LAYER M5 ;
        RECT  46.08 79.836 46.104 79.92 ;
    END
  END wd[192]
  PIN wd[193]
    DIRECTION OUTPUT ;
    USE SIGNAL ;
    PORT
      LAYER M5 ;
        RECT  46.32 79.836 46.344 79.92 ;
    END
  END wd[193]
  PIN wd[194]
    DIRECTION OUTPUT ;
    USE SIGNAL ;
    PORT
      LAYER M5 ;
        RECT  46.56 79.836 46.584 79.92 ;
    END
  END wd[194]
  PIN wd[195]
    DIRECTION OUTPUT ;
    USE SIGNAL ;
    PORT
      LAYER M5 ;
        RECT  46.752 79.836 46.776 79.92 ;
    END
  END wd[195]
  PIN wd[196]
    DIRECTION OUTPUT ;
    USE SIGNAL ;
    PORT
      LAYER M5 ;
        RECT  46.992 79.836 47.016 79.92 ;
    END
  END wd[196]
  PIN wd[197]
    DIRECTION OUTPUT ;
    USE SIGNAL ;
    PORT
      LAYER M5 ;
        RECT  47.232 79.836 47.256 79.92 ;
    END
  END wd[197]
  PIN wd[198]
    DIRECTION OUTPUT ;
    USE SIGNAL ;
    PORT
      LAYER M5 ;
        RECT  47.472 79.836 47.496 79.92 ;
    END
  END wd[198]
  PIN wd[199]
    DIRECTION OUTPUT ;
    USE SIGNAL ;
    PORT
      LAYER M5 ;
        RECT  47.712 79.836 47.736 79.92 ;
    END
  END wd[199]
  PIN wd[19]
    DIRECTION OUTPUT ;
    USE SIGNAL ;
    PORT
      LAYER M5 ;
        RECT  6.192 79.836 6.216 79.92 ;
    END
  END wd[19]
  PIN wd[1]
    DIRECTION OUTPUT ;
    USE SIGNAL ;
    PORT
      LAYER M5 ;
        RECT  2.016 79.836 2.04 79.92 ;
    END
  END wd[1]
  PIN wd[200]
    DIRECTION OUTPUT ;
    USE SIGNAL ;
    PORT
      LAYER M5 ;
        RECT  47.904 79.836 47.928 79.92 ;
    END
  END wd[200]
  PIN wd[201]
    DIRECTION OUTPUT ;
    USE SIGNAL ;
    PORT
      LAYER M5 ;
        RECT  48.144 79.836 48.168 79.92 ;
    END
  END wd[201]
  PIN wd[202]
    DIRECTION OUTPUT ;
    USE SIGNAL ;
    PORT
      LAYER M5 ;
        RECT  48.384 79.836 48.408 79.92 ;
    END
  END wd[202]
  PIN wd[203]
    DIRECTION OUTPUT ;
    USE SIGNAL ;
    PORT
      LAYER M5 ;
        RECT  48.624 79.836 48.648 79.92 ;
    END
  END wd[203]
  PIN wd[204]
    DIRECTION OUTPUT ;
    USE SIGNAL ;
    PORT
      LAYER M5 ;
        RECT  48.864 79.836 48.888 79.92 ;
    END
  END wd[204]
  PIN wd[205]
    DIRECTION OUTPUT ;
    USE SIGNAL ;
    PORT
      LAYER M5 ;
        RECT  49.056 79.836 49.08 79.92 ;
    END
  END wd[205]
  PIN wd[206]
    DIRECTION OUTPUT ;
    USE SIGNAL ;
    PORT
      LAYER M5 ;
        RECT  49.296 79.836 49.32 79.92 ;
    END
  END wd[206]
  PIN wd[207]
    DIRECTION OUTPUT ;
    USE SIGNAL ;
    PORT
      LAYER M5 ;
        RECT  49.536 79.836 49.56 79.92 ;
    END
  END wd[207]
  PIN wd[208]
    DIRECTION OUTPUT ;
    USE SIGNAL ;
    PORT
      LAYER M5 ;
        RECT  49.776 79.836 49.8 79.92 ;
    END
  END wd[208]
  PIN wd[209]
    DIRECTION OUTPUT ;
    USE SIGNAL ;
    PORT
      LAYER M5 ;
        RECT  50.016 79.836 50.04 79.92 ;
    END
  END wd[209]
  PIN wd[20]
    DIRECTION OUTPUT ;
    USE SIGNAL ;
    PORT
      LAYER M5 ;
        RECT  6.432 79.836 6.456 79.92 ;
    END
  END wd[20]
  PIN wd[210]
    DIRECTION OUTPUT ;
    USE SIGNAL ;
    PORT
      LAYER M5 ;
        RECT  50.256 79.836 50.28 79.92 ;
    END
  END wd[210]
  PIN wd[211]
    DIRECTION OUTPUT ;
    USE SIGNAL ;
    PORT
      LAYER M5 ;
        RECT  50.448 79.836 50.472 79.92 ;
    END
  END wd[211]
  PIN wd[212]
    DIRECTION OUTPUT ;
    USE SIGNAL ;
    PORT
      LAYER M5 ;
        RECT  50.688 79.836 50.712 79.92 ;
    END
  END wd[212]
  PIN wd[213]
    DIRECTION OUTPUT ;
    USE SIGNAL ;
    PORT
      LAYER M5 ;
        RECT  50.928 79.836 50.952 79.92 ;
    END
  END wd[213]
  PIN wd[214]
    DIRECTION OUTPUT ;
    USE SIGNAL ;
    PORT
      LAYER M5 ;
        RECT  51.168 79.836 51.192 79.92 ;
    END
  END wd[214]
  PIN wd[215]
    DIRECTION OUTPUT ;
    USE SIGNAL ;
    PORT
      LAYER M5 ;
        RECT  51.408 79.836 51.432 79.92 ;
    END
  END wd[215]
  PIN wd[216]
    DIRECTION OUTPUT ;
    USE SIGNAL ;
    PORT
      LAYER M5 ;
        RECT  51.6 79.836 51.624 79.92 ;
    END
  END wd[216]
  PIN wd[217]
    DIRECTION OUTPUT ;
    USE SIGNAL ;
    PORT
      LAYER M5 ;
        RECT  51.84 79.836 51.864 79.92 ;
    END
  END wd[217]
  PIN wd[218]
    DIRECTION OUTPUT ;
    USE SIGNAL ;
    PORT
      LAYER M5 ;
        RECT  52.08 79.836 52.104 79.92 ;
    END
  END wd[218]
  PIN wd[219]
    DIRECTION OUTPUT ;
    USE SIGNAL ;
    PORT
      LAYER M5 ;
        RECT  52.32 79.836 52.344 79.92 ;
    END
  END wd[219]
  PIN wd[21]
    DIRECTION OUTPUT ;
    USE SIGNAL ;
    PORT
      LAYER M5 ;
        RECT  6.624 79.836 6.648 79.92 ;
    END
  END wd[21]
  PIN wd[220]
    DIRECTION OUTPUT ;
    USE SIGNAL ;
    PORT
      LAYER M5 ;
        RECT  52.56 79.836 52.584 79.92 ;
    END
  END wd[220]
  PIN wd[221]
    DIRECTION OUTPUT ;
    USE SIGNAL ;
    PORT
      LAYER M5 ;
        RECT  52.752 79.836 52.776 79.92 ;
    END
  END wd[221]
  PIN wd[222]
    DIRECTION OUTPUT ;
    USE SIGNAL ;
    PORT
      LAYER M5 ;
        RECT  52.992 79.836 53.016 79.92 ;
    END
  END wd[222]
  PIN wd[223]
    DIRECTION OUTPUT ;
    USE SIGNAL ;
    PORT
      LAYER M5 ;
        RECT  53.232 79.836 53.256 79.92 ;
    END
  END wd[223]
  PIN wd[224]
    DIRECTION OUTPUT ;
    USE SIGNAL ;
    PORT
      LAYER M5 ;
        RECT  53.472 79.836 53.496 79.92 ;
    END
  END wd[224]
  PIN wd[225]
    DIRECTION OUTPUT ;
    USE SIGNAL ;
    PORT
      LAYER M5 ;
        RECT  53.712 79.836 53.736 79.92 ;
    END
  END wd[225]
  PIN wd[226]
    DIRECTION OUTPUT ;
    USE SIGNAL ;
    PORT
      LAYER M5 ;
        RECT  53.904 79.836 53.928 79.92 ;
    END
  END wd[226]
  PIN wd[227]
    DIRECTION OUTPUT ;
    USE SIGNAL ;
    PORT
      LAYER M5 ;
        RECT  54.144 79.836 54.168 79.92 ;
    END
  END wd[227]
  PIN wd[228]
    DIRECTION OUTPUT ;
    USE SIGNAL ;
    PORT
      LAYER M5 ;
        RECT  54.384 79.836 54.408 79.92 ;
    END
  END wd[228]
  PIN wd[229]
    DIRECTION OUTPUT ;
    USE SIGNAL ;
    PORT
      LAYER M5 ;
        RECT  54.624 79.836 54.648 79.92 ;
    END
  END wd[229]
  PIN wd[22]
    DIRECTION OUTPUT ;
    USE SIGNAL ;
    PORT
      LAYER M5 ;
        RECT  6.864 79.836 6.888 79.92 ;
    END
  END wd[22]
  PIN wd[230]
    DIRECTION OUTPUT ;
    USE SIGNAL ;
    PORT
      LAYER M5 ;
        RECT  54.864 79.836 54.888 79.92 ;
    END
  END wd[230]
  PIN wd[231]
    DIRECTION OUTPUT ;
    USE SIGNAL ;
    PORT
      LAYER M5 ;
        RECT  55.056 79.836 55.08 79.92 ;
    END
  END wd[231]
  PIN wd[232]
    DIRECTION OUTPUT ;
    USE SIGNAL ;
    PORT
      LAYER M5 ;
        RECT  55.296 79.836 55.32 79.92 ;
    END
  END wd[232]
  PIN wd[233]
    DIRECTION OUTPUT ;
    USE SIGNAL ;
    PORT
      LAYER M5 ;
        RECT  55.536 79.836 55.56 79.92 ;
    END
  END wd[233]
  PIN wd[234]
    DIRECTION OUTPUT ;
    USE SIGNAL ;
    PORT
      LAYER M5 ;
        RECT  55.776 79.836 55.8 79.92 ;
    END
  END wd[234]
  PIN wd[235]
    DIRECTION OUTPUT ;
    USE SIGNAL ;
    PORT
      LAYER M5 ;
        RECT  56.016 79.836 56.04 79.92 ;
    END
  END wd[235]
  PIN wd[236]
    DIRECTION OUTPUT ;
    USE SIGNAL ;
    PORT
      LAYER M5 ;
        RECT  56.208 79.836 56.232 79.92 ;
    END
  END wd[236]
  PIN wd[237]
    DIRECTION OUTPUT ;
    USE SIGNAL ;
    PORT
      LAYER M5 ;
        RECT  56.448 79.836 56.472 79.92 ;
    END
  END wd[237]
  PIN wd[238]
    DIRECTION OUTPUT ;
    USE SIGNAL ;
    PORT
      LAYER M5 ;
        RECT  56.688 79.836 56.712 79.92 ;
    END
  END wd[238]
  PIN wd[239]
    DIRECTION OUTPUT ;
    USE SIGNAL ;
    PORT
      LAYER M5 ;
        RECT  56.928 79.836 56.952 79.92 ;
    END
  END wd[239]
  PIN wd[23]
    DIRECTION OUTPUT ;
    USE SIGNAL ;
    PORT
      LAYER M5 ;
        RECT  7.104 79.836 7.128 79.92 ;
    END
  END wd[23]
  PIN wd[240]
    DIRECTION OUTPUT ;
    USE SIGNAL ;
    PORT
      LAYER M5 ;
        RECT  57.168 79.836 57.192 79.92 ;
    END
  END wd[240]
  PIN wd[241]
    DIRECTION OUTPUT ;
    USE SIGNAL ;
    PORT
      LAYER M5 ;
        RECT  57.36 79.836 57.384 79.92 ;
    END
  END wd[241]
  PIN wd[242]
    DIRECTION OUTPUT ;
    USE SIGNAL ;
    PORT
      LAYER M5 ;
        RECT  57.6 79.836 57.624 79.92 ;
    END
  END wd[242]
  PIN wd[243]
    DIRECTION OUTPUT ;
    USE SIGNAL ;
    PORT
      LAYER M5 ;
        RECT  57.84 79.836 57.864 79.92 ;
    END
  END wd[243]
  PIN wd[244]
    DIRECTION OUTPUT ;
    USE SIGNAL ;
    PORT
      LAYER M5 ;
        RECT  58.08 79.836 58.104 79.92 ;
    END
  END wd[244]
  PIN wd[245]
    DIRECTION OUTPUT ;
    USE SIGNAL ;
    PORT
      LAYER M5 ;
        RECT  58.32 79.836 58.344 79.92 ;
    END
  END wd[245]
  PIN wd[246]
    DIRECTION OUTPUT ;
    USE SIGNAL ;
    PORT
      LAYER M5 ;
        RECT  58.56 79.836 58.584 79.92 ;
    END
  END wd[246]
  PIN wd[247]
    DIRECTION OUTPUT ;
    USE SIGNAL ;
    PORT
      LAYER M5 ;
        RECT  58.752 79.836 58.776 79.92 ;
    END
  END wd[247]
  PIN wd[248]
    DIRECTION OUTPUT ;
    USE SIGNAL ;
    PORT
      LAYER M5 ;
        RECT  58.992 79.836 59.016 79.92 ;
    END
  END wd[248]
  PIN wd[249]
    DIRECTION OUTPUT ;
    USE SIGNAL ;
    PORT
      LAYER M5 ;
        RECT  59.232 79.836 59.256 79.92 ;
    END
  END wd[249]
  PIN wd[24]
    DIRECTION OUTPUT ;
    USE SIGNAL ;
    PORT
      LAYER M5 ;
        RECT  7.344 79.836 7.368 79.92 ;
    END
  END wd[24]
  PIN wd[250]
    DIRECTION OUTPUT ;
    USE SIGNAL ;
    PORT
      LAYER M5 ;
        RECT  59.472 79.836 59.496 79.92 ;
    END
  END wd[250]
  PIN wd[251]
    DIRECTION OUTPUT ;
    USE SIGNAL ;
    PORT
      LAYER M5 ;
        RECT  59.712 79.836 59.736 79.92 ;
    END
  END wd[251]
  PIN wd[252]
    DIRECTION OUTPUT ;
    USE SIGNAL ;
    PORT
      LAYER M5 ;
        RECT  59.904 79.836 59.928 79.92 ;
    END
  END wd[252]
  PIN wd[253]
    DIRECTION OUTPUT ;
    USE SIGNAL ;
    PORT
      LAYER M5 ;
        RECT  60.144 79.836 60.168 79.92 ;
    END
  END wd[253]
  PIN wd[254]
    DIRECTION OUTPUT ;
    USE SIGNAL ;
    PORT
      LAYER M5 ;
        RECT  60.384 79.836 60.408 79.92 ;
    END
  END wd[254]
  PIN wd[255]
    DIRECTION OUTPUT ;
    USE SIGNAL ;
    PORT
      LAYER M5 ;
        RECT  60.624 79.836 60.648 79.92 ;
    END
  END wd[255]
  PIN wd[256]
    DIRECTION OUTPUT ;
    USE SIGNAL ;
    PORT
      LAYER M5 ;
        RECT  60.864 79.836 60.888 79.92 ;
    END
  END wd[256]
  PIN wd[257]
    DIRECTION OUTPUT ;
    USE SIGNAL ;
    PORT
      LAYER M5 ;
        RECT  61.056 79.836 61.08 79.92 ;
    END
  END wd[257]
  PIN wd[258]
    DIRECTION OUTPUT ;
    USE SIGNAL ;
    PORT
      LAYER M5 ;
        RECT  61.296 79.836 61.32 79.92 ;
    END
  END wd[258]
  PIN wd[259]
    DIRECTION OUTPUT ;
    USE SIGNAL ;
    PORT
      LAYER M5 ;
        RECT  61.536 79.836 61.56 79.92 ;
    END
  END wd[259]
  PIN wd[25]
    DIRECTION OUTPUT ;
    USE SIGNAL ;
    PORT
      LAYER M5 ;
        RECT  7.584 79.836 7.608 79.92 ;
    END
  END wd[25]
  PIN wd[260]
    DIRECTION OUTPUT ;
    USE SIGNAL ;
    PORT
      LAYER M5 ;
        RECT  61.776 79.836 61.8 79.92 ;
    END
  END wd[260]
  PIN wd[261]
    DIRECTION OUTPUT ;
    USE SIGNAL ;
    PORT
      LAYER M5 ;
        RECT  62.016 79.836 62.04 79.92 ;
    END
  END wd[261]
  PIN wd[262]
    DIRECTION OUTPUT ;
    USE SIGNAL ;
    PORT
      LAYER M5 ;
        RECT  62.208 79.836 62.232 79.92 ;
    END
  END wd[262]
  PIN wd[263]
    DIRECTION OUTPUT ;
    USE SIGNAL ;
    PORT
      LAYER M5 ;
        RECT  62.448 79.836 62.472 79.92 ;
    END
  END wd[263]
  PIN wd[264]
    DIRECTION OUTPUT ;
    USE SIGNAL ;
    PORT
      LAYER M5 ;
        RECT  62.688 79.836 62.712 79.92 ;
    END
  END wd[264]
  PIN wd[265]
    DIRECTION OUTPUT ;
    USE SIGNAL ;
    PORT
      LAYER M5 ;
        RECT  62.928 79.836 62.952 79.92 ;
    END
  END wd[265]
  PIN wd[266]
    DIRECTION OUTPUT ;
    USE SIGNAL ;
    PORT
      LAYER M5 ;
        RECT  63.168 79.836 63.192 79.92 ;
    END
  END wd[266]
  PIN wd[267]
    DIRECTION OUTPUT ;
    USE SIGNAL ;
    PORT
      LAYER M5 ;
        RECT  63.36 79.836 63.384 79.92 ;
    END
  END wd[267]
  PIN wd[268]
    DIRECTION OUTPUT ;
    USE SIGNAL ;
    PORT
      LAYER M5 ;
        RECT  63.6 79.836 63.624 79.92 ;
    END
  END wd[268]
  PIN wd[269]
    DIRECTION OUTPUT ;
    USE SIGNAL ;
    PORT
      LAYER M5 ;
        RECT  63.84 79.836 63.864 79.92 ;
    END
  END wd[269]
  PIN wd[26]
    DIRECTION OUTPUT ;
    USE SIGNAL ;
    PORT
      LAYER M5 ;
        RECT  7.776 79.836 7.8 79.92 ;
    END
  END wd[26]
  PIN wd[270]
    DIRECTION OUTPUT ;
    USE SIGNAL ;
    PORT
      LAYER M5 ;
        RECT  64.08 79.836 64.104 79.92 ;
    END
  END wd[270]
  PIN wd[271]
    DIRECTION OUTPUT ;
    USE SIGNAL ;
    PORT
      LAYER M5 ;
        RECT  64.32 79.836 64.344 79.92 ;
    END
  END wd[271]
  PIN wd[272]
    DIRECTION OUTPUT ;
    USE SIGNAL ;
    PORT
      LAYER M5 ;
        RECT  64.512 79.836 64.536 79.92 ;
    END
  END wd[272]
  PIN wd[273]
    DIRECTION OUTPUT ;
    USE SIGNAL ;
    PORT
      LAYER M5 ;
        RECT  64.752 79.836 64.776 79.92 ;
    END
  END wd[273]
  PIN wd[274]
    DIRECTION OUTPUT ;
    USE SIGNAL ;
    PORT
      LAYER M5 ;
        RECT  64.992 79.836 65.016 79.92 ;
    END
  END wd[274]
  PIN wd[275]
    DIRECTION OUTPUT ;
    USE SIGNAL ;
    PORT
      LAYER M5 ;
        RECT  65.232 79.836 65.256 79.92 ;
    END
  END wd[275]
  PIN wd[276]
    DIRECTION OUTPUT ;
    USE SIGNAL ;
    PORT
      LAYER M5 ;
        RECT  65.472 79.836 65.496 79.92 ;
    END
  END wd[276]
  PIN wd[277]
    DIRECTION OUTPUT ;
    USE SIGNAL ;
    PORT
      LAYER M5 ;
        RECT  65.664 79.836 65.688 79.92 ;
    END
  END wd[277]
  PIN wd[278]
    DIRECTION OUTPUT ;
    USE SIGNAL ;
    PORT
      LAYER M5 ;
        RECT  65.904 79.836 65.928 79.92 ;
    END
  END wd[278]
  PIN wd[279]
    DIRECTION OUTPUT ;
    USE SIGNAL ;
    PORT
      LAYER M5 ;
        RECT  66.144 79.836 66.168 79.92 ;
    END
  END wd[279]
  PIN wd[27]
    DIRECTION OUTPUT ;
    USE SIGNAL ;
    PORT
      LAYER M5 ;
        RECT  8.016 79.836 8.04 79.92 ;
    END
  END wd[27]
  PIN wd[280]
    DIRECTION OUTPUT ;
    USE SIGNAL ;
    PORT
      LAYER M5 ;
        RECT  66.384 79.836 66.408 79.92 ;
    END
  END wd[280]
  PIN wd[281]
    DIRECTION OUTPUT ;
    USE SIGNAL ;
    PORT
      LAYER M5 ;
        RECT  66.624 79.836 66.648 79.92 ;
    END
  END wd[281]
  PIN wd[282]
    DIRECTION OUTPUT ;
    USE SIGNAL ;
    PORT
      LAYER M5 ;
        RECT  66.816 79.836 66.84 79.92 ;
    END
  END wd[282]
  PIN wd[283]
    DIRECTION OUTPUT ;
    USE SIGNAL ;
    PORT
      LAYER M5 ;
        RECT  67.056 79.836 67.08 79.92 ;
    END
  END wd[283]
  PIN wd[284]
    DIRECTION OUTPUT ;
    USE SIGNAL ;
    PORT
      LAYER M5 ;
        RECT  67.296 79.836 67.32 79.92 ;
    END
  END wd[284]
  PIN wd[285]
    DIRECTION OUTPUT ;
    USE SIGNAL ;
    PORT
      LAYER M5 ;
        RECT  67.536 79.836 67.56 79.92 ;
    END
  END wd[285]
  PIN wd[286]
    DIRECTION OUTPUT ;
    USE SIGNAL ;
    PORT
      LAYER M5 ;
        RECT  67.776 79.836 67.8 79.92 ;
    END
  END wd[286]
  PIN wd[287]
    DIRECTION OUTPUT ;
    USE SIGNAL ;
    PORT
      LAYER M5 ;
        RECT  68.016 79.836 68.04 79.92 ;
    END
  END wd[287]
  PIN wd[28]
    DIRECTION OUTPUT ;
    USE SIGNAL ;
    PORT
      LAYER M5 ;
        RECT  8.256 79.836 8.28 79.92 ;
    END
  END wd[28]
  PIN wd[29]
    DIRECTION OUTPUT ;
    USE SIGNAL ;
    PORT
      LAYER M5 ;
        RECT  8.496 79.836 8.52 79.92 ;
    END
  END wd[29]
  PIN wd[2]
    DIRECTION OUTPUT ;
    USE SIGNAL ;
    PORT
      LAYER M5 ;
        RECT  2.256 79.836 2.28 79.92 ;
    END
  END wd[2]
  PIN wd[30]
    DIRECTION OUTPUT ;
    USE SIGNAL ;
    PORT
      LAYER M5 ;
        RECT  8.736 79.836 8.76 79.92 ;
    END
  END wd[30]
  PIN wd[31]
    DIRECTION OUTPUT ;
    USE SIGNAL ;
    PORT
      LAYER M5 ;
        RECT  8.928 79.836 8.952 79.92 ;
    END
  END wd[31]
  PIN wd[32]
    DIRECTION OUTPUT ;
    USE SIGNAL ;
    PORT
      LAYER M5 ;
        RECT  9.168 79.836 9.192 79.92 ;
    END
  END wd[32]
  PIN wd[33]
    DIRECTION OUTPUT ;
    USE SIGNAL ;
    PORT
      LAYER M5 ;
        RECT  9.408 79.836 9.432 79.92 ;
    END
  END wd[33]
  PIN wd[34]
    DIRECTION OUTPUT ;
    USE SIGNAL ;
    PORT
      LAYER M5 ;
        RECT  9.648 79.836 9.672 79.92 ;
    END
  END wd[34]
  PIN wd[35]
    DIRECTION OUTPUT ;
    USE SIGNAL ;
    PORT
      LAYER M5 ;
        RECT  9.888 79.836 9.912 79.92 ;
    END
  END wd[35]
  PIN wd[36]
    DIRECTION OUTPUT ;
    USE SIGNAL ;
    PORT
      LAYER M5 ;
        RECT  10.08 79.836 10.104 79.92 ;
    END
  END wd[36]
  PIN wd[37]
    DIRECTION OUTPUT ;
    USE SIGNAL ;
    PORT
      LAYER M5 ;
        RECT  10.32 79.836 10.344 79.92 ;
    END
  END wd[37]
  PIN wd[38]
    DIRECTION OUTPUT ;
    USE SIGNAL ;
    PORT
      LAYER M5 ;
        RECT  10.56 79.836 10.584 79.92 ;
    END
  END wd[38]
  PIN wd[39]
    DIRECTION OUTPUT ;
    USE SIGNAL ;
    PORT
      LAYER M5 ;
        RECT  10.8 79.836 10.824 79.92 ;
    END
  END wd[39]
  PIN wd[3]
    DIRECTION OUTPUT ;
    USE SIGNAL ;
    PORT
      LAYER M5 ;
        RECT  2.496 79.836 2.52 79.92 ;
    END
  END wd[3]
  PIN wd[40]
    DIRECTION OUTPUT ;
    USE SIGNAL ;
    PORT
      LAYER M5 ;
        RECT  11.04 79.836 11.064 79.92 ;
    END
  END wd[40]
  PIN wd[41]
    DIRECTION OUTPUT ;
    USE SIGNAL ;
    PORT
      LAYER M5 ;
        RECT  11.232 79.836 11.256 79.92 ;
    END
  END wd[41]
  PIN wd[42]
    DIRECTION OUTPUT ;
    USE SIGNAL ;
    PORT
      LAYER M5 ;
        RECT  11.472 79.836 11.496 79.92 ;
    END
  END wd[42]
  PIN wd[43]
    DIRECTION OUTPUT ;
    USE SIGNAL ;
    PORT
      LAYER M5 ;
        RECT  11.712 79.836 11.736 79.92 ;
    END
  END wd[43]
  PIN wd[44]
    DIRECTION OUTPUT ;
    USE SIGNAL ;
    PORT
      LAYER M5 ;
        RECT  11.952 79.836 11.976 79.92 ;
    END
  END wd[44]
  PIN wd[45]
    DIRECTION OUTPUT ;
    USE SIGNAL ;
    PORT
      LAYER M5 ;
        RECT  12.192 79.836 12.216 79.92 ;
    END
  END wd[45]
  PIN wd[46]
    DIRECTION OUTPUT ;
    USE SIGNAL ;
    PORT
      LAYER M5 ;
        RECT  12.384 79.836 12.408 79.92 ;
    END
  END wd[46]
  PIN wd[47]
    DIRECTION OUTPUT ;
    USE SIGNAL ;
    PORT
      LAYER M5 ;
        RECT  12.624 79.836 12.648 79.92 ;
    END
  END wd[47]
  PIN wd[48]
    DIRECTION OUTPUT ;
    USE SIGNAL ;
    PORT
      LAYER M5 ;
        RECT  12.864 79.836 12.888 79.92 ;
    END
  END wd[48]
  PIN wd[49]
    DIRECTION OUTPUT ;
    USE SIGNAL ;
    PORT
      LAYER M5 ;
        RECT  13.104 79.836 13.128 79.92 ;
    END
  END wd[49]
  PIN wd[4]
    DIRECTION OUTPUT ;
    USE SIGNAL ;
    PORT
      LAYER M5 ;
        RECT  2.736 79.836 2.76 79.92 ;
    END
  END wd[4]
  PIN wd[50]
    DIRECTION OUTPUT ;
    USE SIGNAL ;
    PORT
      LAYER M5 ;
        RECT  13.344 79.836 13.368 79.92 ;
    END
  END wd[50]
  PIN wd[51]
    DIRECTION OUTPUT ;
    USE SIGNAL ;
    PORT
      LAYER M5 ;
        RECT  13.536 79.836 13.56 79.92 ;
    END
  END wd[51]
  PIN wd[52]
    DIRECTION OUTPUT ;
    USE SIGNAL ;
    PORT
      LAYER M5 ;
        RECT  13.776 79.836 13.8 79.92 ;
    END
  END wd[52]
  PIN wd[53]
    DIRECTION OUTPUT ;
    USE SIGNAL ;
    PORT
      LAYER M5 ;
        RECT  14.016 79.836 14.04 79.92 ;
    END
  END wd[53]
  PIN wd[54]
    DIRECTION OUTPUT ;
    USE SIGNAL ;
    PORT
      LAYER M5 ;
        RECT  14.256 79.836 14.28 79.92 ;
    END
  END wd[54]
  PIN wd[55]
    DIRECTION OUTPUT ;
    USE SIGNAL ;
    PORT
      LAYER M5 ;
        RECT  14.496 79.836 14.52 79.92 ;
    END
  END wd[55]
  PIN wd[56]
    DIRECTION OUTPUT ;
    USE SIGNAL ;
    PORT
      LAYER M5 ;
        RECT  14.736 79.836 14.76 79.92 ;
    END
  END wd[56]
  PIN wd[57]
    DIRECTION OUTPUT ;
    USE SIGNAL ;
    PORT
      LAYER M5 ;
        RECT  14.928 79.836 14.952 79.92 ;
    END
  END wd[57]
  PIN wd[58]
    DIRECTION OUTPUT ;
    USE SIGNAL ;
    PORT
      LAYER M5 ;
        RECT  15.168 79.836 15.192 79.92 ;
    END
  END wd[58]
  PIN wd[59]
    DIRECTION OUTPUT ;
    USE SIGNAL ;
    PORT
      LAYER M5 ;
        RECT  15.408 79.836 15.432 79.92 ;
    END
  END wd[59]
  PIN wd[5]
    DIRECTION OUTPUT ;
    USE SIGNAL ;
    PORT
      LAYER M5 ;
        RECT  2.928 79.836 2.952 79.92 ;
    END
  END wd[5]
  PIN wd[60]
    DIRECTION OUTPUT ;
    USE SIGNAL ;
    PORT
      LAYER M5 ;
        RECT  15.648 79.836 15.672 79.92 ;
    END
  END wd[60]
  PIN wd[61]
    DIRECTION OUTPUT ;
    USE SIGNAL ;
    PORT
      LAYER M5 ;
        RECT  15.888 79.836 15.912 79.92 ;
    END
  END wd[61]
  PIN wd[62]
    DIRECTION OUTPUT ;
    USE SIGNAL ;
    PORT
      LAYER M5 ;
        RECT  16.08 79.836 16.104 79.92 ;
    END
  END wd[62]
  PIN wd[63]
    DIRECTION OUTPUT ;
    USE SIGNAL ;
    PORT
      LAYER M5 ;
        RECT  16.32 79.836 16.344 79.92 ;
    END
  END wd[63]
  PIN wd[64]
    DIRECTION OUTPUT ;
    USE SIGNAL ;
    PORT
      LAYER M5 ;
        RECT  16.56 79.836 16.584 79.92 ;
    END
  END wd[64]
  PIN wd[65]
    DIRECTION OUTPUT ;
    USE SIGNAL ;
    PORT
      LAYER M5 ;
        RECT  16.8 79.836 16.824 79.92 ;
    END
  END wd[65]
  PIN wd[66]
    DIRECTION OUTPUT ;
    USE SIGNAL ;
    PORT
      LAYER M5 ;
        RECT  17.04 79.836 17.064 79.92 ;
    END
  END wd[66]
  PIN wd[67]
    DIRECTION OUTPUT ;
    USE SIGNAL ;
    PORT
      LAYER M5 ;
        RECT  17.232 79.836 17.256 79.92 ;
    END
  END wd[67]
  PIN wd[68]
    DIRECTION OUTPUT ;
    USE SIGNAL ;
    PORT
      LAYER M5 ;
        RECT  17.472 79.836 17.496 79.92 ;
    END
  END wd[68]
  PIN wd[69]
    DIRECTION OUTPUT ;
    USE SIGNAL ;
    PORT
      LAYER M5 ;
        RECT  17.712 79.836 17.736 79.92 ;
    END
  END wd[69]
  PIN wd[6]
    DIRECTION OUTPUT ;
    USE SIGNAL ;
    PORT
      LAYER M5 ;
        RECT  3.168 79.836 3.192 79.92 ;
    END
  END wd[6]
  PIN wd[70]
    DIRECTION OUTPUT ;
    USE SIGNAL ;
    PORT
      LAYER M5 ;
        RECT  17.952 79.836 17.976 79.92 ;
    END
  END wd[70]
  PIN wd[71]
    DIRECTION OUTPUT ;
    USE SIGNAL ;
    PORT
      LAYER M5 ;
        RECT  18.192 79.836 18.216 79.92 ;
    END
  END wd[71]
  PIN wd[72]
    DIRECTION OUTPUT ;
    USE SIGNAL ;
    PORT
      LAYER M5 ;
        RECT  18.384 79.836 18.408 79.92 ;
    END
  END wd[72]
  PIN wd[73]
    DIRECTION OUTPUT ;
    USE SIGNAL ;
    PORT
      LAYER M5 ;
        RECT  18.624 79.836 18.648 79.92 ;
    END
  END wd[73]
  PIN wd[74]
    DIRECTION OUTPUT ;
    USE SIGNAL ;
    PORT
      LAYER M5 ;
        RECT  18.864 79.836 18.888 79.92 ;
    END
  END wd[74]
  PIN wd[75]
    DIRECTION OUTPUT ;
    USE SIGNAL ;
    PORT
      LAYER M5 ;
        RECT  19.104 79.836 19.128 79.92 ;
    END
  END wd[75]
  PIN wd[76]
    DIRECTION OUTPUT ;
    USE SIGNAL ;
    PORT
      LAYER M5 ;
        RECT  19.344 79.836 19.368 79.92 ;
    END
  END wd[76]
  PIN wd[77]
    DIRECTION OUTPUT ;
    USE SIGNAL ;
    PORT
      LAYER M5 ;
        RECT  19.536 79.836 19.56 79.92 ;
    END
  END wd[77]
  PIN wd[78]
    DIRECTION OUTPUT ;
    USE SIGNAL ;
    PORT
      LAYER M5 ;
        RECT  19.776 79.836 19.8 79.92 ;
    END
  END wd[78]
  PIN wd[79]
    DIRECTION OUTPUT ;
    USE SIGNAL ;
    PORT
      LAYER M5 ;
        RECT  20.016 79.836 20.04 79.92 ;
    END
  END wd[79]
  PIN wd[7]
    DIRECTION OUTPUT ;
    USE SIGNAL ;
    PORT
      LAYER M5 ;
        RECT  3.408 79.836 3.432 79.92 ;
    END
  END wd[7]
  PIN wd[80]
    DIRECTION OUTPUT ;
    USE SIGNAL ;
    PORT
      LAYER M5 ;
        RECT  20.256 79.836 20.28 79.92 ;
    END
  END wd[80]
  PIN wd[81]
    DIRECTION OUTPUT ;
    USE SIGNAL ;
    PORT
      LAYER M5 ;
        RECT  20.496 79.836 20.52 79.92 ;
    END
  END wd[81]
  PIN wd[82]
    DIRECTION OUTPUT ;
    USE SIGNAL ;
    PORT
      LAYER M5 ;
        RECT  20.688 79.836 20.712 79.92 ;
    END
  END wd[82]
  PIN wd[83]
    DIRECTION OUTPUT ;
    USE SIGNAL ;
    PORT
      LAYER M5 ;
        RECT  20.928 79.836 20.952 79.92 ;
    END
  END wd[83]
  PIN wd[84]
    DIRECTION OUTPUT ;
    USE SIGNAL ;
    PORT
      LAYER M5 ;
        RECT  21.168 79.836 21.192 79.92 ;
    END
  END wd[84]
  PIN wd[85]
    DIRECTION OUTPUT ;
    USE SIGNAL ;
    PORT
      LAYER M5 ;
        RECT  21.408 79.836 21.432 79.92 ;
    END
  END wd[85]
  PIN wd[86]
    DIRECTION OUTPUT ;
    USE SIGNAL ;
    PORT
      LAYER M5 ;
        RECT  21.648 79.836 21.672 79.92 ;
    END
  END wd[86]
  PIN wd[87]
    DIRECTION OUTPUT ;
    USE SIGNAL ;
    PORT
      LAYER M5 ;
        RECT  21.84 79.836 21.864 79.92 ;
    END
  END wd[87]
  PIN wd[88]
    DIRECTION OUTPUT ;
    USE SIGNAL ;
    PORT
      LAYER M5 ;
        RECT  22.08 79.836 22.104 79.92 ;
    END
  END wd[88]
  PIN wd[89]
    DIRECTION OUTPUT ;
    USE SIGNAL ;
    PORT
      LAYER M5 ;
        RECT  22.32 79.836 22.344 79.92 ;
    END
  END wd[89]
  PIN wd[8]
    DIRECTION OUTPUT ;
    USE SIGNAL ;
    PORT
      LAYER M5 ;
        RECT  3.648 79.836 3.672 79.92 ;
    END
  END wd[8]
  PIN wd[90]
    DIRECTION OUTPUT ;
    USE SIGNAL ;
    PORT
      LAYER M5 ;
        RECT  22.56 79.836 22.584 79.92 ;
    END
  END wd[90]
  PIN wd[91]
    DIRECTION OUTPUT ;
    USE SIGNAL ;
    PORT
      LAYER M5 ;
        RECT  22.8 79.836 22.824 79.92 ;
    END
  END wd[91]
  PIN wd[92]
    DIRECTION OUTPUT ;
    USE SIGNAL ;
    PORT
      LAYER M5 ;
        RECT  22.992 79.836 23.016 79.92 ;
    END
  END wd[92]
  PIN wd[93]
    DIRECTION OUTPUT ;
    USE SIGNAL ;
    PORT
      LAYER M5 ;
        RECT  23.232 79.836 23.256 79.92 ;
    END
  END wd[93]
  PIN wd[94]
    DIRECTION OUTPUT ;
    USE SIGNAL ;
    PORT
      LAYER M5 ;
        RECT  23.472 79.836 23.496 79.92 ;
    END
  END wd[94]
  PIN wd[95]
    DIRECTION OUTPUT ;
    USE SIGNAL ;
    PORT
      LAYER M5 ;
        RECT  23.712 79.836 23.736 79.92 ;
    END
  END wd[95]
  PIN wd[96]
    DIRECTION OUTPUT ;
    USE SIGNAL ;
    PORT
      LAYER M5 ;
        RECT  23.952 79.836 23.976 79.92 ;
    END
  END wd[96]
  PIN wd[97]
    DIRECTION OUTPUT ;
    USE SIGNAL ;
    PORT
      LAYER M5 ;
        RECT  24.192 79.836 24.216 79.92 ;
    END
  END wd[97]
  PIN wd[98]
    DIRECTION OUTPUT ;
    USE SIGNAL ;
    PORT
      LAYER M5 ;
        RECT  24.384 79.836 24.408 79.92 ;
    END
  END wd[98]
  PIN wd[99]
    DIRECTION OUTPUT ;
    USE SIGNAL ;
    PORT
      LAYER M5 ;
        RECT  24.624 79.836 24.648 79.92 ;
    END
  END wd[99]
  PIN wd[9]
    DIRECTION OUTPUT ;
    USE SIGNAL ;
    PORT
      LAYER M5 ;
        RECT  3.888 79.836 3.912 79.92 ;
    END
  END wd[9]
  PIN VDD
    DIRECTION INOUT ;
    USE POWER ;
    PORT
      LAYER M5 ;
        RECT  61.992 2.151 62.112 77.769 ;
        RECT  56.592 2.151 56.712 77.769 ;
        RECT  51.192 2.151 51.312 77.769 ;
        RECT  45.792 2.151 45.912 77.769 ;
        RECT  40.392 2.151 40.512 77.769 ;
        RECT  34.992 2.151 35.112 77.769 ;
        RECT  29.592 2.151 29.712 77.769 ;
        RECT  24.192 2.151 24.312 77.769 ;
        RECT  18.792 2.151 18.912 77.769 ;
        RECT  13.392 2.151 13.512 77.769 ;
        RECT  7.992 2.151 8.112 77.769 ;
        RECT  2.592 2.151 2.712 77.769 ;
    END
  END VDD
  PIN VSS
    DIRECTION INOUT ;
    USE GROUND ;
    PORT
      LAYER M5 ;
        RECT  61.8 2.137 61.92 77.783 ;
        RECT  56.4 2.137 56.52 77.783 ;
        RECT  51 2.137 51.12 77.783 ;
        RECT  45.6 2.137 45.72 77.783 ;
        RECT  40.2 2.137 40.32 77.783 ;
        RECT  34.8 2.137 34.92 77.783 ;
        RECT  29.4 2.137 29.52 77.783 ;
        RECT  24 2.137 24.12 77.783 ;
        RECT  18.6 2.137 18.72 77.783 ;
        RECT  13.2 2.137 13.32 77.783 ;
        RECT  7.8 2.137 7.92 77.783 ;
        RECT  2.4 2.137 2.52 77.783 ;
    END
  END VSS
  OBS
    LAYER RVTN ;
     RECT  2.16 2.16 66.96 2.295 ;
     RECT  2.16 2.565 66.96 2.835 ;
     RECT  2.16 3.105 66.96 3.375 ;
     RECT  2.16 3.645 66.96 3.915 ;
     RECT  2.16 4.185 66.96 4.455 ;
     RECT  2.16 4.725 66.96 4.995 ;
     RECT  2.16 5.265 66.96 5.535 ;
     RECT  2.16 5.805 66.96 6.075 ;
     RECT  2.16 6.345 66.96 6.615 ;
     RECT  2.16 6.885 66.96 7.155 ;
     RECT  2.16 7.425 66.96 7.695 ;
     RECT  2.16 7.965 66.96 8.235 ;
     RECT  2.16 8.505 66.96 8.775 ;
     RECT  2.16 9.045 66.96 9.315 ;
     RECT  2.16 9.585 66.96 9.855 ;
     RECT  2.16 10.125 66.96 10.395 ;
     RECT  2.16 10.665 66.96 10.935 ;
     RECT  2.16 11.205 66.96 11.475 ;
     RECT  2.16 11.745 66.96 12.015 ;
     RECT  2.16 12.285 66.96 12.555 ;
     RECT  2.16 12.825 66.96 13.095 ;
     RECT  2.16 13.365 66.96 13.635 ;
     RECT  2.16 13.905 66.96 14.175 ;
     RECT  2.16 14.445 66.96 14.715 ;
     RECT  2.16 14.985 66.96 15.255 ;
     RECT  2.16 15.525 66.96 15.795 ;
     RECT  2.16 16.065 66.96 16.335 ;
     RECT  2.16 16.605 66.96 16.875 ;
     RECT  2.16 17.145 66.96 17.415 ;
     RECT  2.16 17.685 66.96 17.955 ;
     RECT  2.16 18.225 66.96 18.495 ;
     RECT  2.16 18.765 66.96 19.035 ;
     RECT  2.16 19.305 66.96 19.575 ;
     RECT  2.16 19.845 66.96 20.115 ;
     RECT  2.16 20.385 66.96 20.655 ;
     RECT  2.16 20.925 66.96 21.195 ;
     RECT  2.16 21.465 66.96 21.735 ;
     RECT  2.16 22.005 66.96 22.275 ;
     RECT  2.16 22.545 66.96 22.815 ;
     RECT  2.16 23.085 66.96 23.355 ;
     RECT  2.16 23.625 66.96 23.895 ;
     RECT  2.16 24.165 66.96 24.435 ;
     RECT  2.16 24.705 66.96 24.975 ;
     RECT  2.16 25.245 66.96 25.515 ;
     RECT  2.16 25.785 66.96 26.055 ;
     RECT  2.16 26.325 66.96 26.595 ;
     RECT  2.16 26.865 66.96 27.135 ;
     RECT  2.16 27.405 66.96 27.675 ;
     RECT  2.16 27.945 66.96 28.215 ;
     RECT  2.16 28.485 66.96 28.755 ;
     RECT  2.16 29.025 66.96 29.295 ;
     RECT  2.16 29.565 66.96 29.835 ;
     RECT  2.16 30.105 66.96 30.375 ;
     RECT  2.16 30.645 66.96 30.915 ;
     RECT  2.16 31.185 66.96 31.455 ;
     RECT  2.16 31.725 66.96 31.995 ;
     RECT  2.16 32.265 66.96 32.535 ;
     RECT  2.16 32.805 66.96 33.075 ;
     RECT  2.16 33.345 66.96 33.615 ;
     RECT  2.16 33.885 66.96 34.155 ;
     RECT  2.16 34.425 66.96 34.695 ;
     RECT  2.16 34.965 66.96 35.235 ;
     RECT  2.16 35.505 66.96 35.775 ;
     RECT  2.16 36.045 66.96 36.315 ;
     RECT  2.16 36.585 66.96 36.855 ;
     RECT  2.16 37.125 66.96 37.395 ;
     RECT  2.16 37.665 66.96 37.935 ;
     RECT  2.16 38.205 66.96 38.475 ;
     RECT  2.16 38.745 66.96 39.015 ;
     RECT  2.16 39.285 66.96 39.555 ;
     RECT  2.16 39.825 66.96 40.095 ;
     RECT  2.16 40.365 66.96 40.635 ;
     RECT  2.16 40.905 66.96 41.175 ;
     RECT  2.16 41.445 66.96 41.715 ;
     RECT  2.16 41.985 66.96 42.255 ;
     RECT  2.16 42.525 66.96 42.795 ;
     RECT  2.16 43.065 66.96 43.335 ;
     RECT  2.16 43.605 66.96 43.875 ;
     RECT  2.16 44.145 66.96 44.415 ;
     RECT  2.16 44.685 66.96 44.955 ;
     RECT  2.16 45.225 66.96 45.495 ;
     RECT  2.16 45.765 66.96 46.035 ;
     RECT  2.16 46.305 66.96 46.575 ;
     RECT  2.16 46.845 66.96 47.115 ;
     RECT  2.16 47.385 66.96 47.655 ;
     RECT  2.16 47.925 66.96 48.195 ;
     RECT  2.16 48.465 66.96 48.735 ;
     RECT  2.16 49.005 66.96 49.275 ;
     RECT  2.16 49.545 66.96 49.815 ;
     RECT  2.16 50.085 66.96 50.355 ;
     RECT  2.16 50.625 66.96 50.895 ;
     RECT  2.16 51.165 66.96 51.435 ;
     RECT  2.16 51.705 66.96 51.975 ;
     RECT  2.16 52.245 66.96 52.515 ;
     RECT  2.16 52.785 66.96 53.055 ;
     RECT  2.16 53.325 66.96 53.595 ;
     RECT  2.16 53.865 66.96 54.135 ;
     RECT  2.16 54.405 66.96 54.675 ;
     RECT  2.16 54.945 66.96 55.215 ;
     RECT  2.16 55.485 66.96 55.755 ;
     RECT  2.16 56.025 66.96 56.295 ;
     RECT  2.16 56.565 66.96 56.835 ;
     RECT  2.16 57.105 66.96 57.375 ;
     RECT  2.16 57.645 66.96 57.915 ;
     RECT  2.16 58.185 66.96 58.455 ;
     RECT  2.16 58.725 66.96 58.995 ;
     RECT  2.16 59.265 66.96 59.535 ;
     RECT  2.16 59.805 66.96 60.075 ;
     RECT  2.16 60.345 66.96 60.615 ;
     RECT  2.16 60.885 66.96 61.155 ;
     RECT  2.16 61.425 66.96 61.695 ;
     RECT  2.16 61.965 66.96 62.235 ;
     RECT  2.16 62.505 66.96 62.775 ;
     RECT  2.16 63.045 66.96 63.315 ;
     RECT  2.16 63.585 66.96 63.855 ;
     RECT  2.16 64.125 66.96 64.395 ;
     RECT  2.16 64.665 66.96 64.935 ;
     RECT  2.16 65.205 66.96 65.475 ;
     RECT  2.16 65.745 66.96 66.015 ;
     RECT  2.16 66.285 66.96 66.555 ;
     RECT  2.16 66.825 66.96 67.095 ;
     RECT  2.16 67.365 66.96 67.635 ;
     RECT  2.16 67.905 66.96 68.175 ;
     RECT  2.16 68.445 66.96 68.715 ;
     RECT  2.16 68.985 66.96 69.255 ;
     RECT  2.16 69.525 66.96 69.795 ;
     RECT  2.16 70.065 66.96 70.335 ;
     RECT  2.16 70.605 66.96 70.875 ;
     RECT  2.16 71.145 66.96 71.415 ;
     RECT  2.16 71.685 66.96 71.955 ;
     RECT  2.16 72.225 66.96 72.495 ;
     RECT  2.16 72.765 66.96 73.035 ;
     RECT  2.16 73.305 66.96 73.575 ;
     RECT  2.16 73.845 66.96 74.115 ;
     RECT  2.16 74.385 66.96 74.655 ;
     RECT  2.16 74.925 66.96 75.195 ;
     RECT  2.16 75.465 66.96 75.735 ;
     RECT  2.16 76.005 66.96 76.275 ;
     RECT  2.16 76.545 66.96 76.815 ;
     RECT  2.16 77.085 66.96 77.355 ;
     RECT  2.16 77.625 66.96 77.76 ;
    LAYER RVTP ;
     RECT  2.16 2.295 66.96 2.565 ;
     RECT  2.16 2.835 66.96 3.105 ;
     RECT  2.16 3.375 66.96 3.645 ;
     RECT  2.16 3.915 66.96 4.185 ;
     RECT  2.16 4.455 66.96 4.725 ;
     RECT  2.16 4.995 66.96 5.265 ;
     RECT  2.16 5.535 66.96 5.805 ;
     RECT  2.16 6.075 66.96 6.345 ;
     RECT  2.16 6.615 66.96 6.885 ;
     RECT  2.16 7.155 66.96 7.425 ;
     RECT  2.16 7.695 66.96 7.965 ;
     RECT  2.16 8.235 66.96 8.505 ;
     RECT  2.16 8.775 66.96 9.045 ;
     RECT  2.16 9.315 66.96 9.585 ;
     RECT  2.16 9.855 66.96 10.125 ;
     RECT  2.16 10.395 66.96 10.665 ;
     RECT  2.16 10.935 66.96 11.205 ;
     RECT  2.16 11.475 66.96 11.745 ;
     RECT  2.16 12.015 66.96 12.285 ;
     RECT  2.16 12.555 66.96 12.825 ;
     RECT  2.16 13.095 66.96 13.365 ;
     RECT  2.16 13.635 66.96 13.905 ;
     RECT  2.16 14.175 66.96 14.445 ;
     RECT  2.16 14.715 66.96 14.985 ;
     RECT  2.16 15.255 66.96 15.525 ;
     RECT  2.16 15.795 66.96 16.065 ;
     RECT  2.16 16.335 66.96 16.605 ;
     RECT  2.16 16.875 66.96 17.145 ;
     RECT  2.16 17.415 66.96 17.685 ;
     RECT  2.16 17.955 66.96 18.225 ;
     RECT  2.16 18.495 66.96 18.765 ;
     RECT  2.16 19.035 66.96 19.305 ;
     RECT  2.16 19.575 66.96 19.845 ;
     RECT  2.16 20.115 66.96 20.385 ;
     RECT  2.16 20.655 66.96 20.925 ;
     RECT  2.16 21.195 66.96 21.465 ;
     RECT  2.16 21.735 66.96 22.005 ;
     RECT  2.16 22.275 66.96 22.545 ;
     RECT  2.16 22.815 66.96 23.085 ;
     RECT  2.16 23.355 66.96 23.625 ;
     RECT  2.16 23.895 66.96 24.165 ;
     RECT  2.16 24.435 66.96 24.705 ;
     RECT  2.16 24.975 66.96 25.245 ;
     RECT  2.16 25.515 66.96 25.785 ;
     RECT  2.16 26.055 66.96 26.325 ;
     RECT  2.16 26.595 66.96 26.865 ;
     RECT  2.16 27.135 66.96 27.405 ;
     RECT  2.16 27.675 66.96 27.945 ;
     RECT  2.16 28.215 66.96 28.485 ;
     RECT  2.16 28.755 66.96 29.025 ;
     RECT  2.16 29.295 66.96 29.565 ;
     RECT  2.16 29.835 66.96 30.105 ;
     RECT  2.16 30.375 66.96 30.645 ;
     RECT  2.16 30.915 66.96 31.185 ;
     RECT  2.16 31.455 66.96 31.725 ;
     RECT  2.16 31.995 66.96 32.265 ;
     RECT  2.16 32.535 66.96 32.805 ;
     RECT  2.16 33.075 66.96 33.345 ;
     RECT  2.16 33.615 66.96 33.885 ;
     RECT  2.16 34.155 66.96 34.425 ;
     RECT  2.16 34.695 66.96 34.965 ;
     RECT  2.16 35.235 66.96 35.505 ;
     RECT  2.16 35.775 66.96 36.045 ;
     RECT  2.16 36.315 66.96 36.585 ;
     RECT  2.16 36.855 66.96 37.125 ;
     RECT  2.16 37.395 66.96 37.665 ;
     RECT  2.16 37.935 66.96 38.205 ;
     RECT  2.16 38.475 66.96 38.745 ;
     RECT  2.16 39.015 66.96 39.285 ;
     RECT  2.16 39.555 66.96 39.825 ;
     RECT  2.16 40.095 66.96 40.365 ;
     RECT  2.16 40.635 66.96 40.905 ;
     RECT  2.16 41.175 66.96 41.445 ;
     RECT  2.16 41.715 66.96 41.985 ;
     RECT  2.16 42.255 66.96 42.525 ;
     RECT  2.16 42.795 66.96 43.065 ;
     RECT  2.16 43.335 66.96 43.605 ;
     RECT  2.16 43.875 66.96 44.145 ;
     RECT  2.16 44.415 66.96 44.685 ;
     RECT  2.16 44.955 66.96 45.225 ;
     RECT  2.16 45.495 66.96 45.765 ;
     RECT  2.16 46.035 66.96 46.305 ;
     RECT  2.16 46.575 66.96 46.845 ;
     RECT  2.16 47.115 66.96 47.385 ;
     RECT  2.16 47.655 66.96 47.925 ;
     RECT  2.16 48.195 66.96 48.465 ;
     RECT  2.16 48.735 66.96 49.005 ;
     RECT  2.16 49.275 66.96 49.545 ;
     RECT  2.16 49.815 66.96 50.085 ;
     RECT  2.16 50.355 66.96 50.625 ;
     RECT  2.16 50.895 66.96 51.165 ;
     RECT  2.16 51.435 66.96 51.705 ;
     RECT  2.16 51.975 66.96 52.245 ;
     RECT  2.16 52.515 66.96 52.785 ;
     RECT  2.16 53.055 66.96 53.325 ;
     RECT  2.16 53.595 66.96 53.865 ;
     RECT  2.16 54.135 66.96 54.405 ;
     RECT  2.16 54.675 66.96 54.945 ;
     RECT  2.16 55.215 66.96 55.485 ;
     RECT  2.16 55.755 66.96 56.025 ;
     RECT  2.16 56.295 66.96 56.565 ;
     RECT  2.16 56.835 66.96 57.105 ;
     RECT  2.16 57.375 66.96 57.645 ;
     RECT  2.16 57.915 66.96 58.185 ;
     RECT  2.16 58.455 66.96 58.725 ;
     RECT  2.16 58.995 66.96 59.265 ;
     RECT  2.16 59.535 66.96 59.805 ;
     RECT  2.16 60.075 66.96 60.345 ;
     RECT  2.16 60.615 66.96 60.885 ;
     RECT  2.16 61.155 66.96 61.425 ;
     RECT  2.16 61.695 66.96 61.965 ;
     RECT  2.16 62.235 66.96 62.505 ;
     RECT  2.16 62.775 66.96 63.045 ;
     RECT  2.16 63.315 66.96 63.585 ;
     RECT  2.16 63.855 66.96 64.125 ;
     RECT  2.16 64.395 66.96 64.665 ;
     RECT  2.16 64.935 66.96 65.205 ;
     RECT  2.16 65.475 66.96 65.745 ;
     RECT  2.16 66.015 66.96 66.285 ;
     RECT  2.16 66.555 66.96 66.825 ;
     RECT  2.16 67.095 66.96 67.365 ;
     RECT  2.16 67.635 66.96 67.905 ;
     RECT  2.16 68.175 66.96 68.445 ;
     RECT  2.16 68.715 66.96 68.985 ;
     RECT  2.16 69.255 66.96 69.525 ;
     RECT  2.16 69.795 66.96 70.065 ;
     RECT  2.16 70.335 66.96 70.605 ;
     RECT  2.16 70.875 66.96 71.145 ;
     RECT  2.16 71.415 66.96 71.685 ;
     RECT  2.16 71.955 66.96 72.225 ;
     RECT  2.16 72.495 66.96 72.765 ;
     RECT  2.16 73.035 66.96 73.305 ;
     RECT  2.16 73.575 66.96 73.845 ;
     RECT  2.16 74.115 66.96 74.385 ;
     RECT  2.16 74.655 66.96 74.925 ;
     RECT  2.16 75.195 66.96 75.465 ;
     RECT  2.16 75.735 66.96 76.005 ;
     RECT  2.16 76.275 66.96 76.545 ;
     RECT  2.16 76.815 66.96 77.085 ;
     RECT  2.16 77.355 66.96 77.625 ;
    LAYER M1 ;
     RECT  2.16 2.151 66.96 77.769 ;
    LAYER M2 ;
     RECT  0.031 68.76 0.103 68.778 ;
     RECT  0.103 19.62 0.139 19.638 ;
     RECT  0.103 21.51 0.139 21.528 ;
     RECT  0.103 22.788 0.139 22.806 ;
     RECT  0.103 63.252 0.139 63.648 ;
     RECT  0.103 66.186 0.139 66.204 ;
     RECT  0.139 2.268 0.175 2.286 ;
     RECT  0.103 26.37 0.175 26.388 ;
     RECT  0.139 62.712 0.175 63.648 ;
     RECT  0.103 64.872 0.175 64.89 ;
     RECT  0.139 65.79 0.175 66.204 ;
     RECT  0.175 65.79 0.203 66.888 ;
     RECT  0.175 26.1 0.211 26.388 ;
     RECT  0.203 66.87 0.211 66.888 ;
     RECT  0.139 67.878 0.211 67.896 ;
     RECT  0.103 71.622 0.211 71.64 ;
     RECT  0.211 71.622 0.499 72.252 ;
     RECT  0.103 3.384 0.535 3.708 ;
     RECT  0.103 42.732 0.535 42.75 ;
     RECT  0.103 47.358 0.535 47.376 ;
     RECT  0.499 51.75 0.535 51.768 ;
     RECT  0.103 58.122 0.535 58.716 ;
     RECT  0.103 59.814 0.535 60.372 ;
     RECT  0.211 66.87 0.535 67.896 ;
     RECT  0.103 68.688 0.535 69.48 ;
     RECT  0.103 70.308 0.535 70.326 ;
     RECT  0.499 71.154 0.535 72.252 ;
     RECT  0.499 73.314 0.535 73.872 ;
     RECT  0.463 74.934 0.535 74.952 ;
     RECT  0.535 28.224 1.147 28.242 ;
     RECT  0.535 37.476 1.147 37.494 ;
     RECT  0.103 49.554 1.147 49.572 ;
     RECT  0.535 74.934 1.147 74.988 ;
     RECT  0.175 76.482 1.147 76.5 ;
     RECT  1.147 28.224 1.175 28.314 ;
     RECT  0.203 65.79 1.723 65.808 ;
     RECT  0.175 2.232 2.16 2.286 ;
     RECT  0.535 3.186 2.16 3.708 ;
     RECT  1.687 5.076 2.16 5.094 ;
     RECT  1.723 8.514 2.16 8.532 ;
     RECT  0.103 11.412 2.16 11.43 ;
     RECT  0.103 12.87 2.16 13.59 ;
     RECT  0.535 15.3 2.16 15.318 ;
     RECT  0.103 17.46 2.16 17.478 ;
     RECT  0.103 18.774 2.16 18.792 ;
     RECT  0.139 19.548 2.16 19.638 ;
     RECT  0.103 20.43 2.16 20.448 ;
     RECT  0.139 21.24 2.16 22.806 ;
     RECT  0.103 23.832 2.16 23.85 ;
     RECT  0.211 25.56 2.16 26.388 ;
     RECT  1.175 28.296 2.16 28.314 ;
     RECT  0.211 30.69 2.16 30.708 ;
     RECT  1.435 31.5 2.16 31.518 ;
     RECT  0.103 32.31 2.16 32.328 ;
     RECT  0.103 33.93 2.16 33.948 ;
     RECT  0.103 36.09 2.16 36.108 ;
     RECT  1.147 37.098 2.16 37.494 ;
     RECT  0.139 39.834 2.16 39.852 ;
     RECT  0.535 42.732 2.16 43.056 ;
     RECT  0.103 43.812 2.16 43.83 ;
     RECT  0.535 47.088 2.16 47.376 ;
     RECT  1.147 48.978 2.16 49.572 ;
     RECT  0.535 51.066 2.16 51.768 ;
     RECT  0.535 57.456 2.16 60.372 ;
     RECT  0.175 62.712 2.16 64.89 ;
     RECT  1.723 65.79 2.16 66.078 ;
     RECT  0.535 66.87 2.16 69.48 ;
     RECT  0.535 70.308 2.16 72.252 ;
     RECT  0.535 73.314 2.16 74.106 ;
     RECT  1.147 74.934 2.16 75.186 ;
     RECT  1.147 76.32 2.16 76.5 ;
     RECT  0.535 77.796 2.16 77.814 ;
     RECT  2.16 2.151 2.371 77.814 ;
     RECT  2.371 2.106 2.723 77.814 ;
     RECT  2.723 2.151 3.191 77.814 ;
     RECT  3.191 2.151 4.099 77.769 ;
     RECT  4.099 2.151 5.027 77.814 ;
     RECT  5.027 2.151 7.699 77.769 ;
     RECT  7.699 2.106 9.923 77.769 ;
     RECT  9.923 2.151 18.067 77.769 ;
     RECT  18.067 2.106 19.175 77.769 ;
     RECT  25.987 78.642 26.159 78.66 ;
     RECT  27.499 78.642 27.599 78.66 ;
     RECT  31.171 78.642 31.307 78.66 ;
     RECT  19.175 2.151 31.927 77.769 ;
     RECT  31.927 2.106 32.243 77.769 ;
     RECT  39.091 1.152 39.191 1.17 ;
     RECT  41.143 78.642 41.387 78.66 ;
     RECT  44.311 78.642 44.987 78.66 ;
     RECT  32.243 2.151 48.847 77.769 ;
     RECT  48.847 2.106 50.099 77.769 ;
     RECT  52.123 78.642 52.331 78.66 ;
     RECT  52.699 1.152 52.799 1.17 ;
     RECT  50.099 2.151 54.787 77.769 ;
     RECT  54.787 2.106 55.067 77.769 ;
     RECT  56.551 1.152 56.795 1.17 ;
     RECT  56.839 78.642 57.011 78.66 ;
     RECT  57.595 1.224 57.631 1.242 ;
     RECT  57.631 1.152 57.695 1.242 ;
     RECT  57.695 1.152 57.731 1.17 ;
     RECT  55.067 2.151 59.683 77.769 ;
     RECT  59.683 2.151 60.403 77.814 ;
     RECT  60.403 1.998 60.511 77.814 ;
     RECT  60.511 1.926 60.547 77.814 ;
     RECT  57.235 0.036 62.239 0.054 ;
     RECT  62.239 0.036 62.339 0.468 ;
     RECT  60.547 1.926 62.951 77.85 ;
     RECT  62.951 2.034 64.535 77.85 ;
     RECT  64.535 2.034 64.859 77.814 ;
     RECT  65.047 78.561 65.299 78.579 ;
     RECT  65.299 78.561 65.435 78.66 ;
     RECT  64.859 2.07 65.795 77.814 ;
     RECT  62.339 0.036 65.903 0.054 ;
     RECT  65.795 2.07 66.155 77.769 ;
     RECT  66.235 78.642 66.307 78.66 ;
     RECT  66.307 78.561 66.371 78.66 ;
     RECT  66.371 78.561 66.443 78.579 ;
     RECT  66.155 2.106 66.587 77.769 ;
     RECT  66.587 2.151 66.96 77.769 ;
     RECT  66.96 5.778 66.983 7.254 ;
     RECT  66.983 7.128 67.019 7.254 ;
     RECT  66.96 4.698 67.055 4.716 ;
     RECT  66.96 2.646 67.127 3.474 ;
     RECT  66.96 8.046 67.271 77.418 ;
     RECT  67.271 8.046 67.307 60.03 ;
     RECT  67.307 8.046 67.775 59.904 ;
     RECT  67.775 8.046 67.811 19.062 ;
     RECT  67.775 20.016 67.811 59.904 ;
     RECT  67.271 60.858 67.811 77.418 ;
     RECT  67.811 16.11 67.847 19.062 ;
     RECT  67.811 20.016 67.847 37.62 ;
     RECT  67.811 46.782 67.847 48.564 ;
     RECT  67.811 68.256 67.883 76.878 ;
     RECT  67.883 68.256 67.919 70.668 ;
     RECT  67.919 68.256 67.955 69.714 ;
     RECT  67.919 70.65 67.955 70.668 ;
     RECT  67.811 8.046 68.207 15.084 ;
     RECT  68.207 11.286 68.279 15.084 ;
     RECT  68.207 8.046 68.315 10.422 ;
     RECT  67.847 20.016 68.315 37.044 ;
     RECT  68.315 8.046 68.323 10.044 ;
     RECT  66.983 5.778 68.351 6.264 ;
     RECT  68.323 7.938 68.351 10.044 ;
     RECT  68.315 20.016 68.351 36.918 ;
     RECT  67.127 2.646 68.387 2.664 ;
     RECT  68.279 11.286 68.387 14.004 ;
     RECT  68.279 15.03 68.387 15.084 ;
     RECT  67.847 16.11 68.387 18.594 ;
     RECT  68.351 20.016 68.387 36.882 ;
     RECT  67.811 40.572 68.387 42.282 ;
     RECT  67.811 50.166 68.387 50.616 ;
     RECT  67.811 52.056 68.387 53.55 ;
     RECT  67.883 71.424 68.387 76.878 ;
     RECT  68.351 6.246 68.423 6.264 ;
     RECT  68.387 11.286 68.423 12.924 ;
     RECT  68.387 13.716 68.423 14.004 ;
     RECT  68.387 21.744 68.423 24.426 ;
     RECT  68.387 27.684 68.423 27.702 ;
     RECT  68.387 28.458 68.423 33.714 ;
     RECT  68.387 52.218 68.423 53.082 ;
     RECT  67.811 58.536 68.423 59.904 ;
     RECT  67.811 61.236 68.423 61.254 ;
     RECT  67.811 62.172 68.423 62.874 ;
     RECT  67.811 63.936 68.423 64.89 ;
     RECT  67.811 66.222 68.423 67.356 ;
     RECT  67.955 68.256 68.423 69.246 ;
     RECT  68.387 71.658 68.423 75.258 ;
     RECT  68.387 76.518 68.423 76.878 ;
     RECT  68.423 12.636 68.459 12.924 ;
     RECT  68.423 22.32 68.459 22.338 ;
     RECT  68.423 23.436 68.459 24.426 ;
     RECT  68.423 28.458 68.459 29.664 ;
     RECT  68.423 71.658 68.459 74.952 ;
     RECT  68.351 7.938 68.495 9.504 ;
     RECT  68.459 71.658 68.495 73.674 ;
     RECT  68.495 73.278 68.531 73.674 ;
     RECT  68.459 12.87 68.855 12.924 ;
     RECT  68.855 12.87 68.891 12.888 ;
     RECT  67.127 3.456 68.963 3.474 ;
     RECT  68.495 8.046 68.963 9.504 ;
     RECT  67.811 38.412 68.963 39.204 ;
     RECT  68.423 66.222 68.963 66.78 ;
     RECT  68.495 71.658 68.963 72.486 ;
     RECT  68.963 8.55 68.999 9.504 ;
     RECT  68.387 15.03 68.999 15.048 ;
     RECT  68.387 25.596 68.999 26.694 ;
     RECT  68.387 34.704 68.999 36.342 ;
     RECT  68.963 38.646 68.999 39.204 ;
     RECT  67.811 55.296 68.999 56.52 ;
     RECT  67.811 57.618 68.999 57.672 ;
     RECT  68.423 62.172 68.999 62.46 ;
     RECT  68.963 71.964 68.999 72.486 ;
     RECT  68.459 74.628 68.999 74.844 ;
     RECT  68.999 9.054 69.035 9.504 ;
     RECT  68.423 11.286 69.035 11.466 ;
     RECT  68.387 16.11 69.035 16.128 ;
     RECT  68.387 16.92 69.035 18.594 ;
     RECT  68.387 20.016 69.035 20.484 ;
     RECT  68.459 23.436 69.035 23.454 ;
     RECT  68.459 24.408 69.035 24.426 ;
     RECT  68.999 26.064 69.035 26.586 ;
     RECT  68.459 28.458 69.035 29.124 ;
     RECT  68.423 30.654 69.035 32.058 ;
     RECT  68.423 33.048 69.035 33.066 ;
     RECT  68.999 34.974 69.035 36.342 ;
     RECT  68.999 39.186 69.035 39.204 ;
     RECT  68.387 40.608 69.035 40.626 ;
     RECT  68.387 41.652 69.035 42.282 ;
     RECT  67.811 43.038 69.035 44.406 ;
     RECT  67.811 45.738 69.035 46.026 ;
     RECT  67.847 46.782 69.035 47.34 ;
     RECT  67.847 48.132 69.035 48.564 ;
     RECT  68.387 50.166 69.035 50.184 ;
     RECT  68.423 52.218 69.035 52.236 ;
     RECT  68.423 53.064 69.035 53.082 ;
     RECT  68.999 55.296 69.035 55.44 ;
     RECT  68.999 56.502 69.035 56.52 ;
     RECT  68.999 57.654 69.035 57.672 ;
     RECT  68.423 59.076 69.035 59.904 ;
     RECT  68.999 62.208 69.035 62.46 ;
     RECT  68.423 64.17 69.035 64.89 ;
     RECT  68.963 66.258 69.035 66.78 ;
     RECT  68.423 68.256 69.035 68.274 ;
     RECT  68.423 69.228 69.035 69.246 ;
     RECT  68.999 72.468 69.035 72.486 ;
     RECT  68.531 73.656 69.035 73.674 ;
     RECT  68.999 74.826 69.035 74.844 ;
     RECT  68.423 76.752 69.035 76.77 ;
     RECT  68.971 2.844 69.071 2.862 ;
     RECT  69.035 9.486 69.071 9.504 ;
     RECT  68.971 4.041 69.107 4.059 ;
     RECT  69.035 17.586 69.107 17.604 ;
     RECT  69.035 20.016 69.107 20.034 ;
    LAYER M3 ;
     RECT  20.628 0.091 20.646 0.139 ;
     RECT  22.032 0.091 22.05 0.139 ;
     RECT  57.996 0.091 58.014 0.139 ;
     RECT  3.384 0.091 3.402 0.187 ;
     RECT  57.996 0.139 58.734 0.269 ;
     RECT  57.24 0.031 57.258 0.331 ;
     RECT  57.996 0.269 58.482 0.331 ;
     RECT  65.88 0.031 65.898 0.379 ;
     RECT  62.388 0.091 62.406 0.427 ;
     RECT  62.244 0.427 62.406 0.475 ;
     RECT  65.88 0.379 66.258 0.509 ;
     RECT  3.24 0.187 3.402 0.523 ;
     RECT  51.696 0.091 51.714 0.523 ;
     RECT  52.704 0.091 53.838 0.523 ;
     RECT  6.588 0.091 6.966 0.571 ;
     RECT  9.108 0.139 9.126 0.571 ;
     RECT  10.368 0.091 10.386 0.571 ;
     RECT  15.084 0.091 15.102 0.571 ;
     RECT  17.82 0.091 17.838 0.571 ;
     RECT  24.984 0.523 25.002 0.571 ;
     RECT  28.44 0.091 28.458 0.571 ;
     RECT  48.996 0.091 49.266 0.571 ;
     RECT  64.98 0.235 64.998 0.571 ;
     RECT  65.88 0.509 65.898 0.571 ;
     RECT  14.076 0.571 14.094 0.619 ;
     RECT  24.768 0.571 25.002 0.619 ;
     RECT  8.748 0.571 9.126 1.099 ;
     RECT  14.076 0.619 14.238 1.099 ;
     RECT  30.924 0.571 31.338 1.099 ;
     RECT  37.152 0.571 37.17 1.099 ;
     RECT  38.592 0.571 39.762 1.099 ;
     RECT  56.016 0.571 56.034 1.099 ;
     RECT  57.24 0.331 58.482 1.099 ;
     RECT  16.956 0.571 17.838 1.147 ;
     RECT  26.892 0.091 26.91 1.147 ;
     RECT  27.828 0.571 28.458 1.147 ;
     RECT  29.988 0.091 30.006 1.147 ;
     RECT  47.664 0.571 49.266 1.147 ;
     RECT  56.016 1.099 58.482 1.147 ;
     RECT  59.508 0.523 59.526 1.147 ;
     RECT  61.956 0.475 62.406 1.147 ;
     RECT  63.36 0.523 63.378 1.147 ;
     RECT  56.016 1.147 59.526 1.175 ;
     RECT  2.88 0.523 3.402 1.195 ;
     RECT  60.696 1.099 60.714 1.195 ;
     RECT  61.452 1.147 62.406 1.195 ;
     RECT  64.98 0.571 65.898 1.483 ;
     RECT  2.88 1.195 3.438 1.531 ;
     RECT  2.88 1.531 3.474 1.675 ;
     RECT  33.12 0.523 33.138 1.675 ;
     RECT  47.268 1.147 49.266 1.675 ;
     RECT  2.736 1.675 3.474 1.723 ;
     RECT  4.464 1.051 4.482 1.723 ;
     RECT  5.472 1.099 5.49 1.723 ;
     RECT  6.264 0.571 6.966 1.723 ;
     RECT  8.64 1.099 9.126 1.723 ;
     RECT  10.368 0.571 10.926 1.723 ;
     RECT  12.492 0.571 12.51 1.723 ;
     RECT  13.356 1.099 14.238 1.723 ;
     RECT  15.084 0.571 15.606 1.723 ;
     RECT  16.452 1.147 17.838 1.723 ;
     RECT  23.22 0.091 23.238 1.723 ;
     RECT  24.768 0.619 25.038 1.723 ;
     RECT  26.892 1.147 28.458 1.723 ;
     RECT  29.952 1.147 30.006 1.723 ;
     RECT  30.924 1.099 32.022 1.723 ;
     RECT  33.12 1.675 33.858 1.723 ;
     RECT  36.072 1.147 36.306 1.723 ;
     RECT  37.152 1.099 39.762 1.723 ;
     RECT  42.192 0.523 42.498 1.723 ;
     RECT  43.452 0.091 43.47 1.723 ;
     RECT  44.208 1.147 44.226 1.723 ;
     RECT  45 0.091 45.018 1.723 ;
     RECT  46.764 1.675 49.266 1.723 ;
     RECT  55.116 0.571 55.134 1.723 ;
     RECT  45.936 1.723 45.954 1.771 ;
     RECT  46.692 1.723 49.59 1.771 ;
     RECT  50.4 0.091 50.598 1.771 ;
     RECT  51.696 0.523 53.838 1.771 ;
     RECT  67.752 1.195 67.77 1.771 ;
     RECT  68.94 1.339 68.958 1.771 ;
     RECT  2.736 1.723 6.966 1.819 ;
     RECT  60.696 1.195 62.406 1.921 ;
     RECT  63.36 1.147 63.774 1.921 ;
     RECT  60.516 1.921 63.774 1.993 ;
     RECT  12.492 1.723 17.838 2.011 ;
     RECT  64.98 1.483 66.114 2.029 ;
     RECT  66.96 1.627 66.978 2.059 ;
     RECT  67.752 1.771 68.958 2.059 ;
     RECT  64.836 2.029 66.114 2.065 ;
     RECT  8.64 1.723 9.486 2.101 ;
     RECT  10.368 1.723 11.754 2.101 ;
     RECT  45.936 1.771 49.59 2.101 ;
     RECT  50.4 1.771 53.838 2.101 ;
     RECT  60.408 1.993 63.774 2.101 ;
     RECT  64.836 2.065 66.15 2.101 ;
     RECT  66.96 2.059 68.958 2.101 ;
     RECT  1.152 2.059 1.17 2.107 ;
     RECT  7.704 2.101 7.722 2.143 ;
     RECT  12.492 2.011 18.27 2.143 ;
     RECT  19.152 2.101 19.17 2.143 ;
     RECT  22.788 1.723 29.07 2.143 ;
     RECT  29.952 1.723 34.146 2.143 ;
     RECT  35.208 1.723 39.762 2.143 ;
     RECT  40.824 0.571 40.842 2.143 ;
     RECT  41.616 1.723 45.018 2.143 ;
     RECT  45.936 2.101 53.838 2.143 ;
     RECT  56.016 1.175 56.034 2.143 ;
     RECT  56.772 1.175 59.526 2.143 ;
     RECT  2.34 1.819 6.966 2.191 ;
     RECT  7.704 2.143 7.905 2.191 ;
     RECT  8.64 2.101 11.754 2.191 ;
     RECT  12.492 2.143 19.17 2.191 ;
     RECT  20.628 0.139 22.05 2.191 ;
     RECT  22.788 2.143 40.842 2.191 ;
     RECT  41.616 2.143 53.838 2.191 ;
     RECT  54.684 1.723 55.134 2.191 ;
     RECT  56.016 2.143 59.526 2.191 ;
     RECT  60.408 2.101 63.918 2.191 ;
     RECT  22.788 2.191 64.026 2.227 ;
     RECT  64.836 2.101 68.958 2.227 ;
     RECT  2.34 2.191 19.494 2.251 ;
     RECT  20.376 2.191 22.05 2.251 ;
     RECT  22.788 2.227 68.958 2.251 ;
     RECT  0.18 2.227 0.198 2.263 ;
     RECT  1.152 2.107 1.278 2.285 ;
     RECT  2.34 2.251 68.958 2.371 ;
     RECT  0.144 2.263 0.198 2.429 ;
     RECT  2.268 2.371 68.958 2.635 ;
     RECT  2.268 2.635 68.994 2.839 ;
     RECT  0.144 2.429 0.162 3.181 ;
     RECT  0.144 3.181 0.558 3.379 ;
     RECT  2.268 2.839 69.066 4.036 ;
     RECT  0.108 3.379 0.558 4.109 ;
     RECT  0.54 4.109 0.558 4.397 ;
     RECT  2.268 4.036 69.102 4.555 ;
     RECT  1.692 4.555 69.102 5.099 ;
     RECT  2.268 5.099 69.102 5.453 ;
     RECT  2.304 5.453 69.102 6.955 ;
     RECT  2.268 6.955 69.102 7.231 ;
     RECT  2.232 7.231 69.102 7.435 ;
     RECT  1.728 7.435 69.102 8.537 ;
     RECT  0.108 8.875 0.126 9.005 ;
     RECT  2.268 8.537 69.102 9.965 ;
     RECT  0.144 10.267 0.162 10.843 ;
     RECT  0.144 10.843 0.342 10.987 ;
     RECT  0.108 10.987 0.342 11.021 ;
     RECT  0.108 11.021 0.162 11.645 ;
     RECT  0.108 11.645 0.126 12.077 ;
     RECT  2.304 9.965 69.102 12.955 ;
     RECT  0.108 12.865 0.126 14.429 ;
     RECT  2.268 12.955 69.102 14.525 ;
     RECT  0.144 15.259 0.162 15.295 ;
     RECT  2.268 14.525 69.03 15.629 ;
     RECT  0.144 15.295 0.558 15.725 ;
     RECT  0.144 15.725 0.162 15.869 ;
     RECT  1.152 16.987 1.17 17.117 ;
     RECT  2.304 15.629 69.03 17.581 ;
     RECT  0.108 17.455 0.126 17.837 ;
     RECT  2.304 17.581 69.102 18.701 ;
     RECT  2.304 18.701 67.842 19.277 ;
     RECT  2.304 19.277 67.806 19.336 ;
     RECT  0.108 18.769 0.126 19.543 ;
     RECT  2.268 19.336 67.806 19.841 ;
     RECT  69.084 18.701 69.102 19.963 ;
     RECT  69.012 19.963 69.102 20.039 ;
     RECT  2.268 19.841 66.726 20.075 ;
     RECT  69.012 20.039 69.03 20.107 ;
     RECT  67.788 19.841 67.806 20.219 ;
     RECT  0.108 19.543 0.162 20.237 ;
     RECT  68.976 20.107 69.03 20.489 ;
     RECT  68.364 20.827 68.382 21.115 ;
     RECT  2.304 20.075 66.726 21.119 ;
     RECT  0.108 20.237 0.126 21.235 ;
     RECT  67.788 21.115 68.382 21.403 ;
     RECT  2.304 21.119 66.69 21.547 ;
     RECT  67.752 21.403 68.382 21.569 ;
     RECT  67.788 21.569 68.382 21.739 ;
     RECT  2.268 21.547 66.69 21.767 ;
     RECT  0.108 21.235 0.162 21.869 ;
     RECT  67.788 21.739 68.418 22.109 ;
     RECT  68.364 22.109 68.418 22.315 ;
     RECT  2.304 21.767 66.69 22.507 ;
     RECT  0.144 21.869 0.162 22.585 ;
     RECT  2.304 22.507 67.338 22.685 ;
     RECT  0.144 22.585 0.198 22.783 ;
     RECT  68.364 22.315 68.454 22.939 ;
     RECT  2.304 22.685 67.302 23.117 ;
     RECT  2.34 23.117 67.302 23.189 ;
     RECT  68.364 22.939 69.03 23.459 ;
     RECT  0.108 22.783 0.198 23.837 ;
     RECT  2.34 23.189 67.266 24.089 ;
     RECT  67.248 24.089 67.266 24.091 ;
     RECT  68.364 23.459 68.454 24.091 ;
     RECT  0.108 23.837 0.126 24.173 ;
     RECT  2.34 24.089 66.474 24.283 ;
     RECT  67.248 24.091 68.454 24.379 ;
     RECT  67.248 24.379 69.03 24.431 ;
     RECT  67.248 24.431 68.958 24.467 ;
     RECT  67.248 24.467 67.266 24.701 ;
     RECT  68.364 24.467 68.958 25.007 ;
     RECT  2.304 24.283 66.474 25.195 ;
     RECT  0.144 25.243 0.162 25.555 ;
     RECT  2.16 25.195 66.474 25.555 ;
     RECT  67.788 25.675 67.806 25.816 ;
     RECT  68.976 25.387 69.03 25.816 ;
     RECT  67.788 25.816 69.03 25.817 ;
     RECT  2.16 25.555 66.834 25.853 ;
     RECT  67.824 25.817 69.03 25.853 ;
     RECT  0.144 25.555 0.234 26.093 ;
     RECT  67.824 25.853 67.842 26.093 ;
     RECT  0.144 26.093 0.198 26.365 ;
     RECT  68.94 25.853 69.03 26.591 ;
     RECT  2.304 25.853 66.834 26.599 ;
     RECT  68.94 26.591 68.994 26.699 ;
     RECT  0.108 26.365 0.198 26.861 ;
     RECT  68.94 26.699 68.958 27.067 ;
     RECT  0.18 26.861 0.198 27.149 ;
     RECT  68.364 27.067 68.958 27.245 ;
     RECT  2.304 26.599 67.302 27.481 ;
     RECT  68.364 27.245 68.418 27.481 ;
     RECT  2.304 27.481 68.418 27.533 ;
     RECT  68.364 27.533 68.418 27.779 ;
     RECT  68.4 27.779 68.418 28.219 ;
     RECT  0.54 28.219 1.17 28.319 ;
     RECT  68.4 28.219 69.03 28.507 ;
     RECT  2.304 27.533 67.302 28.525 ;
     RECT  68.364 28.507 69.03 28.525 ;
     RECT  2.304 28.525 69.03 28.651 ;
     RECT  2.268 28.651 69.03 28.829 ;
     RECT  2.268 28.829 66.726 29.057 ;
     RECT  0.54 28.319 0.558 29.117 ;
     RECT  67.824 28.829 69.03 29.129 ;
     RECT  67.824 29.129 68.454 29.405 ;
     RECT  67.896 29.405 68.454 29.645 ;
     RECT  68.328 29.645 68.454 30.209 ;
     RECT  68.4 30.209 68.454 30.331 ;
     RECT  68.4 30.331 69.03 30.509 ;
     RECT  2.304 29.057 66.726 30.605 ;
     RECT  0.216 30.685 0.234 30.763 ;
     RECT  2.34 30.605 66.726 30.839 ;
     RECT  0.144 30.763 0.234 30.893 ;
     RECT  0.216 30.893 0.234 30.941 ;
     RECT  2.34 30.839 66.654 31.387 ;
     RECT  1.44 29.563 1.458 31.523 ;
     RECT  67.788 31.051 67.806 31.627 ;
     RECT  68.976 30.509 69.03 31.627 ;
     RECT  2.304 31.387 66.654 31.765 ;
     RECT  2.304 31.765 66.726 32.395 ;
     RECT  2.268 32.395 66.726 32.491 ;
     RECT  67.788 31.627 69.03 32.491 ;
     RECT  2.268 32.491 69.03 32.567 ;
     RECT  0.108 32.305 0.126 33.053 ;
     RECT  2.304 32.567 69.03 33.071 ;
     RECT  2.304 33.071 68.418 33.385 ;
     RECT  2.268 33.385 68.418 33.485 ;
     RECT  2.304 33.485 68.418 33.989 ;
     RECT  68.364 33.989 68.418 34.259 ;
     RECT  2.304 33.989 67.266 34.457 ;
     RECT  68.976 34.603 68.994 34.747 ;
     RECT  0.108 33.925 0.126 34.877 ;
     RECT  2.304 34.457 67.23 35.179 ;
     RECT  0.144 35.131 0.162 35.261 ;
     RECT  0.216 35.563 0.342 35.741 ;
     RECT  68.976 34.747 69.03 35.755 ;
     RECT  0.216 35.741 0.234 35.885 ;
     RECT  2.304 35.179 67.266 36.187 ;
     RECT  68.364 35.755 69.03 36.619 ;
     RECT  0.108 36.085 0.126 36.653 ;
     RECT  2.268 36.187 67.266 36.689 ;
     RECT  68.328 36.619 69.03 36.907 ;
     RECT  1.152 34.987 1.17 37.121 ;
     RECT  2.268 36.689 66.726 37.427 ;
     RECT  2.304 37.427 66.726 37.435 ;
     RECT  68.292 36.907 69.03 37.597 ;
     RECT  0.54 37.471 0.558 37.709 ;
     RECT  2.304 37.435 66.762 38.011 ;
     RECT  67.824 37.597 69.03 38.011 ;
     RECT  2.304 38.011 66.798 38.281 ;
     RECT  67.788 38.011 69.03 38.281 ;
     RECT  2.304 38.281 69.03 38.621 ;
     RECT  0.144 38.587 0.162 38.717 ;
     RECT  68.976 38.621 69.03 39.011 ;
     RECT  69.012 39.011 69.03 39.209 ;
     RECT  2.304 38.621 67.806 39.317 ;
     RECT  67.716 39.317 67.806 40.027 ;
     RECT  0.144 39.829 0.162 40.075 ;
     RECT  67.716 40.027 68.382 40.171 ;
     RECT  0.108 40.075 0.162 40.205 ;
     RECT  2.304 39.317 66.798 40.297 ;
     RECT  67.716 40.171 69.03 40.297 ;
     RECT  0.144 40.205 0.162 40.301 ;
     RECT  2.304 40.297 69.03 40.631 ;
     RECT  0.324 40.699 0.342 40.877 ;
     RECT  2.304 40.631 68.382 41.135 ;
     RECT  2.304 41.135 67.806 41.309 ;
     RECT  67.284 41.309 67.806 41.453 ;
     RECT  0.144 41.611 0.162 41.741 ;
     RECT  2.304 41.309 66.402 42.187 ;
     RECT  67.788 41.453 67.806 42.283 ;
     RECT  2.304 42.187 66.726 42.601 ;
     RECT  67.752 42.283 67.806 42.601 ;
     RECT  2.304 42.601 67.806 42.667 ;
     RECT  2.268 42.667 67.806 42.749 ;
     RECT  0.108 42.727 0.126 42.845 ;
     RECT  2.268 42.749 66.726 43.096 ;
     RECT  2.232 43.096 66.726 43.367 ;
     RECT  2.304 43.367 66.726 43.537 ;
     RECT  67.752 42.749 67.806 43.537 ;
     RECT  0.54 43.033 0.558 43.613 ;
     RECT  2.304 43.537 67.806 43.613 ;
     RECT  2.304 43.613 66.726 44.155 ;
     RECT  2.268 44.155 66.726 44.299 ;
     RECT  69.012 41.563 69.03 44.411 ;
     RECT  2.232 44.299 66.726 44.587 ;
     RECT  2.232 44.587 66.762 44.645 ;
     RECT  2.304 44.645 66.762 44.683 ;
     RECT  67.752 43.613 67.806 44.683 ;
     RECT  0.108 43.807 0.126 44.957 ;
     RECT  0.144 45.355 0.162 45.485 ;
     RECT  2.304 44.683 67.806 46.013 ;
     RECT  2.304 46.013 66.618 46.067 ;
     RECT  2.304 46.067 66.546 46.535 ;
     RECT  67.752 46.013 67.806 46.843 ;
     RECT  2.304 46.535 66.402 47.077 ;
     RECT  0.54 47.083 0.558 47.353 ;
     RECT  2.268 47.077 66.402 47.461 ;
     RECT  2.268 47.461 66.474 47.615 ;
     RECT  2.304 47.615 66.474 47.893 ;
     RECT  67.248 46.843 67.806 47.893 ;
     RECT  0.108 47.353 0.558 47.981 ;
     RECT  2.304 47.893 67.806 47.995 ;
     RECT  2.304 47.995 67.842 48.035 ;
     RECT  0.108 47.981 0.126 48.125 ;
     RECT  2.304 48.035 67.806 48.379 ;
     RECT  69.012 45.403 69.03 48.569 ;
     RECT  2.268 48.379 67.806 48.767 ;
     RECT  2.304 48.767 67.806 48.845 ;
     RECT  2.304 48.845 66.834 48.929 ;
     RECT  1.152 48.973 1.17 49.037 ;
     RECT  2.304 48.929 66.762 49.883 ;
     RECT  69.012 50.107 69.03 50.189 ;
     RECT  0.108 49.549 0.126 50.237 ;
     RECT  67.752 48.845 67.806 50.395 ;
     RECT  67.752 50.395 68.382 50.621 ;
     RECT  67.752 50.621 67.806 50.629 ;
     RECT  2.304 49.883 66.222 50.701 ;
     RECT  67.284 50.629 67.806 50.701 ;
     RECT  2.304 50.701 67.806 50.717 ;
     RECT  2.304 50.717 66.834 50.819 ;
     RECT  2.304 50.819 66.726 51.005 ;
     RECT  2.304 51.005 66.546 51.665 ;
     RECT  0.54 51.061 0.558 51.745 ;
     RECT  67.716 50.717 67.806 51.835 ;
     RECT  0.504 51.745 0.558 51.869 ;
     RECT  67.716 51.835 68.382 51.979 ;
     RECT  0.504 51.869 0.522 52.205 ;
     RECT  67.716 51.979 69.03 52.219 ;
     RECT  67.248 52.219 69.03 52.313 ;
     RECT  67.788 52.313 69.03 52.541 ;
     RECT  2.304 51.665 66.114 52.591 ;
     RECT  2.304 52.591 66.15 52.861 ;
     RECT  2.304 52.861 66.33 52.891 ;
     RECT  69.012 52.541 69.03 53.087 ;
     RECT  2.268 52.891 66.33 53.131 ;
     RECT  2.268 53.131 66.546 53.285 ;
     RECT  67.788 52.541 67.806 53.515 ;
     RECT  67.788 53.515 68.382 53.555 ;
     RECT  67.788 53.555 67.806 53.659 ;
     RECT  2.304 53.285 66.546 53.671 ;
     RECT  67.752 53.659 67.806 53.803 ;
     RECT  67.716 53.803 67.806 53.947 ;
     RECT  2.304 53.671 66.654 54.139 ;
     RECT  2.304 54.139 66.726 54.337 ;
     RECT  67.68 53.947 67.806 54.337 ;
     RECT  0.144 54.427 0.162 54.557 ;
     RECT  2.304 54.337 67.806 54.571 ;
     RECT  2.232 54.571 67.806 54.635 ;
     RECT  2.304 54.635 67.806 54.707 ;
     RECT  67.248 54.707 67.806 55.211 ;
     RECT  69.012 54.955 69.03 55.243 ;
     RECT  68.976 55.243 69.03 55.445 ;
     RECT  67.752 55.211 67.806 55.453 ;
     RECT  2.304 54.707 66.474 55.561 ;
     RECT  68.976 55.445 68.994 55.787 ;
     RECT  67.752 55.453 67.842 55.853 ;
     RECT  2.304 55.561 66.834 55.957 ;
     RECT  67.752 55.853 67.806 55.957 ;
     RECT  0.144 55.339 0.162 56.045 ;
     RECT  69.012 56.203 69.03 56.525 ;
     RECT  2.304 55.957 67.806 56.867 ;
     RECT  2.304 56.867 66.762 57.173 ;
     RECT  0.144 57.259 0.162 57.389 ;
     RECT  69.012 57.355 69.03 57.499 ;
     RECT  68.976 57.499 69.03 57.641 ;
     RECT  69.012 57.641 69.03 57.677 ;
     RECT  67.788 56.867 67.806 57.787 ;
     RECT  67.752 57.787 67.806 57.931 ;
     RECT  2.304 57.173 66.546 58.027 ;
     RECT  0.54 57.451 0.558 58.117 ;
     RECT  2.268 58.027 66.546 58.117 ;
     RECT  2.232 58.117 66.546 58.261 ;
     RECT  2.232 58.261 66.69 58.349 ;
     RECT  2.268 58.349 66.69 58.415 ;
     RECT  2.304 58.415 66.69 58.423 ;
     RECT  67.716 57.931 67.806 58.507 ;
     RECT  67.716 58.507 68.418 58.559 ;
     RECT  2.304 58.423 66.906 58.795 ;
     RECT  67.716 58.559 67.806 58.795 ;
     RECT  0.108 58.117 0.558 58.829 ;
     RECT  2.304 58.795 67.806 58.955 ;
     RECT  2.304 58.955 67.77 59.225 ;
     RECT  2.304 59.225 67.302 59.333 ;
     RECT  2.304 59.333 66.474 59.371 ;
     RECT  0.54 58.829 0.558 59.549 ;
     RECT  2.268 59.371 66.474 59.567 ;
     RECT  66.456 59.567 66.474 59.729 ;
     RECT  0.144 59.707 0.162 59.809 ;
     RECT  0.108 59.809 0.162 59.837 ;
     RECT  69.012 59.071 69.03 59.909 ;
     RECT  2.268 59.567 65.718 60.035 ;
     RECT  67.248 59.333 67.302 60.151 ;
     RECT  66.528 60.151 67.302 60.269 ;
     RECT  66.672 60.269 67.302 60.331 ;
     RECT  66.672 60.331 67.806 60.341 ;
     RECT  2.268 60.035 65.574 60.461 ;
     RECT  67.716 60.341 67.806 61.051 ;
     RECT  0.108 59.837 0.126 61.085 ;
     RECT  66.672 60.341 66.834 61.087 ;
     RECT  2.304 60.461 65.574 61.231 ;
     RECT  66.384 61.087 66.834 61.231 ;
     RECT  67.716 61.051 68.418 61.259 ;
     RECT  2.304 61.231 66.834 61.385 ;
     RECT  0.144 61.387 0.162 61.517 ;
     RECT  2.304 61.385 66.546 61.627 ;
     RECT  67.716 61.259 67.806 61.735 ;
     RECT  2.268 61.627 66.546 61.799 ;
     RECT  67.284 61.735 67.806 61.805 ;
     RECT  67.752 61.805 67.806 61.925 ;
     RECT  69.012 61.915 69.03 62.059 ;
     RECT  2.268 61.799 65.538 62.107 ;
     RECT  2.232 62.107 65.538 62.465 ;
     RECT  68.976 62.059 69.03 62.465 ;
     RECT  67.788 61.925 67.806 62.491 ;
     RECT  2.268 62.465 65.538 62.581 ;
     RECT  66.348 61.799 66.546 62.581 ;
     RECT  0.108 62.683 0.126 62.707 ;
     RECT  2.268 62.581 66.546 62.815 ;
     RECT  67.788 62.491 68.418 62.879 ;
     RECT  2.268 62.815 66.834 62.923 ;
     RECT  67.788 62.879 67.806 62.923 ;
     RECT  2.268 62.923 67.806 63.041 ;
     RECT  0.108 62.707 0.162 63.485 ;
     RECT  2.268 63.041 66.834 63.653 ;
     RECT  67.752 63.041 67.806 63.815 ;
     RECT  2.268 63.653 66.798 63.917 ;
     RECT  67.788 63.815 67.806 63.931 ;
     RECT  67.788 63.931 68.418 64.165 ;
     RECT  0.108 63.485 0.126 64.219 ;
     RECT  0.108 64.219 0.162 64.348 ;
     RECT  2.268 63.917 66.222 64.651 ;
     RECT  67.788 64.165 69.03 64.769 ;
     RECT  0.108 64.348 0.198 64.829 ;
     RECT  1.728 64.651 66.222 64.867 ;
     RECT  69.012 64.769 69.03 64.895 ;
     RECT  1.728 64.867 66.33 64.939 ;
     RECT  67.788 64.769 67.806 65.164 ;
     RECT  1.728 64.939 66.402 65.551 ;
     RECT  67.752 65.164 67.806 65.551 ;
     RECT  67.284 65.551 67.806 65.645 ;
     RECT  0.108 64.829 0.126 65.785 ;
     RECT  0.108 65.785 0.162 65.995 ;
     RECT  69.012 65.755 69.03 66.043 ;
     RECT  1.728 65.551 66.546 66.083 ;
     RECT  0.108 65.995 0.198 66.091 ;
     RECT  68.976 66.043 69.03 66.187 ;
     RECT  68.94 66.187 69.03 66.245 ;
     RECT  2.232 66.083 66.546 66.289 ;
     RECT  68.976 66.245 69.03 66.389 ;
     RECT  2.232 66.289 66.978 66.475 ;
     RECT  67.788 65.645 67.806 66.475 ;
     RECT  2.232 66.475 67.806 66.515 ;
     RECT  69.012 66.389 69.03 66.785 ;
     RECT  2.268 66.515 67.806 67.127 ;
     RECT  2.304 67.127 67.806 67.333 ;
     RECT  0.036 66.091 0.198 67.369 ;
     RECT  2.304 67.333 68.418 67.469 ;
     RECT  0.036 67.369 0.234 67.675 ;
     RECT  2.304 67.469 67.806 67.945 ;
     RECT  2.268 67.945 67.806 68.141 ;
     RECT  69.012 68.251 69.03 68.333 ;
     RECT  2.304 68.141 67.806 68.521 ;
     RECT  1.404 66.187 1.422 68.747 ;
     RECT  2.304 68.521 68.418 68.765 ;
     RECT  0.036 67.675 0.558 68.783 ;
     RECT  67.752 68.765 68.418 68.783 ;
     RECT  2.304 68.765 66.978 68.909 ;
     RECT  67.788 68.783 68.418 69.163 ;
     RECT  67.788 69.163 69.03 69.251 ;
     RECT  0.108 68.783 0.558 69.389 ;
     RECT  2.304 68.909 66.726 69.643 ;
     RECT  2.268 69.643 66.726 69.799 ;
     RECT  67.788 69.251 68.418 69.799 ;
     RECT  2.268 69.799 68.418 69.827 ;
     RECT  2.304 69.827 68.418 69.917 ;
     RECT  0.108 69.389 0.522 70.609 ;
     RECT  2.304 69.917 66.69 70.645 ;
     RECT  2.304 70.645 66.798 70.681 ;
     RECT  67.788 69.917 68.418 70.891 ;
     RECT  2.304 70.681 66.942 71.617 ;
     RECT  67.788 70.891 69.03 71.617 ;
     RECT  0.108 70.609 0.558 71.645 ;
     RECT  2.304 71.617 69.03 71.741 ;
     RECT  67.86 71.741 69.03 71.885 ;
     RECT  67.896 71.885 69.03 72.029 ;
     RECT  0.108 71.645 0.522 72.077 ;
     RECT  0.144 72.077 0.522 72.221 ;
     RECT  68.364 72.029 69.03 72.769 ;
     RECT  0.144 72.221 0.234 72.797 ;
     RECT  0.216 72.797 0.234 73.099 ;
     RECT  2.304 71.741 66.942 73.147 ;
     RECT  67.824 72.769 69.03 73.147 ;
     RECT  0.216 73.099 0.342 73.309 ;
     RECT  1.152 72.475 1.17 73.309 ;
     RECT  0.216 73.309 1.17 73.421 ;
     RECT  2.304 73.147 69.03 73.679 ;
     RECT  2.304 73.679 68.994 73.819 ;
     RECT  2.268 73.819 68.994 74.587 ;
     RECT  2.196 74.587 68.994 74.624 ;
     RECT  2.232 74.624 68.994 74.821 ;
     RECT  2.232 74.821 69.03 74.909 ;
     RECT  0.504 73.421 1.17 74.929 ;
     RECT  0.468 74.929 1.17 75.191 ;
     RECT  2.232 74.909 68.454 75.263 ;
     RECT  2.268 75.263 68.454 75.293 ;
     RECT  0.468 75.191 0.558 75.389 ;
     RECT  0.468 75.389 0.486 75.533 ;
     RECT  0.108 75.643 0.126 75.773 ;
     RECT  2.268 75.293 66.798 75.821 ;
     RECT  2.304 75.821 66.798 76.123 ;
     RECT  67.572 75.293 68.454 76.123 ;
     RECT  2.304 76.123 68.454 76.411 ;
     RECT  0.144 76.459 0.162 76.477 ;
     RECT  2.304 76.411 69.03 76.775 ;
     RECT  2.304 76.775 68.418 77.081 ;
     RECT  2.304 77.081 66.798 77.179 ;
     RECT  1.98 77.179 66.798 77.309 ;
     RECT  2.304 77.309 66.798 77.549 ;
     RECT  67.572 77.081 68.418 77.597 ;
     RECT  15.912 77.549 23.022 77.621 ;
     RECT  28.44 77.549 36.126 77.621 ;
     RECT  55.98 77.549 63.594 77.621 ;
     RECT  64.512 77.549 66.798 77.621 ;
     RECT  11.088 77.549 15.174 77.657 ;
     RECT  28.44 77.621 34.074 77.693 ;
     RECT  36.9 77.549 41.49 77.693 ;
     RECT  2.415 77.549 5.67 77.729 ;
     RECT  6.768 77.549 10.35 77.729 ;
     RECT  11.16 77.657 15.174 77.729 ;
     RECT  15.912 77.621 22.014 77.729 ;
     RECT  28.44 77.693 34.038 77.729 ;
     RECT  36.9 77.693 38.862 77.729 ;
     RECT  42.516 77.549 54.918 77.729 ;
     RECT  55.98 77.621 62.154 77.729 ;
     RECT  63.252 77.621 63.342 77.729 ;
     RECT  2.415 77.729 5.526 77.777 ;
     RECT  13.215 77.729 14.274 77.777 ;
     RECT  23.832 77.549 24.105 77.777 ;
     RECT  34.815 77.621 36.126 77.777 ;
     RECT  39.636 77.693 41.49 77.777 ;
     RECT  55.98 77.729 61.905 77.777 ;
     RECT  0.144 76.477 0.198 77.789 ;
     RECT  0.18 77.789 0.198 77.791 ;
     RECT  1.152 76.315 1.17 77.791 ;
     RECT  2.952 77.777 5.526 77.819 ;
     RECT  64.512 77.621 64.53 77.855 ;
     RECT  13.644 77.777 14.274 77.885 ;
     RECT  50.832 77.729 54.702 77.885 ;
     RECT  55.98 77.777 61.614 77.885 ;
     RECT  15.912 77.729 21.006 77.933 ;
     RECT  0.18 77.791 1.17 77.981 ;
     RECT  36.9 77.729 38.754 77.981 ;
     RECT  6.768 77.729 8.082 78.077 ;
     RECT  15.912 77.933 18.09 78.077 ;
     RECT  19.152 77.933 21.006 78.077 ;
     RECT  32.04 77.729 32.058 78.077 ;
     RECT  35.172 77.777 36.126 78.077 ;
     RECT  36.936 77.981 38.754 78.077 ;
     RECT  39.636 77.777 39.942 78.077 ;
     RECT  40.716 77.777 41.49 78.077 ;
     RECT  42.696 77.729 43.326 78.077 ;
     RECT  44.316 77.729 48.798 78.077 ;
     RECT  50.976 77.885 54.702 78.077 ;
     RECT  55.98 77.885 60.894 78.077 ;
     RECT  23.832 77.777 23.958 78.125 ;
     RECT  24.912 77.549 27.594 78.125 ;
     RECT  28.44 77.729 29.826 78.125 ;
     RECT  34.02 77.729 34.038 78.125 ;
     RECT  56.16 78.077 60.714 78.125 ;
     RECT  0.54 77.981 1.17 78.269 ;
     RECT  65.304 77.621 66.798 78.556 ;
     RECT  2.952 77.819 4.446 78.653 ;
     RECT  7.2 78.077 8.082 78.653 ;
     RECT  11.16 77.729 12.33 78.653 ;
     RECT  17.388 78.077 18.09 78.653 ;
     RECT  28.764 78.125 28.782 78.653 ;
     RECT  53.82 78.077 54.162 78.653 ;
     RECT  56.16 78.125 59.49 78.653 ;
     RECT  65.052 78.556 66.798 78.653 ;
     RECT  27.504 78.125 27.594 78.665 ;
     RECT  30.744 77.729 31.302 78.665 ;
     RECT  44.316 78.077 48.114 78.665 ;
     RECT  3.132 78.653 4.446 78.701 ;
     RECT  13.968 77.885 14.274 78.701 ;
     RECT  35.172 78.077 35.766 78.701 ;
     RECT  60.696 78.125 60.714 78.701 ;
     RECT  66.24 78.653 66.798 78.701 ;
     RECT  1.152 78.269 1.17 78.845 ;
     RECT  3.132 78.701 4.41 79.229 ;
     RECT  11.16 78.653 11.178 79.229 ;
     RECT  15.156 77.729 15.174 79.229 ;
     RECT  15.912 78.077 16.362 79.229 ;
     RECT  22.86 77.621 23.022 79.229 ;
     RECT  23.832 78.125 23.85 79.229 ;
     RECT  24.912 78.125 26.406 79.229 ;
     RECT  27.504 78.665 27.522 79.229 ;
     RECT  29.808 78.125 29.826 79.229 ;
     RECT  32.868 77.729 32.886 79.229 ;
     RECT  37.548 78.077 38.754 79.229 ;
     RECT  39.636 78.077 39.654 79.229 ;
     RECT  44.424 78.665 48.114 79.229 ;
     RECT  52.128 78.077 52.866 79.229 ;
     RECT  53.82 78.653 53.838 79.229 ;
     RECT  56.16 78.653 59.418 79.229 ;
     RECT  66.312 78.701 66.798 79.229 ;
     RECT  25.308 79.229 26.406 79.277 ;
     RECT  30.744 78.665 31.194 79.277 ;
     RECT  47.052 79.229 48.114 79.277 ;
     RECT  52.128 79.229 52.542 79.277 ;
     RECT  57.852 79.229 59.418 79.277 ;
     RECT  66.312 79.229 66.33 79.277 ;
     RECT  7.38 78.653 8.082 79.709 ;
     RECT  7.38 79.709 7.398 79.757 ;
     RECT  9.864 77.729 10.35 79.757 ;
     RECT  21.78 77.729 22.014 79.757 ;
     RECT  41.148 78.077 41.49 79.757 ;
     RECT  44.424 79.229 45.378 79.757 ;
     RECT  3.852 79.229 4.41 79.805 ;
     RECT  5.508 77.819 5.526 79.805 ;
     RECT  10.332 79.757 10.35 79.805 ;
     RECT  12.312 78.653 12.33 79.805 ;
     RECT  16.344 79.229 16.362 79.805 ;
     RECT  17.388 78.653 17.406 79.805 ;
     RECT  19.152 78.077 19.17 79.805 ;
     RECT  21.78 79.757 21.798 79.805 ;
     RECT  23.004 79.229 23.022 79.805 ;
     RECT  25.416 79.277 26.406 79.805 ;
     RECT  30.744 79.277 30.762 79.805 ;
     RECT  35.316 78.701 35.766 79.805 ;
     RECT  38.736 79.229 38.754 79.805 ;
     RECT  41.148 79.757 41.166 79.805 ;
     RECT  42.696 78.077 43.254 79.805 ;
     RECT  44.424 79.757 44.442 79.805 ;
     RECT  45.36 79.757 45.378 79.805 ;
     RECT  47.052 79.277 47.07 79.805 ;
     RECT  47.808 79.277 48.114 79.805 ;
     RECT  50.976 78.077 50.994 79.805 ;
     RECT  52.128 79.277 52.146 79.805 ;
     RECT  57.852 79.277 57.87 79.805 ;
     RECT  59.004 79.277 59.022 79.805 ;
     RECT  65.052 78.653 65.43 79.805 ;
     RECT  67.572 77.597 68.058 79.805 ;
    LAYER M4 ;
     RECT  0.025 66.096 0.06 66.12 ;
     RECT  0.06 1.056 1.181 78.84 ;
     RECT  1.181 1.056 2.485 78.696 ;
     RECT  2.485 0.144 2.704 78.696 ;
     RECT  2.704 0.144 2.725 12.888 ;
     RECT  2.704 61.104 2.725 78.696 ;
     RECT  2.704 44.448 2.765 44.472 ;
     RECT  2.704 18.192 2.819 38.76 ;
     RECT  2.819 23.28 2.867 38.76 ;
     RECT  2.867 38.064 2.873 38.76 ;
     RECT  2.704 45.456 2.873 59.832 ;
     RECT  2.873 45.552 3.017 59.832 ;
     RECT  3.017 45.552 3.089 59.448 ;
     RECT  2.725 61.104 3.157 79.224 ;
     RECT  3.157 61.104 3.161 79.8 ;
     RECT  2.725 0.096 3.413 12.888 ;
     RECT  2.819 18.192 3.443 22.2 ;
     RECT  2.867 24.768 3.449 37.08 ;
     RECT  3.413 0.144 3.733 12.888 ;
     RECT  2.704 14.256 3.733 16.968 ;
     RECT  3.733 0.144 3.769 16.968 ;
     RECT  3.443 18.192 3.769 18.216 ;
     RECT  2.704 40.08 3.769 43.176 ;
     RECT  3.443 19.2 3.781 22.2 ;
     RECT  2.867 23.28 3.781 23.64 ;
     RECT  3.781 19.2 3.877 23.64 ;
     RECT  3.449 24.768 3.877 31.848 ;
     RECT  2.873 38.064 3.884 38.712 ;
     RECT  3.769 40.08 3.884 43.944 ;
     RECT  3.161 61.104 3.989 78.696 ;
     RECT  3.884 38.064 4.021 43.944 ;
     RECT  4.021 38.064 4.057 44.472 ;
     RECT  3.089 45.552 4.057 46.872 ;
     RECT  4.057 38.064 4.201 46.872 ;
     RECT  3.089 47.856 4.201 59.448 ;
     RECT  3.989 61.104 4.357 77.688 ;
     RECT  3.449 32.928 4.381 37.08 ;
     RECT  4.201 38.064 4.381 59.448 ;
     RECT  3.161 79.728 4.421 79.8 ;
     RECT  3.769 0.144 4.453 18.216 ;
     RECT  3.877 19.2 4.453 31.848 ;
     RECT  3.989 78.672 4.457 78.696 ;
     RECT  4.453 0.144 4.493 31.848 ;
     RECT  4.381 32.928 4.633 59.448 ;
     RECT  4.633 32.928 4.705 59.592 ;
     RECT  4.493 1.728 4.741 31.848 ;
     RECT  4.705 32.928 4.741 60.024 ;
     RECT  4.493 0.144 4.787 0.6 ;
     RECT  4.421 79.728 4.883 79.752 ;
     RECT  4.357 61.008 5.357 77.688 ;
     RECT  4.741 1.728 5.389 60.024 ;
     RECT  5.357 61.008 5.389 77.544 ;
     RECT  4.787 0.576 5.461 0.6 ;
     RECT  5.389 1.728 5.461 77.544 ;
     RECT  5.453 79.776 5.537 79.8 ;
     RECT  5.461 0.576 5.555 77.544 ;
     RECT  5.555 1.728 5.699 77.544 ;
     RECT  5.555 0.576 5.749 0.6 ;
     RECT  5.699 1.728 5.825 76.968 ;
     RECT  5.825 1.728 5.933 54.984 ;
     RECT  5.933 1.728 6.041 52.872 ;
     RECT  5.749 0.096 6.293 0.6 ;
     RECT  5.825 55.968 6.301 76.968 ;
     RECT  6.041 2.208 6.473 52.872 ;
     RECT  6.421 78.048 6.853 78.072 ;
     RECT  5.933 54.192 6.863 54.984 ;
     RECT  6.301 55.968 6.863 76.728 ;
     RECT  6.293 0.096 6.977 0.12 ;
     RECT  6.853 78.048 7.093 78.648 ;
     RECT  7.093 77.856 7.229 78.648 ;
     RECT  7.229 77.856 7.265 77.88 ;
     RECT  6.863 54.192 7.333 76.728 ;
     RECT  7.325 79.728 7.477 79.752 ;
     RECT  6.473 50.064 7.693 52.872 ;
     RECT  7.333 54.192 7.693 77.772 ;
     RECT  6.473 2.208 7.808 49.08 ;
     RECT  7.693 50.064 7.808 77.772 ;
     RECT  7.808 2.148 7.813 77.772 ;
     RECT  7.813 1.728 7.912 77.772 ;
     RECT  7.912 1.728 8.104 77.592 ;
     RECT  8.053 0.576 8.293 0.6 ;
     RECT  8.104 1.728 8.489 52.056 ;
     RECT  8.293 0.096 8.629 0.6 ;
     RECT  8.489 1.728 8.629 49.416 ;
     RECT  8.104 53.088 8.641 77.592 ;
     RECT  8.629 0.096 8.675 49.416 ;
     RECT  7.477 79.68 8.771 79.8 ;
     RECT  8.675 0.144 8.813 49.416 ;
     RECT  8.813 0.144 8.819 49.224 ;
     RECT  8.489 50.592 9.029 52.056 ;
     RECT  8.641 53.088 9.029 77.544 ;
     RECT  9.029 54.432 9.073 77.544 ;
     RECT  8.819 1.728 9.107 49.224 ;
     RECT  9.029 53.088 9.133 53.4 ;
     RECT  8.819 0.144 9.137 0.168 ;
     RECT  9.107 4.176 9.173 32.424 ;
     RECT  9.173 4.176 9.209 18.072 ;
     RECT  9.107 33.456 9.281 49.224 ;
     RECT  9.107 1.728 9.395 3.048 ;
     RECT  9.395 1.728 9.497 1.752 ;
     RECT  9.073 54.432 9.677 77.112 ;
     RECT  9.395 2.832 9.749 3.048 ;
     RECT  9.677 76.272 9.785 77.112 ;
     RECT  9.677 54.432 9.893 75.288 ;
     RECT  9.173 19.344 9.923 32.424 ;
     RECT  9.923 19.392 9.965 32.424 ;
     RECT  9.893 54.432 9.971 56.04 ;
     RECT  9.281 47.712 10.069 49.224 ;
     RECT  9.133 52.656 10.073 53.4 ;
     RECT  10.069 47.712 10.105 49.416 ;
     RECT  9.029 50.592 10.105 51.24 ;
     RECT  9.965 19.488 10.145 32.424 ;
     RECT  9.785 76.368 10.259 77.112 ;
     RECT  10.145 20.064 10.285 32.424 ;
     RECT  9.281 33.552 10.285 46.728 ;
     RECT  8.771 79.728 10.361 79.8 ;
     RECT  10.285 20.064 10.367 46.728 ;
     RECT  10.105 47.712 10.367 51.24 ;
     RECT  10.357 0.096 10.451 0.12 ;
     RECT  9.209 4.176 10.465 17.64 ;
     RECT  10.453 2.64 10.541 2.664 ;
     RECT  10.367 20.064 10.645 51.24 ;
     RECT  10.465 4.176 10.681 17.88 ;
     RECT  10.073 53.184 10.717 53.4 ;
     RECT  9.971 54.432 10.717 55.848 ;
     RECT  10.681 3.936 10.741 17.88 ;
     RECT  10.717 53.184 10.757 55.848 ;
     RECT  10.259 76.8 10.757 77.112 ;
     RECT  9.893 57.6 10.789 75.288 ;
     RECT  10.645 20.064 10.861 51.384 ;
     RECT  10.757 53.328 10.901 55.848 ;
     RECT  10.837 0.576 10.937 0.6 ;
     RECT  10.757 76.896 11.005 77.112 ;
     RECT  11.005 76.896 11.045 77.544 ;
     RECT  10.789 79.2 11.189 79.224 ;
     RECT  10.861 20.064 11.225 51.72 ;
     RECT  10.741 3.888 11.257 17.88 ;
     RECT  11.045 77.52 11.267 77.544 ;
     RECT  10.789 57.6 11.337 75.48 ;
     RECT  10.597 1.728 11.405 1.8 ;
     RECT  11.225 20.064 11.477 32.904 ;
     RECT  11.337 56.784 11.621 75.48 ;
     RECT  11.461 78.624 11.621 78.648 ;
     RECT  11.653 78.096 11.747 78.12 ;
     RECT  10.901 53.328 11.869 55.656 ;
     RECT  11.621 56.784 11.869 75.24 ;
     RECT  11.477 20.064 12.265 32.424 ;
     RECT  11.225 33.936 12.277 51.72 ;
     RECT  12.181 79.776 12.341 79.8 ;
     RECT  12.265 19.392 12.445 32.424 ;
     RECT  12.277 33.936 12.445 52.008 ;
     RECT  11.257 3.888 12.517 17.928 ;
     RECT  12.445 19.392 12.517 52.008 ;
     RECT  11.989 0.576 12.521 0.6 ;
     RECT  12.229 2.88 12.553 2.904 ;
     RECT  12.517 3.888 12.553 52.008 ;
     RECT  12.332 77.52 12.613 77.544 ;
     RECT  12.553 2.88 12.733 52.008 ;
     RECT  11.869 53.328 12.733 75.24 ;
     RECT  12.733 2.88 13.021 75.24 ;
     RECT  11.405 1.728 13.025 1.752 ;
     RECT  13.021 2.88 13.208 75.816 ;
     RECT  12.613 76.896 13.208 77.544 ;
     RECT  13.093 0.096 13.235 0.12 ;
     RECT  13.208 2.148 13.312 77.772 ;
     RECT  13.34 1.104 13.427 1.128 ;
     RECT  13.312 2.418 13.504 77.772 ;
     RECT  13.504 71.616 13.619 76.824 ;
     RECT  13.333 79.728 13.619 79.752 ;
     RECT  13.619 76.8 13.637 76.824 ;
     RECT  13.525 77.856 13.673 77.88 ;
     RECT  13.504 2.88 13.817 65.544 ;
     RECT  13.504 66.576 13.889 70.104 ;
     RECT  13.889 66.576 14.141 70.008 ;
     RECT  13.817 57.504 14.177 65.544 ;
     RECT  13.861 0.576 14.249 0.648 ;
     RECT  13.957 78.672 14.291 78.696 ;
     RECT  14.177 58.8 14.321 65.544 ;
     RECT  13.817 2.88 14.501 56.52 ;
     RECT  13.619 71.616 14.531 75.816 ;
     RECT  14.485 76.896 14.641 76.968 ;
     RECT  14.641 76.896 14.645 77.544 ;
     RECT  14.501 2.928 14.753 56.52 ;
     RECT  14.753 2.928 14.789 16.104 ;
     RECT  14.753 17.472 14.821 56.52 ;
     RECT  14.177 57.504 14.821 57.816 ;
     RECT  14.821 17.472 14.867 57.816 ;
     RECT  14.141 66.672 15.001 70.008 ;
     RECT  14.789 3.264 15.041 16.104 ;
     RECT  15.013 0.096 15.113 0.12 ;
     RECT  15.041 3.36 15.149 16.104 ;
     RECT  14.321 58.8 15.361 65.448 ;
     RECT  15.001 66.672 15.361 70.392 ;
     RECT  14.645 76.944 15.484 77.544 ;
     RECT  15.493 0.576 15.617 0.6 ;
     RECT  15.361 58.8 15.685 70.392 ;
     RECT  14.531 71.616 15.685 75.432 ;
     RECT  14.867 17.472 15.865 46.104 ;
     RECT  14.867 47.136 15.865 57.816 ;
     RECT  15.685 58.8 15.875 75.432 ;
     RECT  14.741 1.728 15.973 1.752 ;
     RECT  15.865 17.472 16.009 57.816 ;
     RECT  15.875 58.8 16.009 74.328 ;
     RECT  15.149 3.36 16.045 14.232 ;
     RECT  15.149 15.408 16.049 16.104 ;
     RECT  16.045 2.928 16.085 14.232 ;
     RECT  16.085 13.68 16.117 14.232 ;
     RECT  16.049 15.408 16.117 15.432 ;
     RECT  16.009 17.472 16.121 74.328 ;
     RECT  15.875 75.408 16.165 75.432 ;
     RECT  16.165 75.408 16.265 75.864 ;
     RECT  14.917 79.2 16.289 79.224 ;
     RECT  16.121 17.472 16.333 57.768 ;
     RECT  16.289 79.2 16.337 79.8 ;
     RECT  15.973 1.152 16.481 1.752 ;
     RECT  16.265 75.408 16.481 75.432 ;
     RECT  16.333 17.088 16.547 57.768 ;
     RECT  16.481 1.68 16.691 1.752 ;
     RECT  16.121 58.8 16.691 74.328 ;
     RECT  15.484 77.52 16.789 77.544 ;
     RECT  16.789 77.52 16.877 78.072 ;
     RECT  16.691 71.472 16.945 74.328 ;
     RECT  16.117 13.68 17.381 15.432 ;
     RECT  16.337 79.776 17.417 79.8 ;
     RECT  16.885 0.576 17.453 0.6 ;
     RECT  16.547 18.384 17.453 57.768 ;
     RECT  16.945 71.472 17.489 74.904 ;
     RECT  16.691 1.728 17.525 1.752 ;
     RECT  16.085 2.928 17.564 12.504 ;
     RECT  16.547 17.088 17.629 17.112 ;
     RECT  17.453 18.528 17.629 57.768 ;
     RECT  16.691 58.8 17.629 70.392 ;
     RECT  16.877 78.048 17.701 78.072 ;
     RECT  17.564 2.016 17.917 12.504 ;
     RECT  17.381 13.68 17.917 15 ;
     RECT  17.917 76.896 17.941 76.92 ;
     RECT  17.629 17.088 17.948 17.544 ;
     RECT  17.701 78.048 18.101 78.648 ;
     RECT  17.948 16.848 18.133 17.544 ;
     RECT  17.489 71.664 18.181 74.904 ;
     RECT  17.629 18.528 18.205 70.392 ;
     RECT  18.101 78.048 18.419 78.12 ;
     RECT  18.181 71.664 18.457 74.952 ;
     RECT  17.941 76.368 18.457 76.92 ;
     RECT  18.419 78.048 18.457 78.072 ;
     RECT  17.917 2.016 18.469 15 ;
     RECT  17.765 0.096 18.563 0.12 ;
     RECT  18.469 2.016 18.608 15.48 ;
     RECT  18.133 16.752 18.608 17.544 ;
     RECT  18.205 18.528 18.608 70.584 ;
     RECT  18.457 71.664 18.608 76.92 ;
     RECT  18.457 77.904 18.608 78.072 ;
     RECT  18.608 2.016 18.803 78.072 ;
     RECT  18.803 2.418 18.904 78.072 ;
     RECT  18.853 79.776 19.093 79.8 ;
     RECT  19.093 79.728 19.181 79.8 ;
     RECT  19.181 79.728 19.331 79.752 ;
     RECT  18.904 2.88 19.433 15.336 ;
     RECT  19.433 2.88 19.868 14.136 ;
     RECT  19.868 2.256 19.955 14.136 ;
     RECT  18.904 19.824 19.964 76.44 ;
     RECT  19.964 19.824 20.009 76.968 ;
     RECT  19.955 2.88 20.045 14.136 ;
     RECT  20.009 76.896 20.051 76.968 ;
     RECT  20.009 19.824 20.225 75.864 ;
     RECT  18.904 16.992 20.257 18.168 ;
     RECT  19.433 15.312 20.261 15.336 ;
     RECT  20.225 19.824 20.293 46.44 ;
     RECT  20.225 47.712 20.297 75.864 ;
     RECT  20.045 13.632 20.437 14.136 ;
     RECT  20.437 13.632 20.477 14.616 ;
     RECT  20.257 16.992 20.509 18.408 ;
     RECT  20.293 19.584 20.509 46.44 ;
     RECT  20.045 2.88 20.549 12.504 ;
     RECT  20.549 2.976 20.585 12.504 ;
     RECT  20.545 15.744 20.617 15.768 ;
     RECT  20.509 16.992 20.617 46.44 ;
     RECT  20.585 3.072 20.627 12.504 ;
     RECT  20.617 15.744 20.729 46.44 ;
     RECT  20.297 54.432 20.729 75.864 ;
     RECT  20.573 0.096 20.789 0.12 ;
     RECT  20.789 0.096 20.873 0.6 ;
     RECT  18.904 78.048 20.897 78.072 ;
     RECT  20.729 18.144 20.945 46.44 ;
     RECT  20.729 55.824 20.977 75.864 ;
     RECT  20.051 76.896 20.977 76.92 ;
     RECT  20.627 3.36 20.981 12.504 ;
     RECT  20.945 18.144 21.017 24.984 ;
     RECT  20.897 77.952 21.017 78.072 ;
     RECT  20.977 55.824 21.125 76.92 ;
     RECT  21.125 68.976 21.301 76.92 ;
     RECT  20.945 25.968 21.337 46.44 ;
     RECT  20.297 47.712 21.337 53.448 ;
     RECT  20.873 0.096 21.377 0.168 ;
     RECT  21.125 55.824 21.413 67.896 ;
     RECT  21.301 68.976 21.443 77.544 ;
     RECT  21.337 25.968 21.485 53.448 ;
     RECT  21.485 31.2 21.587 53.448 ;
     RECT  20.981 3.6 21.661 12.504 ;
     RECT  20.477 13.68 21.661 14.616 ;
     RECT  21.541 1.728 21.781 1.752 ;
     RECT  21.637 79.776 21.808 79.8 ;
     RECT  21.808 79.728 21.809 79.8 ;
     RECT  21.781 1.152 21.881 1.752 ;
     RECT  20.729 15.744 21.881 17.064 ;
     RECT  21.809 79.728 21.913 79.752 ;
     RECT  21.587 31.2 21.989 41.496 ;
     RECT  21.881 16.272 22.025 17.064 ;
     RECT  21.443 68.976 22.025 76.92 ;
     RECT  21.017 18.384 22.057 24.984 ;
     RECT  21.485 25.968 22.057 30.12 ;
     RECT  21.377 0.096 22.061 0.12 ;
     RECT  22.057 18.384 22.097 30.12 ;
     RECT  21.661 3.6 22.133 14.616 ;
     RECT  22.025 16.368 22.165 17.064 ;
     RECT  22.097 18.384 22.165 24.6 ;
     RECT  22.133 3.6 22.213 11.352 ;
     RECT  21.587 42.528 22.241 53.448 ;
     RECT  22.025 76.896 22.241 76.92 ;
     RECT  22.025 68.976 22.355 75.864 ;
     RECT  21.413 56.016 22.381 67.896 ;
     RECT  22.133 12.864 22.417 14.616 ;
     RECT  22.213 2.88 22.421 11.352 ;
     RECT  22.417 12.864 22.453 14.664 ;
     RECT  22.097 25.68 22.453 30.12 ;
     RECT  22.241 45.504 22.489 53.448 ;
     RECT  20.729 54.432 22.489 54.6 ;
     RECT  22.453 12.864 22.525 14.76 ;
     RECT  22.489 45.504 22.525 54.6 ;
     RECT  22.381 55.872 22.525 67.896 ;
     RECT  22.525 45.504 22.529 67.896 ;
     RECT  22.355 68.976 22.561 75.72 ;
     RECT  21.881 1.728 22.633 1.752 ;
     RECT  21.989 33.312 22.705 41.496 ;
     RECT  22.241 42.528 22.705 44.136 ;
     RECT  22.633 1.728 22.739 2.28 ;
     RECT  22.165 16.368 22.745 24.6 ;
     RECT  22.529 49.008 22.745 67.896 ;
     RECT  22.745 16.368 22.781 17.064 ;
     RECT  22.745 18.192 22.781 24.6 ;
     RECT  21.913 79.248 22.789 79.752 ;
     RECT  22.453 25.68 22.813 30.216 ;
     RECT  21.989 31.2 22.813 32.328 ;
     RECT  22.745 58.512 22.817 67.896 ;
     RECT  22.789 79.2 22.949 79.752 ;
     RECT  22.949 79.2 23.033 79.8 ;
     RECT  22.817 67.056 23.065 67.896 ;
     RECT  22.561 68.928 23.065 75.72 ;
     RECT  22.781 19.344 23.077 24.6 ;
     RECT  22.813 25.68 23.077 32.328 ;
     RECT  23.165 0.096 23.249 0.12 ;
     RECT  22.421 3.6 23.317 11.352 ;
     RECT  23.065 67.056 23.317 75.72 ;
     RECT  22.705 33.312 23.389 44.136 ;
     RECT  23.077 19.344 23.413 32.328 ;
     RECT  23.389 33.312 23.413 44.472 ;
     RECT  23.317 67.056 23.701 76.2 ;
     RECT  23.18 77.52 23.701 77.544 ;
     RECT  22.781 18.192 23.756 18.216 ;
     RECT  23.413 19.344 23.756 44.472 ;
     RECT  23.317 3.6 23.785 11.496 ;
     RECT  22.529 45.504 23.797 47.832 ;
     RECT  22.745 49.008 23.797 57.432 ;
     RECT  22.525 12.864 23.821 14.952 ;
     RECT  23.033 79.2 23.861 79.224 ;
     RECT  23.785 3.6 23.893 11.784 ;
     RECT  23.821 12.768 23.893 14.952 ;
     RECT  23.701 67.056 23.9 77.544 ;
     RECT  23.797 45.504 23.929 57.432 ;
     RECT  22.817 58.512 23.929 65.976 ;
     RECT  23.9 67.056 23.987 78.12 ;
     RECT  22.739 1.728 24.008 1.8 ;
     RECT  23.893 3.6 24.008 14.952 ;
     RECT  22.781 16.368 24.008 16.92 ;
     RECT  23.756 18.192 24.008 44.472 ;
     RECT  23.929 45.504 24.008 65.976 ;
     RECT  23.987 67.056 24.008 77.772 ;
     RECT  24.008 1.728 24.112 77.772 ;
     RECT  24.112 1.728 24.304 77.502 ;
     RECT  24.304 18.72 24.365 76.44 ;
     RECT  24.304 1.728 24.401 1.752 ;
     RECT  24.325 0.096 24.467 0.12 ;
     RECT  24.365 18.72 24.515 41.496 ;
     RECT  24.365 42.528 24.659 76.44 ;
     RECT  24.565 0.528 24.796 0.6 ;
     RECT  24.515 20.064 24.797 41.496 ;
     RECT  24.181 79.728 24.853 79.752 ;
     RECT  24.853 79.2 24.941 79.752 ;
     RECT  24.796 0.528 25.043 0.648 ;
     RECT  25.043 0.624 25.049 0.648 ;
     RECT  24.797 33.648 25.049 41.496 ;
     RECT  24.659 42.528 25.049 76.392 ;
     RECT  25.049 42.528 25.085 75.624 ;
     RECT  24.941 79.248 25.093 79.752 ;
     RECT  24.797 20.064 25.121 32.52 ;
     RECT  24.304 3.408 25.193 15.048 ;
     RECT  25.121 20.064 25.373 32.472 ;
     RECT  25.093 79.248 25.379 79.8 ;
     RECT  25.373 20.064 25.475 29.448 ;
     RECT  24.304 16.368 25.549 17.208 ;
     RECT  25.193 3.456 25.553 15.048 ;
     RECT  25.553 3.6 25.589 15.048 ;
     RECT  25.085 45.504 25.625 75.624 ;
     RECT  25.549 16.272 25.657 17.208 ;
     RECT  25.373 30.672 25.697 32.472 ;
     RECT  25.475 20.064 25.717 23.688 ;
     RECT  25.717 19.968 25.729 23.688 ;
     RECT  25.477 1.728 25.765 1.752 ;
     RECT  24.515 18.72 25.765 18.744 ;
     RECT  25.729 19.824 25.765 23.688 ;
     RECT  25.625 45.504 25.985 55.752 ;
     RECT  25.049 33.648 26.089 36.792 ;
     RECT  25.049 37.92 26.089 41.496 ;
     RECT  25.985 47.424 26.093 55.752 ;
     RECT  25.697 30.72 26.125 32.472 ;
     RECT  26.089 33.648 26.125 41.496 ;
     RECT  25.085 42.528 26.125 44.232 ;
     RECT  25.985 45.504 26.125 46.248 ;
     RECT  25.625 57.312 26.125 75.624 ;
     RECT  25.657 16.224 26.197 17.208 ;
     RECT  26.125 30.72 26.197 41.496 ;
     RECT  26.125 42.528 26.197 46.248 ;
     RECT  26.125 57.312 26.201 75.96 ;
     RECT  26.197 16.224 26.243 17.448 ;
     RECT  26.201 57.312 26.345 70.344 ;
     RECT  26.243 16.224 26.381 16.44 ;
     RECT  25.765 18.72 26.381 23.688 ;
     RECT  26.197 30.72 26.417 46.248 ;
     RECT  25.379 79.776 26.417 79.8 ;
     RECT  25.765 1.728 26.435 2.28 ;
     RECT  25.475 24.72 26.483 29.448 ;
     RECT  26.381 16.224 26.521 16.296 ;
     RECT  25.589 3.6 26.593 14.424 ;
     RECT  25.441 77.52 26.629 77.544 ;
     RECT  26.093 47.616 26.669 55.752 ;
     RECT  26.381 18.72 26.701 19.368 ;
     RECT  26.669 55.728 26.701 55.752 ;
     RECT  26.201 71.328 26.701 75.96 ;
     RECT  26.593 2.88 26.723 14.424 ;
     RECT  26.701 55.728 26.737 56.184 ;
     RECT  26.435 1.728 26.777 1.8 ;
     RECT  26.723 3.168 26.777 14.424 ;
     RECT  26.777 3.648 26.809 14.424 ;
     RECT  26.521 16.032 26.809 16.296 ;
     RECT  26.701 71.328 26.813 76.536 ;
     RECT  26.345 58.128 26.819 70.344 ;
     RECT  26.737 55.728 26.885 56.856 ;
     RECT  26.629 77.52 26.917 77.64 ;
     RECT  26.837 0.096 26.921 0.12 ;
     RECT  26.483 25.008 27.025 29.448 ;
     RECT  26.417 30.72 27.025 32.28 ;
     RECT  26.917 77.52 27.065 78.12 ;
     RECT  26.885 55.968 27.313 56.856 ;
     RECT  26.819 68.928 27.313 70.344 ;
     RECT  26.813 71.328 27.313 76.248 ;
     RECT  26.777 1.728 27.349 1.752 ;
     RECT  26.809 3.648 27.349 16.296 ;
     RECT  26.243 17.424 27.349 17.448 ;
     RECT  27.349 1.152 27.353 1.752 ;
     RECT  26.417 33.264 27.353 46.248 ;
     RECT  27.349 3.648 27.385 17.448 ;
     RECT  26.701 18.48 27.385 19.368 ;
     RECT  27.353 45.504 27.385 46.248 ;
     RECT  26.669 47.616 27.385 54.744 ;
     RECT  27.313 55.968 27.457 57.048 ;
     RECT  26.819 58.128 27.457 67.944 ;
     RECT  27.385 3.648 27.501 19.368 ;
     RECT  26.381 20.4 27.501 23.688 ;
     RECT  27.397 79.2 27.533 79.224 ;
     RECT  27.385 45.504 27.641 54.744 ;
     RECT  27.353 1.152 27.713 1.176 ;
     RECT  27.457 55.968 27.817 67.944 ;
     RECT  27.313 68.928 27.817 76.248 ;
     RECT  27.817 55.968 27.821 76.248 ;
     RECT  27.821 71.376 27.829 76.248 ;
     RECT  27.773 0.576 27.857 0.6 ;
     RECT  27.641 53.328 27.925 54.744 ;
     RECT  27.821 55.968 27.925 70.344 ;
     RECT  27.065 77.52 28.069 77.544 ;
     RECT  27.025 25.008 28.105 32.28 ;
     RECT  27.353 33.264 28.105 44.424 ;
     RECT  27.501 3.648 28.213 23.688 ;
     RECT  28.213 3.552 28.249 23.688 ;
     RECT  28.105 25.008 28.249 44.424 ;
     RECT  27.925 53.328 28.259 70.344 ;
     RECT  28.069 77.52 28.355 78.12 ;
     RECT  27.829 71.376 28.549 76.392 ;
     RECT  28.501 1.728 28.7 1.752 ;
     RECT  28.355 78.096 28.753 78.12 ;
     RECT  28.753 78.096 28.837 78.648 ;
     RECT  27.641 45.504 28.933 45.528 ;
     RECT  27.641 46.512 28.933 46.536 ;
     RECT  28.7 1.728 29.077 2.28 ;
     RECT  28.249 3.552 29.077 44.424 ;
     RECT  27.641 47.664 29.077 52.296 ;
     RECT  29.077 1.728 29.081 44.424 ;
     RECT  29.077 47.616 29.221 52.296 ;
     RECT  28.259 53.376 29.221 70.344 ;
     RECT  28.933 45.504 29.269 46.536 ;
     RECT  29.221 47.616 29.269 70.344 ;
     RECT  28.837 78.096 29.369 78.12 ;
     RECT  29.081 2.148 29.408 44.424 ;
     RECT  29.269 45.504 29.408 70.344 ;
     RECT  28.549 71.376 29.408 76.968 ;
     RECT  29.408 2.148 29.512 77.772 ;
     RECT  29.269 79.728 29.701 79.752 ;
     RECT  29.512 2.148 29.704 77.544 ;
     RECT  29.701 79.2 29.837 79.752 ;
     RECT  29.893 1.152 29.981 1.176 ;
     RECT  28.021 0.096 30.017 0.12 ;
     RECT  29.704 36.912 30.017 44.424 ;
     RECT  29.704 45.504 30.125 77.544 ;
     RECT  30.017 36.912 30.197 44.136 ;
     RECT  29.704 30.528 30.557 35.832 ;
     RECT  30.125 77.52 30.659 77.544 ;
     RECT  30.557 33.408 30.697 35.832 ;
     RECT  29.704 20.592 30.769 29.4 ;
     RECT  30.557 30.528 30.769 32.328 ;
     RECT  30.373 79.776 30.773 79.8 ;
     RECT  30.769 20.592 30.809 32.328 ;
     RECT  30.197 37.92 30.809 44.136 ;
     RECT  30.697 33.408 30.845 35.928 ;
     RECT  30.809 37.92 30.845 41.256 ;
     RECT  29.704 2.88 30.877 19.368 ;
     RECT  30.877 2.832 31.091 19.368 ;
     RECT  31.091 2.88 31.097 19.368 ;
     RECT  30.809 42.288 31.097 44.136 ;
     RECT  30.853 78.048 31.097 78.12 ;
     RECT  31.097 10.56 31.129 19.368 ;
     RECT  30.809 20.592 31.129 23.688 ;
     RECT  30.197 36.912 31.165 36.936 ;
     RECT  30.845 37.92 31.165 41.016 ;
     RECT  30.809 24.672 31.205 32.328 ;
     RECT  30.845 33.6 31.237 35.928 ;
     RECT  31.165 36.912 31.237 41.016 ;
     RECT  30.373 1.728 31.241 1.752 ;
     RECT  31.205 27.456 31.241 32.328 ;
     RECT  31.237 33.6 31.277 41.016 ;
     RECT  30.125 45.504 31.313 76.536 ;
     RECT  31.165 79.248 31.331 79.272 ;
     RECT  31.313 45.504 31.345 75.864 ;
     RECT  30.805 0.576 31.349 0.6 ;
     RECT  31.345 45.168 31.379 75.864 ;
     RECT  31.241 27.6 31.385 32.328 ;
     RECT  31.277 33.6 31.385 38.808 ;
     RECT  31.385 31.152 31.601 32.328 ;
     RECT  31.525 76.944 31.633 76.968 ;
     RECT  31.097 78.048 31.633 78.072 ;
     RECT  31.601 31.152 31.709 32.28 ;
     RECT  31.379 45.168 31.709 53.976 ;
     RECT  31.709 31.152 31.745 31.8 ;
     RECT  31.633 76.944 31.817 78.072 ;
     RECT  31.385 33.6 31.849 38.568 ;
     RECT  31.129 10.56 31.885 23.688 ;
     RECT  31.205 24.672 31.885 26.376 ;
     RECT  31.849 33.552 31.921 38.568 ;
     RECT  31.709 45.168 31.921 47.64 ;
     RECT  31.385 27.6 31.925 29.736 ;
     RECT  31.277 39.84 31.993 41.016 ;
     RECT  31.964 1.104 32.051 1.128 ;
     RECT  31.817 77.52 32.069 78.072 ;
     RECT  31.885 10.56 32.092 26.376 ;
     RECT  31.379 55.104 32.092 75.864 ;
     RECT  31.921 33.264 32.249 38.568 ;
     RECT  31.925 27.888 32.357 29.736 ;
     RECT  31.709 48.72 32.357 53.976 ;
     RECT  32.092 10.848 32.461 26.376 ;
     RECT  32.485 79.776 32.627 79.8 ;
     RECT  32.092 56.112 32.641 75.864 ;
     RECT  31.097 42.72 32.677 44.136 ;
     RECT  31.921 45.12 32.677 47.64 ;
     RECT  32.461 10.848 32.681 26.856 ;
     RECT  32.677 42.72 32.713 47.64 ;
     RECT  32.713 42.72 32.771 47.736 ;
     RECT  31.993 39.84 32.785 41.064 ;
     RECT  32.771 42.72 32.785 44.136 ;
     RECT  32.681 10.944 32.789 26.856 ;
     RECT  32.357 27.888 32.789 29.016 ;
     RECT  32.771 45.12 32.789 47.736 ;
     RECT  32.789 46.752 32.821 47.736 ;
     RECT  32.357 48.72 32.821 53.4 ;
     RECT  32.677 79.2 32.897 79.224 ;
     RECT  32.069 77.52 32.963 77.544 ;
     RECT  31.745 31.2 32.965 31.8 ;
     RECT  31.097 2.88 33.005 9.336 ;
     RECT  32.249 33.264 33.005 38.52 ;
     RECT  32.789 10.944 33.041 19.368 ;
     RECT  32.092 55.104 33.073 55.128 ;
     RECT  32.641 56.112 33.073 75.96 ;
     RECT  33.073 55.104 33.109 75.96 ;
     RECT  33.005 3.648 33.149 9.336 ;
     RECT  33.041 18.816 33.149 19.368 ;
     RECT  32.965 30.912 33.185 31.8 ;
     RECT  33.109 0.528 33.203 0.552 ;
     RECT  32.417 1.728 33.217 1.752 ;
     RECT  33.041 16.128 33.221 17.736 ;
     RECT  33.109 54.864 33.257 75.96 ;
     RECT  33.149 18.816 33.293 19.32 ;
     RECT  32.789 20.352 33.293 26.376 ;
     RECT  33.185 31.776 33.293 31.8 ;
     RECT  33.149 8.448 33.329 9.336 ;
     RECT  32.789 45.12 33.329 45.624 ;
     RECT  33.257 55.104 33.365 75.96 ;
     RECT  33.005 33.456 33.401 38.52 ;
     RECT  33.365 55.104 33.437 67.896 ;
     RECT  33.293 19.008 33.509 19.32 ;
     RECT  32.789 28.224 33.509 29.016 ;
     RECT  33.221 16.464 33.545 17.736 ;
     RECT  33.437 55.728 33.545 67.896 ;
     RECT  33.509 19.104 33.581 19.32 ;
     RECT  33.365 69.024 33.637 75.96 ;
     RECT  33.329 45.12 33.653 45.576 ;
     RECT  33.401 33.648 33.689 38.52 ;
     RECT  32.785 39.84 33.761 44.136 ;
     RECT  33.217 1.728 33.788 2.28 ;
     RECT  33.329 8.496 33.829 9.336 ;
     RECT  33.545 16.56 33.833 17.736 ;
     RECT  33.793 30.336 33.865 30.36 ;
     RECT  33.788 1.68 33.875 2.28 ;
     RECT  33.293 25.68 33.937 26.376 ;
     RECT  33.761 42.528 33.973 44.136 ;
     RECT  33.761 39.84 34.009 41.496 ;
     RECT  34.009 78.096 34.115 78.12 ;
     RECT  33.689 36.912 34.153 38.52 ;
     RECT  33.829 8.496 34.333 9.864 ;
     RECT  33.041 10.944 34.333 14.712 ;
     RECT  32.821 46.752 34.357 53.4 ;
     RECT  33.545 64.944 34.357 67.896 ;
     RECT  33.637 69.024 34.357 76.392 ;
     RECT  34.333 8.256 34.513 14.712 ;
     RECT  34.357 46.752 34.513 54.12 ;
     RECT  33.689 33.648 34.549 35.496 ;
     RECT  34.081 31.968 34.621 31.992 ;
     RECT  34.549 33.6 34.621 35.496 ;
     RECT  33.545 55.728 34.621 63.816 ;
     RECT  34.357 64.944 34.621 76.392 ;
     RECT  33.149 3.648 34.657 7.176 ;
     RECT  34.513 8.256 34.657 15.24 ;
     RECT  34.621 31.968 34.729 35.496 ;
     RECT  34.153 36.912 34.729 38.712 ;
     RECT  34.657 3.648 34.765 15.24 ;
     RECT  33.875 1.728 34.808 2.28 ;
     RECT  34.765 3.408 34.808 15.24 ;
     RECT  33.833 16.8 34.808 17.736 ;
     RECT  33.581 19.296 34.808 19.32 ;
     RECT  33.293 20.352 34.808 24.648 ;
     RECT  33.937 25.68 34.808 27.192 ;
     RECT  33.509 28.224 34.808 28.536 ;
     RECT  33.865 29.52 34.808 30.36 ;
     RECT  34.729 31.968 34.808 38.808 ;
     RECT  34.009 39.792 34.808 41.496 ;
     RECT  33.973 42.528 34.808 44.472 ;
     RECT  33.653 45.504 34.808 45.576 ;
     RECT  34.513 46.752 34.808 54.696 ;
     RECT  34.621 55.728 34.808 76.392 ;
     RECT  34.808 1.728 35.104 78.072 ;
     RECT  35.104 69.024 35.161 78.072 ;
     RECT  35.104 37.152 35.165 45.672 ;
     RECT  35.104 57.6 35.219 67.992 ;
     RECT  35.104 20.352 35.267 28.536 ;
     RECT  35.161 69.024 35.267 78.696 ;
     RECT  35.104 2.976 35.308 19.368 ;
     RECT  34.789 0.144 35.315 0.168 ;
     RECT  35.104 1.728 35.345 1.8 ;
     RECT  35.219 57.6 35.381 65.304 ;
     RECT  35.308 3.408 35.453 19.368 ;
     RECT  34.789 79.776 35.777 79.8 ;
     RECT  35.165 37.2 35.884 45.672 ;
     RECT  35.104 46.704 35.939 56.376 ;
     RECT  35.345 1.728 35.941 1.752 ;
     RECT  35.884 37.2 35.957 38.808 ;
     RECT  35.267 69.024 36.137 78.072 ;
     RECT  36.137 77.52 36.179 78.072 ;
     RECT  35.267 22.464 36.205 28.536 ;
     RECT  35.104 30.096 36.205 30.36 ;
     RECT  35.884 39.84 36.241 45.672 ;
     RECT  35.939 46.704 36.241 46.728 ;
     RECT  35.453 3.408 36.281 17.64 ;
     RECT  36.241 39.84 36.281 46.728 ;
     RECT  35.941 1.152 36.317 1.752 ;
     RECT  35.267 20.352 36.385 21.48 ;
     RECT  36.205 22.464 36.385 30.36 ;
     RECT  35.219 66.288 36.385 67.992 ;
     RECT  36.137 69.024 36.385 75.864 ;
     RECT  36.281 3.408 36.425 15 ;
     RECT  36.281 15.984 36.425 17.64 ;
     RECT  35.957 37.2 36.457 38.76 ;
     RECT  36.425 16.512 36.469 17.64 ;
     RECT  35.453 18.72 36.469 19.368 ;
     RECT  35.381 57.6 36.493 65.256 ;
     RECT  36.385 66.288 36.493 75.864 ;
     RECT  36.469 16.512 36.515 19.368 ;
     RECT  35.939 47.712 36.517 56.376 ;
     RECT  36.493 57.6 36.517 75.864 ;
     RECT  36.457 37.104 36.525 38.76 ;
     RECT  36.515 16.8 36.601 19.368 ;
     RECT  36.385 20.352 36.601 30.36 ;
     RECT  36.425 10.848 36.605 15 ;
     RECT  35.104 31.776 36.605 36.024 ;
     RECT  36.517 47.712 36.605 75.864 ;
     RECT  36.317 1.728 36.613 1.752 ;
     RECT  36.605 31.92 36.637 36.024 ;
     RECT  36.525 37.104 36.637 38.712 ;
     RECT  36.425 3.408 36.709 9.816 ;
     RECT  36.613 1.728 36.713 2.328 ;
     RECT  36.281 39.84 36.785 43.176 ;
     RECT  36.601 16.8 36.857 30.36 ;
     RECT  36.605 57.552 36.892 75.864 ;
     RECT  36.857 20.352 36.929 30.36 ;
     RECT  36.605 47.712 36.929 56.424 ;
     RECT  36.179 77.952 36.929 78.072 ;
     RECT  36.892 71.136 37.001 75.864 ;
     RECT  36.709 3.36 37.037 9.816 ;
     RECT  36.929 25.68 37.037 30.36 ;
     RECT  37.037 29.28 37.105 30.36 ;
     RECT  37.093 0.576 37.181 0.6 ;
     RECT  36.281 44.16 37.285 46.728 ;
     RECT  36.929 47.712 37.285 54.168 ;
     RECT  37.001 71.28 37.321 75.864 ;
     RECT  36.857 16.8 37.325 19.368 ;
     RECT  37.321 71.28 37.325 76.392 ;
     RECT  36.785 39.84 37.433 42.84 ;
     RECT  36.605 10.848 37.621 14.952 ;
     RECT  36.637 31.92 37.645 38.712 ;
     RECT  37.037 25.68 37.649 28.296 ;
     RECT  37.037 3.648 37.681 9.816 ;
     RECT  37.621 10.848 37.681 15.432 ;
     RECT  37.325 16.8 37.681 17.64 ;
     RECT  37.649 25.68 37.685 27.864 ;
     RECT  37.105 29.28 37.685 30.84 ;
     RECT  37.681 3.648 37.721 17.64 ;
     RECT  36.713 1.728 37.861 2.28 ;
     RECT  37.285 44.16 37.907 54.168 ;
     RECT  37.907 44.16 37.937 54.072 ;
     RECT  37.325 18.768 38.041 19.368 ;
     RECT  36.929 20.352 38.041 24.504 ;
     RECT  37.861 1.104 38.051 2.28 ;
     RECT  37.433 39.888 38.077 42.84 ;
     RECT  37.937 44.16 38.077 53.832 ;
     RECT  36.929 78.048 38.117 78.072 ;
     RECT  36.929 55.44 38.185 56.424 ;
     RECT  36.892 57.552 38.185 70.008 ;
     RECT  37.721 15.888 38.189 17.64 ;
     RECT  37.685 29.328 38.204 30.84 ;
     RECT  37.645 31.92 38.204 38.808 ;
     RECT  38.204 29.328 38.261 38.808 ;
     RECT  37.721 3.648 38.369 14.712 ;
     RECT  37.685 25.776 38.405 27.864 ;
     RECT  37.285 79.2 38.437 79.224 ;
     RECT  38.185 55.44 38.441 70.008 ;
     RECT  38.437 79.2 38.477 79.8 ;
     RECT  38.261 32.832 38.513 38.808 ;
     RECT  37.325 71.424 38.677 76.392 ;
     RECT  38.077 39.888 38.693 53.832 ;
     RECT  38.189 16.512 38.725 17.64 ;
     RECT  38.041 18.768 38.725 24.504 ;
     RECT  38.513 36.864 38.725 38.808 ;
     RECT  38.693 39.888 38.725 41.496 ;
     RECT  38.441 55.44 38.725 63.864 ;
     RECT  38.477 79.776 38.765 79.8 ;
     RECT  38.051 1.728 38.771 2.28 ;
     RECT  38.725 16.512 38.833 24.504 ;
     RECT  38.677 71.424 38.837 76.92 ;
     RECT  38.261 29.328 38.873 31.656 ;
     RECT  38.369 5.472 38.965 14.712 ;
     RECT  38.833 16.512 39.011 24.744 ;
     RECT  38.693 42.576 39.017 53.832 ;
     RECT  38.965 5.472 39.053 15.528 ;
     RECT  39.011 17.424 39.121 24.744 ;
     RECT  38.405 25.776 39.121 27.72 ;
     RECT  39.017 47.424 39.265 53.832 ;
     RECT  38.771 1.728 39.341 1.752 ;
     RECT  38.369 3.648 39.397 4.44 ;
     RECT  39.581 79.2 39.665 79.224 ;
     RECT  38.837 71.424 39.733 76.872 ;
     RECT  38.245 0.576 39.877 0.6 ;
     RECT  39.121 17.424 39.877 27.72 ;
     RECT  38.873 29.328 39.884 29.352 ;
     RECT  39.884 29.328 39.905 29.832 ;
     RECT  38.873 31.632 39.905 31.656 ;
     RECT  39.397 3.408 39.913 4.44 ;
     RECT  39.913 3.408 39.973 4.488 ;
     RECT  39.877 0.096 40.019 0.6 ;
     RECT  39.877 17.424 40.021 27.96 ;
     RECT  39.973 2.88 40.069 4.488 ;
     RECT  39.053 5.472 40.069 15.384 ;
     RECT  39.265 47.424 40.093 54.12 ;
     RECT  40.019 0.192 40.163 0.6 ;
     RECT  40.069 2.88 40.208 15.384 ;
     RECT  40.021 17.424 40.208 28.2 ;
     RECT  39.905 29.328 40.208 31.656 ;
     RECT  38.513 32.832 40.208 35.736 ;
     RECT  38.725 36.864 40.208 41.496 ;
     RECT  39.017 42.576 40.208 46.104 ;
     RECT  40.093 47.328 40.208 54.12 ;
     RECT  38.725 55.2 40.208 63.864 ;
     RECT  38.441 64.896 40.208 70.008 ;
     RECT  39.733 71.376 40.208 76.872 ;
     RECT  39.829 78.048 40.208 78.072 ;
     RECT  40.163 0.288 40.403 0.6 ;
     RECT  40.208 2.148 40.504 78.072 ;
     RECT  40.504 47.328 40.673 47.64 ;
     RECT  40.021 79.728 40.789 79.752 ;
     RECT  40.403 0.576 40.853 0.6 ;
     RECT  40.504 5.472 40.925 13.32 ;
     RECT  40.504 17.088 41.033 27.72 ;
     RECT  40.504 30.816 41.033 31.656 ;
     RECT  40.925 5.472 41.141 13.128 ;
     RECT  41.033 17.088 41.171 22.056 ;
     RECT  40.789 79.728 41.177 79.8 ;
     RECT  41.141 8.448 41.249 13.128 ;
     RECT  40.504 49.056 41.285 70.104 ;
     RECT  41.285 55.872 41.429 70.104 ;
     RECT  40.673 47.424 41.465 47.64 ;
     RECT  40.504 76.896 41.465 76.92 ;
     RECT  40.504 29.328 41.468 29.352 ;
     RECT  40.504 2.88 41.497 4.44 ;
     RECT  41.141 5.472 41.497 7.464 ;
     RECT  41.177 79.728 41.501 79.752 ;
     RECT  40.504 78.048 41.509 78.072 ;
     RECT  41.171 20.112 41.555 22.056 ;
     RECT  40.504 32.832 41.569 45.816 ;
     RECT  41.555 20.208 41.573 22.056 ;
     RECT  40.504 14.4 41.609 15.864 ;
     RECT  41.569 32.832 41.609 46.104 ;
     RECT  41.033 31.632 41.845 31.656 ;
     RECT  41.609 32.832 41.845 40.44 ;
     RECT  41.465 47.424 41.845 47.448 ;
     RECT  41.468 29.328 41.893 29.544 ;
     RECT  41.285 49.056 41.893 54.696 ;
     RECT  41.429 66.48 41.893 70.104 ;
     RECT  40.504 71.232 41.893 75.624 ;
     RECT  41.701 76.944 41.933 77.544 ;
     RECT  41.497 2.88 42.049 7.464 ;
     RECT  41.845 47.328 42.077 47.448 ;
     RECT  41.933 76.944 42.179 76.968 ;
     RECT  41.171 17.088 42.185 19.08 ;
     RECT  41.893 66.48 42.289 75.624 ;
     RECT  41.573 20.4 42.332 22.056 ;
     RECT  41.033 23.136 42.332 27.72 ;
     RECT  41.893 48.912 42.361 54.696 ;
     RECT  41.429 55.872 42.361 65.256 ;
     RECT  42.332 20.4 42.419 27.72 ;
     RECT  42.049 3.936 42.437 7.464 ;
     RECT  41.893 28.992 42.505 29.544 ;
     RECT  41.609 14.4 42.509 15.816 ;
     RECT  42.049 2.88 42.545 2.952 ;
     RECT  42.419 20.4 42.563 22.44 ;
     RECT  42.505 28.992 42.641 30.024 ;
     RECT  42.641 28.8 42.649 30.024 ;
     RECT  42.14 0.528 42.707 0.552 ;
     RECT  41.249 8.496 42.721 13.128 ;
     RECT  41.609 41.424 42.721 46.104 ;
     RECT  42.361 48.912 42.721 65.256 ;
     RECT  42.649 28.8 42.725 30.12 ;
     RECT  42.563 20.496 42.748 22.44 ;
     RECT  42.437 4.416 42.761 7.464 ;
     RECT  42.721 48.72 42.761 65.256 ;
     RECT  42.185 17.088 42.793 17.736 ;
     RECT  42.761 4.464 42.829 7.464 ;
     RECT  42.721 8.448 42.829 13.128 ;
     RECT  41.845 31.632 42.937 40.44 ;
     RECT  42.721 41.424 42.937 46.392 ;
     RECT  42.077 47.424 42.973 47.448 ;
     RECT  42.761 48.72 42.973 63.864 ;
     RECT  42.725 29.328 42.997 30.12 ;
     RECT  42.937 31.632 42.997 46.392 ;
     RECT  42.509 14.4 43.013 15.576 ;
     RECT  42.545 2.88 43.049 2.904 ;
     RECT  42.829 4.464 43.117 13.128 ;
     RECT  42.997 29.328 43.141 46.392 ;
     RECT  42.973 47.424 43.141 63.864 ;
     RECT  43.117 4.464 43.189 13.368 ;
     RECT  42.185 19.056 43.261 19.08 ;
     RECT  42.761 64.848 43.261 65.256 ;
     RECT  42.289 66.48 43.261 75.96 ;
     RECT  42.373 79.776 43.265 79.8 ;
     RECT  43.141 29.328 43.337 63.864 ;
     RECT  42.853 78.048 43.337 78.072 ;
     RECT  42.793 16.56 43.373 17.736 ;
     RECT  43.381 0.096 43.481 0.12 ;
     RECT  43.261 64.848 43.481 75.96 ;
     RECT  43.481 66.288 43.517 75.96 ;
     RECT  43.517 66.384 43.549 75.96 ;
     RECT  42.748 20.496 43.585 22.056 ;
     RECT  42.419 23.424 43.621 27.72 ;
     RECT  43.013 14.4 43.697 15 ;
     RECT  43.337 56.88 43.697 63.864 ;
     RECT  43.189 4.464 43.877 13.416 ;
     RECT  43.261 18.768 43.909 19.08 ;
     RECT  43.585 20.112 43.909 22.056 ;
     RECT  43.621 23.424 43.909 27.912 ;
     RECT  43.337 29.328 43.909 55.704 ;
     RECT  43.549 66.384 44.005 76.824 ;
     RECT  43.373 16.656 44.017 17.736 ;
     RECT  43.909 18.768 44.017 22.056 ;
     RECT  41.269 1.728 44.053 1.752 ;
     RECT  44.017 16.656 44.125 22.056 ;
     RECT  43.909 23.424 44.125 55.704 ;
     RECT  43.877 5.136 44.129 13.416 ;
     RECT  44.053 1.152 44.237 1.752 ;
     RECT  44.129 5.136 44.237 13.368 ;
     RECT  43.697 63.36 44.3 63.864 ;
     RECT  43.481 64.848 44.3 65.256 ;
     RECT  43.697 56.88 44.387 62.328 ;
     RECT  44.005 66.384 44.437 77.544 ;
     RECT  44.437 66.384 44.453 78.072 ;
     RECT  44.125 16.656 44.521 55.704 ;
     RECT  44.3 63.36 44.521 65.256 ;
     RECT  44.453 66.384 44.521 76.92 ;
     RECT  44.521 16.608 44.593 55.704 ;
     RECT  44.387 56.88 44.593 61.368 ;
     RECT  43.697 14.592 44.597 15 ;
     RECT  44.521 63.36 44.665 76.92 ;
     RECT  44.245 79.776 44.909 79.8 ;
     RECT  44.945 0.096 45.029 0.12 ;
     RECT  44.597 14.64 45.169 15 ;
     RECT  44.593 16.608 45.169 61.368 ;
     RECT  44.341 4.128 45.205 4.152 ;
     RECT  44.237 5.136 45.205 13.32 ;
     RECT  44.453 78.048 45.281 78.072 ;
     RECT  45.205 4.128 45.421 13.368 ;
     RECT  44.665 62.976 45.529 76.92 ;
     RECT  44.237 1.728 45.608 1.752 ;
     RECT  44.533 2.88 45.608 2.904 ;
     RECT  45.421 4.128 45.608 13.656 ;
     RECT  45.169 14.64 45.608 61.368 ;
     RECT  45.529 62.496 45.608 76.92 ;
     RECT  45.493 77.904 45.608 77.928 ;
     RECT  45.608 1.728 45.635 77.928 ;
     RECT  45.635 1.728 45.712 77.772 ;
     RECT  44.909 79.728 45.829 79.8 ;
     RECT  45.712 1.728 45.904 77.502 ;
     RECT  45.904 1.728 46.037 1.8 ;
     RECT  45.904 65.232 46.109 76.968 ;
     RECT  45.904 2.88 46.181 2.952 ;
     RECT  46.181 2.88 46.325 2.904 ;
     RECT  45.904 31.632 46.397 61.368 ;
     RECT  46.109 65.232 46.397 76.92 ;
     RECT  45.904 15.696 46.505 30.408 ;
     RECT  46.397 39.6 46.541 61.368 ;
     RECT  46.037 1.728 46.72 1.752 ;
     RECT  46.541 39.6 46.721 54.408 ;
     RECT  46.541 55.488 46.721 61.368 ;
     RECT  46.397 66.24 46.78 76.92 ;
     RECT  45.904 4.56 46.793 14.664 ;
     RECT  46.721 47.28 46.793 54.408 ;
     RECT  46.72 1.68 46.837 1.752 ;
     RECT  45.904 62.496 46.865 63.912 ;
     RECT  46.397 31.632 46.933 38.52 ;
     RECT  46.793 47.28 47.009 54.36 ;
     RECT  46.741 78.048 47.009 78.072 ;
     RECT  46.865 63.216 47.045 63.912 ;
     RECT  46.837 1.152 47.297 1.752 ;
     RECT  46.933 31.536 47.333 38.52 ;
     RECT  47.009 47.328 47.333 54.36 ;
     RECT  47.045 63.36 47.333 63.912 ;
     RECT  47.333 48.672 47.369 54.36 ;
     RECT  46.721 58.992 47.369 61.368 ;
     RECT  45.829 79.2 47.585 79.8 ;
     RECT  47.369 48.96 47.801 54.36 ;
     RECT  46.78 66.24 47.833 75.48 ;
     RECT  46.78 76.512 47.833 76.92 ;
     RECT  47.833 66.24 47.843 76.92 ;
     RECT  47.843 66.24 47.845 76.776 ;
     RECT  47.297 1.728 47.873 1.752 ;
     RECT  46.505 15.696 47.941 30.12 ;
     RECT  47.333 31.536 47.941 38.28 ;
     RECT  47.333 63.36 47.981 63.384 ;
     RECT  46.721 39.6 48.013 46.104 ;
     RECT  47.333 47.328 48.013 47.688 ;
     RECT  46.721 55.488 48.017 57.912 ;
     RECT  47.845 66.24 48.017 76.536 ;
     RECT  47.801 49.344 48.044 54.36 ;
     RECT  48.044 49.344 48.085 54.504 ;
     RECT  48.013 39.6 48.121 47.688 ;
     RECT  47.585 79.248 48.125 79.8 ;
     RECT  48.125 79.248 48.179 79.272 ;
     RECT  48.085 4.512 48.229 4.536 ;
     RECT  46.793 5.52 48.229 14.664 ;
     RECT  48.229 4.512 48.265 14.664 ;
     RECT  47.941 15.696 48.265 38.28 ;
     RECT  48.121 39.264 48.305 47.688 ;
     RECT  47.369 59.04 48.341 61.368 ;
     RECT  48.121 2.928 48.449 3.048 ;
     RECT  48.085 49.344 48.485 55.416 ;
     RECT  48.017 66.48 48.508 76.536 ;
     RECT  47.557 0.576 48.521 0.6 ;
     RECT  48.305 42.576 48.557 47.688 ;
     RECT  48.373 78.048 48.581 78.072 ;
     RECT  48.449 3.024 48.593 3.048 ;
     RECT  48.341 59.04 48.593 61.32 ;
     RECT  46.397 65.232 48.625 65.256 ;
     RECT  48.508 68.976 48.629 76.536 ;
     RECT  48.265 4.512 48.733 38.28 ;
     RECT  48.305 39.264 48.733 41.544 ;
     RECT  48.625 64.992 48.733 65.256 ;
     RECT  48.668 1.104 48.755 1.128 ;
     RECT  48.733 4.512 48.809 41.544 ;
     RECT  48.581 78 48.809 78.072 ;
     RECT  48.812 77.52 48.899 77.544 ;
     RECT  48.593 60.096 48.953 61.32 ;
     RECT  48.017 56.736 48.985 57.912 ;
     RECT  48.629 68.976 49.061 76.392 ;
     RECT  48.953 60.096 49.097 61.224 ;
     RECT  49.061 71.136 49.205 76.392 ;
     RECT  48.733 64.416 49.237 65.256 ;
     RECT  48.508 66.48 49.237 67.992 ;
     RECT  49.237 64.416 49.241 67.992 ;
     RECT  48.941 0.096 49.277 0.12 ;
     RECT  48.557 42.576 49.349 47.544 ;
     RECT  49.045 77.472 49.385 77.496 ;
     RECT  49.241 64.944 49.493 67.992 ;
     RECT  49.381 1.728 49.601 1.752 ;
     RECT  48.985 56.496 49.619 57.912 ;
     RECT  49.525 48.72 49.633 48.744 ;
     RECT  48.485 49.728 49.633 55.416 ;
     RECT  49.493 66.48 49.633 67.992 ;
     RECT  49.061 68.976 49.633 70.152 ;
     RECT  49.621 2.88 49.745 2.904 ;
     RECT  49.619 56.592 49.813 57.912 ;
     RECT  48.593 59.04 49.813 59.064 ;
     RECT  49.097 60.096 49.813 60.984 ;
     RECT  49.205 71.424 49.889 76.392 ;
     RECT  48.809 4.512 49.921 19.416 ;
     RECT  49.777 62.784 49.921 62.808 ;
     RECT  49.921 3.936 49.957 19.416 ;
     RECT  48.809 20.592 49.957 41.544 ;
     RECT  49.633 48.72 50.173 55.416 ;
     RECT  49.633 66.48 50.317 70.152 ;
     RECT  49.889 71.424 50.317 76.248 ;
     RECT  50.245 77.52 50.437 77.544 ;
     RECT  49.813 56.592 50.461 60.984 ;
     RECT  49.921 62.688 50.497 62.808 ;
     RECT  49.957 3.936 50.569 41.544 ;
     RECT  49.349 42.576 50.569 45.288 ;
     RECT  50.497 62.688 50.569 63.576 ;
     RECT  50.317 66.48 50.569 76.248 ;
     RECT  50.569 3.936 50.677 45.288 ;
     RECT  50.569 66.384 50.677 76.248 ;
     RECT  49.493 64.944 50.741 65.256 ;
     RECT  50.677 66.24 50.741 76.248 ;
     RECT  49.861 2.256 50.773 2.328 ;
     RECT  50.677 3.84 50.773 45.288 ;
     RECT  50.437 77.472 50.821 77.544 ;
     RECT  50.917 79.776 51.005 79.8 ;
     RECT  50.773 2.256 51.008 45.288 ;
     RECT  49.349 46.272 51.008 47.544 ;
     RECT  50.173 48.672 51.008 55.416 ;
     RECT  50.461 56.592 51.008 61.224 ;
     RECT  50.569 62.688 51.008 63.624 ;
     RECT  50.741 64.944 51.008 76.248 ;
     RECT  50.821 77.472 51.008 77.88 ;
     RECT  51.008 2.148 51.145 77.88 ;
     RECT  51.145 1.776 51.304 77.88 ;
     RECT  51.304 77.52 51.397 77.88 ;
     RECT  51.304 3.36 51.473 45.288 ;
     RECT  51.397 77.52 51.829 78.072 ;
     RECT  51.473 3.936 51.905 37.944 ;
     RECT  50.341 0.096 52.124 0.12 ;
     RECT  52.069 79.776 52.157 79.8 ;
     RECT  52.124 0.096 52.211 0.552 ;
     RECT  51.304 59.808 52.265 60.936 ;
     RECT  51.304 64.896 52.268 69.576 ;
     RECT  51.304 70.608 52.268 76.248 ;
     RECT  51.304 57.12 52.297 57.96 ;
     RECT  51.304 63.36 52.297 63.672 ;
     RECT  52.268 64.896 52.297 76.248 ;
     RECT  51.829 77.52 52.301 78.12 ;
     RECT  52.265 60.096 52.333 60.936 ;
     RECT  52.297 63.36 52.355 76.248 ;
     RECT  52.355 63.36 52.364 70.056 ;
     RECT  52.364 63.216 52.451 70.056 ;
     RECT  51.304 48.672 52.477 56.088 ;
     RECT  52.297 57.12 52.477 58.104 ;
     RECT  52.477 48.672 52.501 58.104 ;
     RECT  52.508 79.248 52.595 79.272 ;
     RECT  51.473 39.216 52.604 45.288 ;
     RECT  51.304 46.56 52.652 47.448 ;
     RECT  52.501 48.432 52.652 58.104 ;
     RECT  52.604 39.216 52.691 45.528 ;
     RECT  52.355 71.424 52.697 76.248 ;
     RECT  52.691 39.216 52.787 45.48 ;
     RECT  51.733 1.728 52.801 1.752 ;
     RECT  52.333 60.096 52.805 61.704 ;
     RECT  52.801 1.728 52.913 2.28 ;
     RECT  52.913 2.256 52.931 2.28 ;
     RECT  52.652 46.56 52.981 58.104 ;
     RECT  51.905 3.936 53.129 37.848 ;
     RECT  52.981 46.56 53.129 58.152 ;
     RECT  53.129 46.56 53.165 55.8 ;
     RECT  53.129 37.44 53.197 37.848 ;
     RECT  53.129 56.928 53.233 58.152 ;
     RECT  53.129 3.936 53.309 35.976 ;
     RECT  53.309 3.936 53.317 35.784 ;
     RECT  53.197 37.44 53.317 38.04 ;
     RECT  52.787 39.216 53.317 45.288 ;
     RECT  52.451 63.36 53.345 70.056 ;
     RECT  52.697 71.424 53.345 76.056 ;
     RECT  52.301 77.52 53.345 78.072 ;
     RECT  53.317 37.44 53.489 45.288 ;
     RECT  53.345 64.896 53.516 70.056 ;
     RECT  53.345 71.424 53.516 75.72 ;
     RECT  53.317 3.696 53.593 35.784 ;
     RECT  53.593 3.6 53.605 35.784 ;
     RECT  52.805 60.096 53.653 60.984 ;
     RECT  53.345 63.36 53.665 63.768 ;
     RECT  53.516 64.896 53.669 75.72 ;
     RECT  53.489 38.784 53.699 45.288 ;
     RECT  52.211 0.096 53.849 0.12 ;
     RECT  52.741 79.2 53.849 79.224 ;
     RECT  53.605 2.88 53.921 35.784 ;
     RECT  53.233 56.928 53.989 58.92 ;
     RECT  53.653 60.048 53.989 60.984 ;
     RECT  53.165 48.336 53.993 55.8 ;
     RECT  53.989 56.928 54.029 60.984 ;
     RECT  53.921 3.264 54.083 35.784 ;
     RECT  54.083 3.264 54.131 33.624 ;
     RECT  53.669 64.944 54.131 75.72 ;
     RECT  53.345 78.048 54.133 78.072 ;
     RECT  53.665 62.688 54.14 63.768 ;
     RECT  54.133 78.048 54.217 78.648 ;
     RECT  54.14 62.016 54.227 63.768 ;
     RECT  53.993 48.672 54.349 55.8 ;
     RECT  54.029 56.928 54.349 58.152 ;
     RECT  54.083 34.752 54.421 35.784 ;
     RECT  53.489 37.44 54.421 37.464 ;
     RECT  53.699 39.456 54.421 45.288 ;
     RECT  54.421 39.456 54.457 45.576 ;
     RECT  53.165 46.56 54.457 47.352 ;
     RECT  54.227 62.256 54.493 63.768 ;
     RECT  54.131 69.552 54.605 75.72 ;
     RECT  54.605 70.512 54.641 75.72 ;
     RECT  54.493 62.256 54.661 63.816 ;
     RECT  54.131 64.944 54.661 68.424 ;
     RECT  54.421 34.752 54.707 37.464 ;
     RECT  54.517 1.728 54.713 1.752 ;
     RECT  54.707 37.44 54.745 37.464 ;
     RECT  54.661 62.256 54.748 68.424 ;
     RECT  54.641 71.328 54.817 75.72 ;
     RECT  54.131 3.264 54.821 33.336 ;
     RECT  54.748 62.256 54.821 63.816 ;
     RECT  54.217 78.048 54.853 78.072 ;
     RECT  54.748 64.944 54.893 68.424 ;
     RECT  54.349 48.672 54.899 58.152 ;
     RECT  54.757 1.776 54.929 1.8 ;
     RECT  54.893 65.52 55.037 68.424 ;
     RECT  54.817 71.328 55.045 76.296 ;
     RECT  54.853 77.52 55.045 78.072 ;
     RECT  54.457 39.456 55.052 47.352 ;
     RECT  54.745 37.44 55.141 38.328 ;
     RECT  55.052 39.456 55.141 47.544 ;
     RECT  54.029 59.808 55.141 60.936 ;
     RECT  54.997 0.576 55.189 0.6 ;
     RECT  54.707 34.752 55.213 35.88 ;
     RECT  55.141 59.808 55.213 61.128 ;
     RECT  55.045 71.328 55.253 78.072 ;
     RECT  55.213 59.808 55.321 61.992 ;
     RECT  55.141 37.44 55.465 47.544 ;
     RECT  54.899 48.672 55.465 57.72 ;
     RECT  54.821 3.36 55.765 33.336 ;
     RECT  55.213 34.704 55.861 35.88 ;
     RECT  55.321 59.232 55.861 61.992 ;
     RECT  54.821 63.024 55.861 63.816 ;
     RECT  55.037 65.52 55.861 67.992 ;
     RECT  55.253 71.328 55.897 76.968 ;
     RECT  55.861 34.704 55.957 36.456 ;
     RECT  55.465 37.44 55.957 57.72 ;
     RECT  55.765 3.36 56.041 33.624 ;
     RECT  55.957 34.704 56.041 57.72 ;
     RECT  55.189 0.096 56.045 0.6 ;
     RECT  55.897 70.896 56.185 76.968 ;
     RECT  55.861 64.896 56.197 67.992 ;
     RECT  55.861 59.232 56.257 63.816 ;
     RECT  56.197 64.896 56.257 68.952 ;
     RECT  56.113 2.304 56.408 2.328 ;
     RECT  56.041 3.36 56.408 57.72 ;
     RECT  56.257 59.232 56.408 68.952 ;
     RECT  56.185 70.128 56.408 76.968 ;
     RECT  55.253 78.048 56.408 78.072 ;
     RECT  56.045 0.096 56.435 0.12 ;
     RECT  56.408 2.148 56.512 78.072 ;
     RECT  56.54 1.104 56.627 1.128 ;
     RECT  56.005 79.2 56.677 79.224 ;
     RECT  56.512 2.148 56.704 77.502 ;
     RECT  56.677 78.624 56.765 79.224 ;
     RECT  56.704 2.148 56.797 12.264 ;
     RECT  56.704 63.168 56.981 76.344 ;
     RECT  56.765 79.2 57.449 79.224 ;
     RECT  57.337 0.528 57.589 0.552 ;
     RECT  57.589 0.336 57.625 0.552 ;
     RECT  56.797 1.728 57.625 12.264 ;
     RECT  57.625 0.336 57.73 12.264 ;
     RECT  57.73 0.336 57.805 12.312 ;
     RECT  56.704 13.44 57.805 61.992 ;
     RECT  57.805 0.336 57.941 61.992 ;
     RECT  56.981 63.168 58.093 75.624 ;
     RECT  58.069 76.704 58.093 76.728 ;
     RECT  57.941 0.096 58.165 61.992 ;
     RECT  58.093 63.168 58.165 76.728 ;
     RECT  58.165 0.096 58.405 76.728 ;
     RECT  58.405 0.048 58.673 76.728 ;
     RECT  57.797 79.248 58.733 79.8 ;
     RECT  58.673 36.864 58.885 76.728 ;
     RECT  58.885 36.864 58.979 77.544 ;
     RECT  58.733 79.2 59.033 79.8 ;
     RECT  58.673 0.048 59.249 35.88 ;
     RECT  58.979 76.896 59.267 77.544 ;
     RECT  58.979 36.864 59.357 75.864 ;
     RECT  59.033 79.2 59.461 79.272 ;
     RECT  59.461 78.624 59.545 79.272 ;
     RECT  59.249 2.208 59.785 35.88 ;
     RECT  59.357 36.864 59.785 58.92 ;
     RECT  59.785 2.208 59.891 58.92 ;
     RECT  59.267 76.896 59.933 76.92 ;
     RECT  59.545 79.248 59.939 79.272 ;
     RECT  59.357 60.048 60.253 75.864 ;
     RECT  59.641 78.096 60.253 78.12 ;
     RECT  59.249 0.048 60.275 0.84 ;
     RECT  59.891 2.208 60.293 15.48 ;
     RECT  60.275 0.144 60.371 0.84 ;
     RECT  60.253 60.048 60.397 75.912 ;
     RECT  60.253 77.856 60.419 78.12 ;
     RECT  59.891 16.8 60.613 58.92 ;
     RECT  60.397 60.048 60.613 76.344 ;
     RECT  60.517 79.776 60.659 79.8 ;
     RECT  60.371 0.24 60.685 0.84 ;
     RECT  60.419 78.048 60.685 78.12 ;
     RECT  60.685 0.24 60.709 1.128 ;
     RECT  60.293 2.208 60.709 14.424 ;
     RECT  60.293 15.408 60.908 15.48 ;
     RECT  60.613 16.8 60.908 76.344 ;
     RECT  60.908 15.408 60.973 76.344 ;
     RECT  60.685 78.048 61.091 78.696 ;
     RECT  60.973 15.408 61.153 76.776 ;
     RECT  60.709 0.24 61.405 14.424 ;
     RECT  61.153 15.408 61.405 76.872 ;
     RECT  61.405 0.24 61.621 76.872 ;
     RECT  61.585 77.856 61.621 77.88 ;
     RECT  61.621 0.24 62.104 77.88 ;
     RECT  62.104 0.24 62.165 22.824 ;
     RECT  62.165 0.24 62.237 22.728 ;
     RECT  62.104 23.856 62.273 77.88 ;
     RECT  62.237 0.24 62.377 18.456 ;
     RECT  62.377 0.096 62.461 18.456 ;
     RECT  62.273 56.544 62.483 77.88 ;
     RECT  62.237 19.776 62.597 22.728 ;
     RECT  62.597 19.776 62.633 19.8 ;
     RECT  62.273 23.856 62.675 55.272 ;
     RECT  62.677 78.576 62.819 78.696 ;
     RECT  62.819 78.576 62.867 78.6 ;
     RECT  62.483 56.544 63.011 77.544 ;
     RECT  62.597 20.832 63.065 22.728 ;
     RECT  62.461 0.24 63.445 18.456 ;
     RECT  63.011 77.52 63.461 77.544 ;
     RECT  62.675 24.816 63.569 55.272 ;
     RECT  63.065 20.832 63.601 21.192 ;
     RECT  63.569 38.448 63.605 55.272 ;
     RECT  61.669 79.776 63.635 79.8 ;
     RECT  63.169 23.76 63.673 23.784 ;
     RECT  63.569 24.816 63.673 37.464 ;
     RECT  63.445 0.144 63.685 18.456 ;
     RECT  63.605 38.544 63.817 55.272 ;
     RECT  63.011 56.544 63.817 76.392 ;
     RECT  63.685 0.096 63.827 18.456 ;
     RECT  63.817 38.544 63.857 76.392 ;
     RECT  63.065 22.176 63.925 22.728 ;
     RECT  63.673 23.76 63.925 37.464 ;
     RECT  63.827 0.144 63.997 18.456 ;
     RECT  63.601 19.968 64.105 21.192 ;
     RECT  63.925 22.176 64.105 37.464 ;
     RECT  63.857 39.792 64.109 76.392 ;
     RECT  64.109 48.912 64.211 76.392 ;
     RECT  64.211 56.688 64.217 76.392 ;
     RECT  63.997 0.144 64.393 18.888 ;
     RECT  64.105 19.968 64.393 37.464 ;
     RECT  64.393 0.144 64.433 37.464 ;
     RECT  64.217 56.688 64.433 76.104 ;
     RECT  64.109 39.792 64.469 47.928 ;
     RECT  64.211 48.912 64.577 55.224 ;
     RECT  64.433 56.688 64.577 58.536 ;
     RECT  64.577 48.912 64.613 51.096 ;
     RECT  64.469 39.84 64.685 47.928 ;
     RECT  64.613 48.912 64.721 50.808 ;
     RECT  64.685 39.84 64.757 46.872 ;
     RECT  64.577 56.688 64.757 58.104 ;
     RECT  63.857 38.544 64.793 38.808 ;
     RECT  64.577 52.416 64.793 55.224 ;
     RECT  64.897 77.088 64.933 77.16 ;
     RECT  64.721 48.912 64.937 50.568 ;
     RECT  64.793 38.544 65.009 38.712 ;
     RECT  64.757 45.408 65.009 46.872 ;
     RECT  64.937 48.912 65.045 49.08 ;
     RECT  64.685 47.904 65.053 47.928 ;
     RECT  64.793 52.416 65.075 54.696 ;
     RECT  64.741 79.776 65.077 79.8 ;
     RECT  64.757 39.84 65.081 43.848 ;
     RECT  65.045 48.96 65.081 49.08 ;
     RECT  65.081 39.84 65.117 42.552 ;
     RECT  64.433 59.712 65.153 63.336 ;
     RECT  65.009 38.688 65.225 38.712 ;
     RECT  65.117 40.56 65.225 41.688 ;
     RECT  64.433 64.32 65.293 76.104 ;
     RECT  64.933 77.088 65.293 77.544 ;
     RECT  64.433 0.144 65.297 37.32 ;
     RECT  65.225 40.56 65.297 41.112 ;
     RECT  64.937 50.256 65.297 50.568 ;
     RECT  65.075 53.232 65.297 54.696 ;
     RECT  64.757 58.08 65.405 58.104 ;
     RECT  65.297 53.952 65.441 54.696 ;
     RECT  65.077 79.728 65.441 79.8 ;
     RECT  65.441 79.728 65.507 79.752 ;
     RECT  65.153 59.712 65.513 61.272 ;
     RECT  65.293 64.32 65.513 77.544 ;
     RECT  65.513 66.768 65.545 77.544 ;
     RECT  65.297 40.608 65.585 41.112 ;
     RECT  65.513 64.32 65.585 65.208 ;
     RECT  65.297 19.68 65.621 37.32 ;
     RECT  65.009 45.456 65.653 46.872 ;
     RECT  65.585 64.752 65.693 65.208 ;
     RECT  65.653 45.456 65.729 47.304 ;
     RECT  65.513 59.712 65.729 59.928 ;
     RECT  65.693 64.752 65.801 64.776 ;
     RECT  65.545 66.768 65.833 78.312 ;
     RECT  65.297 0.144 65.869 18.456 ;
     RECT  64.757 56.688 65.905 56.856 ;
     RECT  65.621 19.68 65.909 28.92 ;
     RECT  65.081 43.776 65.909 43.848 ;
     RECT  65.909 19.68 65.945 27.384 ;
     RECT  65.869 0.096 65.953 18.456 ;
     RECT  65.909 28.368 66.017 28.92 ;
     RECT  65.297 50.352 66.017 50.376 ;
     RECT  65.905 56.688 66.017 57.192 ;
     RECT  65.953 0.192 66.053 18.456 ;
     RECT  65.621 30.048 66.053 37.32 ;
     RECT  65.153 62.736 66.053 63.336 ;
     RECT  65.833 39.168 66.085 39.192 ;
     RECT  66.053 0.192 66.131 18.216 ;
     RECT  66.017 56.688 66.157 57.096 ;
     RECT  65.945 19.68 66.161 21.96 ;
     RECT  66.053 30.048 66.161 31.8 ;
     RECT  66.161 30.432 66.197 31.8 ;
     RECT  65.833 66.768 66.229 78.648 ;
     RECT  66.053 32.88 66.233 37.32 ;
     RECT  65.945 22.992 66.269 27.384 ;
     RECT  66.157 55.728 66.269 57.096 ;
     RECT  65.513 61.248 66.301 61.272 ;
     RECT  66.229 66.768 66.301 78.696 ;
     RECT  66.197 30.432 66.305 31.512 ;
     RECT  65.729 46.416 66.373 47.304 ;
     RECT  66.085 39.168 66.409 39.48 ;
     RECT  66.301 66.768 66.419 79.272 ;
     RECT  66.193 45.216 66.517 45.24 ;
     RECT  66.131 0.192 66.611 2.52 ;
     RECT  66.517 44.352 66.629 45.24 ;
     RECT  65.585 40.608 66.697 40.632 ;
     RECT  65.441 54.672 66.697 54.696 ;
     RECT  66.233 34.176 66.733 37.32 ;
     RECT  65.081 48.96 66.733 48.984 ;
     RECT  65.729 59.904 66.733 59.928 ;
     RECT  66.301 61.248 66.733 61.368 ;
     RECT  66.053 63.216 66.769 63.336 ;
     RECT  66.419 66.768 66.773 79.224 ;
     RECT  66.269 23.328 67.201 27.384 ;
     RECT  66.017 28.368 67.201 28.632 ;
     RECT  66.131 3.744 67.237 18.216 ;
     RECT  66.161 19.68 67.237 21.864 ;
     RECT  66.733 34.176 67.237 37.464 ;
     RECT  66.373 46.416 67.237 47.448 ;
     RECT  66.697 54.24 67.237 54.696 ;
     RECT  66.269 56.064 67.237 57.096 ;
     RECT  66.733 59.904 67.237 61.368 ;
     RECT  66.769 63.216 67.237 63.912 ;
     RECT  67.237 3.744 67.273 21.864 ;
     RECT  67.201 23.328 67.273 28.632 ;
     RECT  67.237 32.496 67.273 37.464 ;
     RECT  66.409 39.024 67.273 39.48 ;
     RECT  66.697 40.464 67.273 41.304 ;
     RECT  66.697 42.432 67.273 42.456 ;
     RECT  66.629 44.592 67.273 45.24 ;
     RECT  67.237 46.416 67.273 47.592 ;
     RECT  66.733 48.96 67.273 49.56 ;
     RECT  66.697 50.976 67.273 51 ;
     RECT  67.237 58.8 67.273 61.368 ;
     RECT  66.611 0.24 67.331 2.52 ;
     RECT  66.773 75.168 67.517 79.224 ;
     RECT  67.331 0.384 67.571 2.52 ;
     RECT  67.571 1.056 67.597 2.52 ;
     RECT  67.273 3.744 67.597 28.824 ;
     RECT  67.273 65.616 67.633 65.64 ;
     RECT  66.773 66.768 67.633 73.608 ;
     RECT  67.237 54.24 67.669 57.096 ;
     RECT  67.273 50.688 67.705 51 ;
     RECT  67.237 52.224 67.705 52.248 ;
     RECT  67.669 53.952 67.705 57.096 ;
     RECT  67.273 58.8 67.705 61.8 ;
     RECT  67.273 32.496 67.741 41.448 ;
     RECT  67.273 42.432 67.741 43.608 ;
     RECT  67.273 44.592 67.741 49.56 ;
     RECT  67.705 50.688 67.741 52.248 ;
     RECT  67.705 53.808 67.741 61.8 ;
     RECT  67.633 65.616 67.741 73.608 ;
     RECT  66.305 31.2 67.777 31.512 ;
     RECT  67.741 32.496 67.777 52.248 ;
     RECT  67.741 53.664 67.777 61.8 ;
     RECT  67.237 62.928 67.777 63.912 ;
     RECT  67.741 65.184 67.777 73.608 ;
     RECT  67.517 75.168 67.777 79.8 ;
     RECT  67.597 1.056 67.813 28.824 ;
     RECT  67.777 31.056 67.813 73.608 ;
     RECT  67.813 31.056 67.849 73.896 ;
     RECT  67.777 75.12 67.849 79.8 ;
     RECT  67.813 1.056 67.885 29.4 ;
     RECT  67.849 31.056 68.069 79.8 ;
     RECT  67.885 1.056 68.317 29.64 ;
     RECT  68.317 1.056 68.389 30.072 ;
     RECT  68.069 31.056 68.389 78.84 ;
     RECT  68.389 1.056 69.084 78.84 ;
     RECT  69.084 14.496 69.113 14.52 ;
    LAYER M5 ;
     RECT  1.104 0.016 68.04 0.563 ;
     RECT  3.408 0.563 68.04 0.611 ;
     RECT  21.552 0.611 68.04 1.139 ;
     RECT  21.552 1.139 48.264 1.187 ;
     RECT  3.408 0.611 20.424 1.763 ;
     RECT  21.552 1.187 27.144 1.763 ;
     RECT  28.272 1.187 48.264 1.763 ;
     RECT  49.392 1.139 57.336 1.763 ;
     RECT  3.408 1.763 14.616 1.811 ;
     RECT  21.984 1.763 26.664 1.811 ;
     RECT  49.632 1.763 57.336 1.811 ;
     RECT  1.104 0.563 2.28 2.137 ;
     RECT  3.408 1.811 10.488 2.137 ;
     RECT  58.416 1.139 61.752 2.137 ;
     RECT  62.784 1.139 68.04 2.137 ;
     RECT  55.344 1.811 57.336 2.197 ;
     RECT  58.416 2.137 68.04 2.197 ;
     RECT  21.984 1.811 22.728 2.291 ;
     RECT  23.856 1.811 26.424 2.291 ;
     RECT  28.272 1.763 46.632 2.291 ;
     RECT  49.632 1.811 54.312 2.291 ;
     RECT  34.32 2.291 36.648 2.339 ;
     RECT  49.632 2.291 52.008 2.339 ;
     RECT  1.104 2.137 10.488 2.725 ;
     RECT  28.272 2.291 32.712 2.867 ;
     RECT  11.808 1.811 14.616 2.915 ;
     RECT  39.408 2.291 46.632 2.915 ;
     RECT  49.632 2.339 49.656 2.915 ;
     RECT  39.408 2.915 42.024 2.963 ;
     RECT  17.616 1.763 20.424 3.061 ;
     RECT  17.616 3.061 20.616 3.109 ;
     RECT  26.688 2.869 26.712 3.203 ;
     RECT  17.424 3.109 20.616 3.251 ;
     RECT  29.28 2.867 32.712 3.443 ;
     RECT  34.32 2.339 35.736 3.443 ;
     RECT  39.408 2.963 40.512 3.443 ;
     RECT  41.76 2.963 42.024 3.443 ;
     RECT  18.048 3.251 20.616 3.491 ;
     RECT  23.856 2.291 25.272 3.491 ;
     RECT  21.984 2.291 22.248 3.541 ;
     RECT  53.376 2.291 54.312 3.685 ;
     RECT  50.784 2.339 52.008 3.829 ;
     RECT  0.144 2.725 10.488 3.877 ;
     RECT  11.808 2.915 11.832 3.877 ;
     RECT  21.984 3.541 22.344 3.925 ;
     RECT  23.856 3.491 24.888 3.925 ;
     RECT  50.688 3.829 52.008 3.925 ;
     RECT  53.328 3.685 54.312 3.925 ;
     RECT  13.008 2.915 14.616 3.971 ;
     RECT  21.984 3.925 24.888 3.971 ;
     RECT  49.968 3.925 54.312 4.453 ;
     RECT  55.344 2.197 68.04 4.453 ;
     RECT  41.76 3.443 41.784 4.501 ;
     RECT  43.824 2.915 43.848 4.501 ;
     RECT  48.24 1.763 48.264 4.501 ;
     RECT  49.968 4.453 68.04 4.501 ;
     RECT  0.144 3.877 11.832 4.595 ;
     RECT  13.2 3.971 14.616 4.595 ;
     RECT  16.224 1.763 16.248 4.595 ;
     RECT  18.048 3.491 19.704 4.595 ;
     RECT  28.272 2.867 28.296 4.595 ;
     RECT  30.72 3.443 32.712 4.595 ;
     RECT  40.08 3.443 40.512 4.595 ;
     RECT  45.216 2.915 46.632 4.595 ;
     RECT  31.536 4.595 32.712 4.643 ;
     RECT  32.688 4.643 32.712 4.691 ;
     RECT  21.984 3.971 24.312 5.027 ;
     RECT  25.632 4.693 25.656 5.027 ;
     RECT  45.456 4.595 46.632 5.075 ;
     RECT  1.344 4.595 11.832 5.171 ;
     RECT  31.536 4.643 31.56 5.171 ;
     RECT  34.32 3.443 35.304 5.171 ;
     RECT  45.6 5.075 46.632 5.461 ;
     RECT  29.4 3.443 29.712 5.509 ;
     RECT  38.064 4.501 38.088 5.509 ;
     RECT  45.6 5.461 46.728 5.557 ;
     RECT  48.096 4.501 68.04 5.557 ;
     RECT  43.632 4.501 43.848 5.605 ;
     RECT  29.4 5.509 30.408 5.653 ;
     RECT  21.984 5.027 22.008 5.795 ;
     RECT  13.2 4.595 13.512 5.845 ;
     RECT  0.144 4.595 0.168 5.939 ;
     RECT  26.976 3.925 27 5.989 ;
     RECT  26.4 5.989 27 6.035 ;
     RECT  1.344 5.171 11.688 6.229 ;
     RECT  1.344 6.229 11.832 6.323 ;
     RECT  1.344 6.323 10.824 6.371 ;
     RECT  37.584 5.509 38.088 6.371 ;
     RECT  34.8 5.171 35.112 6.661 ;
     RECT  29.28 5.653 30.408 6.803 ;
     RECT  45.6 5.557 68.04 6.853 ;
     RECT  29.28 6.803 29.712 7.187 ;
     RECT  34.8 6.661 35.496 7.189 ;
     RECT  43.632 5.605 44.472 7.331 ;
     RECT  26.4 6.035 26.424 7.333 ;
     RECT  1.344 6.371 10.68 7.381 ;
     RECT  11.808 6.323 11.832 7.381 ;
     RECT  43.632 7.331 43.656 7.429 ;
     RECT  1.344 7.381 11.832 7.475 ;
     RECT  32.112 6.181 32.136 7.523 ;
     RECT  45.504 6.853 68.04 7.667 ;
     RECT  17.28 7.525 17.304 7.909 ;
     RECT  1.824 7.475 11.832 7.957 ;
     RECT  13.2 5.845 13.944 7.957 ;
     RECT  26.064 7.333 26.424 8.005 ;
     RECT  40.2 4.595 40.512 8.149 ;
     RECT  23.088 5.027 24.312 8.197 ;
     RECT  17.04 7.909 17.304 8.339 ;
     RECT  17.28 8.339 17.304 8.435 ;
     RECT  18.6 4.595 19.56 8.437 ;
     RECT  29.4 7.187 29.712 8.437 ;
     RECT  34.8 7.189 36.216 8.483 ;
     RECT  23.088 8.197 24.408 8.579 ;
     RECT  21.12 7.381 21.144 8.675 ;
     RECT  39.84 8.149 40.512 8.675 ;
     RECT  25.872 8.005 26.424 9.011 ;
     RECT  34.8 8.483 35.496 9.301 ;
     RECT  25.872 9.011 26.232 9.587 ;
     RECT  29.4 8.437 30.216 9.587 ;
     RECT  45.6 7.667 68.04 9.587 ;
     RECT  0.144 8.485 0.168 9.683 ;
     RECT  34.368 9.301 35.496 10.165 ;
     RECT  17.472 9.061 17.496 10.307 ;
     RECT  1.824 7.957 13.944 10.355 ;
     RECT  26.064 9.587 26.232 10.355 ;
     RECT  29.4 9.587 29.832 10.835 ;
     RECT  67.776 9.587 68.04 10.835 ;
     RECT  2.016 10.355 13.944 10.883 ;
     RECT  2.016 10.883 10.2 10.931 ;
     RECT  2.256 10.931 10.2 10.979 ;
     RECT  11.472 10.883 13.944 11.173 ;
     RECT  45.6 9.587 65.88 11.173 ;
     RECT  34.368 10.165 35.688 11.221 ;
     RECT  36.864 9.013 36.888 11.221 ;
     RECT  45.024 11.173 65.88 11.315 ;
     RECT  68.928 10.885 68.952 11.315 ;
     RECT  11.472 11.173 13.992 11.365 ;
     RECT  26.208 10.355 26.232 11.365 ;
     RECT  26.208 11.365 26.76 11.411 ;
     RECT  43.584 7.429 43.656 11.461 ;
     RECT  20.928 11.317 20.952 11.653 ;
     RECT  41.76 4.501 42.456 11.653 ;
     RECT  43.584 11.461 43.896 11.653 ;
     RECT  45.6 11.315 65.88 11.653 ;
     RECT  34.368 11.221 36.888 11.701 ;
     RECT  38.064 6.371 38.088 11.701 ;
     RECT  40.2 8.675 40.512 11.749 ;
     RECT  41.76 11.653 43.896 11.749 ;
     RECT  40.2 11.749 43.896 11.795 ;
     RECT  45.6 11.653 66.696 11.891 ;
     RECT  26.736 11.411 26.76 11.987 ;
     RECT  34.368 11.701 38.088 12.083 ;
     RECT  40.2 11.795 42.456 12.083 ;
     RECT  11.472 11.365 14.088 12.227 ;
     RECT  32.016 9.109 32.04 12.227 ;
     RECT  15.6 11.653 15.624 12.275 ;
     RECT  11.712 12.227 14.088 12.373 ;
     RECT  2.4 10.979 9.912 12.469 ;
     RECT  33.312 9.061 33.336 12.517 ;
     RECT  20.928 11.653 21.096 13.045 ;
     RECT  32.688 12.517 33.336 13.141 ;
     RECT  45.6 11.891 65.88 13.187 ;
     RECT  32.688 13.141 33.48 13.235 ;
     RECT  2.4 12.469 10.104 13.573 ;
     RECT  52.368 13.187 65.88 13.763 ;
     RECT  15.84 12.373 15.864 13.909 ;
     RECT  11.712 12.373 14.52 14.197 ;
     RECT  15.84 13.909 15.912 14.197 ;
     RECT  40.2 12.083 40.728 14.197 ;
     RECT  20.928 13.045 21.912 14.387 ;
     RECT  23.088 8.579 24.312 14.435 ;
     RECT  45.6 13.187 51.312 14.437 ;
     RECT  52.368 13.763 65.688 14.437 ;
     RECT  2.4 13.573 10.248 14.485 ;
     RECT  17.04 12.229 17.064 14.773 ;
     RECT  33.456 13.235 33.48 14.773 ;
     RECT  34.8 12.083 38.088 14.963 ;
     RECT  40.08 14.197 40.728 15.061 ;
     RECT  41.76 12.083 42.456 15.061 ;
     RECT  11.52 14.197 15.912 15.109 ;
     RECT  40.08 15.061 42.456 15.395 ;
     RECT  11.424 15.109 15.912 15.443 ;
     RECT  17.04 14.773 17.304 15.443 ;
     RECT  37.632 14.963 38.088 15.443 ;
     RECT  38.064 15.443 38.088 15.493 ;
     RECT  29.4 10.835 29.712 15.685 ;
     RECT  45.6 14.437 65.688 15.731 ;
     RECT  2.4 14.485 10.392 15.829 ;
     RECT  11.424 15.443 14.52 15.829 ;
     RECT  28.848 15.685 29.712 15.923 ;
     RECT  46.992 15.731 65.688 15.923 ;
     RECT  45.6 15.731 46.008 15.925 ;
     RECT  67.776 10.835 67.8 15.971 ;
     RECT  52.368 15.923 65.688 16.019 ;
     RECT  2.4 15.829 14.52 16.259 ;
     RECT  27.792 15.061 27.816 16.259 ;
     RECT  20.928 14.387 21.672 16.357 ;
     RECT  20.928 16.357 22.536 16.403 ;
     RECT  34.8 14.963 36.456 16.501 ;
     RECT  38.064 15.493 39 16.547 ;
     RECT  2.4 16.259 3.432 16.595 ;
     RECT  32.496 14.773 33.48 16.787 ;
     RECT  17.04 15.443 17.064 16.837 ;
     RECT  18.48 8.437 19.56 16.837 ;
     RECT  29.4 15.923 29.712 16.981 ;
     RECT  26.208 16.501 26.232 17.029 ;
     RECT  34.8 16.501 36.504 17.029 ;
     RECT  45.216 15.925 46.008 17.029 ;
     RECT  0.144 15.013 0.168 17.075 ;
     RECT  15.84 15.443 15.912 17.077 ;
     RECT  17.04 16.837 19.56 17.077 ;
     RECT  30.96 16.501 30.984 17.077 ;
     RECT  15.84 17.077 19.56 17.123 ;
     RECT  28.992 16.981 29.712 17.123 ;
     RECT  32.64 16.787 33.48 17.219 ;
     RECT  44.832 17.029 46.008 17.219 ;
     RECT  52.368 16.019 65.064 17.219 ;
     RECT  30.96 17.077 31.416 17.363 ;
     RECT  34.8 17.029 36.6 17.365 ;
     RECT  38.064 16.547 38.088 17.365 ;
     RECT  25.728 17.029 26.232 17.459 ;
     RECT  4.608 16.259 14.52 17.509 ;
     RECT  0.24 17.077 0.264 17.557 ;
     RECT  4.608 17.509 14.808 17.605 ;
     RECT  0.24 17.557 0.552 17.699 ;
     RECT  4.464 17.605 14.808 17.699 ;
     RECT  32.64 17.219 32.664 17.699 ;
     RECT  2.4 16.595 2.712 18.181 ;
     RECT  34.8 17.365 38.088 18.515 ;
     RECT  24 14.435 24.312 18.709 ;
     RECT  2.4 18.181 2.808 18.757 ;
     RECT  11.712 17.699 14.808 18.803 ;
     RECT  24 18.709 24.504 18.949 ;
     RECT  45.072 17.219 46.008 18.997 ;
     RECT  37.584 18.515 38.088 19.043 ;
     RECT  23.808 18.949 24.504 19.091 ;
     RECT  2.4 18.757 3.432 19.189 ;
     RECT  4.464 17.699 10.488 19.189 ;
     RECT  0.144 18.229 0.168 19.333 ;
     RECT  46.992 15.923 51.312 19.333 ;
     RECT  52.368 17.219 63.96 19.333 ;
     RECT  24 19.091 24.504 19.379 ;
     RECT  15.84 17.123 16.536 19.427 ;
     RECT  17.664 17.123 19.56 19.427 ;
     RECT  0.144 19.333 0.216 19.475 ;
     RECT  32.448 18.373 32.472 19.573 ;
     RECT  31.968 19.573 32.472 19.619 ;
     RECT  29.4 17.123 29.712 19.813 ;
     RECT  18 19.427 19.56 19.861 ;
     RECT  20.928 16.403 20.952 19.861 ;
     RECT  25.728 17.459 25.752 20.003 ;
     RECT  22.512 16.403 22.536 20.147 ;
     RECT  40.2 15.395 42.456 20.389 ;
     RECT  38.064 19.043 38.088 20.485 ;
     RECT  0.144 19.475 0.168 20.531 ;
     RECT  18 19.861 20.952 20.579 ;
     RECT  46.992 19.333 63.96 20.579 ;
     RECT  15.84 19.427 15.912 20.725 ;
     RECT  28.848 19.813 29.712 20.819 ;
     RECT  44.832 18.997 46.008 20.821 ;
     RECT  46.992 20.579 51.312 20.821 ;
     RECT  27.552 20.005 27.576 21.107 ;
     RECT  40.2 20.389 42.552 21.107 ;
     RECT  2.4 19.189 10.488 21.203 ;
     RECT  44.832 20.821 51.312 21.203 ;
     RECT  31.968 19.619 31.992 21.299 ;
     RECT  37.632 20.485 38.088 21.395 ;
     RECT  15.84 20.725 16.776 21.541 ;
     RECT  41.76 21.107 42.552 21.685 ;
     RECT  43.584 11.795 43.656 21.685 ;
     RECT  3.792 21.203 10.488 21.925 ;
     RECT  15.696 21.541 16.776 22.019 ;
     RECT  2.4 21.203 2.808 22.165 ;
     RECT  3.792 21.925 10.68 22.165 ;
     RECT  34.8 18.515 36.6 22.357 ;
     RECT  41.76 21.685 43.656 22.451 ;
     RECT  44.832 21.203 45.912 22.451 ;
     RECT  40.2 21.107 40.512 22.453 ;
     RECT  18 20.579 19.56 22.499 ;
     RECT  34.8 22.357 36.984 22.597 ;
     RECT  20.928 20.579 20.952 22.741 ;
     RECT  24 19.379 24.312 22.741 ;
     RECT  38.064 21.395 38.088 22.741 ;
     RECT  33.888 22.597 36.984 22.789 ;
     RECT  38.064 22.741 38.28 22.789 ;
     RECT  0.24 22.549 0.264 22.885 ;
     RECT  33.888 22.789 38.28 22.885 ;
     RECT  39.744 22.453 40.512 22.885 ;
     RECT  33.888 22.885 40.512 22.981 ;
     RECT  41.76 22.451 42.456 22.981 ;
     RECT  23.184 22.741 24.312 23.077 ;
     RECT  18 22.499 19.032 23.171 ;
     RECT  11.712 18.803 14.52 23.269 ;
     RECT  15.696 22.019 16.392 23.269 ;
     RECT  11.712 23.269 16.392 23.315 ;
     RECT  29.4 20.819 29.712 23.317 ;
     RECT  33.888 22.981 42.456 23.411 ;
     RECT  2.4 22.165 10.68 23.555 ;
     RECT  34.8 23.411 42.456 23.555 ;
     RECT  0.144 22.885 0.264 23.603 ;
     RECT  37.776 23.555 42.456 23.651 ;
     RECT  40.2 23.651 42.456 23.653 ;
     RECT  43.584 22.451 43.656 23.653 ;
     RECT  0.192 23.603 0.264 23.699 ;
     RECT  40.2 23.653 43.656 23.795 ;
     RECT  20.928 22.741 21.384 23.939 ;
     RECT  0.24 23.699 0.264 23.987 ;
     RECT  46.992 21.203 51.312 23.989 ;
     RECT  52.368 20.579 63.96 23.989 ;
     RECT  25.44 23.173 25.464 24.131 ;
     RECT  37.776 23.651 38.856 24.323 ;
     RECT  23.088 23.077 24.312 24.373 ;
     RECT  29.232 23.317 29.712 24.469 ;
     RECT  34.8 23.555 36.6 24.469 ;
     RECT  11.712 23.315 16.296 24.563 ;
     RECT  40.2 23.795 42.456 24.563 ;
     RECT  40.2 24.563 40.632 24.613 ;
     RECT  31.92 23.125 31.944 24.661 ;
     RECT  23.088 24.373 24.408 24.755 ;
     RECT  23.376 24.755 24.408 24.805 ;
     RECT  15.696 24.563 16.296 24.853 ;
     RECT  18.192 23.171 19.032 24.899 ;
     RECT  41.76 24.563 42.456 24.901 ;
     RECT  43.584 23.795 43.656 24.901 ;
     RECT  46.992 23.989 63.96 24.949 ;
     RECT  65.04 17.219 65.064 24.949 ;
     RECT  15.696 24.853 16.44 24.995 ;
     RECT  3.84 23.555 10.68 25.093 ;
     RECT  11.712 24.563 14.52 25.093 ;
     RECT  34.032 24.469 36.6 25.189 ;
     RECT  34.032 25.189 36.84 25.427 ;
     RECT  31.728 24.661 31.944 25.475 ;
     RECT  29.088 24.469 29.712 25.523 ;
     RECT  2.4 23.555 2.856 25.715 ;
     RECT  41.76 24.901 43.656 25.715 ;
     RECT  43.584 25.715 43.656 25.717 ;
     RECT  34.032 25.427 36.6 25.763 ;
     RECT  38.064 24.323 38.856 25.813 ;
     RECT  39.888 24.613 40.632 25.813 ;
     RECT  20.928 23.939 20.952 26.053 ;
     RECT  31.104 25.573 31.128 26.243 ;
     RECT  38.064 25.813 40.632 26.243 ;
     RECT  23.376 24.805 24.456 26.245 ;
     RECT  3.84 25.093 14.52 26.291 ;
     RECT  34.032 25.763 36.312 26.291 ;
     RECT  38.064 26.243 38.856 26.291 ;
     RECT  39.936 26.243 40.632 26.341 ;
     RECT  41.76 25.715 42.456 26.341 ;
     RECT  23.376 26.245 25.176 26.387 ;
     RECT  27.792 26.197 27.816 26.677 ;
     RECT  15.696 24.995 16.248 26.725 ;
     RECT  3.888 26.291 14.52 26.819 ;
     RECT  20.88 26.053 20.952 26.819 ;
     RECT  23.376 26.387 24.456 26.819 ;
     RECT  43.584 25.717 44.136 26.869 ;
     RECT  45.216 22.451 45.912 26.869 ;
     RECT  39.936 26.341 42.456 27.059 ;
     RECT  18.6 24.899 19.032 27.061 ;
     RECT  26.448 24.709 26.472 27.109 ;
     RECT  27.456 26.677 27.816 27.109 ;
     RECT  26.448 27.109 27.816 27.155 ;
     RECT  34.032 26.291 35.256 27.203 ;
     RECT  26.736 27.155 27.816 27.299 ;
     RECT  29.232 25.523 29.712 27.299 ;
     RECT  41.568 27.059 42.456 27.349 ;
     RECT  43.584 26.869 45.912 27.349 ;
     RECT  39.936 27.059 40.512 27.491 ;
     RECT  46.992 24.949 65.064 27.587 ;
     RECT  24 26.819 24.456 27.589 ;
     RECT  27.792 27.299 27.816 27.635 ;
     RECT  2.4 25.715 2.712 27.733 ;
     RECT  3.888 26.819 10.68 27.733 ;
     RECT  36.288 26.291 36.312 27.829 ;
     RECT  24 27.589 24.504 27.877 ;
     RECT  23.76 27.877 24.504 27.971 ;
     RECT  40.032 27.491 40.512 28.211 ;
     RECT  29.4 27.299 29.712 28.405 ;
     RECT  36.288 27.829 36.696 28.451 ;
     RECT  26.736 27.299 26.76 28.453 ;
     RECT  29.184 28.405 29.712 28.453 ;
     RECT  20.928 26.819 20.952 28.501 ;
     RECT  26.736 28.453 27.384 28.739 ;
     RECT  32.448 27.877 32.472 28.981 ;
     RECT  32.112 28.981 32.472 29.027 ;
     RECT  18.6 27.061 19.608 29.075 ;
     RECT  0.144 27.685 0.168 29.411 ;
     RECT  27.36 28.739 27.384 29.459 ;
     RECT  41.568 27.349 45.912 29.509 ;
     RECT  22.752 29.557 22.776 29.605 ;
     RECT  23.76 27.971 24.456 29.605 ;
     RECT  36.288 28.451 36.312 29.653 ;
     RECT  20.928 28.501 21.576 29.747 ;
     RECT  32.112 29.027 32.136 29.747 ;
     RECT  40.2 28.211 40.512 29.797 ;
     RECT  2.4 27.733 10.68 30.275 ;
     RECT  36.288 29.653 37.032 30.371 ;
     RECT  4.512 30.275 10.68 30.421 ;
     RECT  11.712 26.819 14.52 30.421 ;
     RECT  38.064 26.291 38.088 30.469 ;
     RECT  29.184 28.453 30.456 30.563 ;
     RECT  20.928 29.747 20.952 30.611 ;
     RECT  39.936 29.797 40.512 30.707 ;
     RECT  40.08 30.707 40.512 30.803 ;
     RECT  41.52 29.509 45.912 30.803 ;
     RECT  15.696 26.725 16.488 30.899 ;
     RECT  18.6 29.075 19.416 30.899 ;
     RECT  43.584 30.803 45.912 31.091 ;
     RECT  22.752 29.605 24.456 31.333 ;
     RECT  2.4 30.275 2.856 31.379 ;
     RECT  38.064 30.469 38.28 31.379 ;
     RECT  22.656 31.333 24.456 31.381 ;
     RECT  4.512 30.421 14.52 31.525 ;
     RECT  22.656 31.381 25.272 31.667 ;
     RECT  45.216 31.091 45.912 31.763 ;
     RECT  18.6 30.899 18.912 31.813 ;
     RECT  0.144 31.333 0.168 31.955 ;
     RECT  36.288 30.371 36.312 31.955 ;
     RECT  27.888 30.229 27.912 32.149 ;
     RECT  29.184 30.563 29.712 32.149 ;
     RECT  27.888 32.149 29.712 32.195 ;
     RECT  41.52 30.803 42.456 32.245 ;
     RECT  43.584 31.091 44.088 32.245 ;
     RECT  30.816 31.237 30.84 32.339 ;
     RECT  2.4 31.379 2.808 32.437 ;
     RECT  3.936 31.525 14.52 32.437 ;
     RECT  41.52 32.245 44.088 33.061 ;
     RECT  52.368 27.587 65.064 33.107 ;
     RECT  28.272 32.195 29.712 33.541 ;
     RECT  20.112 33.541 20.136 33.589 ;
     RECT  45.6 31.763 45.912 33.781 ;
     RECT  46.992 27.587 51.312 33.781 ;
     RECT  21.648 31.909 21.672 33.827 ;
     RECT  45.6 33.781 51.312 33.829 ;
     RECT  41.52 33.061 44.184 33.923 ;
     RECT  23.424 31.667 25.272 34.069 ;
     RECT  43.152 33.923 44.184 34.115 ;
     RECT  2.4 32.437 14.52 34.163 ;
     RECT  44.16 34.115 44.184 34.405 ;
     RECT  45.6 33.829 51.432 34.405 ;
     RECT  18.192 31.813 18.912 34.595 ;
     RECT  31.872 34.117 31.896 34.597 ;
     RECT  20.112 33.589 20.28 34.643 ;
     RECT  39.072 34.117 39.096 34.645 ;
     RECT  40.2 30.803 40.512 34.645 ;
     RECT  28.224 33.541 29.712 34.835 ;
     RECT  39.072 34.645 40.512 34.835 ;
     RECT  23.232 34.069 25.272 34.883 ;
     RECT  23.232 34.883 25.224 34.885 ;
     RECT  31.008 34.597 31.896 34.931 ;
     RECT  22.8 34.885 25.224 35.027 ;
     RECT  44.16 34.405 51.432 35.123 ;
     RECT  2.4 34.163 10.68 35.363 ;
     RECT  0.144 34.741 0.168 35.605 ;
     RECT  31.008 34.931 31.032 35.699 ;
     RECT  38.064 31.379 38.088 35.747 ;
     RECT  15.696 30.899 16.248 35.797 ;
     RECT  0.144 35.605 0.264 35.843 ;
     RECT  40.032 34.835 40.512 35.845 ;
     RECT  41.52 33.923 41.832 35.845 ;
     RECT  45.6 35.123 51.432 35.891 ;
     RECT  36.72 34.117 36.744 35.939 ;
     RECT  32.928 35.605 32.952 35.987 ;
     RECT  40.032 35.845 41.832 35.987 ;
     RECT  23.424 35.027 25.224 36.227 ;
     RECT  3.744 35.363 10.68 36.229 ;
     RECT  11.712 34.163 14.52 36.229 ;
     RECT  45.6 35.891 51.312 36.373 ;
     RECT  18.6 34.595 18.912 36.469 ;
     RECT  20.256 34.643 20.28 36.469 ;
     RECT  0.24 35.843 0.264 36.515 ;
     RECT  3.744 36.229 14.52 36.515 ;
     RECT  15.504 35.797 16.248 36.517 ;
     RECT  2.4 35.363 2.712 36.661 ;
     RECT  29.04 34.835 29.712 36.755 ;
     RECT  43.152 34.115 43.176 36.757 ;
     RECT  44.16 35.123 44.184 36.757 ;
     RECT  24 36.227 25.224 36.803 ;
     RECT  15.504 36.517 16.344 37.187 ;
     RECT  17.472 36.469 17.496 37.187 ;
     RECT  37.92 36.901 37.944 37.189 ;
     RECT  37.008 37.189 37.944 37.331 ;
     RECT  40.032 35.987 40.512 37.477 ;
     RECT  45.456 36.373 51.312 37.571 ;
     RECT  48.672 37.571 51.312 37.619 ;
     RECT  41.52 35.987 41.832 37.621 ;
     RECT  2.4 36.661 2.856 37.667 ;
     RECT  18.6 36.469 20.28 37.667 ;
     RECT  37.92 37.331 37.944 37.667 ;
     RECT  43.152 36.757 44.184 37.859 ;
     RECT  17.52 37.573 17.544 38.101 ;
     RECT  18.6 37.667 18.912 38.101 ;
     RECT  17.52 38.101 18.912 38.147 ;
     RECT  41.52 37.621 42.168 38.197 ;
     RECT  43.152 37.859 43.896 38.197 ;
     RECT  3.888 36.515 14.52 38.243 ;
     RECT  45.456 37.571 47.208 38.293 ;
     RECT  41.52 38.197 43.896 38.339 ;
     RECT  48.768 37.619 51.312 38.675 ;
     RECT  11.712 38.243 14.52 38.677 ;
     RECT  15.504 37.187 16.248 38.677 ;
     RECT  11.712 38.677 16.248 38.771 ;
     RECT  36.432 37.573 36.456 38.771 ;
     RECT  41.52 38.339 42.168 38.771 ;
     RECT  44.928 38.293 47.208 38.771 ;
     RECT  48.768 38.675 49.128 38.819 ;
     RECT  43.152 38.339 43.896 38.867 ;
     RECT  3.936 38.243 10.68 39.205 ;
     RECT  11.712 38.771 14.856 39.205 ;
     RECT  34.8 27.203 35.256 39.301 ;
     RECT  18.192 38.147 18.912 39.395 ;
     RECT  43.152 38.867 43.416 39.443 ;
     RECT  48.864 38.819 49.128 39.443 ;
     RECT  34.8 39.301 35.832 39.827 ;
     RECT  15.84 38.771 16.248 39.829 ;
     RECT  24 36.803 24.456 39.925 ;
     RECT  18.6 39.395 18.912 39.973 ;
     RECT  20.256 37.667 20.28 39.973 ;
     RECT  45.36 38.771 47.208 40.021 ;
     RECT  29.184 36.755 29.712 40.069 ;
     RECT  2.4 37.667 2.712 40.165 ;
     RECT  3.936 39.205 14.856 40.165 ;
     RECT  23.808 39.925 24.456 40.165 ;
     RECT  29.184 40.069 29.832 40.211 ;
     RECT  26.784 39.973 26.808 40.307 ;
     RECT  22.944 40.165 24.792 40.309 ;
     RECT  39.504 37.477 40.512 40.309 ;
     RECT  41.52 38.771 41.544 40.309 ;
     RECT  39.504 40.309 41.544 40.451 ;
     RECT  50.496 38.675 51.312 40.547 ;
     RECT  49.104 39.443 49.128 40.549 ;
     RECT  15.84 39.829 17.112 40.739 ;
     RECT  44.448 40.021 47.208 40.835 ;
     RECT  0.144 40.837 0.168 40.979 ;
     RECT  18.6 39.973 20.28 41.027 ;
     RECT  22.896 40.309 24.792 41.075 ;
     RECT  49.104 40.549 49.224 41.123 ;
     RECT  15.84 40.739 16.776 41.171 ;
     RECT  19.968 41.027 20.28 41.315 ;
     RECT  41.52 40.451 41.544 41.413 ;
     RECT  34.8 39.827 35.256 41.461 ;
     RECT  50.736 40.547 51.312 41.509 ;
     RECT  52.416 33.107 65.064 41.509 ;
     RECT  37.68 40.885 37.704 41.603 ;
     RECT  22.896 41.075 24.456 41.651 ;
     RECT  2.4 40.165 14.856 41.699 ;
     RECT  41.52 41.413 41.64 41.939 ;
     RECT  37.872 42.085 37.896 42.133 ;
     RECT  39.504 40.451 40.512 42.133 ;
     RECT  44.448 40.835 46.584 42.179 ;
     RECT  36.384 41.557 36.408 42.467 ;
     RECT  15.84 41.171 16.584 42.469 ;
     RECT  4.032 41.699 14.856 42.565 ;
     RECT  15.84 42.469 16.92 42.565 ;
     RECT  2.4 41.699 2.712 42.709 ;
     RECT  4.032 42.565 16.92 42.709 ;
     RECT  26.592 41.557 26.616 42.755 ;
     RECT  23.856 41.651 24.456 42.803 ;
     RECT  2.4 42.709 16.92 42.947 ;
     RECT  12.288 42.947 16.92 43.045 ;
     RECT  45.36 42.179 46.584 43.141 ;
     RECT  12.288 43.045 17.304 43.235 ;
     RECT  34.8 41.461 35.352 43.235 ;
     RECT  26.208 42.997 26.232 43.331 ;
     RECT  37.872 42.133 40.512 43.379 ;
     RECT  41.616 41.939 41.64 43.379 ;
     RECT  49.104 41.123 49.128 43.861 ;
     RECT  2.4 42.947 11.304 43.955 ;
     RECT  49.104 43.861 49.56 43.957 ;
     RECT  50.736 41.509 65.064 43.957 ;
     RECT  12.288 43.235 16.92 44.051 ;
     RECT  20.256 41.315 20.28 44.149 ;
     RECT  21.552 42.133 21.576 44.149 ;
     RECT  43.152 39.443 43.176 44.341 ;
     RECT  18.6 41.027 18.912 44.389 ;
     RECT  12.288 44.051 16.248 44.965 ;
     RECT  43.152 44.341 43.704 45.059 ;
     RECT  45.216 43.141 46.584 45.061 ;
     RECT  45.216 45.061 47.4 45.157 ;
     RECT  2.4 43.955 10.728 45.493 ;
     RECT  18.48 44.389 18.912 45.541 ;
     RECT  20.256 44.149 21.576 45.541 ;
     RECT  32.736 43.285 32.76 45.635 ;
     RECT  37.872 43.379 38.232 45.635 ;
     RECT  41.904 44.629 41.928 45.635 ;
     RECT  34.8 43.235 35.256 45.637 ;
     RECT  37.872 45.635 37.896 45.637 ;
     RECT  49.104 43.957 65.064 45.731 ;
     RECT  2.4 45.493 10.92 45.973 ;
     RECT  12 44.965 16.248 45.973 ;
     RECT  45.072 45.157 47.4 46.117 ;
     RECT  26.112 45.541 26.136 46.259 ;
     RECT  18.48 45.541 21.576 46.307 ;
     RECT  31.584 45.589 31.608 46.405 ;
     RECT  37.584 45.637 37.896 46.499 ;
     RECT  18.48 46.307 20.28 46.501 ;
     RECT  24 42.803 24.456 46.501 ;
     RECT  17.328 46.501 20.28 46.643 ;
     RECT  24 46.501 25.128 46.645 ;
     RECT  21.552 46.307 21.576 46.691 ;
     RECT  49.536 45.731 65.064 46.691 ;
     RECT  27.6 46.165 27.624 46.787 ;
     RECT  44.304 46.117 47.4 46.787 ;
     RECT  43.152 45.059 43.176 46.835 ;
     RECT  34.8 45.637 35.928 46.883 ;
     RECT  31.584 46.405 31.896 47.075 ;
     RECT  23.616 46.645 25.128 47.315 ;
     RECT  37.632 46.499 37.896 47.363 ;
     RECT  41.856 46.021 41.88 47.363 ;
     RECT  45.216 46.787 47.4 47.363 ;
     RECT  2.4 45.973 16.248 47.411 ;
     RECT  50.208 46.691 65.064 47.411 ;
     RECT  18.192 46.643 20.28 47.797 ;
     RECT  34.8 46.883 35.256 47.845 ;
     RECT  50.496 47.411 65.064 47.939 ;
     RECT  18.192 47.797 21.672 48.035 ;
     RECT  34.8 47.845 35.928 48.467 ;
     RECT  23.616 47.315 24.456 48.757 ;
     RECT  31.872 47.075 31.896 48.805 ;
     RECT  45.216 47.363 46.728 48.853 ;
     RECT  2.4 47.411 11.208 48.997 ;
     RECT  12.288 47.411 16.248 48.997 ;
     RECT  23.616 48.757 25.08 49.043 ;
     RECT  31.248 48.805 31.896 49.043 ;
     RECT  43.296 48.421 43.32 49.091 ;
     RECT  18.192 48.035 20.28 49.093 ;
     RECT  21.648 48.035 21.672 49.093 ;
     RECT  18.192 49.093 21.672 49.139 ;
     RECT  18.192 49.139 21.144 49.477 ;
     RECT  23.616 49.043 24.456 49.477 ;
     RECT  17.76 49.477 21.144 49.525 ;
     RECT  2.4 48.997 16.248 49.571 ;
     RECT  31.584 49.043 31.896 49.619 ;
     RECT  33.504 48.949 33.528 49.763 ;
     RECT  17.376 49.525 21.144 49.811 ;
     RECT  12.288 49.571 16.248 49.861 ;
     RECT  17.376 49.811 20.28 49.861 ;
     RECT  50.496 47.939 64.056 49.907 ;
     RECT  44.4 48.853 46.728 50.051 ;
     RECT  23.04 49.477 24.456 50.101 ;
     RECT  31.584 49.619 31.704 50.147 ;
     RECT  52.368 49.907 64.056 50.195 ;
     RECT  12.288 49.861 20.28 50.291 ;
     RECT  27.744 47.797 27.768 50.291 ;
     RECT  15.696 50.291 20.28 50.579 ;
     RECT  22.464 50.101 24.456 50.579 ;
     RECT  25.92 49.525 25.944 50.771 ;
     RECT  27.696 50.629 27.72 50.771 ;
     RECT  15.696 50.579 16.68 50.867 ;
     RECT  44.4 50.051 46.584 50.915 ;
     RECT  37.872 47.363 37.896 50.965 ;
     RECT  52.368 50.195 63.144 51.059 ;
     RECT  2.4 49.571 10.68 51.107 ;
     RECT  29.184 40.211 29.712 51.109 ;
     RECT  3.888 51.107 10.68 51.395 ;
     RECT  17.76 50.579 20.28 51.493 ;
     RECT  44.4 50.915 44.424 51.589 ;
     RECT  44.256 51.589 44.424 51.635 ;
     RECT  45.6 50.915 46.584 51.733 ;
     RECT  25.968 51.109 25.992 51.779 ;
     RECT  37.872 50.965 38.184 51.779 ;
     RECT  50.496 49.907 51.312 51.829 ;
     RECT  12.288 50.291 14.616 51.875 ;
     RECT  29.184 51.109 29.928 51.923 ;
     RECT  31.68 50.147 31.704 51.923 ;
     RECT  49.824 51.829 51.312 51.971 ;
     RECT  12.288 51.875 14.52 52.019 ;
     RECT  17.76 51.493 20.616 52.019 ;
     RECT  15.84 50.867 16.68 52.069 ;
     RECT  54.576 51.059 63.144 52.163 ;
     RECT  18.6 52.019 20.616 52.165 ;
     RECT  45.6 51.733 46.68 52.165 ;
     RECT  15.84 52.069 17.16 52.211 ;
     RECT  18.6 52.165 20.664 52.307 ;
     RECT  2.4 51.107 2.808 52.405 ;
     RECT  3.888 51.395 10.632 52.405 ;
     RECT  65.04 47.939 65.064 52.451 ;
     RECT  23.904 50.579 24.456 52.453 ;
     RECT  27.36 51.829 27.384 52.499 ;
     RECT  22.464 50.579 22.488 52.549 ;
     RECT  23.904 52.453 25.32 52.549 ;
     RECT  18.6 52.307 20.616 52.595 ;
     RECT  54.576 52.163 62.856 52.691 ;
     RECT  15.84 52.211 17.064 52.835 ;
     RECT  34.8 48.467 35.256 52.981 ;
     RECT  49.968 51.971 51.312 53.029 ;
     RECT  52.368 51.059 53.4 53.029 ;
     RECT  49.968 53.029 53.4 53.171 ;
     RECT  34.8 52.981 36.168 53.221 ;
     RECT  49.968 53.171 51.312 53.267 ;
     RECT  29.184 51.923 29.712 53.317 ;
     RECT  22.464 52.549 25.32 53.363 ;
     RECT  59.904 52.691 62.856 53.507 ;
     RECT  23.904 53.363 25.32 53.555 ;
     RECT  44.256 51.635 44.28 53.557 ;
     RECT  15.84 52.835 17.016 53.603 ;
     RECT  47.904 51.349 47.928 53.699 ;
     RECT  45.6 52.165 46.728 53.795 ;
     RECT  43.536 53.557 44.28 53.843 ;
     RECT  45.6 53.795 46.68 53.893 ;
     RECT  12.624 52.019 14.52 53.941 ;
     RECT  34.368 53.221 36.168 53.941 ;
     RECT  34.368 53.941 36.456 53.987 ;
     RECT  59.952 53.507 62.856 54.035 ;
     RECT  0.288 53.365 0.312 54.085 ;
     RECT  34.368 53.987 35.256 54.131 ;
     RECT  43.536 53.843 43.992 54.131 ;
     RECT  37.872 51.779 37.896 54.179 ;
     RECT  50.064 53.267 51.312 54.179 ;
     RECT  54.576 52.691 58.872 54.275 ;
     RECT  30.72 52.789 30.744 54.325 ;
     RECT  32.016 53.941 32.04 54.325 ;
     RECT  28.224 53.317 29.712 54.371 ;
     RECT  15.84 53.603 16.728 54.373 ;
     RECT  22.464 53.363 22.824 54.373 ;
     RECT  23.904 53.555 24.456 54.373 ;
     RECT  15.696 54.373 16.728 54.419 ;
     RECT  52.368 53.171 53.4 54.421 ;
     RECT  0.192 54.085 0.312 54.467 ;
     RECT  45.072 53.893 46.68 54.515 ;
     RECT  52.368 54.421 53.496 54.563 ;
     RECT  54.816 54.275 58.872 54.563 ;
     RECT  63.888 53.749 63.912 54.755 ;
     RECT  59.952 54.035 62.712 55.189 ;
     RECT  18.6 52.595 20.28 55.237 ;
     RECT  36.432 53.987 36.456 55.237 ;
     RECT  36.432 55.237 36.552 55.283 ;
     RECT  50.496 54.179 51.312 55.381 ;
     RECT  48.096 54.469 48.12 55.427 ;
     RECT  0.144 54.613 0.168 55.475 ;
     RECT  54.864 54.563 58.872 55.619 ;
     RECT  2.4 52.405 10.632 55.621 ;
     RECT  43.968 54.131 43.992 55.667 ;
     RECT  54.864 55.619 58.296 55.669 ;
     RECT  18.6 55.237 20.328 55.813 ;
     RECT  54.72 55.669 58.296 55.955 ;
     RECT  12.624 53.941 14.664 55.957 ;
     RECT  15.696 54.419 16.248 55.957 ;
     RECT  29.184 54.371 29.712 56.053 ;
     RECT  30.72 54.325 32.04 56.053 ;
     RECT  2.4 55.621 11.4 56.483 ;
     RECT  29.184 56.053 32.04 56.483 ;
     RECT  54.72 55.955 57.912 56.531 ;
     RECT  56.4 56.531 57.912 56.723 ;
     RECT  43.056 55.669 43.08 56.771 ;
     RECT  3.888 56.483 11.4 56.819 ;
     RECT  18.24 55.813 20.328 56.819 ;
     RECT  22.464 54.373 24.456 56.869 ;
     RECT  52.368 54.563 53.352 56.917 ;
     RECT  59.952 55.189 63.144 56.917 ;
     RECT  64.176 55.813 64.2 56.917 ;
     RECT  3.936 56.819 11.4 56.965 ;
     RECT  3.936 56.965 11.448 57.059 ;
     RECT  12.624 55.957 16.248 57.059 ;
     RECT  22.464 56.869 25.176 57.059 ;
     RECT  52.368 56.917 53.688 57.061 ;
     RECT  54.72 56.531 54.888 57.061 ;
     RECT  49.584 55.381 51.312 57.107 ;
     RECT  18.432 56.819 20.328 57.299 ;
     RECT  52.368 57.061 54.888 57.395 ;
     RECT  18.6 57.299 20.328 57.541 ;
     RECT  21.408 56.533 21.432 57.541 ;
     RECT  38.352 55.813 38.376 57.541 ;
     RECT  18.6 57.541 21.432 57.587 ;
     RECT  29.184 56.483 31.416 57.635 ;
     RECT  15.696 57.059 16.248 57.683 ;
     RECT  42.864 57.349 42.888 57.731 ;
     RECT  23.76 57.059 25.176 57.779 ;
     RECT  36.528 55.283 36.552 57.875 ;
     RECT  34.8 54.131 35.256 57.877 ;
     RECT  39.504 43.379 40.512 57.877 ;
     RECT  2.4 56.483 2.712 58.021 ;
     RECT  4.272 57.059 11.448 58.021 ;
     RECT  38.064 57.541 38.376 58.021 ;
     RECT  39.504 57.877 40.968 58.021 ;
     RECT  56.4 56.723 57.768 58.115 ;
     RECT  18.6 57.587 21.144 58.163 ;
     RECT  38.064 58.021 40.968 58.163 ;
     RECT  54.864 57.395 54.888 58.163 ;
     RECT  59.952 56.917 64.2 58.163 ;
     RECT  57.744 58.115 57.768 58.355 ;
     RECT  30.72 57.635 30.744 58.643 ;
     RECT  2.4 58.021 11.448 58.645 ;
     RECT  12.624 57.059 14.52 58.645 ;
     RECT  34.464 57.877 35.256 58.645 ;
     RECT  45.6 54.515 46.68 58.645 ;
     RECT  29.184 57.635 29.712 58.693 ;
     RECT  32.544 58.693 32.568 58.883 ;
     RECT  38.064 58.163 38.088 59.171 ;
     RECT  2.4 58.645 14.52 59.267 ;
     RECT  50.352 57.107 51.312 59.267 ;
     RECT  34.272 58.645 35.256 59.269 ;
     RECT  44.64 58.645 46.68 59.315 ;
     RECT  34.272 59.269 35.352 59.555 ;
     RECT  17.232 59.221 17.256 59.891 ;
     RECT  18.6 58.163 20.328 59.891 ;
     RECT  11.664 59.267 14.52 59.987 ;
     RECT  26.16 58.117 26.184 59.987 ;
     RECT  52.368 57.395 53.688 60.083 ;
     RECT  39.504 58.163 40.968 60.085 ;
     RECT  56.4 58.115 56.712 60.373 ;
     RECT  15.84 57.683 16.248 60.467 ;
     RECT  23.76 57.779 24.456 60.467 ;
     RECT  34.272 59.555 35.112 60.803 ;
     RECT  59.952 58.163 63.768 60.805 ;
     RECT  32.16 59.029 32.184 60.853 ;
     RECT  44.208 60.181 44.232 60.853 ;
     RECT  45.6 59.315 46.68 60.853 ;
     RECT  59.952 60.805 63.864 60.949 ;
     RECT  12.624 59.987 14.52 60.997 ;
     RECT  37.008 60.229 37.032 61.043 ;
     RECT  22.464 57.059 22.488 61.045 ;
     RECT  48.288 59.797 48.312 61.091 ;
     RECT  59.52 60.949 63.864 61.141 ;
     RECT  59.232 61.141 63.864 61.379 ;
     RECT  15.84 60.467 16.2 61.525 ;
     RECT  22.464 61.045 22.776 61.525 ;
     RECT  24 60.467 24.456 61.525 ;
     RECT  44.208 60.853 46.68 61.907 ;
     RECT  52.368 60.083 53.352 62.005 ;
     RECT  15.552 61.525 17.16 62.195 ;
     RECT  39.504 60.085 41.016 62.195 ;
     RECT  55.872 60.373 56.712 62.195 ;
     RECT  22.464 61.525 24.456 62.723 ;
     RECT  52.368 62.005 54.216 62.723 ;
     RECT  2.4 59.267 10.632 62.867 ;
     RECT  29.184 58.693 30.696 62.869 ;
     RECT  25.968 61.189 25.992 62.915 ;
     RECT  23.904 62.723 24.456 63.061 ;
     RECT  2.4 62.867 9.72 63.203 ;
     RECT  23.904 63.061 24.984 63.203 ;
     RECT  36.816 61.573 36.84 63.203 ;
     RECT  22.464 62.723 22.776 63.205 ;
     RECT  28.992 62.869 30.696 63.205 ;
     RECT  39.504 62.195 40.92 63.205 ;
     RECT  32.16 60.853 32.664 63.251 ;
     RECT  18.6 59.891 19.848 63.253 ;
     RECT  28.416 63.205 30.696 63.347 ;
     RECT  12 60.997 14.52 63.397 ;
     RECT  15.552 62.195 16.2 63.491 ;
     RECT  59.232 61.379 63.816 63.541 ;
     RECT  12 63.397 14.568 63.781 ;
     RECT  56.4 62.195 56.712 63.781 ;
     RECT  34.8 60.803 35.112 63.829 ;
     RECT  23.904 63.203 24.456 63.971 ;
     RECT  54.672 63.205 54.696 64.067 ;
     RECT  11.664 63.781 14.568 64.069 ;
     RECT  18.6 63.253 19.896 64.307 ;
     RECT  28.992 63.347 30.696 64.357 ;
     RECT  28.944 64.357 30.696 64.451 ;
     RECT  56.4 63.781 57 64.451 ;
     RECT  58.416 63.541 63.816 64.451 ;
     RECT  33.024 63.781 33.048 64.595 ;
     RECT  44.352 61.907 46.68 64.595 ;
     RECT  10.752 64.069 14.568 64.691 ;
     RECT  22.032 63.205 22.776 64.835 ;
     RECT  18.6 64.307 19.848 64.885 ;
     RECT  34.704 63.829 35.112 64.933 ;
     RECT  52.368 62.723 53.352 64.933 ;
     RECT  34.704 64.933 35.208 64.979 ;
     RECT  36.528 64.405 36.552 64.979 ;
     RECT  17.712 64.885 19.848 65.027 ;
     RECT  25.68 64.741 25.704 65.029 ;
     RECT  58.656 64.451 63.816 65.075 ;
     RECT  39.504 63.205 40.968 65.125 ;
     RECT  28.944 64.451 30.072 65.171 ;
     RECT  59.232 65.075 63.816 65.171 ;
     RECT  15.84 63.491 16.2 65.173 ;
     RECT  18.6 65.027 19.848 65.509 ;
     RECT  28.992 65.171 30.072 65.509 ;
     RECT  2.4 63.203 9.624 65.603 ;
     RECT  44.544 64.595 46.68 65.603 ;
     RECT  25.68 65.029 25.896 65.605 ;
     RECT  25.68 65.605 26.136 65.651 ;
     RECT  25.872 65.651 26.136 65.747 ;
     RECT  15.84 65.173 16.824 66.037 ;
     RECT  22.416 64.835 22.776 66.085 ;
     RECT  28.992 65.509 30.408 66.323 ;
     RECT  21.696 66.085 22.776 66.371 ;
     RECT  55.152 65.509 55.176 66.419 ;
     RECT  59.232 65.171 63.768 66.419 ;
     RECT  29.088 66.323 30.408 66.467 ;
     RECT  39.504 65.125 41.016 66.469 ;
     RECT  39.504 66.469 41.784 66.515 ;
     RECT  59.52 66.419 63.768 66.709 ;
     RECT  2.4 65.603 2.808 66.755 ;
     RECT  10.752 64.691 14.52 66.755 ;
     RECT  26.112 65.747 26.136 66.755 ;
     RECT  29.088 66.467 30.072 66.755 ;
     RECT  18.6 65.509 20.04 66.803 ;
     RECT  34.8 64.979 35.208 66.899 ;
     RECT  15.84 66.037 17.064 67.091 ;
     RECT  29.088 66.755 30.024 67.091 ;
     RECT  15.84 67.091 16.824 67.141 ;
     RECT  59.52 66.709 64.152 67.283 ;
     RECT  3.888 65.603 9.624 67.331 ;
     RECT  27.888 66.709 27.912 67.523 ;
     RECT  44.688 65.603 46.68 67.573 ;
     RECT  24 63.971 24.456 67.621 ;
     RECT  34.8 66.899 35.112 67.669 ;
     RECT  44.688 67.573 46.92 67.669 ;
     RECT  29.184 67.091 30.024 67.715 ;
     RECT  52.368 64.933 53.688 67.715 ;
     RECT  4.032 67.331 9.624 67.717 ;
     RECT  11.088 66.755 14.52 67.717 ;
     RECT  59.616 67.283 64.152 67.717 ;
     RECT  41.76 66.515 41.784 67.765 ;
     RECT  50.496 59.267 51.312 67.765 ;
     RECT  4.032 67.717 14.52 67.811 ;
     RECT  22.464 66.371 22.776 67.811 ;
     RECT  24 67.621 24.504 67.811 ;
     RECT  15.6 67.141 16.824 67.859 ;
     RECT  44.448 67.669 46.92 67.859 ;
     RECT  52.368 67.715 52.392 67.955 ;
     RECT  18.6 66.803 19.848 68.341 ;
     RECT  58.176 68.005 58.2 68.341 ;
     RECT  59.616 67.717 65.112 68.341 ;
     RECT  41.616 67.765 41.784 68.435 ;
     RECT  39.504 66.515 40.512 68.629 ;
     RECT  34.368 67.669 35.112 68.675 ;
     RECT  58.176 68.341 65.112 68.773 ;
     RECT  53.664 67.715 53.688 68.869 ;
     RECT  24 67.811 24.456 68.917 ;
     RECT  53.664 68.869 53.832 68.917 ;
     RECT  56.4 64.451 56.712 68.917 ;
     RECT  15.6 67.859 16.2 68.963 ;
     RECT  26.784 68.341 26.808 68.963 ;
     RECT  2.4 66.755 2.712 68.965 ;
     RECT  4.128 67.811 14.52 68.965 ;
     RECT  44.448 67.859 44.472 69.011 ;
     RECT  58.032 68.773 65.112 69.011 ;
     RECT  22.464 67.811 22.488 69.107 ;
     RECT  38.736 68.629 40.512 69.107 ;
     RECT  33.024 68.341 33.048 69.155 ;
     RECT  48.432 68.821 48.456 69.347 ;
     RECT  15.696 68.963 16.2 69.349 ;
     RECT  18.24 68.341 19.848 69.443 ;
     RECT  23.808 68.917 24.456 69.445 ;
     RECT  59.136 69.011 65.112 69.541 ;
     RECT  23.808 69.445 24.552 69.587 ;
     RECT  53.664 68.917 54.12 69.685 ;
     RECT  30.96 69.109 30.984 69.971 ;
     RECT  1.344 40.069 1.368 70.021 ;
     RECT  2.4 68.965 14.52 70.021 ;
     RECT  25.776 67.093 25.8 70.069 ;
     RECT  53.568 69.685 54.12 70.069 ;
     RECT  58.032 69.011 58.056 70.069 ;
     RECT  59.136 69.541 65.688 70.069 ;
     RECT  15.696 69.349 17.064 70.163 ;
     RECT  21.936 69.493 21.96 70.163 ;
     RECT  49.824 67.765 51.312 70.163 ;
     RECT  56.208 68.917 56.712 70.163 ;
     RECT  25.776 70.069 26.568 70.357 ;
     RECT  45.6 67.859 46.584 70.405 ;
     RECT  53.568 70.069 54.504 70.499 ;
     RECT  52.32 69.541 52.344 70.547 ;
     RECT  58.032 70.069 65.688 70.691 ;
     RECT  24 69.587 24.552 70.741 ;
     RECT  25.728 70.357 26.568 70.741 ;
     RECT  53.808 70.499 54.504 70.835 ;
     RECT  34.8 68.675 35.112 70.885 ;
     RECT  18.6 69.443 19.848 70.933 ;
     RECT  15.696 70.163 16.68 71.123 ;
     RECT  45.6 70.405 46.632 71.315 ;
     RECT  34.416 70.885 35.112 71.651 ;
     RECT  24 70.741 26.568 71.699 ;
     RECT  32.688 70.693 32.712 71.747 ;
     RECT  41.76 68.435 41.784 71.797 ;
     RECT  58.704 70.691 65.688 71.797 ;
     RECT  1.344 70.021 14.52 71.843 ;
     RECT  31.344 70.645 31.368 71.843 ;
     RECT  58.656 71.797 65.688 71.987 ;
     RECT  48.432 71.605 48.456 72.181 ;
     RECT  53.808 70.835 54.456 72.419 ;
     RECT  41.712 71.797 42.264 72.709 ;
     RECT  24 71.699 25.08 72.901 ;
     RECT  66.816 70.117 66.84 72.949 ;
     RECT  47.856 72.181 48.456 72.995 ;
     RECT  56.4 70.163 56.712 72.997 ;
     RECT  15.696 71.123 16.584 73.043 ;
     RECT  26.544 71.699 26.568 73.139 ;
     RECT  58.656 71.987 59.352 73.187 ;
     RECT  48.432 72.995 48.456 73.235 ;
     RECT  1.344 71.843 10.872 73.333 ;
     RECT  0.144 73.237 0.168 73.379 ;
     RECT  56.4 72.997 57.624 73.477 ;
     RECT  58.656 73.187 58.68 73.477 ;
     RECT  60.336 71.987 65.688 73.525 ;
     RECT  66.816 72.949 67.32 73.525 ;
     RECT  60.336 73.525 67.32 73.573 ;
     RECT  45.6 71.315 45.912 73.621 ;
     RECT  15.84 73.043 16.584 73.667 ;
     RECT  29.184 67.715 29.712 73.765 ;
     RECT  23.664 72.901 25.08 73.811 ;
     RECT  41.712 72.709 42.312 73.859 ;
     RECT  53.808 72.419 53.832 73.861 ;
     RECT  53.808 73.861 53.928 73.907 ;
     RECT  23.664 73.811 24.456 74.003 ;
     RECT  41.952 73.859 42.312 74.005 ;
     RECT  49.296 73.765 49.32 74.005 ;
     RECT  50.496 70.163 51.312 74.005 ;
     RECT  36.816 70.645 36.84 74.051 ;
     RECT  21.648 73.477 21.672 74.099 ;
     RECT  18.6 70.933 20.568 74.147 ;
     RECT  56.4 73.477 58.68 74.147 ;
     RECT  45.6 73.621 46.008 74.245 ;
     RECT  53.904 73.907 53.928 74.291 ;
     RECT  1.344 73.333 11.112 74.629 ;
     RECT  12.624 71.843 14.52 74.629 ;
     RECT  1.344 74.629 14.52 74.677 ;
     RECT  15.84 73.667 16.2 74.677 ;
     RECT  29.088 73.765 29.712 74.677 ;
     RECT  39.504 69.107 40.512 74.677 ;
     RECT  39.408 74.677 40.512 74.725 ;
     RECT  45.6 74.245 46.584 74.725 ;
     RECT  52.512 74.677 52.536 74.725 ;
     RECT  39.408 74.725 40.728 74.821 ;
     RECT  41.952 74.005 42.648 74.821 ;
     RECT  55.248 74.677 55.272 74.821 ;
     RECT  52.416 74.725 52.536 74.867 ;
     RECT  18.6 74.147 19.848 74.917 ;
     RECT  54.384 74.821 55.32 74.917 ;
     RECT  56.4 74.147 57.624 74.917 ;
     RECT  34.8 71.651 35.112 74.965 ;
     RECT  39.408 74.821 42.648 75.013 ;
     RECT  1.344 74.677 17.064 75.109 ;
     RECT  32.592 72.901 32.616 75.109 ;
     RECT  34.32 74.965 35.208 75.109 ;
     RECT  26.208 73.957 26.232 75.157 ;
     RECT  28.896 74.677 29.712 75.203 ;
     RECT  28.992 75.203 29.712 75.205 ;
     RECT  39.408 75.013 43.272 75.205 ;
     RECT  1.104 75.109 17.064 75.299 ;
     RECT  26.016 75.157 26.232 75.299 ;
     RECT  54.384 74.917 57.624 75.299 ;
     RECT  39.408 75.205 43.32 75.301 ;
     RECT  24 74.003 24.456 75.493 ;
     RECT  45.408 74.725 46.584 75.589 ;
     RECT  52.512 74.867 52.536 75.731 ;
     RECT  1.104 75.299 15.192 75.827 ;
     RECT  18.192 74.917 19.848 75.829 ;
     RECT  22.56 74.725 22.584 75.829 ;
     RECT  39.408 75.301 43.56 75.829 ;
     RECT  16.176 75.299 17.064 75.875 ;
     RECT  60.336 73.573 67.8 75.923 ;
     RECT  32.592 75.109 35.208 76.309 ;
     RECT  36.384 74.293 36.408 76.309 ;
     RECT  17.04 75.875 17.064 76.357 ;
     RECT  18.192 75.829 20.52 76.357 ;
     RECT  27.648 76.213 27.672 76.357 ;
     RECT  23.904 75.493 24.456 76.405 ;
     RECT  38.928 75.829 43.56 76.453 ;
     RECT  58.656 74.147 58.68 76.453 ;
     RECT  45.408 75.589 46.728 76.501 ;
     RECT  23.904 76.405 24.648 76.549 ;
     RECT  17.04 76.357 20.52 76.645 ;
     RECT  55.536 75.299 57.624 76.693 ;
     RECT  58.656 76.453 58.968 76.693 ;
     RECT  45.408 76.501 47.256 76.741 ;
     RECT  38.928 76.453 43.8 76.885 ;
     RECT  45.408 76.741 47.832 76.931 ;
     RECT  1.104 75.827 13.8 76.933 ;
     RECT  15.168 75.827 15.192 76.933 ;
     RECT  27.648 76.357 27.864 76.933 ;
     RECT  28.992 75.205 30.168 76.933 ;
     RECT  54.384 75.299 54.408 77.221 ;
     RECT  55.536 76.693 58.968 77.221 ;
     RECT  49.296 74.005 51.312 77.461 ;
     RECT  1.104 76.933 15.432 77.509 ;
     RECT  17.04 76.645 21.192 77.509 ;
     RECT  22.32 75.829 22.584 77.509 ;
     RECT  23.712 76.549 24.648 77.509 ;
     RECT  26.016 75.299 26.04 77.509 ;
     RECT  27.648 76.933 30.168 77.509 ;
     RECT  31.536 76.933 31.56 77.509 ;
     RECT  32.592 76.309 36.408 77.509 ;
     RECT  38.688 76.885 43.8 77.509 ;
     RECT  49.056 77.461 51.312 77.509 ;
     RECT  54.384 77.221 58.968 77.509 ;
     RECT  60.528 75.923 67.8 77.845 ;
     RECT  1.104 77.509 36.408 77.941 ;
     RECT  37.536 76.357 37.56 77.941 ;
     RECT  48.864 77.509 51.312 77.989 ;
     RECT  52.32 77.509 53.256 77.989 ;
     RECT  1.104 77.941 37.56 78.037 ;
     RECT  38.688 77.509 44.04 78.037 ;
     RECT  45.408 76.931 47.256 78.037 ;
     RECT  48.624 77.989 53.256 78.037 ;
     RECT  54.384 77.509 59.256 78.037 ;
     RECT  48.384 78.037 59.256 78.085 ;
     RECT  60.384 77.845 67.8 78.085 ;
     RECT  1.104 78.037 47.256 79.189 ;
     RECT  48.384 78.085 67.8 79.189 ;
     RECT  1.104 79.189 67.8 79.765 ;
     RECT  1.104 79.765 68.04 79.888 ;
  END
END qkd_ctrl_pc_port_child
END LIBRARY
